VERSION 5.8 ;
BUSBITCHARS "[]" ;
DIVIDERCHAR "/" ;
UNITS
    DATABASE MICRONS 1000 ;
END UNITS

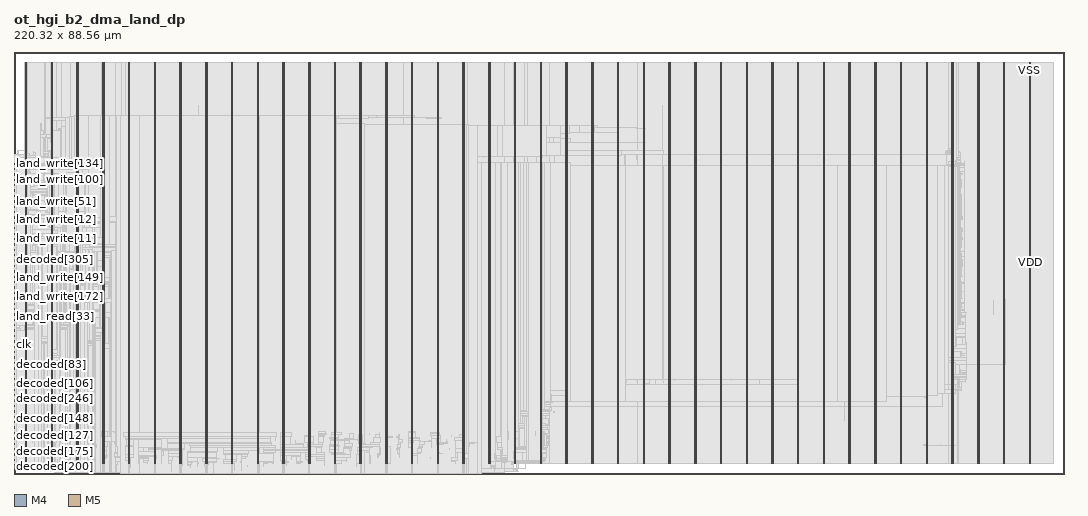
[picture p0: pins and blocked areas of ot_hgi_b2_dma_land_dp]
MACRO ot_hgi_b2_dma_land_dp
  FOREIGN ot_hgi_b2_dma_land_dp 0 0 ;
  CLASS BLOCK ;
  SIZE 220.32 BY 88.56 ;
  PIN clk
    DIRECTION INPUT ;
    USE SIGNAL ;
    PORT
      LAYER M4 ;
        RECT  0 27.216 0.084 27.24 ;
    END
  END clk
  PIN decoded[0]
    DIRECTION OUTPUT ;
    USE SIGNAL ;
    PORT
      LAYER M4 ;
        RECT  0 27.312 0.084 27.336 ;
    END
  END decoded[0]
  PIN decoded[100]
    DIRECTION OUTPUT ;
    USE SIGNAL ;
    PORT
      LAYER M4 ;
        RECT  0 18.48 0.084 18.504 ;
    END
  END decoded[100]
  PIN decoded[101]
    DIRECTION OUTPUT ;
    USE SIGNAL ;
    PORT
      LAYER M4 ;
        RECT  0 18.576 0.084 18.6 ;
    END
  END decoded[101]
  PIN decoded[102]
    DIRECTION OUTPUT ;
    USE SIGNAL ;
    PORT
      LAYER M4 ;
        RECT  0 18.672 0.084 18.696 ;
    END
  END decoded[102]
  PIN decoded[103]
    DIRECTION OUTPUT ;
    USE SIGNAL ;
    PORT
      LAYER M4 ;
        RECT  0 18.768 0.084 18.792 ;
    END
  END decoded[103]
  PIN decoded[104]
    DIRECTION OUTPUT ;
    USE SIGNAL ;
    PORT
      LAYER M4 ;
        RECT  0 18.864 0.084 18.888 ;
    END
  END decoded[104]
  PIN decoded[105]
    DIRECTION OUTPUT ;
    USE SIGNAL ;
    PORT
      LAYER M4 ;
        RECT  0 18.96 0.084 18.984 ;
    END
  END decoded[105]
  PIN decoded[106]
    DIRECTION OUTPUT ;
    USE SIGNAL ;
    PORT
      LAYER M4 ;
        RECT  0 19.056 0.084 19.08 ;
    END
  END decoded[106]
  PIN decoded[107]
    DIRECTION OUTPUT ;
    USE SIGNAL ;
    PORT
      LAYER M4 ;
        RECT  0 19.152 0.084 19.176 ;
    END
  END decoded[107]
  PIN decoded[108]
    DIRECTION OUTPUT ;
    USE SIGNAL ;
    PORT
      LAYER M4 ;
        RECT  0 19.248 0.084 19.272 ;
    END
  END decoded[108]
  PIN decoded[109]
    DIRECTION OUTPUT ;
    USE SIGNAL ;
    PORT
      LAYER M4 ;
        RECT  0 19.344 0.084 19.368 ;
    END
  END decoded[109]
  PIN decoded[10]
    DIRECTION OUTPUT ;
    USE SIGNAL ;
    PORT
      LAYER M4 ;
        RECT  0 28.272 0.084 28.296 ;
    END
  END decoded[10]
  PIN decoded[110]
    DIRECTION OUTPUT ;
    USE SIGNAL ;
    PORT
      LAYER M4 ;
        RECT  0 19.44 0.084 19.464 ;
    END
  END decoded[110]
  PIN decoded[111]
    DIRECTION OUTPUT ;
    USE SIGNAL ;
    PORT
      LAYER M4 ;
        RECT  0 19.536 0.084 19.56 ;
    END
  END decoded[111]
  PIN decoded[112]
    DIRECTION OUTPUT ;
    USE SIGNAL ;
    PORT
      LAYER M4 ;
        RECT  0 19.632 0.084 19.656 ;
    END
  END decoded[112]
  PIN decoded[113]
    DIRECTION OUTPUT ;
    USE SIGNAL ;
    PORT
      LAYER M4 ;
        RECT  0 19.728 0.084 19.752 ;
    END
  END decoded[113]
  PIN decoded[114]
    DIRECTION OUTPUT ;
    USE SIGNAL ;
    PORT
      LAYER M4 ;
        RECT  0 19.824 0.084 19.848 ;
    END
  END decoded[114]
  PIN decoded[115]
    DIRECTION OUTPUT ;
    USE SIGNAL ;
    PORT
      LAYER M4 ;
        RECT  0 19.92 0.084 19.944 ;
    END
  END decoded[115]
  PIN decoded[116]
    DIRECTION OUTPUT ;
    USE SIGNAL ;
    PORT
      LAYER M4 ;
        RECT  0 20.016 0.084 20.04 ;
    END
  END decoded[116]
  PIN decoded[117]
    DIRECTION OUTPUT ;
    USE SIGNAL ;
    PORT
      LAYER M4 ;
        RECT  0 20.112 0.084 20.136 ;
    END
  END decoded[117]
  PIN decoded[118]
    DIRECTION OUTPUT ;
    USE SIGNAL ;
    PORT
      LAYER M4 ;
        RECT  0 20.208 0.084 20.232 ;
    END
  END decoded[118]
  PIN decoded[119]
    DIRECTION OUTPUT ;
    USE SIGNAL ;
    PORT
      LAYER M4 ;
        RECT  0 20.304 0.084 20.328 ;
    END
  END decoded[119]
  PIN decoded[11]
    DIRECTION OUTPUT ;
    USE SIGNAL ;
    PORT
      LAYER M4 ;
        RECT  0 28.368 0.084 28.392 ;
    END
  END decoded[11]
  PIN decoded[120]
    DIRECTION OUTPUT ;
    USE SIGNAL ;
    PORT
      LAYER M4 ;
        RECT  0 20.4 0.084 20.424 ;
    END
  END decoded[120]
  PIN decoded[121]
    DIRECTION OUTPUT ;
    USE SIGNAL ;
    PORT
      LAYER M4 ;
        RECT  0 20.496 0.084 20.52 ;
    END
  END decoded[121]
  PIN decoded[122]
    DIRECTION OUTPUT ;
    USE SIGNAL ;
    PORT
      LAYER M4 ;
        RECT  0 20.592 0.084 20.616 ;
    END
  END decoded[122]
  PIN decoded[123]
    DIRECTION OUTPUT ;
    USE SIGNAL ;
    PORT
      LAYER M4 ;
        RECT  0 20.688 0.084 20.712 ;
    END
  END decoded[123]
  PIN decoded[124]
    DIRECTION OUTPUT ;
    USE SIGNAL ;
    PORT
      LAYER M4 ;
        RECT  0 20.784 0.084 20.808 ;
    END
  END decoded[124]
  PIN decoded[125]
    DIRECTION OUTPUT ;
    USE SIGNAL ;
    PORT
      LAYER M4 ;
        RECT  0 20.88 0.084 20.904 ;
    END
  END decoded[125]
  PIN decoded[126]
    DIRECTION OUTPUT ;
    USE SIGNAL ;
    PORT
      LAYER M4 ;
        RECT  0 20.976 0.084 21 ;
    END
  END decoded[126]
  PIN decoded[127]
    DIRECTION OUTPUT ;
    USE SIGNAL ;
    PORT
      LAYER M4 ;
        RECT  0 8.016 0.084 8.04 ;
    END
  END decoded[127]
  PIN decoded[128]
    DIRECTION OUTPUT ;
    USE SIGNAL ;
    PORT
      LAYER M4 ;
        RECT  0 8.112 0.084 8.136 ;
    END
  END decoded[128]
  PIN decoded[129]
    DIRECTION OUTPUT ;
    USE SIGNAL ;
    PORT
      LAYER M4 ;
        RECT  0 8.208 0.084 8.232 ;
    END
  END decoded[129]
  PIN decoded[12]
    DIRECTION OUTPUT ;
    USE SIGNAL ;
    PORT
      LAYER M4 ;
        RECT  0 28.464 0.084 28.488 ;
    END
  END decoded[12]
  PIN decoded[130]
    DIRECTION OUTPUT ;
    USE SIGNAL ;
    PORT
      LAYER M4 ;
        RECT  0 8.304 0.084 8.328 ;
    END
  END decoded[130]
  PIN decoded[131]
    DIRECTION OUTPUT ;
    USE SIGNAL ;
    PORT
      LAYER M4 ;
        RECT  0 8.4 0.084 8.424 ;
    END
  END decoded[131]
  PIN decoded[132]
    DIRECTION OUTPUT ;
    USE SIGNAL ;
    PORT
      LAYER M4 ;
        RECT  0 8.496 0.084 8.52 ;
    END
  END decoded[132]
  PIN decoded[133]
    DIRECTION OUTPUT ;
    USE SIGNAL ;
    PORT
      LAYER M4 ;
        RECT  0 8.592 0.084 8.616 ;
    END
  END decoded[133]
  PIN decoded[134]
    DIRECTION OUTPUT ;
    USE SIGNAL ;
    PORT
      LAYER M4 ;
        RECT  0 8.688 0.084 8.712 ;
    END
  END decoded[134]
  PIN decoded[135]
    DIRECTION OUTPUT ;
    USE SIGNAL ;
    PORT
      LAYER M4 ;
        RECT  0 8.784 0.084 8.808 ;
    END
  END decoded[135]
  PIN decoded[136]
    DIRECTION OUTPUT ;
    USE SIGNAL ;
    PORT
      LAYER M4 ;
        RECT  0 8.88 0.084 8.904 ;
    END
  END decoded[136]
  PIN decoded[137]
    DIRECTION OUTPUT ;
    USE SIGNAL ;
    PORT
      LAYER M4 ;
        RECT  0 8.976 0.084 9 ;
    END
  END decoded[137]
  PIN decoded[138]
    DIRECTION OUTPUT ;
    USE SIGNAL ;
    PORT
      LAYER M4 ;
        RECT  0 9.072 0.084 9.096 ;
    END
  END decoded[138]
  PIN decoded[139]
    DIRECTION OUTPUT ;
    USE SIGNAL ;
    PORT
      LAYER M4 ;
        RECT  0 9.168 0.084 9.192 ;
    END
  END decoded[139]
  PIN decoded[13]
    DIRECTION OUTPUT ;
    USE SIGNAL ;
    PORT
      LAYER M4 ;
        RECT  0 28.56 0.084 28.584 ;
    END
  END decoded[13]
  PIN decoded[140]
    DIRECTION OUTPUT ;
    USE SIGNAL ;
    PORT
      LAYER M4 ;
        RECT  0 9.264 0.084 9.288 ;
    END
  END decoded[140]
  PIN decoded[141]
    DIRECTION OUTPUT ;
    USE SIGNAL ;
    PORT
      LAYER M4 ;
        RECT  0 9.36 0.084 9.384 ;
    END
  END decoded[141]
  PIN decoded[142]
    DIRECTION OUTPUT ;
    USE SIGNAL ;
    PORT
      LAYER M4 ;
        RECT  0 9.456 0.084 9.48 ;
    END
  END decoded[142]
  PIN decoded[143]
    DIRECTION OUTPUT ;
    USE SIGNAL ;
    PORT
      LAYER M4 ;
        RECT  0 9.552 0.084 9.576 ;
    END
  END decoded[143]
  PIN decoded[144]
    DIRECTION OUTPUT ;
    USE SIGNAL ;
    PORT
      LAYER M4 ;
        RECT  0 9.648 0.084 9.672 ;
    END
  END decoded[144]
  PIN decoded[145]
    DIRECTION OUTPUT ;
    USE SIGNAL ;
    PORT
      LAYER M4 ;
        RECT  0 9.744 0.084 9.768 ;
    END
  END decoded[145]
  PIN decoded[146]
    DIRECTION OUTPUT ;
    USE SIGNAL ;
    PORT
      LAYER M4 ;
        RECT  0 9.84 0.084 9.864 ;
    END
  END decoded[146]
  PIN decoded[147]
    DIRECTION OUTPUT ;
    USE SIGNAL ;
    PORT
      LAYER M4 ;
        RECT  0 9.936 0.084 9.96 ;
    END
  END decoded[147]
  PIN decoded[148]
    DIRECTION OUTPUT ;
    USE SIGNAL ;
    PORT
      LAYER M4 ;
        RECT  0 10.032 0.084 10.056 ;
    END
  END decoded[148]
  PIN decoded[149]
    DIRECTION OUTPUT ;
    USE SIGNAL ;
    PORT
      LAYER M4 ;
        RECT  0 10.128 0.084 10.152 ;
    END
  END decoded[149]
  PIN decoded[14]
    DIRECTION OUTPUT ;
    USE SIGNAL ;
    PORT
      LAYER M4 ;
        RECT  0 28.656 0.084 28.68 ;
    END
  END decoded[14]
  PIN decoded[150]
    DIRECTION OUTPUT ;
    USE SIGNAL ;
    PORT
      LAYER M4 ;
        RECT  0 10.224 0.084 10.248 ;
    END
  END decoded[150]
  PIN decoded[151]
    DIRECTION OUTPUT ;
    USE SIGNAL ;
    PORT
      LAYER M4 ;
        RECT  0 10.32 0.084 10.344 ;
    END
  END decoded[151]
  PIN decoded[152]
    DIRECTION OUTPUT ;
    USE SIGNAL ;
    PORT
      LAYER M4 ;
        RECT  0 10.416 0.084 10.44 ;
    END
  END decoded[152]
  PIN decoded[153]
    DIRECTION OUTPUT ;
    USE SIGNAL ;
    PORT
      LAYER M4 ;
        RECT  0 10.512 0.084 10.536 ;
    END
  END decoded[153]
  PIN decoded[154]
    DIRECTION OUTPUT ;
    USE SIGNAL ;
    PORT
      LAYER M4 ;
        RECT  0 10.608 0.084 10.632 ;
    END
  END decoded[154]
  PIN decoded[155]
    DIRECTION OUTPUT ;
    USE SIGNAL ;
    PORT
      LAYER M4 ;
        RECT  0 10.704 0.084 10.728 ;
    END
  END decoded[155]
  PIN decoded[156]
    DIRECTION OUTPUT ;
    USE SIGNAL ;
    PORT
      LAYER M4 ;
        RECT  0 10.8 0.084 10.824 ;
    END
  END decoded[156]
  PIN decoded[157]
    DIRECTION OUTPUT ;
    USE SIGNAL ;
    PORT
      LAYER M4 ;
        RECT  0 10.896 0.084 10.92 ;
    END
  END decoded[157]
  PIN decoded[158]
    DIRECTION OUTPUT ;
    USE SIGNAL ;
    PORT
      LAYER M4 ;
        RECT  0 10.992 0.084 11.016 ;
    END
  END decoded[158]
  PIN decoded[159]
    DIRECTION OUTPUT ;
    USE SIGNAL ;
    PORT
      LAYER M4 ;
        RECT  0 4.944 0.084 4.968 ;
    END
  END decoded[159]
  PIN decoded[15]
    DIRECTION OUTPUT ;
    USE SIGNAL ;
    PORT
      LAYER M4 ;
        RECT  0 28.752 0.084 28.776 ;
    END
  END decoded[15]
  PIN decoded[160]
    DIRECTION OUTPUT ;
    USE SIGNAL ;
    PORT
      LAYER M4 ;
        RECT  0 5.04 0.084 5.064 ;
    END
  END decoded[160]
  PIN decoded[161]
    DIRECTION OUTPUT ;
    USE SIGNAL ;
    PORT
      LAYER M4 ;
        RECT  0 5.136 0.084 5.16 ;
    END
  END decoded[161]
  PIN decoded[162]
    DIRECTION OUTPUT ;
    USE SIGNAL ;
    PORT
      LAYER M4 ;
        RECT  0 5.232 0.084 5.256 ;
    END
  END decoded[162]
  PIN decoded[163]
    DIRECTION OUTPUT ;
    USE SIGNAL ;
    PORT
      LAYER M4 ;
        RECT  0 5.328 0.084 5.352 ;
    END
  END decoded[163]
  PIN decoded[164]
    DIRECTION OUTPUT ;
    USE SIGNAL ;
    PORT
      LAYER M4 ;
        RECT  0 5.424 0.084 5.448 ;
    END
  END decoded[164]
  PIN decoded[165]
    DIRECTION OUTPUT ;
    USE SIGNAL ;
    PORT
      LAYER M4 ;
        RECT  0 5.52 0.084 5.544 ;
    END
  END decoded[165]
  PIN decoded[166]
    DIRECTION OUTPUT ;
    USE SIGNAL ;
    PORT
      LAYER M4 ;
        RECT  0 5.616 0.084 5.64 ;
    END
  END decoded[166]
  PIN decoded[167]
    DIRECTION OUTPUT ;
    USE SIGNAL ;
    PORT
      LAYER M4 ;
        RECT  0 5.712 0.084 5.736 ;
    END
  END decoded[167]
  PIN decoded[168]
    DIRECTION OUTPUT ;
    USE SIGNAL ;
    PORT
      LAYER M4 ;
        RECT  0 5.808 0.084 5.832 ;
    END
  END decoded[168]
  PIN decoded[169]
    DIRECTION OUTPUT ;
    USE SIGNAL ;
    PORT
      LAYER M4 ;
        RECT  0 5.904 0.084 5.928 ;
    END
  END decoded[169]
  PIN decoded[16]
    DIRECTION OUTPUT ;
    USE SIGNAL ;
    PORT
      LAYER M4 ;
        RECT  0 28.848 0.084 28.872 ;
    END
  END decoded[16]
  PIN decoded[170]
    DIRECTION OUTPUT ;
    USE SIGNAL ;
    PORT
      LAYER M4 ;
        RECT  0 6 0.084 6.024 ;
    END
  END decoded[170]
  PIN decoded[171]
    DIRECTION OUTPUT ;
    USE SIGNAL ;
    PORT
      LAYER M4 ;
        RECT  0 6.096 0.084 6.12 ;
    END
  END decoded[171]
  PIN decoded[172]
    DIRECTION OUTPUT ;
    USE SIGNAL ;
    PORT
      LAYER M4 ;
        RECT  0 6.192 0.084 6.216 ;
    END
  END decoded[172]
  PIN decoded[173]
    DIRECTION OUTPUT ;
    USE SIGNAL ;
    PORT
      LAYER M4 ;
        RECT  0 6.288 0.084 6.312 ;
    END
  END decoded[173]
  PIN decoded[174]
    DIRECTION OUTPUT ;
    USE SIGNAL ;
    PORT
      LAYER M4 ;
        RECT  0 6.384 0.084 6.408 ;
    END
  END decoded[174]
  PIN decoded[175]
    DIRECTION OUTPUT ;
    USE SIGNAL ;
    PORT
      LAYER M4 ;
        RECT  0 6.48 0.084 6.504 ;
    END
  END decoded[175]
  PIN decoded[176]
    DIRECTION OUTPUT ;
    USE SIGNAL ;
    PORT
      LAYER M4 ;
        RECT  0 6.576 0.084 6.6 ;
    END
  END decoded[176]
  PIN decoded[177]
    DIRECTION OUTPUT ;
    USE SIGNAL ;
    PORT
      LAYER M4 ;
        RECT  0 6.672 0.084 6.696 ;
    END
  END decoded[177]
  PIN decoded[178]
    DIRECTION OUTPUT ;
    USE SIGNAL ;
    PORT
      LAYER M4 ;
        RECT  0 6.768 0.084 6.792 ;
    END
  END decoded[178]
  PIN decoded[179]
    DIRECTION OUTPUT ;
    USE SIGNAL ;
    PORT
      LAYER M4 ;
        RECT  0 6.864 0.084 6.888 ;
    END
  END decoded[179]
  PIN decoded[17]
    DIRECTION OUTPUT ;
    USE SIGNAL ;
    PORT
      LAYER M4 ;
        RECT  0 28.944 0.084 28.968 ;
    END
  END decoded[17]
  PIN decoded[180]
    DIRECTION OUTPUT ;
    USE SIGNAL ;
    PORT
      LAYER M4 ;
        RECT  0 6.96 0.084 6.984 ;
    END
  END decoded[180]
  PIN decoded[181]
    DIRECTION OUTPUT ;
    USE SIGNAL ;
    PORT
      LAYER M4 ;
        RECT  0 7.056 0.084 7.08 ;
    END
  END decoded[181]
  PIN decoded[182]
    DIRECTION OUTPUT ;
    USE SIGNAL ;
    PORT
      LAYER M4 ;
        RECT  0 7.152 0.084 7.176 ;
    END
  END decoded[182]
  PIN decoded[183]
    DIRECTION OUTPUT ;
    USE SIGNAL ;
    PORT
      LAYER M4 ;
        RECT  0 7.248 0.084 7.272 ;
    END
  END decoded[183]
  PIN decoded[184]
    DIRECTION OUTPUT ;
    USE SIGNAL ;
    PORT
      LAYER M4 ;
        RECT  0 7.344 0.084 7.368 ;
    END
  END decoded[184]
  PIN decoded[185]
    DIRECTION OUTPUT ;
    USE SIGNAL ;
    PORT
      LAYER M4 ;
        RECT  0 7.44 0.084 7.464 ;
    END
  END decoded[185]
  PIN decoded[186]
    DIRECTION OUTPUT ;
    USE SIGNAL ;
    PORT
      LAYER M4 ;
        RECT  0 7.536 0.084 7.56 ;
    END
  END decoded[186]
  PIN decoded[187]
    DIRECTION OUTPUT ;
    USE SIGNAL ;
    PORT
      LAYER M4 ;
        RECT  0 7.632 0.084 7.656 ;
    END
  END decoded[187]
  PIN decoded[188]
    DIRECTION OUTPUT ;
    USE SIGNAL ;
    PORT
      LAYER M4 ;
        RECT  0 7.728 0.084 7.752 ;
    END
  END decoded[188]
  PIN decoded[189]
    DIRECTION OUTPUT ;
    USE SIGNAL ;
    PORT
      LAYER M4 ;
        RECT  0 7.824 0.084 7.848 ;
    END
  END decoded[189]
  PIN decoded[18]
    DIRECTION OUTPUT ;
    USE SIGNAL ;
    PORT
      LAYER M4 ;
        RECT  0 29.04 0.084 29.064 ;
    END
  END decoded[18]
  PIN decoded[190]
    DIRECTION OUTPUT ;
    USE SIGNAL ;
    PORT
      LAYER M4 ;
        RECT  0 7.92 0.084 7.944 ;
    END
  END decoded[190]
  PIN decoded[191]
    DIRECTION OUTPUT ;
    USE SIGNAL ;
    PORT
      LAYER M4 ;
        RECT  0 1.872 0.084 1.896 ;
    END
  END decoded[191]
  PIN decoded[192]
    DIRECTION OUTPUT ;
    USE SIGNAL ;
    PORT
      LAYER M4 ;
        RECT  0 1.968 0.084 1.992 ;
    END
  END decoded[192]
  PIN decoded[193]
    DIRECTION OUTPUT ;
    USE SIGNAL ;
    PORT
      LAYER M4 ;
        RECT  0 2.064 0.084 2.088 ;
    END
  END decoded[193]
  PIN decoded[194]
    DIRECTION OUTPUT ;
    USE SIGNAL ;
    PORT
      LAYER M4 ;
        RECT  0 2.16 0.084 2.184 ;
    END
  END decoded[194]
  PIN decoded[195]
    DIRECTION OUTPUT ;
    USE SIGNAL ;
    PORT
      LAYER M4 ;
        RECT  0 2.256 0.084 2.28 ;
    END
  END decoded[195]
  PIN decoded[196]
    DIRECTION OUTPUT ;
    USE SIGNAL ;
    PORT
      LAYER M4 ;
        RECT  0 2.352 0.084 2.376 ;
    END
  END decoded[196]
  PIN decoded[197]
    DIRECTION OUTPUT ;
    USE SIGNAL ;
    PORT
      LAYER M4 ;
        RECT  0 2.448 0.084 2.472 ;
    END
  END decoded[197]
  PIN decoded[198]
    DIRECTION OUTPUT ;
    USE SIGNAL ;
    PORT
      LAYER M4 ;
        RECT  0 2.544 0.084 2.568 ;
    END
  END decoded[198]
  PIN decoded[199]
    DIRECTION OUTPUT ;
    USE SIGNAL ;
    PORT
      LAYER M4 ;
        RECT  0 2.64 0.084 2.664 ;
    END
  END decoded[199]
  PIN decoded[19]
    DIRECTION OUTPUT ;
    USE SIGNAL ;
    PORT
      LAYER M4 ;
        RECT  0 29.136 0.084 29.16 ;
    END
  END decoded[19]
  PIN decoded[1]
    DIRECTION OUTPUT ;
    USE SIGNAL ;
    PORT
      LAYER M4 ;
        RECT  0 27.408 0.084 27.432 ;
    END
  END decoded[1]
  PIN decoded[200]
    DIRECTION OUTPUT ;
    USE SIGNAL ;
    PORT
      LAYER M4 ;
        RECT  0 2.736 0.084 2.76 ;
    END
  END decoded[200]
  PIN decoded[201]
    DIRECTION OUTPUT ;
    USE SIGNAL ;
    PORT
      LAYER M4 ;
        RECT  0 2.832 0.084 2.856 ;
    END
  END decoded[201]
  PIN decoded[202]
    DIRECTION OUTPUT ;
    USE SIGNAL ;
    PORT
      LAYER M4 ;
        RECT  0 2.928 0.084 2.952 ;
    END
  END decoded[202]
  PIN decoded[203]
    DIRECTION OUTPUT ;
    USE SIGNAL ;
    PORT
      LAYER M4 ;
        RECT  0 3.024 0.084 3.048 ;
    END
  END decoded[203]
  PIN decoded[204]
    DIRECTION OUTPUT ;
    USE SIGNAL ;
    PORT
      LAYER M4 ;
        RECT  0 3.12 0.084 3.144 ;
    END
  END decoded[204]
  PIN decoded[205]
    DIRECTION OUTPUT ;
    USE SIGNAL ;
    PORT
      LAYER M4 ;
        RECT  0 3.216 0.084 3.24 ;
    END
  END decoded[205]
  PIN decoded[206]
    DIRECTION OUTPUT ;
    USE SIGNAL ;
    PORT
      LAYER M4 ;
        RECT  0 3.312 0.084 3.336 ;
    END
  END decoded[206]
  PIN decoded[207]
    DIRECTION OUTPUT ;
    USE SIGNAL ;
    PORT
      LAYER M4 ;
        RECT  0 3.408 0.084 3.432 ;
    END
  END decoded[207]
  PIN decoded[208]
    DIRECTION OUTPUT ;
    USE SIGNAL ;
    PORT
      LAYER M4 ;
        RECT  0 3.504 0.084 3.528 ;
    END
  END decoded[208]
  PIN decoded[209]
    DIRECTION OUTPUT ;
    USE SIGNAL ;
    PORT
      LAYER M4 ;
        RECT  0 3.6 0.084 3.624 ;
    END
  END decoded[209]
  PIN decoded[20]
    DIRECTION OUTPUT ;
    USE SIGNAL ;
    PORT
      LAYER M4 ;
        RECT  0 29.232 0.084 29.256 ;
    END
  END decoded[20]
  PIN decoded[210]
    DIRECTION OUTPUT ;
    USE SIGNAL ;
    PORT
      LAYER M4 ;
        RECT  0 3.696 0.084 3.72 ;
    END
  END decoded[210]
  PIN decoded[211]
    DIRECTION OUTPUT ;
    USE SIGNAL ;
    PORT
      LAYER M4 ;
        RECT  0 3.792 0.084 3.816 ;
    END
  END decoded[211]
  PIN decoded[212]
    DIRECTION OUTPUT ;
    USE SIGNAL ;
    PORT
      LAYER M4 ;
        RECT  0 3.888 0.084 3.912 ;
    END
  END decoded[212]
  PIN decoded[213]
    DIRECTION OUTPUT ;
    USE SIGNAL ;
    PORT
      LAYER M4 ;
        RECT  0 3.984 0.084 4.008 ;
    END
  END decoded[213]
  PIN decoded[214]
    DIRECTION OUTPUT ;
    USE SIGNAL ;
    PORT
      LAYER M4 ;
        RECT  0 4.08 0.084 4.104 ;
    END
  END decoded[214]
  PIN decoded[215]
    DIRECTION OUTPUT ;
    USE SIGNAL ;
    PORT
      LAYER M4 ;
        RECT  0 4.176 0.084 4.2 ;
    END
  END decoded[215]
  PIN decoded[216]
    DIRECTION OUTPUT ;
    USE SIGNAL ;
    PORT
      LAYER M4 ;
        RECT  0 4.272 0.084 4.296 ;
    END
  END decoded[216]
  PIN decoded[217]
    DIRECTION OUTPUT ;
    USE SIGNAL ;
    PORT
      LAYER M4 ;
        RECT  0 4.368 0.084 4.392 ;
    END
  END decoded[217]
  PIN decoded[218]
    DIRECTION OUTPUT ;
    USE SIGNAL ;
    PORT
      LAYER M4 ;
        RECT  0 4.464 0.084 4.488 ;
    END
  END decoded[218]
  PIN decoded[219]
    DIRECTION OUTPUT ;
    USE SIGNAL ;
    PORT
      LAYER M4 ;
        RECT  0 4.56 0.084 4.584 ;
    END
  END decoded[219]
  PIN decoded[21]
    DIRECTION OUTPUT ;
    USE SIGNAL ;
    PORT
      LAYER M4 ;
        RECT  0 29.328 0.084 29.352 ;
    END
  END decoded[21]
  PIN decoded[220]
    DIRECTION OUTPUT ;
    USE SIGNAL ;
    PORT
      LAYER M4 ;
        RECT  0 4.656 0.084 4.68 ;
    END
  END decoded[220]
  PIN decoded[221]
    DIRECTION OUTPUT ;
    USE SIGNAL ;
    PORT
      LAYER M4 ;
        RECT  0 4.752 0.084 4.776 ;
    END
  END decoded[221]
  PIN decoded[222]
    DIRECTION OUTPUT ;
    USE SIGNAL ;
    PORT
      LAYER M4 ;
        RECT  0 4.848 0.084 4.872 ;
    END
  END decoded[222]
  PIN decoded[223]
    DIRECTION OUTPUT ;
    USE SIGNAL ;
    PORT
      LAYER M4 ;
        RECT  0 11.856 0.084 11.88 ;
    END
  END decoded[223]
  PIN decoded[224]
    DIRECTION OUTPUT ;
    USE SIGNAL ;
    PORT
      LAYER M4 ;
        RECT  0 11.952 0.084 11.976 ;
    END
  END decoded[224]
  PIN decoded[225]
    DIRECTION OUTPUT ;
    USE SIGNAL ;
    PORT
      LAYER M4 ;
        RECT  0 12.048 0.084 12.072 ;
    END
  END decoded[225]
  PIN decoded[226]
    DIRECTION OUTPUT ;
    USE SIGNAL ;
    PORT
      LAYER M4 ;
        RECT  0 12.144 0.084 12.168 ;
    END
  END decoded[226]
  PIN decoded[227]
    DIRECTION OUTPUT ;
    USE SIGNAL ;
    PORT
      LAYER M4 ;
        RECT  0 12.24 0.084 12.264 ;
    END
  END decoded[227]
  PIN decoded[228]
    DIRECTION OUTPUT ;
    USE SIGNAL ;
    PORT
      LAYER M4 ;
        RECT  0 12.336 0.084 12.36 ;
    END
  END decoded[228]
  PIN decoded[229]
    DIRECTION OUTPUT ;
    USE SIGNAL ;
    PORT
      LAYER M4 ;
        RECT  0 12.432 0.084 12.456 ;
    END
  END decoded[229]
  PIN decoded[22]
    DIRECTION OUTPUT ;
    USE SIGNAL ;
    PORT
      LAYER M4 ;
        RECT  0 29.424 0.084 29.448 ;
    END
  END decoded[22]
  PIN decoded[230]
    DIRECTION OUTPUT ;
    USE SIGNAL ;
    PORT
      LAYER M4 ;
        RECT  0 12.528 0.084 12.552 ;
    END
  END decoded[230]
  PIN decoded[231]
    DIRECTION OUTPUT ;
    USE SIGNAL ;
    PORT
      LAYER M4 ;
        RECT  0 12.624 0.084 12.648 ;
    END
  END decoded[231]
  PIN decoded[232]
    DIRECTION OUTPUT ;
    USE SIGNAL ;
    PORT
      LAYER M4 ;
        RECT  0 12.72 0.084 12.744 ;
    END
  END decoded[232]
  PIN decoded[233]
    DIRECTION OUTPUT ;
    USE SIGNAL ;
    PORT
      LAYER M4 ;
        RECT  0 12.816 0.084 12.84 ;
    END
  END decoded[233]
  PIN decoded[234]
    DIRECTION OUTPUT ;
    USE SIGNAL ;
    PORT
      LAYER M4 ;
        RECT  0 12.912 0.084 12.936 ;
    END
  END decoded[234]
  PIN decoded[235]
    DIRECTION OUTPUT ;
    USE SIGNAL ;
    PORT
      LAYER M4 ;
        RECT  0 13.008 0.084 13.032 ;
    END
  END decoded[235]
  PIN decoded[236]
    DIRECTION OUTPUT ;
    USE SIGNAL ;
    PORT
      LAYER M4 ;
        RECT  0 13.104 0.084 13.128 ;
    END
  END decoded[236]
  PIN decoded[237]
    DIRECTION OUTPUT ;
    USE SIGNAL ;
    PORT
      LAYER M4 ;
        RECT  0 13.2 0.084 13.224 ;
    END
  END decoded[237]
  PIN decoded[238]
    DIRECTION OUTPUT ;
    USE SIGNAL ;
    PORT
      LAYER M4 ;
        RECT  0 13.296 0.084 13.32 ;
    END
  END decoded[238]
  PIN decoded[239]
    DIRECTION OUTPUT ;
    USE SIGNAL ;
    PORT
      LAYER M4 ;
        RECT  0 13.392 0.084 13.416 ;
    END
  END decoded[239]
  PIN decoded[23]
    DIRECTION OUTPUT ;
    USE SIGNAL ;
    PORT
      LAYER M4 ;
        RECT  0 29.52 0.084 29.544 ;
    END
  END decoded[23]
  PIN decoded[240]
    DIRECTION OUTPUT ;
    USE SIGNAL ;
    PORT
      LAYER M4 ;
        RECT  0 13.488 0.084 13.512 ;
    END
  END decoded[240]
  PIN decoded[241]
    DIRECTION OUTPUT ;
    USE SIGNAL ;
    PORT
      LAYER M4 ;
        RECT  0 13.584 0.084 13.608 ;
    END
  END decoded[241]
  PIN decoded[242]
    DIRECTION OUTPUT ;
    USE SIGNAL ;
    PORT
      LAYER M4 ;
        RECT  0 13.68 0.084 13.704 ;
    END
  END decoded[242]
  PIN decoded[243]
    DIRECTION OUTPUT ;
    USE SIGNAL ;
    PORT
      LAYER M4 ;
        RECT  0 13.776 0.084 13.8 ;
    END
  END decoded[243]
  PIN decoded[244]
    DIRECTION OUTPUT ;
    USE SIGNAL ;
    PORT
      LAYER M4 ;
        RECT  0 13.872 0.084 13.896 ;
    END
  END decoded[244]
  PIN decoded[245]
    DIRECTION OUTPUT ;
    USE SIGNAL ;
    PORT
      LAYER M4 ;
        RECT  0 13.968 0.084 13.992 ;
    END
  END decoded[245]
  PIN decoded[246]
    DIRECTION OUTPUT ;
    USE SIGNAL ;
    PORT
      LAYER M4 ;
        RECT  0 14.064 0.084 14.088 ;
    END
  END decoded[246]
  PIN decoded[247]
    DIRECTION OUTPUT ;
    USE SIGNAL ;
    PORT
      LAYER M4 ;
        RECT  0 14.16 0.084 14.184 ;
    END
  END decoded[247]
  PIN decoded[248]
    DIRECTION OUTPUT ;
    USE SIGNAL ;
    PORT
      LAYER M4 ;
        RECT  0 14.256 0.084 14.28 ;
    END
  END decoded[248]
  PIN decoded[249]
    DIRECTION OUTPUT ;
    USE SIGNAL ;
    PORT
      LAYER M4 ;
        RECT  0 14.352 0.084 14.376 ;
    END
  END decoded[249]
  PIN decoded[24]
    DIRECTION OUTPUT ;
    USE SIGNAL ;
    PORT
      LAYER M4 ;
        RECT  0 29.616 0.084 29.64 ;
    END
  END decoded[24]
  PIN decoded[250]
    DIRECTION OUTPUT ;
    USE SIGNAL ;
    PORT
      LAYER M4 ;
        RECT  0 14.448 0.084 14.472 ;
    END
  END decoded[250]
  PIN decoded[251]
    DIRECTION OUTPUT ;
    USE SIGNAL ;
    PORT
      LAYER M4 ;
        RECT  0 14.544 0.084 14.568 ;
    END
  END decoded[251]
  PIN decoded[252]
    DIRECTION OUTPUT ;
    USE SIGNAL ;
    PORT
      LAYER M4 ;
        RECT  0 14.64 0.084 14.664 ;
    END
  END decoded[252]
  PIN decoded[253]
    DIRECTION OUTPUT ;
    USE SIGNAL ;
    PORT
      LAYER M4 ;
        RECT  0 14.736 0.084 14.76 ;
    END
  END decoded[253]
  PIN decoded[254]
    DIRECTION OUTPUT ;
    USE SIGNAL ;
    PORT
      LAYER M4 ;
        RECT  0 14.832 0.084 14.856 ;
    END
  END decoded[254]
  PIN decoded[255]
    DIRECTION OUTPUT ;
    USE SIGNAL ;
    PORT
      LAYER M4 ;
        RECT  0 14.928 0.084 14.952 ;
    END
  END decoded[255]
  PIN decoded[256]
    DIRECTION OUTPUT ;
    USE SIGNAL ;
    PORT
      LAYER M4 ;
        RECT  0 15.024 0.084 15.048 ;
    END
  END decoded[256]
  PIN decoded[257]
    DIRECTION OUTPUT ;
    USE SIGNAL ;
    PORT
      LAYER M4 ;
        RECT  0 15.12 0.084 15.144 ;
    END
  END decoded[257]
  PIN decoded[258]
    DIRECTION OUTPUT ;
    USE SIGNAL ;
    PORT
      LAYER M4 ;
        RECT  0 15.216 0.084 15.24 ;
    END
  END decoded[258]
  PIN decoded[259]
    DIRECTION OUTPUT ;
    USE SIGNAL ;
    PORT
      LAYER M4 ;
        RECT  0 15.312 0.084 15.336 ;
    END
  END decoded[259]
  PIN decoded[25]
    DIRECTION OUTPUT ;
    USE SIGNAL ;
    PORT
      LAYER M4 ;
        RECT  0 29.712 0.084 29.736 ;
    END
  END decoded[25]
  PIN decoded[260]
    DIRECTION OUTPUT ;
    USE SIGNAL ;
    PORT
      LAYER M4 ;
        RECT  0 15.408 0.084 15.432 ;
    END
  END decoded[260]
  PIN decoded[261]
    DIRECTION OUTPUT ;
    USE SIGNAL ;
    PORT
      LAYER M4 ;
        RECT  0 15.504 0.084 15.528 ;
    END
  END decoded[261]
  PIN decoded[262]
    DIRECTION OUTPUT ;
    USE SIGNAL ;
    PORT
      LAYER M4 ;
        RECT  0 15.6 0.084 15.624 ;
    END
  END decoded[262]
  PIN decoded[263]
    DIRECTION OUTPUT ;
    USE SIGNAL ;
    PORT
      LAYER M4 ;
        RECT  0 15.696 0.084 15.72 ;
    END
  END decoded[263]
  PIN decoded[264]
    DIRECTION OUTPUT ;
    USE SIGNAL ;
    PORT
      LAYER M4 ;
        RECT  0 15.792 0.084 15.816 ;
    END
  END decoded[264]
  PIN decoded[265]
    DIRECTION OUTPUT ;
    USE SIGNAL ;
    PORT
      LAYER M4 ;
        RECT  0 15.888 0.084 15.912 ;
    END
  END decoded[265]
  PIN decoded[266]
    DIRECTION OUTPUT ;
    USE SIGNAL ;
    PORT
      LAYER M4 ;
        RECT  0 15.984 0.084 16.008 ;
    END
  END decoded[266]
  PIN decoded[267]
    DIRECTION OUTPUT ;
    USE SIGNAL ;
    PORT
      LAYER M4 ;
        RECT  0 16.08 0.084 16.104 ;
    END
  END decoded[267]
  PIN decoded[268]
    DIRECTION OUTPUT ;
    USE SIGNAL ;
    PORT
      LAYER M4 ;
        RECT  0 16.176 0.084 16.2 ;
    END
  END decoded[268]
  PIN decoded[269]
    DIRECTION OUTPUT ;
    USE SIGNAL ;
    PORT
      LAYER M4 ;
        RECT  0 16.272 0.084 16.296 ;
    END
  END decoded[269]
  PIN decoded[26]
    DIRECTION OUTPUT ;
    USE SIGNAL ;
    PORT
      LAYER M4 ;
        RECT  0 29.808 0.084 29.832 ;
    END
  END decoded[26]
  PIN decoded[270]
    DIRECTION OUTPUT ;
    USE SIGNAL ;
    PORT
      LAYER M4 ;
        RECT  0 16.368 0.084 16.392 ;
    END
  END decoded[270]
  PIN decoded[271]
    DIRECTION OUTPUT ;
    USE SIGNAL ;
    PORT
      LAYER M4 ;
        RECT  0 16.464 0.084 16.488 ;
    END
  END decoded[271]
  PIN decoded[272]
    DIRECTION OUTPUT ;
    USE SIGNAL ;
    PORT
      LAYER M4 ;
        RECT  0 16.56 0.084 16.584 ;
    END
  END decoded[272]
  PIN decoded[273]
    DIRECTION OUTPUT ;
    USE SIGNAL ;
    PORT
      LAYER M4 ;
        RECT  0 16.656 0.084 16.68 ;
    END
  END decoded[273]
  PIN decoded[274]
    DIRECTION OUTPUT ;
    USE SIGNAL ;
    PORT
      LAYER M4 ;
        RECT  0 16.752 0.084 16.776 ;
    END
  END decoded[274]
  PIN decoded[275]
    DIRECTION OUTPUT ;
    USE SIGNAL ;
    PORT
      LAYER M4 ;
        RECT  0 16.848 0.084 16.872 ;
    END
  END decoded[275]
  PIN decoded[276]
    DIRECTION OUTPUT ;
    USE SIGNAL ;
    PORT
      LAYER M4 ;
        RECT  0 16.944 0.084 16.968 ;
    END
  END decoded[276]
  PIN decoded[277]
    DIRECTION OUTPUT ;
    USE SIGNAL ;
    PORT
      LAYER M4 ;
        RECT  0 17.04 0.084 17.064 ;
    END
  END decoded[277]
  PIN decoded[278]
    DIRECTION OUTPUT ;
    USE SIGNAL ;
    PORT
      LAYER M4 ;
        RECT  0 17.136 0.084 17.16 ;
    END
  END decoded[278]
  PIN decoded[279]
    DIRECTION OUTPUT ;
    USE SIGNAL ;
    PORT
      LAYER M4 ;
        RECT  0 17.232 0.084 17.256 ;
    END
  END decoded[279]
  PIN decoded[27]
    DIRECTION OUTPUT ;
    USE SIGNAL ;
    PORT
      LAYER M4 ;
        RECT  0 29.904 0.084 29.928 ;
    END
  END decoded[27]
  PIN decoded[280]
    DIRECTION OUTPUT ;
    USE SIGNAL ;
    PORT
      LAYER M4 ;
        RECT  0 17.328 0.084 17.352 ;
    END
  END decoded[280]
  PIN decoded[281]
    DIRECTION OUTPUT ;
    USE SIGNAL ;
    PORT
      LAYER M4 ;
        RECT  0 17.424 0.084 17.448 ;
    END
  END decoded[281]
  PIN decoded[282]
    DIRECTION OUTPUT ;
    USE SIGNAL ;
    PORT
      LAYER M4 ;
        RECT  0 17.52 0.084 17.544 ;
    END
  END decoded[282]
  PIN decoded[283]
    DIRECTION OUTPUT ;
    USE SIGNAL ;
    PORT
      LAYER M4 ;
        RECT  0 17.616 0.084 17.64 ;
    END
  END decoded[283]
  PIN decoded[284]
    DIRECTION OUTPUT ;
    USE SIGNAL ;
    PORT
      LAYER M4 ;
        RECT  0 17.712 0.084 17.736 ;
    END
  END decoded[284]
  PIN decoded[285]
    DIRECTION OUTPUT ;
    USE SIGNAL ;
    PORT
      LAYER M4 ;
        RECT  0 17.808 0.084 17.832 ;
    END
  END decoded[285]
  PIN decoded[286]
    DIRECTION OUTPUT ;
    USE SIGNAL ;
    PORT
      LAYER M4 ;
        RECT  0 17.904 0.084 17.928 ;
    END
  END decoded[286]
  PIN decoded[287]
    DIRECTION OUTPUT ;
    USE SIGNAL ;
    PORT
      LAYER M4 ;
        RECT  0 43.344 0.084 43.368 ;
    END
  END decoded[287]
  PIN decoded[288]
    DIRECTION OUTPUT ;
    USE SIGNAL ;
    PORT
      LAYER M4 ;
        RECT  0 43.44 0.084 43.464 ;
    END
  END decoded[288]
  PIN decoded[289]
    DIRECTION OUTPUT ;
    USE SIGNAL ;
    PORT
      LAYER M4 ;
        RECT  0 43.536 0.084 43.56 ;
    END
  END decoded[289]
  PIN decoded[28]
    DIRECTION OUTPUT ;
    USE SIGNAL ;
    PORT
      LAYER M4 ;
        RECT  0 30 0.084 30.024 ;
    END
  END decoded[28]
  PIN decoded[290]
    DIRECTION OUTPUT ;
    USE SIGNAL ;
    PORT
      LAYER M4 ;
        RECT  0 43.632 0.084 43.656 ;
    END
  END decoded[290]
  PIN decoded[291]
    DIRECTION OUTPUT ;
    USE SIGNAL ;
    PORT
      LAYER M4 ;
        RECT  0 43.728 0.084 43.752 ;
    END
  END decoded[291]
  PIN decoded[292]
    DIRECTION OUTPUT ;
    USE SIGNAL ;
    PORT
      LAYER M4 ;
        RECT  0 43.824 0.084 43.848 ;
    END
  END decoded[292]
  PIN decoded[293]
    DIRECTION OUTPUT ;
    USE SIGNAL ;
    PORT
      LAYER M4 ;
        RECT  0 43.92 0.084 43.944 ;
    END
  END decoded[293]
  PIN decoded[294]
    DIRECTION OUTPUT ;
    USE SIGNAL ;
    PORT
      LAYER M4 ;
        RECT  0 44.016 0.084 44.04 ;
    END
  END decoded[294]
  PIN decoded[295]
    DIRECTION OUTPUT ;
    USE SIGNAL ;
    PORT
      LAYER M4 ;
        RECT  0 44.112 0.084 44.136 ;
    END
  END decoded[295]
  PIN decoded[296]
    DIRECTION OUTPUT ;
    USE SIGNAL ;
    PORT
      LAYER M4 ;
        RECT  0 44.208 0.084 44.232 ;
    END
  END decoded[296]
  PIN decoded[297]
    DIRECTION OUTPUT ;
    USE SIGNAL ;
    PORT
      LAYER M4 ;
        RECT  0 44.304 0.084 44.328 ;
    END
  END decoded[297]
  PIN decoded[298]
    DIRECTION OUTPUT ;
    USE SIGNAL ;
    PORT
      LAYER M4 ;
        RECT  0 44.4 0.084 44.424 ;
    END
  END decoded[298]
  PIN decoded[299]
    DIRECTION OUTPUT ;
    USE SIGNAL ;
    PORT
      LAYER M4 ;
        RECT  0 44.496 0.084 44.52 ;
    END
  END decoded[299]
  PIN decoded[29]
    DIRECTION OUTPUT ;
    USE SIGNAL ;
    PORT
      LAYER M4 ;
        RECT  0 30.096 0.084 30.12 ;
    END
  END decoded[29]
  PIN decoded[2]
    DIRECTION OUTPUT ;
    USE SIGNAL ;
    PORT
      LAYER M4 ;
        RECT  0 27.504 0.084 27.528 ;
    END
  END decoded[2]
  PIN decoded[300]
    DIRECTION OUTPUT ;
    USE SIGNAL ;
    PORT
      LAYER M4 ;
        RECT  0 44.592 0.084 44.616 ;
    END
  END decoded[300]
  PIN decoded[301]
    DIRECTION OUTPUT ;
    USE SIGNAL ;
    PORT
      LAYER M4 ;
        RECT  0 44.688 0.084 44.712 ;
    END
  END decoded[301]
  PIN decoded[302]
    DIRECTION OUTPUT ;
    USE SIGNAL ;
    PORT
      LAYER M4 ;
        RECT  0 44.784 0.084 44.808 ;
    END
  END decoded[302]
  PIN decoded[303]
    DIRECTION OUTPUT ;
    USE SIGNAL ;
    PORT
      LAYER M4 ;
        RECT  0 44.88 0.084 44.904 ;
    END
  END decoded[303]
  PIN decoded[304]
    DIRECTION OUTPUT ;
    USE SIGNAL ;
    PORT
      LAYER M4 ;
        RECT  0 44.976 0.084 45 ;
    END
  END decoded[304]
  PIN decoded[305]
    DIRECTION OUTPUT ;
    USE SIGNAL ;
    PORT
      LAYER M4 ;
        RECT  0 45.072 0.084 45.096 ;
    END
  END decoded[305]
  PIN decoded[306]
    DIRECTION OUTPUT ;
    USE SIGNAL ;
    PORT
      LAYER M4 ;
        RECT  0 45.168 0.084 45.192 ;
    END
  END decoded[306]
  PIN decoded[30]
    DIRECTION OUTPUT ;
    USE SIGNAL ;
    PORT
      LAYER M4 ;
        RECT  0 30.192 0.084 30.216 ;
    END
  END decoded[30]
  PIN decoded[31]
    DIRECTION OUTPUT ;
    USE SIGNAL ;
    PORT
      LAYER M4 ;
        RECT  0 24.144 0.084 24.168 ;
    END
  END decoded[31]
  PIN decoded[32]
    DIRECTION OUTPUT ;
    USE SIGNAL ;
    PORT
      LAYER M4 ;
        RECT  0 24.24 0.084 24.264 ;
    END
  END decoded[32]
  PIN decoded[33]
    DIRECTION OUTPUT ;
    USE SIGNAL ;
    PORT
      LAYER M4 ;
        RECT  0 24.336 0.084 24.36 ;
    END
  END decoded[33]
  PIN decoded[34]
    DIRECTION OUTPUT ;
    USE SIGNAL ;
    PORT
      LAYER M4 ;
        RECT  0 24.432 0.084 24.456 ;
    END
  END decoded[34]
  PIN decoded[35]
    DIRECTION OUTPUT ;
    USE SIGNAL ;
    PORT
      LAYER M4 ;
        RECT  0 24.528 0.084 24.552 ;
    END
  END decoded[35]
  PIN decoded[36]
    DIRECTION OUTPUT ;
    USE SIGNAL ;
    PORT
      LAYER M4 ;
        RECT  0 24.624 0.084 24.648 ;
    END
  END decoded[36]
  PIN decoded[37]
    DIRECTION OUTPUT ;
    USE SIGNAL ;
    PORT
      LAYER M4 ;
        RECT  0 24.72 0.084 24.744 ;
    END
  END decoded[37]
  PIN decoded[38]
    DIRECTION OUTPUT ;
    USE SIGNAL ;
    PORT
      LAYER M4 ;
        RECT  0 24.816 0.084 24.84 ;
    END
  END decoded[38]
  PIN decoded[39]
    DIRECTION OUTPUT ;
    USE SIGNAL ;
    PORT
      LAYER M4 ;
        RECT  0 24.912 0.084 24.936 ;
    END
  END decoded[39]
  PIN decoded[3]
    DIRECTION OUTPUT ;
    USE SIGNAL ;
    PORT
      LAYER M4 ;
        RECT  0 27.6 0.084 27.624 ;
    END
  END decoded[3]
  PIN decoded[40]
    DIRECTION OUTPUT ;
    USE SIGNAL ;
    PORT
      LAYER M4 ;
        RECT  0 25.008 0.084 25.032 ;
    END
  END decoded[40]
  PIN decoded[41]
    DIRECTION OUTPUT ;
    USE SIGNAL ;
    PORT
      LAYER M4 ;
        RECT  0 25.104 0.084 25.128 ;
    END
  END decoded[41]
  PIN decoded[42]
    DIRECTION OUTPUT ;
    USE SIGNAL ;
    PORT
      LAYER M4 ;
        RECT  0 25.2 0.084 25.224 ;
    END
  END decoded[42]
  PIN decoded[43]
    DIRECTION OUTPUT ;
    USE SIGNAL ;
    PORT
      LAYER M4 ;
        RECT  0 25.296 0.084 25.32 ;
    END
  END decoded[43]
  PIN decoded[44]
    DIRECTION OUTPUT ;
    USE SIGNAL ;
    PORT
      LAYER M4 ;
        RECT  0 25.392 0.084 25.416 ;
    END
  END decoded[44]
  PIN decoded[45]
    DIRECTION OUTPUT ;
    USE SIGNAL ;
    PORT
      LAYER M4 ;
        RECT  0 25.488 0.084 25.512 ;
    END
  END decoded[45]
  PIN decoded[46]
    DIRECTION OUTPUT ;
    USE SIGNAL ;
    PORT
      LAYER M4 ;
        RECT  0 25.584 0.084 25.608 ;
    END
  END decoded[46]
  PIN decoded[47]
    DIRECTION OUTPUT ;
    USE SIGNAL ;
    PORT
      LAYER M4 ;
        RECT  0 25.68 0.084 25.704 ;
    END
  END decoded[47]
  PIN decoded[48]
    DIRECTION OUTPUT ;
    USE SIGNAL ;
    PORT
      LAYER M4 ;
        RECT  0 25.776 0.084 25.8 ;
    END
  END decoded[48]
  PIN decoded[49]
    DIRECTION OUTPUT ;
    USE SIGNAL ;
    PORT
      LAYER M4 ;
        RECT  0 25.872 0.084 25.896 ;
    END
  END decoded[49]
  PIN decoded[4]
    DIRECTION OUTPUT ;
    USE SIGNAL ;
    PORT
      LAYER M4 ;
        RECT  0 27.696 0.084 27.72 ;
    END
  END decoded[4]
  PIN decoded[50]
    DIRECTION OUTPUT ;
    USE SIGNAL ;
    PORT
      LAYER M4 ;
        RECT  0 25.968 0.084 25.992 ;
    END
  END decoded[50]
  PIN decoded[51]
    DIRECTION OUTPUT ;
    USE SIGNAL ;
    PORT
      LAYER M4 ;
        RECT  0 26.064 0.084 26.088 ;
    END
  END decoded[51]
  PIN decoded[52]
    DIRECTION OUTPUT ;
    USE SIGNAL ;
    PORT
      LAYER M4 ;
        RECT  0 26.16 0.084 26.184 ;
    END
  END decoded[52]
  PIN decoded[53]
    DIRECTION OUTPUT ;
    USE SIGNAL ;
    PORT
      LAYER M4 ;
        RECT  0 26.256 0.084 26.28 ;
    END
  END decoded[53]
  PIN decoded[54]
    DIRECTION OUTPUT ;
    USE SIGNAL ;
    PORT
      LAYER M4 ;
        RECT  0 26.352 0.084 26.376 ;
    END
  END decoded[54]
  PIN decoded[55]
    DIRECTION OUTPUT ;
    USE SIGNAL ;
    PORT
      LAYER M4 ;
        RECT  0 26.448 0.084 26.472 ;
    END
  END decoded[55]
  PIN decoded[56]
    DIRECTION OUTPUT ;
    USE SIGNAL ;
    PORT
      LAYER M4 ;
        RECT  0 26.544 0.084 26.568 ;
    END
  END decoded[56]
  PIN decoded[57]
    DIRECTION OUTPUT ;
    USE SIGNAL ;
    PORT
      LAYER M4 ;
        RECT  0 26.64 0.084 26.664 ;
    END
  END decoded[57]
  PIN decoded[58]
    DIRECTION OUTPUT ;
    USE SIGNAL ;
    PORT
      LAYER M4 ;
        RECT  0 26.736 0.084 26.76 ;
    END
  END decoded[58]
  PIN decoded[59]
    DIRECTION OUTPUT ;
    USE SIGNAL ;
    PORT
      LAYER M4 ;
        RECT  0 26.832 0.084 26.856 ;
    END
  END decoded[59]
  PIN decoded[5]
    DIRECTION OUTPUT ;
    USE SIGNAL ;
    PORT
      LAYER M4 ;
        RECT  0 27.792 0.084 27.816 ;
    END
  END decoded[5]
  PIN decoded[60]
    DIRECTION OUTPUT ;
    USE SIGNAL ;
    PORT
      LAYER M4 ;
        RECT  0 26.928 0.084 26.952 ;
    END
  END decoded[60]
  PIN decoded[61]
    DIRECTION OUTPUT ;
    USE SIGNAL ;
    PORT
      LAYER M4 ;
        RECT  0 27.024 0.084 27.048 ;
    END
  END decoded[61]
  PIN decoded[62]
    DIRECTION OUTPUT ;
    USE SIGNAL ;
    PORT
      LAYER M4 ;
        RECT  0 27.12 0.084 27.144 ;
    END
  END decoded[62]
  PIN decoded[63]
    DIRECTION OUTPUT ;
    USE SIGNAL ;
    PORT
      LAYER M4 ;
        RECT  0 21.072 0.084 21.096 ;
    END
  END decoded[63]
  PIN decoded[64]
    DIRECTION OUTPUT ;
    USE SIGNAL ;
    PORT
      LAYER M4 ;
        RECT  0 21.168 0.084 21.192 ;
    END
  END decoded[64]
  PIN decoded[65]
    DIRECTION OUTPUT ;
    USE SIGNAL ;
    PORT
      LAYER M4 ;
        RECT  0 21.264 0.084 21.288 ;
    END
  END decoded[65]
  PIN decoded[66]
    DIRECTION OUTPUT ;
    USE SIGNAL ;
    PORT
      LAYER M4 ;
        RECT  0 21.36 0.084 21.384 ;
    END
  END decoded[66]
  PIN decoded[67]
    DIRECTION OUTPUT ;
    USE SIGNAL ;
    PORT
      LAYER M4 ;
        RECT  0 21.456 0.084 21.48 ;
    END
  END decoded[67]
  PIN decoded[68]
    DIRECTION OUTPUT ;
    USE SIGNAL ;
    PORT
      LAYER M4 ;
        RECT  0 21.552 0.084 21.576 ;
    END
  END decoded[68]
  PIN decoded[69]
    DIRECTION OUTPUT ;
    USE SIGNAL ;
    PORT
      LAYER M4 ;
        RECT  0 21.648 0.084 21.672 ;
    END
  END decoded[69]
  PIN decoded[6]
    DIRECTION OUTPUT ;
    USE SIGNAL ;
    PORT
      LAYER M4 ;
        RECT  0 27.888 0.084 27.912 ;
    END
  END decoded[6]
  PIN decoded[70]
    DIRECTION OUTPUT ;
    USE SIGNAL ;
    PORT
      LAYER M4 ;
        RECT  0 21.744 0.084 21.768 ;
    END
  END decoded[70]
  PIN decoded[71]
    DIRECTION OUTPUT ;
    USE SIGNAL ;
    PORT
      LAYER M4 ;
        RECT  0 21.84 0.084 21.864 ;
    END
  END decoded[71]
  PIN decoded[72]
    DIRECTION OUTPUT ;
    USE SIGNAL ;
    PORT
      LAYER M4 ;
        RECT  0 21.936 0.084 21.96 ;
    END
  END decoded[72]
  PIN decoded[73]
    DIRECTION OUTPUT ;
    USE SIGNAL ;
    PORT
      LAYER M4 ;
        RECT  0 22.032 0.084 22.056 ;
    END
  END decoded[73]
  PIN decoded[74]
    DIRECTION OUTPUT ;
    USE SIGNAL ;
    PORT
      LAYER M4 ;
        RECT  0 22.128 0.084 22.152 ;
    END
  END decoded[74]
  PIN decoded[75]
    DIRECTION OUTPUT ;
    USE SIGNAL ;
    PORT
      LAYER M4 ;
        RECT  0 22.224 0.084 22.248 ;
    END
  END decoded[75]
  PIN decoded[76]
    DIRECTION OUTPUT ;
    USE SIGNAL ;
    PORT
      LAYER M4 ;
        RECT  0 22.32 0.084 22.344 ;
    END
  END decoded[76]
  PIN decoded[77]
    DIRECTION OUTPUT ;
    USE SIGNAL ;
    PORT
      LAYER M4 ;
        RECT  0 22.416 0.084 22.44 ;
    END
  END decoded[77]
  PIN decoded[78]
    DIRECTION OUTPUT ;
    USE SIGNAL ;
    PORT
      LAYER M4 ;
        RECT  0 22.512 0.084 22.536 ;
    END
  END decoded[78]
  PIN decoded[79]
    DIRECTION OUTPUT ;
    USE SIGNAL ;
    PORT
      LAYER M4 ;
        RECT  0 22.608 0.084 22.632 ;
    END
  END decoded[79]
  PIN decoded[7]
    DIRECTION OUTPUT ;
    USE SIGNAL ;
    PORT
      LAYER M4 ;
        RECT  0 27.984 0.084 28.008 ;
    END
  END decoded[7]
  PIN decoded[80]
    DIRECTION OUTPUT ;
    USE SIGNAL ;
    PORT
      LAYER M4 ;
        RECT  0 22.704 0.084 22.728 ;
    END
  END decoded[80]
  PIN decoded[81]
    DIRECTION OUTPUT ;
    USE SIGNAL ;
    PORT
      LAYER M4 ;
        RECT  0 22.8 0.084 22.824 ;
    END
  END decoded[81]
  PIN decoded[82]
    DIRECTION OUTPUT ;
    USE SIGNAL ;
    PORT
      LAYER M4 ;
        RECT  0 22.896 0.084 22.92 ;
    END
  END decoded[82]
  PIN decoded[83]
    DIRECTION OUTPUT ;
    USE SIGNAL ;
    PORT
      LAYER M4 ;
        RECT  0 22.992 0.084 23.016 ;
    END
  END decoded[83]
  PIN decoded[84]
    DIRECTION OUTPUT ;
    USE SIGNAL ;
    PORT
      LAYER M4 ;
        RECT  0 23.088 0.084 23.112 ;
    END
  END decoded[84]
  PIN decoded[85]
    DIRECTION OUTPUT ;
    USE SIGNAL ;
    PORT
      LAYER M4 ;
        RECT  0 23.184 0.084 23.208 ;
    END
  END decoded[85]
  PIN decoded[86]
    DIRECTION OUTPUT ;
    USE SIGNAL ;
    PORT
      LAYER M4 ;
        RECT  0 23.28 0.084 23.304 ;
    END
  END decoded[86]
  PIN decoded[87]
    DIRECTION OUTPUT ;
    USE SIGNAL ;
    PORT
      LAYER M4 ;
        RECT  0 23.376 0.084 23.4 ;
    END
  END decoded[87]
  PIN decoded[88]
    DIRECTION OUTPUT ;
    USE SIGNAL ;
    PORT
      LAYER M4 ;
        RECT  0 23.472 0.084 23.496 ;
    END
  END decoded[88]
  PIN decoded[89]
    DIRECTION OUTPUT ;
    USE SIGNAL ;
    PORT
      LAYER M4 ;
        RECT  0 23.568 0.084 23.592 ;
    END
  END decoded[89]
  PIN decoded[8]
    DIRECTION OUTPUT ;
    USE SIGNAL ;
    PORT
      LAYER M4 ;
        RECT  0 28.08 0.084 28.104 ;
    END
  END decoded[8]
  PIN decoded[90]
    DIRECTION OUTPUT ;
    USE SIGNAL ;
    PORT
      LAYER M4 ;
        RECT  0 23.664 0.084 23.688 ;
    END
  END decoded[90]
  PIN decoded[91]
    DIRECTION OUTPUT ;
    USE SIGNAL ;
    PORT
      LAYER M4 ;
        RECT  0 23.76 0.084 23.784 ;
    END
  END decoded[91]
  PIN decoded[92]
    DIRECTION OUTPUT ;
    USE SIGNAL ;
    PORT
      LAYER M4 ;
        RECT  0 23.856 0.084 23.88 ;
    END
  END decoded[92]
  PIN decoded[93]
    DIRECTION OUTPUT ;
    USE SIGNAL ;
    PORT
      LAYER M4 ;
        RECT  0 23.952 0.084 23.976 ;
    END
  END decoded[93]
  PIN decoded[94]
    DIRECTION OUTPUT ;
    USE SIGNAL ;
    PORT
      LAYER M4 ;
        RECT  0 24.048 0.084 24.072 ;
    END
  END decoded[94]
  PIN decoded[95]
    DIRECTION OUTPUT ;
    USE SIGNAL ;
    PORT
      LAYER M4 ;
        RECT  0 18 0.084 18.024 ;
    END
  END decoded[95]
  PIN decoded[96]
    DIRECTION OUTPUT ;
    USE SIGNAL ;
    PORT
      LAYER M4 ;
        RECT  0 18.096 0.084 18.12 ;
    END
  END decoded[96]
  PIN decoded[97]
    DIRECTION OUTPUT ;
    USE SIGNAL ;
    PORT
      LAYER M4 ;
        RECT  0 18.192 0.084 18.216 ;
    END
  END decoded[97]
  PIN decoded[98]
    DIRECTION OUTPUT ;
    USE SIGNAL ;
    PORT
      LAYER M4 ;
        RECT  0 18.288 0.084 18.312 ;
    END
  END decoded[98]
  PIN decoded[99]
    DIRECTION OUTPUT ;
    USE SIGNAL ;
    PORT
      LAYER M4 ;
        RECT  0 18.384 0.084 18.408 ;
    END
  END decoded[99]
  PIN decoded[9]
    DIRECTION OUTPUT ;
    USE SIGNAL ;
    PORT
      LAYER M4 ;
        RECT  0 28.176 0.084 28.2 ;
    END
  END decoded[9]
  PIN land_read[0]
    DIRECTION INPUT ;
    USE SIGNAL ;
    PORT
      LAYER M4 ;
        RECT  0 45.264 0.084 45.288 ;
    END
  END land_read[0]
  PIN land_read[10]
    DIRECTION INPUT ;
    USE SIGNAL ;
    PORT
      LAYER M4 ;
        RECT  0 46.224 0.084 46.248 ;
    END
  END land_read[10]
  PIN land_read[11]
    DIRECTION INPUT ;
    USE SIGNAL ;
    PORT
      LAYER M4 ;
        RECT  0 46.32 0.084 46.344 ;
    END
  END land_read[11]
  PIN land_read[12]
    DIRECTION INPUT ;
    USE SIGNAL ;
    PORT
      LAYER M4 ;
        RECT  0 31.056 0.084 31.08 ;
    END
  END land_read[12]
  PIN land_read[13]
    DIRECTION INPUT ;
    USE SIGNAL ;
    PORT
      LAYER M4 ;
        RECT  0 31.152 0.084 31.176 ;
    END
  END land_read[13]
  PIN land_read[14]
    DIRECTION INPUT ;
    USE SIGNAL ;
    PORT
      LAYER M4 ;
        RECT  0 31.248 0.084 31.272 ;
    END
  END land_read[14]
  PIN land_read[15]
    DIRECTION INPUT ;
    USE SIGNAL ;
    PORT
      LAYER M4 ;
        RECT  0 31.344 0.084 31.368 ;
    END
  END land_read[15]
  PIN land_read[16]
    DIRECTION INPUT ;
    USE SIGNAL ;
    PORT
      LAYER M4 ;
        RECT  0 31.44 0.084 31.464 ;
    END
  END land_read[16]
  PIN land_read[17]
    DIRECTION INPUT ;
    USE SIGNAL ;
    PORT
      LAYER M4 ;
        RECT  0 31.536 0.084 31.56 ;
    END
  END land_read[17]
  PIN land_read[18]
    DIRECTION INPUT ;
    USE SIGNAL ;
    PORT
      LAYER M4 ;
        RECT  0 31.632 0.084 31.656 ;
    END
  END land_read[18]
  PIN land_read[19]
    DIRECTION INPUT ;
    USE SIGNAL ;
    PORT
      LAYER M4 ;
        RECT  0 31.728 0.084 31.752 ;
    END
  END land_read[19]
  PIN land_read[1]
    DIRECTION INPUT ;
    USE SIGNAL ;
    PORT
      LAYER M4 ;
        RECT  0 45.36 0.084 45.384 ;
    END
  END land_read[1]
  PIN land_read[20]
    DIRECTION INPUT ;
    USE SIGNAL ;
    PORT
      LAYER M4 ;
        RECT  0 31.824 0.084 31.848 ;
    END
  END land_read[20]
  PIN land_read[21]
    DIRECTION INPUT ;
    USE SIGNAL ;
    PORT
      LAYER M4 ;
        RECT  0 31.92 0.084 31.944 ;
    END
  END land_read[21]
  PIN land_read[22]
    DIRECTION INPUT ;
    USE SIGNAL ;
    PORT
      LAYER M4 ;
        RECT  0 32.016 0.084 32.04 ;
    END
  END land_read[22]
  PIN land_read[23]
    DIRECTION INPUT ;
    USE SIGNAL ;
    PORT
      LAYER M4 ;
        RECT  0 32.112 0.084 32.136 ;
    END
  END land_read[23]
  PIN land_read[24]
    DIRECTION INPUT ;
    USE SIGNAL ;
    PORT
      LAYER M4 ;
        RECT  0 32.208 0.084 32.232 ;
    END
  END land_read[24]
  PIN land_read[25]
    DIRECTION INPUT ;
    USE SIGNAL ;
    PORT
      LAYER M4 ;
        RECT  0 32.304 0.084 32.328 ;
    END
  END land_read[25]
  PIN land_read[26]
    DIRECTION INPUT ;
    USE SIGNAL ;
    PORT
      LAYER M4 ;
        RECT  0 32.4 0.084 32.424 ;
    END
  END land_read[26]
  PIN land_read[27]
    DIRECTION INPUT ;
    USE SIGNAL ;
    PORT
      LAYER M4 ;
        RECT  0 32.496 0.084 32.52 ;
    END
  END land_read[27]
  PIN land_read[28]
    DIRECTION INPUT ;
    USE SIGNAL ;
    PORT
      LAYER M4 ;
        RECT  0 32.592 0.084 32.616 ;
    END
  END land_read[28]
  PIN land_read[29]
    DIRECTION INPUT ;
    USE SIGNAL ;
    PORT
      LAYER M4 ;
        RECT  0 32.688 0.084 32.712 ;
    END
  END land_read[29]
  PIN land_read[2]
    DIRECTION INPUT ;
    USE SIGNAL ;
    PORT
      LAYER M4 ;
        RECT  0 45.456 0.084 45.48 ;
    END
  END land_read[2]
  PIN land_read[30]
    DIRECTION INPUT ;
    USE SIGNAL ;
    PORT
      LAYER M4 ;
        RECT  0 32.784 0.084 32.808 ;
    END
  END land_read[30]
  PIN land_read[31]
    DIRECTION INPUT ;
    USE SIGNAL ;
    PORT
      LAYER M4 ;
        RECT  0 32.88 0.084 32.904 ;
    END
  END land_read[31]
  PIN land_read[32]
    DIRECTION INPUT ;
    USE SIGNAL ;
    PORT
      LAYER M4 ;
        RECT  0 32.976 0.084 33 ;
    END
  END land_read[32]
  PIN land_read[33]
    DIRECTION INPUT ;
    USE SIGNAL ;
    PORT
      LAYER M4 ;
        RECT  0 33.072 0.084 33.096 ;
    END
  END land_read[33]
  PIN land_read[34]
    DIRECTION INPUT ;
    USE SIGNAL ;
    PORT
      LAYER M4 ;
        RECT  0 33.168 0.084 33.192 ;
    END
  END land_read[34]
  PIN land_read[35]
    DIRECTION INPUT ;
    USE SIGNAL ;
    PORT
      LAYER M4 ;
        RECT  0 33.264 0.084 33.288 ;
    END
  END land_read[35]
  PIN land_read[36]
    DIRECTION INPUT ;
    USE SIGNAL ;
    PORT
      LAYER M4 ;
        RECT  0 33.36 0.084 33.384 ;
    END
  END land_read[36]
  PIN land_read[37]
    DIRECTION INPUT ;
    USE SIGNAL ;
    PORT
      LAYER M4 ;
        RECT  0 33.456 0.084 33.48 ;
    END
  END land_read[37]
  PIN land_read[38]
    DIRECTION INPUT ;
    USE SIGNAL ;
    PORT
      LAYER M4 ;
        RECT  0 33.552 0.084 33.576 ;
    END
  END land_read[38]
  PIN land_read[39]
    DIRECTION INPUT ;
    USE SIGNAL ;
    PORT
      LAYER M4 ;
        RECT  0 33.648 0.084 33.672 ;
    END
  END land_read[39]
  PIN land_read[3]
    DIRECTION INPUT ;
    USE SIGNAL ;
    PORT
      LAYER M4 ;
        RECT  0 45.552 0.084 45.576 ;
    END
  END land_read[3]
  PIN land_read[40]
    DIRECTION INPUT ;
    USE SIGNAL ;
    PORT
      LAYER M4 ;
        RECT  0 33.744 0.084 33.768 ;
    END
  END land_read[40]
  PIN land_read[41]
    DIRECTION INPUT ;
    USE SIGNAL ;
    PORT
      LAYER M4 ;
        RECT  0 33.84 0.084 33.864 ;
    END
  END land_read[41]
  PIN land_read[42]
    DIRECTION INPUT ;
    USE SIGNAL ;
    PORT
      LAYER M4 ;
        RECT  0 33.936 0.084 33.96 ;
    END
  END land_read[42]
  PIN land_read[43]
    DIRECTION INPUT ;
    USE SIGNAL ;
    PORT
      LAYER M4 ;
        RECT  0 34.032 0.084 34.056 ;
    END
  END land_read[43]
  PIN land_read[44]
    DIRECTION INPUT ;
    USE SIGNAL ;
    PORT
      LAYER M4 ;
        RECT  0 46.416 0.084 46.44 ;
    END
  END land_read[44]
  PIN land_read[45]
    DIRECTION INPUT ;
    USE SIGNAL ;
    PORT
      LAYER M4 ;
        RECT  0 46.512 0.084 46.536 ;
    END
  END land_read[45]
  PIN land_read[46]
    DIRECTION INPUT ;
    USE SIGNAL ;
    PORT
      LAYER M4 ;
        RECT  0 46.608 0.084 46.632 ;
    END
  END land_read[46]
  PIN land_read[47]
    DIRECTION INPUT ;
    USE SIGNAL ;
    PORT
      LAYER M4 ;
        RECT  0 46.704 0.084 46.728 ;
    END
  END land_read[47]
  PIN land_read[48]
    DIRECTION INPUT ;
    USE SIGNAL ;
    PORT
      LAYER M4 ;
        RECT  0 46.8 0.084 46.824 ;
    END
  END land_read[48]
  PIN land_read[49]
    DIRECTION INPUT ;
    USE SIGNAL ;
    PORT
      LAYER M4 ;
        RECT  0 46.896 0.084 46.92 ;
    END
  END land_read[49]
  PIN land_read[4]
    DIRECTION INPUT ;
    USE SIGNAL ;
    PORT
      LAYER M4 ;
        RECT  0 45.648 0.084 45.672 ;
    END
  END land_read[4]
  PIN land_read[50]
    DIRECTION INPUT ;
    USE SIGNAL ;
    PORT
      LAYER M4 ;
        RECT  0 46.992 0.084 47.016 ;
    END
  END land_read[50]
  PIN land_read[51]
    DIRECTION INPUT ;
    USE SIGNAL ;
    PORT
      LAYER M4 ;
        RECT  0 47.088 0.084 47.112 ;
    END
  END land_read[51]
  PIN land_read[52]
    DIRECTION INPUT ;
    USE SIGNAL ;
    PORT
      LAYER M4 ;
        RECT  0 47.184 0.084 47.208 ;
    END
  END land_read[52]
  PIN land_read[53]
    DIRECTION INPUT ;
    USE SIGNAL ;
    PORT
      LAYER M4 ;
        RECT  0 47.28 0.084 47.304 ;
    END
  END land_read[53]
  PIN land_read[54]
    DIRECTION INPUT ;
    USE SIGNAL ;
    PORT
      LAYER M4 ;
        RECT  0 47.376 0.084 47.4 ;
    END
  END land_read[54]
  PIN land_read[55]
    DIRECTION INPUT ;
    USE SIGNAL ;
    PORT
      LAYER M4 ;
        RECT  0 47.472 0.084 47.496 ;
    END
  END land_read[55]
  PIN land_read[56]
    DIRECTION INPUT ;
    USE SIGNAL ;
    PORT
      LAYER M4 ;
        RECT  0 47.568 0.084 47.592 ;
    END
  END land_read[56]
  PIN land_read[57]
    DIRECTION INPUT ;
    USE SIGNAL ;
    PORT
      LAYER M4 ;
        RECT  0 47.664 0.084 47.688 ;
    END
  END land_read[57]
  PIN land_read[58]
    DIRECTION INPUT ;
    USE SIGNAL ;
    PORT
      LAYER M4 ;
        RECT  0 47.76 0.084 47.784 ;
    END
  END land_read[58]
  PIN land_read[59]
    DIRECTION INPUT ;
    USE SIGNAL ;
    PORT
      LAYER M4 ;
        RECT  0 47.856 0.084 47.88 ;
    END
  END land_read[59]
  PIN land_read[5]
    DIRECTION INPUT ;
    USE SIGNAL ;
    PORT
      LAYER M4 ;
        RECT  0 45.744 0.084 45.768 ;
    END
  END land_read[5]
  PIN land_read[60]
    DIRECTION INPUT ;
    USE SIGNAL ;
    PORT
      LAYER M4 ;
        RECT  0 47.952 0.084 47.976 ;
    END
  END land_read[60]
  PIN land_read[61]
    DIRECTION INPUT ;
    USE SIGNAL ;
    PORT
      LAYER M4 ;
        RECT  0 48.048 0.084 48.072 ;
    END
  END land_read[61]
  PIN land_read[62]
    DIRECTION INPUT ;
    USE SIGNAL ;
    PORT
      LAYER M4 ;
        RECT  0 48.144 0.084 48.168 ;
    END
  END land_read[62]
  PIN land_read[63]
    DIRECTION INPUT ;
    USE SIGNAL ;
    PORT
      LAYER M4 ;
        RECT  0 48.24 0.084 48.264 ;
    END
  END land_read[63]
  PIN land_read[6]
    DIRECTION INPUT ;
    USE SIGNAL ;
    PORT
      LAYER M4 ;
        RECT  0 45.84 0.084 45.864 ;
    END
  END land_read[6]
  PIN land_read[7]
    DIRECTION INPUT ;
    USE SIGNAL ;
    PORT
      LAYER M4 ;
        RECT  0 45.936 0.084 45.96 ;
    END
  END land_read[7]
  PIN land_read[8]
    DIRECTION INPUT ;
    USE SIGNAL ;
    PORT
      LAYER M4 ;
        RECT  0 46.032 0.084 46.056 ;
    END
  END land_read[8]
  PIN land_read[9]
    DIRECTION INPUT ;
    USE SIGNAL ;
    PORT
      LAYER M4 ;
        RECT  0 46.128 0.084 46.152 ;
    END
  END land_read[9]
  PIN land_write[0]
    DIRECTION INPUT ;
    USE SIGNAL ;
    PORT
      LAYER M4 ;
        RECT  0 48.336 0.084 48.36 ;
    END
  END land_write[0]
  PIN land_write[100]
    DIRECTION INPUT ;
    USE SIGNAL ;
    PORT
      LAYER M4 ;
        RECT  0 61.776 0.084 61.8 ;
    END
  END land_write[100]
  PIN land_write[101]
    DIRECTION INPUT ;
    USE SIGNAL ;
    PORT
      LAYER M4 ;
        RECT  0 61.872 0.084 61.896 ;
    END
  END land_write[101]
  PIN land_write[102]
    DIRECTION INPUT ;
    USE SIGNAL ;
    PORT
      LAYER M4 ;
        RECT  0 61.968 0.084 61.992 ;
    END
  END land_write[102]
  PIN land_write[103]
    DIRECTION INPUT ;
    USE SIGNAL ;
    PORT
      LAYER M4 ;
        RECT  0 62.064 0.084 62.088 ;
    END
  END land_write[103]
  PIN land_write[104]
    DIRECTION INPUT ;
    USE SIGNAL ;
    PORT
      LAYER M4 ;
        RECT  0 62.16 0.084 62.184 ;
    END
  END land_write[104]
  PIN land_write[105]
    DIRECTION INPUT ;
    USE SIGNAL ;
    PORT
      LAYER M4 ;
        RECT  0 62.256 0.084 62.28 ;
    END
  END land_write[105]
  PIN land_write[106]
    DIRECTION INPUT ;
    USE SIGNAL ;
    PORT
      LAYER M4 ;
        RECT  0 62.352 0.084 62.376 ;
    END
  END land_write[106]
  PIN land_write[107]
    DIRECTION INPUT ;
    USE SIGNAL ;
    PORT
      LAYER M4 ;
        RECT  0 62.448 0.084 62.472 ;
    END
  END land_write[107]
  PIN land_write[108]
    DIRECTION INPUT ;
    USE SIGNAL ;
    PORT
      LAYER M4 ;
        RECT  0 62.544 0.084 62.568 ;
    END
  END land_write[108]
  PIN land_write[109]
    DIRECTION INPUT ;
    USE SIGNAL ;
    PORT
      LAYER M4 ;
        RECT  0 62.64 0.084 62.664 ;
    END
  END land_write[109]
  PIN land_write[10]
    DIRECTION INPUT ;
    USE SIGNAL ;
    PORT
      LAYER M4 ;
        RECT  0 49.296 0.084 49.32 ;
    END
  END land_write[10]
  PIN land_write[110]
    DIRECTION INPUT ;
    USE SIGNAL ;
    PORT
      LAYER M4 ;
        RECT  0 62.736 0.084 62.76 ;
    END
  END land_write[110]
  PIN land_write[111]
    DIRECTION INPUT ;
    USE SIGNAL ;
    PORT
      LAYER M4 ;
        RECT  0 62.832 0.084 62.856 ;
    END
  END land_write[111]
  PIN land_write[112]
    DIRECTION INPUT ;
    USE SIGNAL ;
    PORT
      LAYER M4 ;
        RECT  0 62.928 0.084 62.952 ;
    END
  END land_write[112]
  PIN land_write[113]
    DIRECTION INPUT ;
    USE SIGNAL ;
    PORT
      LAYER M4 ;
        RECT  0 63.024 0.084 63.048 ;
    END
  END land_write[113]
  PIN land_write[114]
    DIRECTION INPUT ;
    USE SIGNAL ;
    PORT
      LAYER M4 ;
        RECT  0 63.12 0.084 63.144 ;
    END
  END land_write[114]
  PIN land_write[115]
    DIRECTION INPUT ;
    USE SIGNAL ;
    PORT
      LAYER M4 ;
        RECT  0 63.216 0.084 63.24 ;
    END
  END land_write[115]
  PIN land_write[116]
    DIRECTION INPUT ;
    USE SIGNAL ;
    PORT
      LAYER M4 ;
        RECT  0 63.312 0.084 63.336 ;
    END
  END land_write[116]
  PIN land_write[117]
    DIRECTION INPUT ;
    USE SIGNAL ;
    PORT
      LAYER M4 ;
        RECT  0 63.408 0.084 63.432 ;
    END
  END land_write[117]
  PIN land_write[118]
    DIRECTION INPUT ;
    USE SIGNAL ;
    PORT
      LAYER M4 ;
        RECT  0 63.504 0.084 63.528 ;
    END
  END land_write[118]
  PIN land_write[119]
    DIRECTION INPUT ;
    USE SIGNAL ;
    PORT
      LAYER M4 ;
        RECT  0 63.6 0.084 63.624 ;
    END
  END land_write[119]
  PIN land_write[11]
    DIRECTION INPUT ;
    USE SIGNAL ;
    PORT
      LAYER M4 ;
        RECT  0 49.392 0.084 49.416 ;
    END
  END land_write[11]
  PIN land_write[120]
    DIRECTION INPUT ;
    USE SIGNAL ;
    PORT
      LAYER M4 ;
        RECT  0 63.696 0.084 63.72 ;
    END
  END land_write[120]
  PIN land_write[121]
    DIRECTION INPUT ;
    USE SIGNAL ;
    PORT
      LAYER M4 ;
        RECT  0 63.792 0.084 63.816 ;
    END
  END land_write[121]
  PIN land_write[122]
    DIRECTION INPUT ;
    USE SIGNAL ;
    PORT
      LAYER M4 ;
        RECT  0 63.888 0.084 63.912 ;
    END
  END land_write[122]
  PIN land_write[123]
    DIRECTION INPUT ;
    USE SIGNAL ;
    PORT
      LAYER M4 ;
        RECT  0 63.984 0.084 64.008 ;
    END
  END land_write[123]
  PIN land_write[124]
    DIRECTION INPUT ;
    USE SIGNAL ;
    PORT
      LAYER M4 ;
        RECT  0 64.08 0.084 64.104 ;
    END
  END land_write[124]
  PIN land_write[125]
    DIRECTION INPUT ;
    USE SIGNAL ;
    PORT
      LAYER M4 ;
        RECT  0 64.176 0.084 64.2 ;
    END
  END land_write[125]
  PIN land_write[126]
    DIRECTION INPUT ;
    USE SIGNAL ;
    PORT
      LAYER M4 ;
        RECT  0 64.272 0.084 64.296 ;
    END
  END land_write[126]
  PIN land_write[127]
    DIRECTION INPUT ;
    USE SIGNAL ;
    PORT
      LAYER M4 ;
        RECT  0 64.368 0.084 64.392 ;
    END
  END land_write[127]
  PIN land_write[128]
    DIRECTION INPUT ;
    USE SIGNAL ;
    PORT
      LAYER M4 ;
        RECT  0 64.464 0.084 64.488 ;
    END
  END land_write[128]
  PIN land_write[129]
    DIRECTION INPUT ;
    USE SIGNAL ;
    PORT
      LAYER M4 ;
        RECT  0 64.56 0.084 64.584 ;
    END
  END land_write[129]
  PIN land_write[12]
    DIRECTION INPUT ;
    USE SIGNAL ;
    PORT
      LAYER M4 ;
        RECT  0 53.328 0.084 53.352 ;
    END
  END land_write[12]
  PIN land_write[130]
    DIRECTION INPUT ;
    USE SIGNAL ;
    PORT
      LAYER M4 ;
        RECT  0 64.656 0.084 64.68 ;
    END
  END land_write[130]
  PIN land_write[131]
    DIRECTION INPUT ;
    USE SIGNAL ;
    PORT
      LAYER M4 ;
        RECT  0 64.752 0.084 64.776 ;
    END
  END land_write[131]
  PIN land_write[132]
    DIRECTION INPUT ;
    USE SIGNAL ;
    PORT
      LAYER M4 ;
        RECT  0 64.848 0.084 64.872 ;
    END
  END land_write[132]
  PIN land_write[133]
    DIRECTION INPUT ;
    USE SIGNAL ;
    PORT
      LAYER M4 ;
        RECT  0 64.944 0.084 64.968 ;
    END
  END land_write[133]
  PIN land_write[134]
    DIRECTION INPUT ;
    USE SIGNAL ;
    PORT
      LAYER M4 ;
        RECT  0 65.04 0.084 65.064 ;
    END
  END land_write[134]
  PIN land_write[135]
    DIRECTION INPUT ;
    USE SIGNAL ;
    PORT
      LAYER M4 ;
        RECT  0 65.136 0.084 65.16 ;
    END
  END land_write[135]
  PIN land_write[136]
    DIRECTION INPUT ;
    USE SIGNAL ;
    PORT
      LAYER M4 ;
        RECT  0 65.232 0.084 65.256 ;
    END
  END land_write[136]
  PIN land_write[137]
    DIRECTION INPUT ;
    USE SIGNAL ;
    PORT
      LAYER M4 ;
        RECT  0 65.328 0.084 65.352 ;
    END
  END land_write[137]
  PIN land_write[138]
    DIRECTION INPUT ;
    USE SIGNAL ;
    PORT
      LAYER M4 ;
        RECT  0 65.424 0.084 65.448 ;
    END
  END land_write[138]
  PIN land_write[139]
    DIRECTION INPUT ;
    USE SIGNAL ;
    PORT
      LAYER M4 ;
        RECT  0 65.52 0.084 65.544 ;
    END
  END land_write[139]
  PIN land_write[13]
    DIRECTION INPUT ;
    USE SIGNAL ;
    PORT
      LAYER M4 ;
        RECT  0 53.424 0.084 53.448 ;
    END
  END land_write[13]
  PIN land_write[140]
    DIRECTION INPUT ;
    USE SIGNAL ;
    PORT
      LAYER M4 ;
        RECT  0 40.272 0.084 40.296 ;
    END
  END land_write[140]
  PIN land_write[141]
    DIRECTION INPUT ;
    USE SIGNAL ;
    PORT
      LAYER M4 ;
        RECT  0 40.368 0.084 40.392 ;
    END
  END land_write[141]
  PIN land_write[142]
    DIRECTION INPUT ;
    USE SIGNAL ;
    PORT
      LAYER M4 ;
        RECT  0 40.464 0.084 40.488 ;
    END
  END land_write[142]
  PIN land_write[143]
    DIRECTION INPUT ;
    USE SIGNAL ;
    PORT
      LAYER M4 ;
        RECT  0 40.56 0.084 40.584 ;
    END
  END land_write[143]
  PIN land_write[144]
    DIRECTION INPUT ;
    USE SIGNAL ;
    PORT
      LAYER M4 ;
        RECT  0 40.656 0.084 40.68 ;
    END
  END land_write[144]
  PIN land_write[145]
    DIRECTION INPUT ;
    USE SIGNAL ;
    PORT
      LAYER M4 ;
        RECT  0 40.752 0.084 40.776 ;
    END
  END land_write[145]
  PIN land_write[146]
    DIRECTION INPUT ;
    USE SIGNAL ;
    PORT
      LAYER M4 ;
        RECT  0 40.848 0.084 40.872 ;
    END
  END land_write[146]
  PIN land_write[147]
    DIRECTION INPUT ;
    USE SIGNAL ;
    PORT
      LAYER M4 ;
        RECT  0 40.944 0.084 40.968 ;
    END
  END land_write[147]
  PIN land_write[148]
    DIRECTION INPUT ;
    USE SIGNAL ;
    PORT
      LAYER M4 ;
        RECT  0 41.04 0.084 41.064 ;
    END
  END land_write[148]
  PIN land_write[149]
    DIRECTION INPUT ;
    USE SIGNAL ;
    PORT
      LAYER M4 ;
        RECT  0 41.136 0.084 41.16 ;
    END
  END land_write[149]
  PIN land_write[14]
    DIRECTION INPUT ;
    USE SIGNAL ;
    PORT
      LAYER M4 ;
        RECT  0 53.52 0.084 53.544 ;
    END
  END land_write[14]
  PIN land_write[150]
    DIRECTION INPUT ;
    USE SIGNAL ;
    PORT
      LAYER M4 ;
        RECT  0 41.232 0.084 41.256 ;
    END
  END land_write[150]
  PIN land_write[151]
    DIRECTION INPUT ;
    USE SIGNAL ;
    PORT
      LAYER M4 ;
        RECT  0 41.328 0.084 41.352 ;
    END
  END land_write[151]
  PIN land_write[152]
    DIRECTION INPUT ;
    USE SIGNAL ;
    PORT
      LAYER M4 ;
        RECT  0 41.424 0.084 41.448 ;
    END
  END land_write[152]
  PIN land_write[153]
    DIRECTION INPUT ;
    USE SIGNAL ;
    PORT
      LAYER M4 ;
        RECT  0 41.52 0.084 41.544 ;
    END
  END land_write[153]
  PIN land_write[154]
    DIRECTION INPUT ;
    USE SIGNAL ;
    PORT
      LAYER M4 ;
        RECT  0 41.616 0.084 41.64 ;
    END
  END land_write[154]
  PIN land_write[155]
    DIRECTION INPUT ;
    USE SIGNAL ;
    PORT
      LAYER M4 ;
        RECT  0 41.712 0.084 41.736 ;
    END
  END land_write[155]
  PIN land_write[156]
    DIRECTION INPUT ;
    USE SIGNAL ;
    PORT
      LAYER M4 ;
        RECT  0 41.808 0.084 41.832 ;
    END
  END land_write[156]
  PIN land_write[157]
    DIRECTION INPUT ;
    USE SIGNAL ;
    PORT
      LAYER M4 ;
        RECT  0 41.904 0.084 41.928 ;
    END
  END land_write[157]
  PIN land_write[158]
    DIRECTION INPUT ;
    USE SIGNAL ;
    PORT
      LAYER M4 ;
        RECT  0 42 0.084 42.024 ;
    END
  END land_write[158]
  PIN land_write[159]
    DIRECTION INPUT ;
    USE SIGNAL ;
    PORT
      LAYER M4 ;
        RECT  0 42.096 0.084 42.12 ;
    END
  END land_write[159]
  PIN land_write[15]
    DIRECTION INPUT ;
    USE SIGNAL ;
    PORT
      LAYER M4 ;
        RECT  0 53.616 0.084 53.64 ;
    END
  END land_write[15]
  PIN land_write[160]
    DIRECTION INPUT ;
    USE SIGNAL ;
    PORT
      LAYER M4 ;
        RECT  0 42.192 0.084 42.216 ;
    END
  END land_write[160]
  PIN land_write[161]
    DIRECTION INPUT ;
    USE SIGNAL ;
    PORT
      LAYER M4 ;
        RECT  0 42.288 0.084 42.312 ;
    END
  END land_write[161]
  PIN land_write[162]
    DIRECTION INPUT ;
    USE SIGNAL ;
    PORT
      LAYER M4 ;
        RECT  0 42.384 0.084 42.408 ;
    END
  END land_write[162]
  PIN land_write[163]
    DIRECTION INPUT ;
    USE SIGNAL ;
    PORT
      LAYER M4 ;
        RECT  0 42.48 0.084 42.504 ;
    END
  END land_write[163]
  PIN land_write[164]
    DIRECTION INPUT ;
    USE SIGNAL ;
    PORT
      LAYER M4 ;
        RECT  0 42.576 0.084 42.6 ;
    END
  END land_write[164]
  PIN land_write[165]
    DIRECTION INPUT ;
    USE SIGNAL ;
    PORT
      LAYER M4 ;
        RECT  0 42.672 0.084 42.696 ;
    END
  END land_write[165]
  PIN land_write[166]
    DIRECTION INPUT ;
    USE SIGNAL ;
    PORT
      LAYER M4 ;
        RECT  0 42.768 0.084 42.792 ;
    END
  END land_write[166]
  PIN land_write[167]
    DIRECTION INPUT ;
    USE SIGNAL ;
    PORT
      LAYER M4 ;
        RECT  0 42.864 0.084 42.888 ;
    END
  END land_write[167]
  PIN land_write[168]
    DIRECTION INPUT ;
    USE SIGNAL ;
    PORT
      LAYER M4 ;
        RECT  0 42.96 0.084 42.984 ;
    END
  END land_write[168]
  PIN land_write[169]
    DIRECTION INPUT ;
    USE SIGNAL ;
    PORT
      LAYER M4 ;
        RECT  0 43.056 0.084 43.08 ;
    END
  END land_write[169]
  PIN land_write[16]
    DIRECTION INPUT ;
    USE SIGNAL ;
    PORT
      LAYER M4 ;
        RECT  0 53.712 0.084 53.736 ;
    END
  END land_write[16]
  PIN land_write[170]
    DIRECTION INPUT ;
    USE SIGNAL ;
    PORT
      LAYER M4 ;
        RECT  0 43.152 0.084 43.176 ;
    END
  END land_write[170]
  PIN land_write[171]
    DIRECTION INPUT ;
    USE SIGNAL ;
    PORT
      LAYER M4 ;
        RECT  0 43.248 0.084 43.272 ;
    END
  END land_write[171]
  PIN land_write[172]
    DIRECTION INPUT ;
    USE SIGNAL ;
    PORT
      LAYER M4 ;
        RECT  0 37.2 0.084 37.224 ;
    END
  END land_write[172]
  PIN land_write[173]
    DIRECTION INPUT ;
    USE SIGNAL ;
    PORT
      LAYER M4 ;
        RECT  0 37.296 0.084 37.32 ;
    END
  END land_write[173]
  PIN land_write[174]
    DIRECTION INPUT ;
    USE SIGNAL ;
    PORT
      LAYER M4 ;
        RECT  0 37.392 0.084 37.416 ;
    END
  END land_write[174]
  PIN land_write[175]
    DIRECTION INPUT ;
    USE SIGNAL ;
    PORT
      LAYER M4 ;
        RECT  0 37.488 0.084 37.512 ;
    END
  END land_write[175]
  PIN land_write[176]
    DIRECTION INPUT ;
    USE SIGNAL ;
    PORT
      LAYER M4 ;
        RECT  0 37.584 0.084 37.608 ;
    END
  END land_write[176]
  PIN land_write[177]
    DIRECTION INPUT ;
    USE SIGNAL ;
    PORT
      LAYER M4 ;
        RECT  0 37.68 0.084 37.704 ;
    END
  END land_write[177]
  PIN land_write[178]
    DIRECTION INPUT ;
    USE SIGNAL ;
    PORT
      LAYER M4 ;
        RECT  0 37.776 0.084 37.8 ;
    END
  END land_write[178]
  PIN land_write[179]
    DIRECTION INPUT ;
    USE SIGNAL ;
    PORT
      LAYER M4 ;
        RECT  0 37.872 0.084 37.896 ;
    END
  END land_write[179]
  PIN land_write[17]
    DIRECTION INPUT ;
    USE SIGNAL ;
    PORT
      LAYER M4 ;
        RECT  0 53.808 0.084 53.832 ;
    END
  END land_write[17]
  PIN land_write[180]
    DIRECTION INPUT ;
    USE SIGNAL ;
    PORT
      LAYER M4 ;
        RECT  0 37.968 0.084 37.992 ;
    END
  END land_write[180]
  PIN land_write[181]
    DIRECTION INPUT ;
    USE SIGNAL ;
    PORT
      LAYER M4 ;
        RECT  0 38.064 0.084 38.088 ;
    END
  END land_write[181]
  PIN land_write[182]
    DIRECTION INPUT ;
    USE SIGNAL ;
    PORT
      LAYER M4 ;
        RECT  0 38.16 0.084 38.184 ;
    END
  END land_write[182]
  PIN land_write[183]
    DIRECTION INPUT ;
    USE SIGNAL ;
    PORT
      LAYER M4 ;
        RECT  0 38.256 0.084 38.28 ;
    END
  END land_write[183]
  PIN land_write[184]
    DIRECTION INPUT ;
    USE SIGNAL ;
    PORT
      LAYER M4 ;
        RECT  0 38.352 0.084 38.376 ;
    END
  END land_write[184]
  PIN land_write[185]
    DIRECTION INPUT ;
    USE SIGNAL ;
    PORT
      LAYER M4 ;
        RECT  0 38.448 0.084 38.472 ;
    END
  END land_write[185]
  PIN land_write[186]
    DIRECTION INPUT ;
    USE SIGNAL ;
    PORT
      LAYER M4 ;
        RECT  0 38.544 0.084 38.568 ;
    END
  END land_write[186]
  PIN land_write[187]
    DIRECTION INPUT ;
    USE SIGNAL ;
    PORT
      LAYER M4 ;
        RECT  0 38.64 0.084 38.664 ;
    END
  END land_write[187]
  PIN land_write[188]
    DIRECTION INPUT ;
    USE SIGNAL ;
    PORT
      LAYER M4 ;
        RECT  0 38.736 0.084 38.76 ;
    END
  END land_write[188]
  PIN land_write[189]
    DIRECTION INPUT ;
    USE SIGNAL ;
    PORT
      LAYER M4 ;
        RECT  0 38.832 0.084 38.856 ;
    END
  END land_write[189]
  PIN land_write[18]
    DIRECTION INPUT ;
    USE SIGNAL ;
    PORT
      LAYER M4 ;
        RECT  0 53.904 0.084 53.928 ;
    END
  END land_write[18]
  PIN land_write[190]
    DIRECTION INPUT ;
    USE SIGNAL ;
    PORT
      LAYER M4 ;
        RECT  0 38.928 0.084 38.952 ;
    END
  END land_write[190]
  PIN land_write[191]
    DIRECTION INPUT ;
    USE SIGNAL ;
    PORT
      LAYER M4 ;
        RECT  0 39.024 0.084 39.048 ;
    END
  END land_write[191]
  PIN land_write[192]
    DIRECTION INPUT ;
    USE SIGNAL ;
    PORT
      LAYER M4 ;
        RECT  0 39.12 0.084 39.144 ;
    END
  END land_write[192]
  PIN land_write[193]
    DIRECTION INPUT ;
    USE SIGNAL ;
    PORT
      LAYER M4 ;
        RECT  0 39.216 0.084 39.24 ;
    END
  END land_write[193]
  PIN land_write[194]
    DIRECTION INPUT ;
    USE SIGNAL ;
    PORT
      LAYER M4 ;
        RECT  0 39.312 0.084 39.336 ;
    END
  END land_write[194]
  PIN land_write[195]
    DIRECTION INPUT ;
    USE SIGNAL ;
    PORT
      LAYER M4 ;
        RECT  0 39.408 0.084 39.432 ;
    END
  END land_write[195]
  PIN land_write[196]
    DIRECTION INPUT ;
    USE SIGNAL ;
    PORT
      LAYER M4 ;
        RECT  0 39.504 0.084 39.528 ;
    END
  END land_write[196]
  PIN land_write[197]
    DIRECTION INPUT ;
    USE SIGNAL ;
    PORT
      LAYER M4 ;
        RECT  0 39.6 0.084 39.624 ;
    END
  END land_write[197]
  PIN land_write[198]
    DIRECTION INPUT ;
    USE SIGNAL ;
    PORT
      LAYER M4 ;
        RECT  0 39.696 0.084 39.72 ;
    END
  END land_write[198]
  PIN land_write[199]
    DIRECTION INPUT ;
    USE SIGNAL ;
    PORT
      LAYER M4 ;
        RECT  0 39.792 0.084 39.816 ;
    END
  END land_write[199]
  PIN land_write[19]
    DIRECTION INPUT ;
    USE SIGNAL ;
    PORT
      LAYER M4 ;
        RECT  0 54 0.084 54.024 ;
    END
  END land_write[19]
  PIN land_write[1]
    DIRECTION INPUT ;
    USE SIGNAL ;
    PORT
      LAYER M4 ;
        RECT  0 48.432 0.084 48.456 ;
    END
  END land_write[1]
  PIN land_write[200]
    DIRECTION INPUT ;
    USE SIGNAL ;
    PORT
      LAYER M4 ;
        RECT  0 39.888 0.084 39.912 ;
    END
  END land_write[200]
  PIN land_write[201]
    DIRECTION INPUT ;
    USE SIGNAL ;
    PORT
      LAYER M4 ;
        RECT  0 39.984 0.084 40.008 ;
    END
  END land_write[201]
  PIN land_write[202]
    DIRECTION INPUT ;
    USE SIGNAL ;
    PORT
      LAYER M4 ;
        RECT  0 40.08 0.084 40.104 ;
    END
  END land_write[202]
  PIN land_write[203]
    DIRECTION INPUT ;
    USE SIGNAL ;
    PORT
      LAYER M4 ;
        RECT  0 40.176 0.084 40.2 ;
    END
  END land_write[203]
  PIN land_write[204]
    DIRECTION INPUT ;
    USE SIGNAL ;
    PORT
      LAYER M4 ;
        RECT  0 34.128 0.084 34.152 ;
    END
  END land_write[204]
  PIN land_write[205]
    DIRECTION INPUT ;
    USE SIGNAL ;
    PORT
      LAYER M4 ;
        RECT  0 34.224 0.084 34.248 ;
    END
  END land_write[205]
  PIN land_write[206]
    DIRECTION INPUT ;
    USE SIGNAL ;
    PORT
      LAYER M4 ;
        RECT  0 34.32 0.084 34.344 ;
    END
  END land_write[206]
  PIN land_write[207]
    DIRECTION INPUT ;
    USE SIGNAL ;
    PORT
      LAYER M4 ;
        RECT  0 34.416 0.084 34.44 ;
    END
  END land_write[207]
  PIN land_write[208]
    DIRECTION INPUT ;
    USE SIGNAL ;
    PORT
      LAYER M4 ;
        RECT  0 34.512 0.084 34.536 ;
    END
  END land_write[208]
  PIN land_write[209]
    DIRECTION INPUT ;
    USE SIGNAL ;
    PORT
      LAYER M4 ;
        RECT  0 34.608 0.084 34.632 ;
    END
  END land_write[209]
  PIN land_write[20]
    DIRECTION INPUT ;
    USE SIGNAL ;
    PORT
      LAYER M4 ;
        RECT  0 54.096 0.084 54.12 ;
    END
  END land_write[20]
  PIN land_write[210]
    DIRECTION INPUT ;
    USE SIGNAL ;
    PORT
      LAYER M4 ;
        RECT  0 34.704 0.084 34.728 ;
    END
  END land_write[210]
  PIN land_write[211]
    DIRECTION INPUT ;
    USE SIGNAL ;
    PORT
      LAYER M4 ;
        RECT  0 34.8 0.084 34.824 ;
    END
  END land_write[211]
  PIN land_write[212]
    DIRECTION INPUT ;
    USE SIGNAL ;
    PORT
      LAYER M4 ;
        RECT  0 34.896 0.084 34.92 ;
    END
  END land_write[212]
  PIN land_write[213]
    DIRECTION INPUT ;
    USE SIGNAL ;
    PORT
      LAYER M4 ;
        RECT  0 34.992 0.084 35.016 ;
    END
  END land_write[213]
  PIN land_write[214]
    DIRECTION INPUT ;
    USE SIGNAL ;
    PORT
      LAYER M4 ;
        RECT  0 35.088 0.084 35.112 ;
    END
  END land_write[214]
  PIN land_write[215]
    DIRECTION INPUT ;
    USE SIGNAL ;
    PORT
      LAYER M4 ;
        RECT  0 35.184 0.084 35.208 ;
    END
  END land_write[215]
  PIN land_write[216]
    DIRECTION INPUT ;
    USE SIGNAL ;
    PORT
      LAYER M4 ;
        RECT  0 35.28 0.084 35.304 ;
    END
  END land_write[216]
  PIN land_write[217]
    DIRECTION INPUT ;
    USE SIGNAL ;
    PORT
      LAYER M4 ;
        RECT  0 35.376 0.084 35.4 ;
    END
  END land_write[217]
  PIN land_write[218]
    DIRECTION INPUT ;
    USE SIGNAL ;
    PORT
      LAYER M4 ;
        RECT  0 35.472 0.084 35.496 ;
    END
  END land_write[218]
  PIN land_write[219]
    DIRECTION INPUT ;
    USE SIGNAL ;
    PORT
      LAYER M4 ;
        RECT  0 35.568 0.084 35.592 ;
    END
  END land_write[219]
  PIN land_write[21]
    DIRECTION INPUT ;
    USE SIGNAL ;
    PORT
      LAYER M4 ;
        RECT  0 54.192 0.084 54.216 ;
    END
  END land_write[21]
  PIN land_write[220]
    DIRECTION INPUT ;
    USE SIGNAL ;
    PORT
      LAYER M4 ;
        RECT  0 35.664 0.084 35.688 ;
    END
  END land_write[220]
  PIN land_write[221]
    DIRECTION INPUT ;
    USE SIGNAL ;
    PORT
      LAYER M4 ;
        RECT  0 35.76 0.084 35.784 ;
    END
  END land_write[221]
  PIN land_write[222]
    DIRECTION INPUT ;
    USE SIGNAL ;
    PORT
      LAYER M4 ;
        RECT  0 35.856 0.084 35.88 ;
    END
  END land_write[222]
  PIN land_write[223]
    DIRECTION INPUT ;
    USE SIGNAL ;
    PORT
      LAYER M4 ;
        RECT  0 35.952 0.084 35.976 ;
    END
  END land_write[223]
  PIN land_write[224]
    DIRECTION INPUT ;
    USE SIGNAL ;
    PORT
      LAYER M4 ;
        RECT  0 36.048 0.084 36.072 ;
    END
  END land_write[224]
  PIN land_write[225]
    DIRECTION INPUT ;
    USE SIGNAL ;
    PORT
      LAYER M4 ;
        RECT  0 36.144 0.084 36.168 ;
    END
  END land_write[225]
  PIN land_write[226]
    DIRECTION INPUT ;
    USE SIGNAL ;
    PORT
      LAYER M4 ;
        RECT  0 36.24 0.084 36.264 ;
    END
  END land_write[226]
  PIN land_write[227]
    DIRECTION INPUT ;
    USE SIGNAL ;
    PORT
      LAYER M4 ;
        RECT  0 36.336 0.084 36.36 ;
    END
  END land_write[227]
  PIN land_write[228]
    DIRECTION INPUT ;
    USE SIGNAL ;
    PORT
      LAYER M4 ;
        RECT  0 36.432 0.084 36.456 ;
    END
  END land_write[228]
  PIN land_write[229]
    DIRECTION INPUT ;
    USE SIGNAL ;
    PORT
      LAYER M4 ;
        RECT  0 36.528 0.084 36.552 ;
    END
  END land_write[229]
  PIN land_write[22]
    DIRECTION INPUT ;
    USE SIGNAL ;
    PORT
      LAYER M4 ;
        RECT  0 54.288 0.084 54.312 ;
    END
  END land_write[22]
  PIN land_write[230]
    DIRECTION INPUT ;
    USE SIGNAL ;
    PORT
      LAYER M4 ;
        RECT  0 36.624 0.084 36.648 ;
    END
  END land_write[230]
  PIN land_write[231]
    DIRECTION INPUT ;
    USE SIGNAL ;
    PORT
      LAYER M4 ;
        RECT  0 36.72 0.084 36.744 ;
    END
  END land_write[231]
  PIN land_write[232]
    DIRECTION INPUT ;
    USE SIGNAL ;
    PORT
      LAYER M4 ;
        RECT  0 36.816 0.084 36.84 ;
    END
  END land_write[232]
  PIN land_write[233]
    DIRECTION INPUT ;
    USE SIGNAL ;
    PORT
      LAYER M4 ;
        RECT  0 36.912 0.084 36.936 ;
    END
  END land_write[233]
  PIN land_write[234]
    DIRECTION INPUT ;
    USE SIGNAL ;
    PORT
      LAYER M4 ;
        RECT  0 37.008 0.084 37.032 ;
    END
  END land_write[234]
  PIN land_write[235]
    DIRECTION INPUT ;
    USE SIGNAL ;
    PORT
      LAYER M4 ;
        RECT  0 37.104 0.084 37.128 ;
    END
  END land_write[235]
  PIN land_write[236]
    DIRECTION INPUT ;
    USE SIGNAL ;
    PORT
      LAYER M4 ;
        RECT  0 50.256 0.084 50.28 ;
    END
  END land_write[236]
  PIN land_write[237]
    DIRECTION INPUT ;
    USE SIGNAL ;
    PORT
      LAYER M4 ;
        RECT  0 50.352 0.084 50.376 ;
    END
  END land_write[237]
  PIN land_write[238]
    DIRECTION INPUT ;
    USE SIGNAL ;
    PORT
      LAYER M4 ;
        RECT  0 50.448 0.084 50.472 ;
    END
  END land_write[238]
  PIN land_write[239]
    DIRECTION INPUT ;
    USE SIGNAL ;
    PORT
      LAYER M4 ;
        RECT  0 50.544 0.084 50.568 ;
    END
  END land_write[239]
  PIN land_write[23]
    DIRECTION INPUT ;
    USE SIGNAL ;
    PORT
      LAYER M4 ;
        RECT  0 54.384 0.084 54.408 ;
    END
  END land_write[23]
  PIN land_write[240]
    DIRECTION INPUT ;
    USE SIGNAL ;
    PORT
      LAYER M4 ;
        RECT  0 50.64 0.084 50.664 ;
    END
  END land_write[240]
  PIN land_write[241]
    DIRECTION INPUT ;
    USE SIGNAL ;
    PORT
      LAYER M4 ;
        RECT  0 50.736 0.084 50.76 ;
    END
  END land_write[241]
  PIN land_write[242]
    DIRECTION INPUT ;
    USE SIGNAL ;
    PORT
      LAYER M4 ;
        RECT  0 50.832 0.084 50.856 ;
    END
  END land_write[242]
  PIN land_write[243]
    DIRECTION INPUT ;
    USE SIGNAL ;
    PORT
      LAYER M4 ;
        RECT  0 50.928 0.084 50.952 ;
    END
  END land_write[243]
  PIN land_write[244]
    DIRECTION INPUT ;
    USE SIGNAL ;
    PORT
      LAYER M4 ;
        RECT  0 51.024 0.084 51.048 ;
    END
  END land_write[244]
  PIN land_write[245]
    DIRECTION INPUT ;
    USE SIGNAL ;
    PORT
      LAYER M4 ;
        RECT  0 51.12 0.084 51.144 ;
    END
  END land_write[245]
  PIN land_write[246]
    DIRECTION INPUT ;
    USE SIGNAL ;
    PORT
      LAYER M4 ;
        RECT  0 51.216 0.084 51.24 ;
    END
  END land_write[246]
  PIN land_write[247]
    DIRECTION INPUT ;
    USE SIGNAL ;
    PORT
      LAYER M4 ;
        RECT  0 51.312 0.084 51.336 ;
    END
  END land_write[247]
  PIN land_write[248]
    DIRECTION INPUT ;
    USE SIGNAL ;
    PORT
      LAYER M4 ;
        RECT  0 51.408 0.084 51.432 ;
    END
  END land_write[248]
  PIN land_write[249]
    DIRECTION INPUT ;
    USE SIGNAL ;
    PORT
      LAYER M4 ;
        RECT  0 51.504 0.084 51.528 ;
    END
  END land_write[249]
  PIN land_write[24]
    DIRECTION INPUT ;
    USE SIGNAL ;
    PORT
      LAYER M4 ;
        RECT  0 54.48 0.084 54.504 ;
    END
  END land_write[24]
  PIN land_write[250]
    DIRECTION INPUT ;
    USE SIGNAL ;
    PORT
      LAYER M4 ;
        RECT  0 51.6 0.084 51.624 ;
    END
  END land_write[250]
  PIN land_write[251]
    DIRECTION INPUT ;
    USE SIGNAL ;
    PORT
      LAYER M4 ;
        RECT  0 51.696 0.084 51.72 ;
    END
  END land_write[251]
  PIN land_write[252]
    DIRECTION INPUT ;
    USE SIGNAL ;
    PORT
      LAYER M4 ;
        RECT  0 51.792 0.084 51.816 ;
    END
  END land_write[252]
  PIN land_write[253]
    DIRECTION INPUT ;
    USE SIGNAL ;
    PORT
      LAYER M4 ;
        RECT  0 51.888 0.084 51.912 ;
    END
  END land_write[253]
  PIN land_write[254]
    DIRECTION INPUT ;
    USE SIGNAL ;
    PORT
      LAYER M4 ;
        RECT  0 51.984 0.084 52.008 ;
    END
  END land_write[254]
  PIN land_write[255]
    DIRECTION INPUT ;
    USE SIGNAL ;
    PORT
      LAYER M4 ;
        RECT  0 52.08 0.084 52.104 ;
    END
  END land_write[255]
  PIN land_write[256]
    DIRECTION INPUT ;
    USE SIGNAL ;
    PORT
      LAYER M4 ;
        RECT  0 52.176 0.084 52.2 ;
    END
  END land_write[256]
  PIN land_write[257]
    DIRECTION INPUT ;
    USE SIGNAL ;
    PORT
      LAYER M4 ;
        RECT  0 52.272 0.084 52.296 ;
    END
  END land_write[257]
  PIN land_write[258]
    DIRECTION INPUT ;
    USE SIGNAL ;
    PORT
      LAYER M4 ;
        RECT  0 52.368 0.084 52.392 ;
    END
  END land_write[258]
  PIN land_write[259]
    DIRECTION INPUT ;
    USE SIGNAL ;
    PORT
      LAYER M4 ;
        RECT  0 52.464 0.084 52.488 ;
    END
  END land_write[259]
  PIN land_write[25]
    DIRECTION INPUT ;
    USE SIGNAL ;
    PORT
      LAYER M4 ;
        RECT  0 54.576 0.084 54.6 ;
    END
  END land_write[25]
  PIN land_write[260]
    DIRECTION INPUT ;
    USE SIGNAL ;
    PORT
      LAYER M4 ;
        RECT  0 52.56 0.084 52.584 ;
    END
  END land_write[260]
  PIN land_write[261]
    DIRECTION INPUT ;
    USE SIGNAL ;
    PORT
      LAYER M4 ;
        RECT  0 52.656 0.084 52.68 ;
    END
  END land_write[261]
  PIN land_write[262]
    DIRECTION INPUT ;
    USE SIGNAL ;
    PORT
      LAYER M4 ;
        RECT  0 52.752 0.084 52.776 ;
    END
  END land_write[262]
  PIN land_write[263]
    DIRECTION INPUT ;
    USE SIGNAL ;
    PORT
      LAYER M4 ;
        RECT  0 52.848 0.084 52.872 ;
    END
  END land_write[263]
  PIN land_write[264]
    DIRECTION INPUT ;
    USE SIGNAL ;
    PORT
      LAYER M4 ;
        RECT  0 52.944 0.084 52.968 ;
    END
  END land_write[264]
  PIN land_write[26]
    DIRECTION INPUT ;
    USE SIGNAL ;
    PORT
      LAYER M4 ;
        RECT  0 54.672 0.084 54.696 ;
    END
  END land_write[26]
  PIN land_write[27]
    DIRECTION INPUT ;
    USE SIGNAL ;
    PORT
      LAYER M4 ;
        RECT  0 54.768 0.084 54.792 ;
    END
  END land_write[27]
  PIN land_write[28]
    DIRECTION INPUT ;
    USE SIGNAL ;
    PORT
      LAYER M4 ;
        RECT  0 54.864 0.084 54.888 ;
    END
  END land_write[28]
  PIN land_write[29]
    DIRECTION INPUT ;
    USE SIGNAL ;
    PORT
      LAYER M4 ;
        RECT  0 54.96 0.084 54.984 ;
    END
  END land_write[29]
  PIN land_write[2]
    DIRECTION INPUT ;
    USE SIGNAL ;
    PORT
      LAYER M4 ;
        RECT  0 48.528 0.084 48.552 ;
    END
  END land_write[2]
  PIN land_write[30]
    DIRECTION INPUT ;
    USE SIGNAL ;
    PORT
      LAYER M4 ;
        RECT  0 55.056 0.084 55.08 ;
    END
  END land_write[30]
  PIN land_write[31]
    DIRECTION INPUT ;
    USE SIGNAL ;
    PORT
      LAYER M4 ;
        RECT  0 55.152 0.084 55.176 ;
    END
  END land_write[31]
  PIN land_write[32]
    DIRECTION INPUT ;
    USE SIGNAL ;
    PORT
      LAYER M4 ;
        RECT  0 55.248 0.084 55.272 ;
    END
  END land_write[32]
  PIN land_write[33]
    DIRECTION INPUT ;
    USE SIGNAL ;
    PORT
      LAYER M4 ;
        RECT  0 55.344 0.084 55.368 ;
    END
  END land_write[33]
  PIN land_write[34]
    DIRECTION INPUT ;
    USE SIGNAL ;
    PORT
      LAYER M4 ;
        RECT  0 55.44 0.084 55.464 ;
    END
  END land_write[34]
  PIN land_write[35]
    DIRECTION INPUT ;
    USE SIGNAL ;
    PORT
      LAYER M4 ;
        RECT  0 55.536 0.084 55.56 ;
    END
  END land_write[35]
  PIN land_write[36]
    DIRECTION INPUT ;
    USE SIGNAL ;
    PORT
      LAYER M4 ;
        RECT  0 55.632 0.084 55.656 ;
    END
  END land_write[36]
  PIN land_write[37]
    DIRECTION INPUT ;
    USE SIGNAL ;
    PORT
      LAYER M4 ;
        RECT  0 55.728 0.084 55.752 ;
    END
  END land_write[37]
  PIN land_write[38]
    DIRECTION INPUT ;
    USE SIGNAL ;
    PORT
      LAYER M4 ;
        RECT  0 55.824 0.084 55.848 ;
    END
  END land_write[38]
  PIN land_write[39]
    DIRECTION INPUT ;
    USE SIGNAL ;
    PORT
      LAYER M4 ;
        RECT  0 55.92 0.084 55.944 ;
    END
  END land_write[39]
  PIN land_write[3]
    DIRECTION INPUT ;
    USE SIGNAL ;
    PORT
      LAYER M4 ;
        RECT  0 48.624 0.084 48.648 ;
    END
  END land_write[3]
  PIN land_write[40]
    DIRECTION INPUT ;
    USE SIGNAL ;
    PORT
      LAYER M4 ;
        RECT  0 56.016 0.084 56.04 ;
    END
  END land_write[40]
  PIN land_write[41]
    DIRECTION INPUT ;
    USE SIGNAL ;
    PORT
      LAYER M4 ;
        RECT  0 56.112 0.084 56.136 ;
    END
  END land_write[41]
  PIN land_write[42]
    DIRECTION INPUT ;
    USE SIGNAL ;
    PORT
      LAYER M4 ;
        RECT  0 56.208 0.084 56.232 ;
    END
  END land_write[42]
  PIN land_write[43]
    DIRECTION INPUT ;
    USE SIGNAL ;
    PORT
      LAYER M4 ;
        RECT  0 56.304 0.084 56.328 ;
    END
  END land_write[43]
  PIN land_write[44]
    DIRECTION INPUT ;
    USE SIGNAL ;
    PORT
      LAYER M4 ;
        RECT  0 56.4 0.084 56.424 ;
    END
  END land_write[44]
  PIN land_write[45]
    DIRECTION INPUT ;
    USE SIGNAL ;
    PORT
      LAYER M4 ;
        RECT  0 56.496 0.084 56.52 ;
    END
  END land_write[45]
  PIN land_write[46]
    DIRECTION INPUT ;
    USE SIGNAL ;
    PORT
      LAYER M4 ;
        RECT  0 56.592 0.084 56.616 ;
    END
  END land_write[46]
  PIN land_write[47]
    DIRECTION INPUT ;
    USE SIGNAL ;
    PORT
      LAYER M4 ;
        RECT  0 56.688 0.084 56.712 ;
    END
  END land_write[47]
  PIN land_write[48]
    DIRECTION INPUT ;
    USE SIGNAL ;
    PORT
      LAYER M4 ;
        RECT  0 56.784 0.084 56.808 ;
    END
  END land_write[48]
  PIN land_write[49]
    DIRECTION INPUT ;
    USE SIGNAL ;
    PORT
      LAYER M4 ;
        RECT  0 56.88 0.084 56.904 ;
    END
  END land_write[49]
  PIN land_write[4]
    DIRECTION INPUT ;
    USE SIGNAL ;
    PORT
      LAYER M4 ;
        RECT  0 48.72 0.084 48.744 ;
    END
  END land_write[4]
  PIN land_write[50]
    DIRECTION INPUT ;
    USE SIGNAL ;
    PORT
      LAYER M4 ;
        RECT  0 56.976 0.084 57 ;
    END
  END land_write[50]
  PIN land_write[51]
    DIRECTION INPUT ;
    USE SIGNAL ;
    PORT
      LAYER M4 ;
        RECT  0 57.072 0.084 57.096 ;
    END
  END land_write[51]
  PIN land_write[52]
    DIRECTION INPUT ;
    USE SIGNAL ;
    PORT
      LAYER M4 ;
        RECT  0 57.168 0.084 57.192 ;
    END
  END land_write[52]
  PIN land_write[53]
    DIRECTION INPUT ;
    USE SIGNAL ;
    PORT
      LAYER M4 ;
        RECT  0 57.264 0.084 57.288 ;
    END
  END land_write[53]
  PIN land_write[54]
    DIRECTION INPUT ;
    USE SIGNAL ;
    PORT
      LAYER M4 ;
        RECT  0 57.36 0.084 57.384 ;
    END
  END land_write[54]
  PIN land_write[55]
    DIRECTION INPUT ;
    USE SIGNAL ;
    PORT
      LAYER M4 ;
        RECT  0 57.456 0.084 57.48 ;
    END
  END land_write[55]
  PIN land_write[56]
    DIRECTION INPUT ;
    USE SIGNAL ;
    PORT
      LAYER M4 ;
        RECT  0 57.552 0.084 57.576 ;
    END
  END land_write[56]
  PIN land_write[57]
    DIRECTION INPUT ;
    USE SIGNAL ;
    PORT
      LAYER M4 ;
        RECT  0 57.648 0.084 57.672 ;
    END
  END land_write[57]
  PIN land_write[58]
    DIRECTION INPUT ;
    USE SIGNAL ;
    PORT
      LAYER M4 ;
        RECT  0 57.744 0.084 57.768 ;
    END
  END land_write[58]
  PIN land_write[59]
    DIRECTION INPUT ;
    USE SIGNAL ;
    PORT
      LAYER M4 ;
        RECT  0 57.84 0.084 57.864 ;
    END
  END land_write[59]
  PIN land_write[5]
    DIRECTION INPUT ;
    USE SIGNAL ;
    PORT
      LAYER M4 ;
        RECT  0 48.816 0.084 48.84 ;
    END
  END land_write[5]
  PIN land_write[60]
    DIRECTION INPUT ;
    USE SIGNAL ;
    PORT
      LAYER M4 ;
        RECT  0 57.936 0.084 57.96 ;
    END
  END land_write[60]
  PIN land_write[61]
    DIRECTION INPUT ;
    USE SIGNAL ;
    PORT
      LAYER M4 ;
        RECT  0 58.032 0.084 58.056 ;
    END
  END land_write[61]
  PIN land_write[62]
    DIRECTION INPUT ;
    USE SIGNAL ;
    PORT
      LAYER M4 ;
        RECT  0 58.128 0.084 58.152 ;
    END
  END land_write[62]
  PIN land_write[63]
    DIRECTION INPUT ;
    USE SIGNAL ;
    PORT
      LAYER M4 ;
        RECT  0 58.224 0.084 58.248 ;
    END
  END land_write[63]
  PIN land_write[64]
    DIRECTION INPUT ;
    USE SIGNAL ;
    PORT
      LAYER M4 ;
        RECT  0 58.32 0.084 58.344 ;
    END
  END land_write[64]
  PIN land_write[65]
    DIRECTION INPUT ;
    USE SIGNAL ;
    PORT
      LAYER M4 ;
        RECT  0 58.416 0.084 58.44 ;
    END
  END land_write[65]
  PIN land_write[66]
    DIRECTION INPUT ;
    USE SIGNAL ;
    PORT
      LAYER M4 ;
        RECT  0 58.512 0.084 58.536 ;
    END
  END land_write[66]
  PIN land_write[67]
    DIRECTION INPUT ;
    USE SIGNAL ;
    PORT
      LAYER M4 ;
        RECT  0 58.608 0.084 58.632 ;
    END
  END land_write[67]
  PIN land_write[68]
    DIRECTION INPUT ;
    USE SIGNAL ;
    PORT
      LAYER M4 ;
        RECT  0 58.704 0.084 58.728 ;
    END
  END land_write[68]
  PIN land_write[69]
    DIRECTION INPUT ;
    USE SIGNAL ;
    PORT
      LAYER M4 ;
        RECT  0 58.8 0.084 58.824 ;
    END
  END land_write[69]
  PIN land_write[6]
    DIRECTION INPUT ;
    USE SIGNAL ;
    PORT
      LAYER M4 ;
        RECT  0 48.912 0.084 48.936 ;
    END
  END land_write[6]
  PIN land_write[70]
    DIRECTION INPUT ;
    USE SIGNAL ;
    PORT
      LAYER M4 ;
        RECT  0 58.896 0.084 58.92 ;
    END
  END land_write[70]
  PIN land_write[71]
    DIRECTION INPUT ;
    USE SIGNAL ;
    PORT
      LAYER M4 ;
        RECT  0 58.992 0.084 59.016 ;
    END
  END land_write[71]
  PIN land_write[72]
    DIRECTION INPUT ;
    USE SIGNAL ;
    PORT
      LAYER M4 ;
        RECT  0 59.088 0.084 59.112 ;
    END
  END land_write[72]
  PIN land_write[73]
    DIRECTION INPUT ;
    USE SIGNAL ;
    PORT
      LAYER M4 ;
        RECT  0 59.184 0.084 59.208 ;
    END
  END land_write[73]
  PIN land_write[74]
    DIRECTION INPUT ;
    USE SIGNAL ;
    PORT
      LAYER M4 ;
        RECT  0 59.28 0.084 59.304 ;
    END
  END land_write[74]
  PIN land_write[75]
    DIRECTION INPUT ;
    USE SIGNAL ;
    PORT
      LAYER M4 ;
        RECT  0 59.376 0.084 59.4 ;
    END
  END land_write[75]
  PIN land_write[76]
    DIRECTION INPUT ;
    USE SIGNAL ;
    PORT
      LAYER M4 ;
        RECT  0 59.472 0.084 59.496 ;
    END
  END land_write[76]
  PIN land_write[77]
    DIRECTION INPUT ;
    USE SIGNAL ;
    PORT
      LAYER M4 ;
        RECT  0 59.568 0.084 59.592 ;
    END
  END land_write[77]
  PIN land_write[78]
    DIRECTION INPUT ;
    USE SIGNAL ;
    PORT
      LAYER M4 ;
        RECT  0 59.664 0.084 59.688 ;
    END
  END land_write[78]
  PIN land_write[79]
    DIRECTION INPUT ;
    USE SIGNAL ;
    PORT
      LAYER M4 ;
        RECT  0 59.76 0.084 59.784 ;
    END
  END land_write[79]
  PIN land_write[7]
    DIRECTION INPUT ;
    USE SIGNAL ;
    PORT
      LAYER M4 ;
        RECT  0 49.008 0.084 49.032 ;
    END
  END land_write[7]
  PIN land_write[80]
    DIRECTION INPUT ;
    USE SIGNAL ;
    PORT
      LAYER M4 ;
        RECT  0 59.856 0.084 59.88 ;
    END
  END land_write[80]
  PIN land_write[81]
    DIRECTION INPUT ;
    USE SIGNAL ;
    PORT
      LAYER M4 ;
        RECT  0 59.952 0.084 59.976 ;
    END
  END land_write[81]
  PIN land_write[82]
    DIRECTION INPUT ;
    USE SIGNAL ;
    PORT
      LAYER M4 ;
        RECT  0 60.048 0.084 60.072 ;
    END
  END land_write[82]
  PIN land_write[83]
    DIRECTION INPUT ;
    USE SIGNAL ;
    PORT
      LAYER M4 ;
        RECT  0 60.144 0.084 60.168 ;
    END
  END land_write[83]
  PIN land_write[84]
    DIRECTION INPUT ;
    USE SIGNAL ;
    PORT
      LAYER M4 ;
        RECT  0 60.24 0.084 60.264 ;
    END
  END land_write[84]
  PIN land_write[85]
    DIRECTION INPUT ;
    USE SIGNAL ;
    PORT
      LAYER M4 ;
        RECT  0 60.336 0.084 60.36 ;
    END
  END land_write[85]
  PIN land_write[86]
    DIRECTION INPUT ;
    USE SIGNAL ;
    PORT
      LAYER M4 ;
        RECT  0 60.432 0.084 60.456 ;
    END
  END land_write[86]
  PIN land_write[87]
    DIRECTION INPUT ;
    USE SIGNAL ;
    PORT
      LAYER M4 ;
        RECT  0 60.528 0.084 60.552 ;
    END
  END land_write[87]
  PIN land_write[88]
    DIRECTION INPUT ;
    USE SIGNAL ;
    PORT
      LAYER M4 ;
        RECT  0 60.624 0.084 60.648 ;
    END
  END land_write[88]
  PIN land_write[89]
    DIRECTION INPUT ;
    USE SIGNAL ;
    PORT
      LAYER M4 ;
        RECT  0 60.72 0.084 60.744 ;
    END
  END land_write[89]
  PIN land_write[8]
    DIRECTION INPUT ;
    USE SIGNAL ;
    PORT
      LAYER M4 ;
        RECT  0 49.104 0.084 49.128 ;
    END
  END land_write[8]
  PIN land_write[90]
    DIRECTION INPUT ;
    USE SIGNAL ;
    PORT
      LAYER M4 ;
        RECT  0 60.816 0.084 60.84 ;
    END
  END land_write[90]
  PIN land_write[91]
    DIRECTION INPUT ;
    USE SIGNAL ;
    PORT
      LAYER M4 ;
        RECT  0 60.912 0.084 60.936 ;
    END
  END land_write[91]
  PIN land_write[92]
    DIRECTION INPUT ;
    USE SIGNAL ;
    PORT
      LAYER M4 ;
        RECT  0 61.008 0.084 61.032 ;
    END
  END land_write[92]
  PIN land_write[93]
    DIRECTION INPUT ;
    USE SIGNAL ;
    PORT
      LAYER M4 ;
        RECT  0 61.104 0.084 61.128 ;
    END
  END land_write[93]
  PIN land_write[94]
    DIRECTION INPUT ;
    USE SIGNAL ;
    PORT
      LAYER M4 ;
        RECT  0 61.2 0.084 61.224 ;
    END
  END land_write[94]
  PIN land_write[95]
    DIRECTION INPUT ;
    USE SIGNAL ;
    PORT
      LAYER M4 ;
        RECT  0 61.296 0.084 61.32 ;
    END
  END land_write[95]
  PIN land_write[96]
    DIRECTION INPUT ;
    USE SIGNAL ;
    PORT
      LAYER M4 ;
        RECT  0 61.392 0.084 61.416 ;
    END
  END land_write[96]
  PIN land_write[97]
    DIRECTION INPUT ;
    USE SIGNAL ;
    PORT
      LAYER M4 ;
        RECT  0 61.488 0.084 61.512 ;
    END
  END land_write[97]
  PIN land_write[98]
    DIRECTION INPUT ;
    USE SIGNAL ;
    PORT
      LAYER M4 ;
        RECT  0 61.584 0.084 61.608 ;
    END
  END land_write[98]
  PIN land_write[99]
    DIRECTION INPUT ;
    USE SIGNAL ;
    PORT
      LAYER M4 ;
        RECT  0 61.68 0.084 61.704 ;
    END
  END land_write[99]
  PIN land_write[9]
    DIRECTION INPUT ;
    USE SIGNAL ;
    PORT
      LAYER M4 ;
        RECT  0 49.2 0.084 49.224 ;
    END
  END land_write[9]
  PIN rst_n
    DIRECTION INPUT ;
    USE SIGNAL ;
    PORT
      LAYER M4 ;
        RECT  0 53.04 0.084 53.064 ;
    END
  END rst_n
  PIN source_format[0]
    DIRECTION INPUT ;
    USE SIGNAL ;
    PORT
      LAYER M4 ;
        RECT  0 53.136 0.084 53.16 ;
    END
  END source_format[0]
  PIN source_format[1]
    DIRECTION INPUT ;
    USE SIGNAL ;
    PORT
      LAYER M4 ;
        RECT  0 53.232 0.084 53.256 ;
    END
  END source_format[1]
  PIN source_format[2]
    DIRECTION INPUT ;
    USE SIGNAL ;
    PORT
      LAYER M4 ;
        RECT  0 11.376 0.084 11.4 ;
    END
  END source_format[2]
  PIN source_format[3]
    DIRECTION INPUT ;
    USE SIGNAL ;
    PORT
      LAYER M4 ;
        RECT  0 11.472 0.084 11.496 ;
    END
  END source_format[3]
  PIN source_format[4]
    DIRECTION INPUT ;
    USE SIGNAL ;
    PORT
      LAYER M4 ;
        RECT  0 11.568 0.084 11.592 ;
    END
  END source_format[4]
  PIN source_format[5]
    DIRECTION INPUT ;
    USE SIGNAL ;
    PORT
      LAYER M4 ;
        RECT  0 11.664 0.084 11.688 ;
    END
  END source_format[5]
  PIN source_format[6]
    DIRECTION INPUT ;
    USE SIGNAL ;
    PORT
      LAYER M4 ;
        RECT  0 11.76 0.084 11.784 ;
    END
  END source_format[6]
  PIN VDD
    DIRECTION INOUT ;
    USE POWER ;
    PORT
      LAYER M5 ;
        RECT  213.192 2.151 213.312 86.409 ;
        RECT  207.792 2.151 207.912 86.409 ;
        RECT  202.392 2.151 202.512 86.409 ;
        RECT  196.992 2.151 197.112 86.409 ;
        RECT  191.592 2.151 191.712 86.409 ;
        RECT  186.192 2.151 186.312 86.409 ;
        RECT  180.792 2.151 180.912 86.409 ;
        RECT  175.392 2.151 175.512 86.409 ;
        RECT  169.992 2.151 170.112 86.409 ;
        RECT  164.592 2.151 164.712 86.409 ;
        RECT  159.192 2.151 159.312 86.409 ;
        RECT  153.792 2.151 153.912 86.409 ;
        RECT  148.392 2.151 148.512 86.409 ;
        RECT  142.992 2.151 143.112 86.409 ;
        RECT  137.592 2.151 137.712 86.409 ;
        RECT  132.192 2.151 132.312 86.409 ;
        RECT  126.792 2.151 126.912 86.409 ;
        RECT  121.392 2.151 121.512 86.409 ;
        RECT  115.992 2.151 116.112 86.409 ;
        RECT  110.592 2.151 110.712 86.409 ;
        RECT  105.192 2.151 105.312 86.409 ;
        RECT  99.792 2.151 99.912 86.409 ;
        RECT  94.392 2.151 94.512 86.409 ;
        RECT  88.992 2.151 89.112 86.409 ;
        RECT  83.592 2.151 83.712 86.409 ;
        RECT  78.192 2.151 78.312 86.409 ;
        RECT  72.792 2.151 72.912 86.409 ;
        RECT  67.392 2.151 67.512 86.409 ;
        RECT  61.992 2.151 62.112 86.409 ;
        RECT  56.592 2.151 56.712 86.409 ;
        RECT  51.192 2.151 51.312 86.409 ;
        RECT  45.792 2.151 45.912 86.409 ;
        RECT  40.392 2.151 40.512 86.409 ;
        RECT  34.992 2.151 35.112 86.409 ;
        RECT  29.592 2.151 29.712 86.409 ;
        RECT  24.192 2.151 24.312 86.409 ;
        RECT  18.792 2.151 18.912 86.409 ;
        RECT  13.392 2.151 13.512 86.409 ;
        RECT  7.992 2.151 8.112 86.409 ;
        RECT  2.592 2.151 2.712 86.409 ;
    END
  END VDD
  PIN VSS
    DIRECTION INOUT ;
    USE GROUND ;
    PORT
      LAYER M5 ;
        RECT  213 2.137 213.12 86.423 ;
        RECT  207.6 2.137 207.72 86.423 ;
        RECT  202.2 2.137 202.32 86.423 ;
        RECT  196.8 2.137 196.92 86.423 ;
        RECT  191.4 2.137 191.52 86.423 ;
        RECT  186 2.137 186.12 86.423 ;
        RECT  180.6 2.137 180.72 86.423 ;
        RECT  175.2 2.137 175.32 86.423 ;
        RECT  169.8 2.137 169.92 86.423 ;
        RECT  164.4 2.137 164.52 86.423 ;
        RECT  159 2.137 159.12 86.423 ;
        RECT  153.6 2.137 153.72 86.423 ;
        RECT  148.2 2.137 148.32 86.423 ;
        RECT  142.8 2.137 142.92 86.423 ;
        RECT  137.4 2.137 137.52 86.423 ;
        RECT  132 2.137 132.12 86.423 ;
        RECT  126.6 2.137 126.72 86.423 ;
        RECT  121.2 2.137 121.32 86.423 ;
        RECT  115.8 2.137 115.92 86.423 ;
        RECT  110.4 2.137 110.52 86.423 ;
        RECT  105 2.137 105.12 86.423 ;
        RECT  99.6 2.137 99.72 86.423 ;
        RECT  94.2 2.137 94.32 86.423 ;
        RECT  88.8 2.137 88.92 86.423 ;
        RECT  83.4 2.137 83.52 86.423 ;
        RECT  78 2.137 78.12 86.423 ;
        RECT  72.6 2.137 72.72 86.423 ;
        RECT  67.2 2.137 67.32 86.423 ;
        RECT  61.8 2.137 61.92 86.423 ;
        RECT  56.4 2.137 56.52 86.423 ;
        RECT  51 2.137 51.12 86.423 ;
        RECT  45.6 2.137 45.72 86.423 ;
        RECT  40.2 2.137 40.32 86.423 ;
        RECT  34.8 2.137 34.92 86.423 ;
        RECT  29.4 2.137 29.52 86.423 ;
        RECT  24 2.137 24.12 86.423 ;
        RECT  18.6 2.137 18.72 86.423 ;
        RECT  13.2 2.137 13.32 86.423 ;
        RECT  7.8 2.137 7.92 86.423 ;
        RECT  2.4 2.137 2.52 86.423 ;
    END
  END VSS
  # OT_OBS_CLOSED layer=M5 d_um=1.536 added=622
  OBS
    LAYER RVTN ;
     RECT  2.16 2.16 218.16 2.295 ;
     RECT  2.16 2.565 218.16 2.835 ;
     RECT  2.16 3.105 218.16 3.375 ;
     RECT  2.16 3.645 218.16 3.915 ;
     RECT  2.16 4.185 218.16 4.455 ;
     RECT  2.16 4.725 218.16 4.995 ;
     RECT  2.16 5.265 218.16 5.535 ;
     RECT  2.16 5.805 218.16 6.075 ;
     RECT  2.16 6.345 218.16 6.615 ;
     RECT  2.16 6.885 218.16 7.155 ;
     RECT  2.16 7.425 218.16 7.695 ;
     RECT  2.16 7.965 218.16 8.235 ;
     RECT  2.16 8.505 218.16 8.775 ;
     RECT  2.16 9.045 218.16 9.315 ;
     RECT  2.16 9.585 218.16 9.855 ;
     RECT  2.16 10.125 218.16 10.395 ;
     RECT  2.16 10.665 218.16 10.935 ;
     RECT  2.16 11.205 218.16 11.475 ;
     RECT  2.16 11.745 218.16 12.015 ;
     RECT  2.16 12.285 218.16 12.555 ;
     RECT  2.16 12.825 218.16 13.095 ;
     RECT  2.16 13.365 218.16 13.635 ;
     RECT  2.16 13.905 218.16 14.175 ;
     RECT  2.16 14.445 218.16 14.715 ;
     RECT  2.16 14.985 218.16 15.255 ;
     RECT  2.16 15.525 218.16 15.795 ;
     RECT  2.16 16.065 218.16 16.335 ;
     RECT  2.16 16.605 218.16 16.875 ;
     RECT  2.16 17.145 218.16 17.415 ;
     RECT  2.16 17.685 218.16 17.955 ;
     RECT  2.16 18.225 218.16 18.495 ;
     RECT  2.16 18.765 218.16 19.035 ;
     RECT  2.16 19.305 218.16 19.575 ;
     RECT  2.16 19.845 218.16 20.115 ;
     RECT  2.16 20.385 218.16 20.655 ;
     RECT  2.16 20.925 218.16 21.195 ;
     RECT  2.16 21.465 218.16 21.6 ;
     RECT  2.16 21.6 21.276 21.735 ;
     RECT  198.18 21.6 218.16 21.735 ;
     RECT  2.16 22.005 21.276 22.275 ;
     RECT  198.18 22.005 218.16 22.275 ;
     RECT  2.16 22.545 21.276 22.815 ;
     RECT  198.18 22.545 218.16 22.815 ;
     RECT  2.16 23.085 21.276 23.355 ;
     RECT  198.18 23.085 218.16 23.355 ;
     RECT  2.16 23.625 21.276 23.895 ;
     RECT  198.18 23.625 218.16 23.895 ;
     RECT  2.16 24.165 21.276 24.435 ;
     RECT  198.18 24.165 218.16 24.435 ;
     RECT  2.16 24.705 21.276 24.975 ;
     RECT  198.18 24.705 218.16 24.975 ;
     RECT  2.16 25.245 21.276 25.515 ;
     RECT  198.18 25.245 218.16 25.515 ;
     RECT  2.16 25.785 21.276 26.055 ;
     RECT  198.18 25.785 218.16 26.055 ;
     RECT  2.16 26.325 21.276 26.595 ;
     RECT  198.18 26.325 218.16 26.595 ;
     RECT  2.16 26.865 21.276 27.135 ;
     RECT  198.18 26.865 218.16 27.135 ;
     RECT  2.16 27.405 21.276 27.675 ;
     RECT  198.18 27.405 218.16 27.675 ;
     RECT  2.16 27.945 21.276 28.215 ;
     RECT  198.18 27.945 218.16 28.215 ;
     RECT  2.16 28.485 21.276 28.755 ;
     RECT  198.18 28.485 218.16 28.755 ;
     RECT  2.16 29.025 21.276 29.295 ;
     RECT  198.18 29.025 218.16 29.295 ;
     RECT  2.16 29.565 21.276 29.835 ;
     RECT  198.18 29.565 218.16 29.835 ;
     RECT  2.16 30.105 21.276 30.375 ;
     RECT  198.18 30.105 218.16 30.375 ;
     RECT  2.16 30.645 21.276 30.915 ;
     RECT  198.18 30.645 218.16 30.915 ;
     RECT  2.16 31.185 21.276 31.455 ;
     RECT  198.18 31.185 218.16 31.455 ;
     RECT  2.16 31.725 21.276 31.995 ;
     RECT  198.18 31.725 218.16 31.995 ;
     RECT  2.16 32.265 21.276 32.535 ;
     RECT  198.18 32.265 218.16 32.535 ;
     RECT  2.16 32.805 21.276 33.075 ;
     RECT  198.18 32.805 218.16 33.075 ;
     RECT  2.16 33.345 21.276 33.615 ;
     RECT  198.18 33.345 218.16 33.615 ;
     RECT  2.16 33.885 21.276 34.155 ;
     RECT  198.18 33.885 218.16 34.155 ;
     RECT  2.16 34.425 21.276 34.695 ;
     RECT  198.18 34.425 218.16 34.695 ;
     RECT  2.16 34.965 21.276 35.235 ;
     RECT  198.18 34.965 218.16 35.235 ;
     RECT  2.16 35.505 21.276 35.775 ;
     RECT  198.18 35.505 218.16 35.775 ;
     RECT  2.16 36.045 21.276 36.315 ;
     RECT  198.18 36.045 218.16 36.315 ;
     RECT  2.16 36.585 21.276 36.855 ;
     RECT  198.18 36.585 218.16 36.855 ;
     RECT  2.16 37.125 21.276 37.395 ;
     RECT  198.18 37.125 218.16 37.395 ;
     RECT  2.16 37.665 21.276 37.935 ;
     RECT  198.18 37.665 218.16 37.935 ;
     RECT  2.16 38.205 21.276 38.475 ;
     RECT  198.18 38.205 218.16 38.475 ;
     RECT  2.16 38.745 21.276 39.015 ;
     RECT  198.18 38.745 218.16 39.015 ;
     RECT  2.16 39.285 21.276 39.555 ;
     RECT  198.18 39.285 218.16 39.555 ;
     RECT  2.16 39.825 21.276 40.095 ;
     RECT  198.18 39.825 218.16 40.095 ;
     RECT  2.16 40.365 21.276 40.635 ;
     RECT  198.18 40.365 218.16 40.635 ;
     RECT  2.16 40.905 21.276 41.175 ;
     RECT  198.18 40.905 218.16 41.175 ;
     RECT  2.16 41.445 21.276 41.715 ;
     RECT  198.18 41.445 218.16 41.715 ;
     RECT  2.16 41.985 21.276 42.255 ;
     RECT  198.18 41.985 218.16 42.255 ;
     RECT  2.16 42.525 21.276 42.795 ;
     RECT  198.18 42.525 218.16 42.795 ;
     RECT  2.16 43.065 21.276 43.335 ;
     RECT  198.18 43.065 218.16 43.335 ;
     RECT  2.16 43.605 21.276 43.875 ;
     RECT  198.18 43.605 218.16 43.875 ;
     RECT  2.16 44.145 21.276 44.415 ;
     RECT  198.18 44.145 218.16 44.415 ;
     RECT  2.16 44.685 21.276 44.955 ;
     RECT  198.18 44.685 218.16 44.955 ;
     RECT  2.16 45.225 21.276 45.495 ;
     RECT  198.18 45.225 218.16 45.495 ;
     RECT  2.16 45.765 21.276 46.035 ;
     RECT  198.18 45.765 218.16 46.035 ;
     RECT  2.16 46.305 21.276 46.575 ;
     RECT  198.18 46.305 218.16 46.575 ;
     RECT  2.16 46.845 21.276 47.115 ;
     RECT  198.18 46.845 218.16 47.115 ;
     RECT  2.16 47.385 21.276 47.655 ;
     RECT  198.18 47.385 218.16 47.655 ;
     RECT  2.16 47.925 21.276 48.195 ;
     RECT  198.18 47.925 218.16 48.195 ;
     RECT  2.16 48.465 21.276 48.735 ;
     RECT  198.18 48.465 218.16 48.735 ;
     RECT  2.16 49.005 21.276 49.275 ;
     RECT  198.18 49.005 218.16 49.275 ;
     RECT  2.16 49.545 21.276 49.815 ;
     RECT  198.18 49.545 218.16 49.815 ;
     RECT  2.16 50.085 21.276 50.355 ;
     RECT  198.18 50.085 218.16 50.355 ;
     RECT  2.16 50.625 21.276 50.895 ;
     RECT  198.18 50.625 218.16 50.895 ;
     RECT  2.16 51.165 21.276 51.435 ;
     RECT  198.18 51.165 218.16 51.435 ;
     RECT  2.16 51.705 21.276 51.975 ;
     RECT  198.18 51.705 218.16 51.975 ;
     RECT  2.16 52.245 21.276 52.515 ;
     RECT  198.18 52.245 218.16 52.515 ;
     RECT  2.16 52.785 21.276 53.055 ;
     RECT  198.18 52.785 218.16 53.055 ;
     RECT  2.16 53.325 21.276 53.595 ;
     RECT  198.18 53.325 218.16 53.595 ;
     RECT  2.16 53.865 21.276 54.135 ;
     RECT  198.18 53.865 218.16 54.135 ;
     RECT  2.16 54.405 21.276 54.675 ;
     RECT  198.18 54.405 218.16 54.675 ;
     RECT  2.16 54.945 21.276 55.215 ;
     RECT  198.18 54.945 218.16 55.215 ;
     RECT  2.16 55.485 21.276 55.755 ;
     RECT  198.18 55.485 218.16 55.755 ;
     RECT  2.16 56.025 21.276 56.295 ;
     RECT  198.18 56.025 218.16 56.295 ;
     RECT  2.16 56.565 21.276 56.835 ;
     RECT  198.18 56.565 218.16 56.835 ;
     RECT  2.16 57.105 21.276 57.375 ;
     RECT  198.18 57.105 218.16 57.375 ;
     RECT  2.16 57.645 21.276 57.915 ;
     RECT  198.18 57.645 218.16 57.915 ;
     RECT  2.16 58.185 21.276 58.455 ;
     RECT  198.18 58.185 218.16 58.455 ;
     RECT  2.16 58.725 21.276 58.995 ;
     RECT  198.18 58.725 218.16 58.995 ;
     RECT  2.16 59.265 21.276 59.535 ;
     RECT  198.18 59.265 218.16 59.535 ;
     RECT  2.16 59.805 21.276 60.075 ;
     RECT  198.18 59.805 218.16 60.075 ;
     RECT  2.16 60.345 21.276 60.615 ;
     RECT  198.18 60.345 218.16 60.615 ;
     RECT  2.16 60.885 21.276 61.155 ;
     RECT  198.18 60.885 218.16 61.155 ;
     RECT  2.16 61.425 21.276 61.695 ;
     RECT  198.18 61.425 218.16 61.695 ;
     RECT  2.16 61.965 21.276 62.235 ;
     RECT  198.18 61.965 218.16 62.235 ;
     RECT  2.16 62.505 21.276 62.775 ;
     RECT  198.18 62.505 218.16 62.775 ;
     RECT  2.16 63.045 21.276 63.315 ;
     RECT  198.18 63.045 218.16 63.315 ;
     RECT  2.16 63.585 21.276 63.855 ;
     RECT  198.18 63.585 218.16 63.855 ;
     RECT  2.16 64.125 21.276 64.395 ;
     RECT  198.18 64.125 218.16 64.395 ;
     RECT  2.16 64.665 21.276 64.935 ;
     RECT  198.18 64.665 218.16 64.935 ;
     RECT  2.16 65.205 21.276 65.475 ;
     RECT  198.18 65.205 218.16 65.475 ;
     RECT  2.16 65.745 21.276 66.015 ;
     RECT  198.18 65.745 218.16 66.015 ;
     RECT  2.16 66.285 21.276 66.555 ;
     RECT  198.18 66.285 218.16 66.555 ;
     RECT  2.16 66.825 21.276 66.96 ;
     RECT  198.18 66.825 218.16 66.96 ;
     RECT  2.16 66.96 218.16 67.095 ;
     RECT  2.16 67.365 218.16 67.635 ;
     RECT  2.16 67.905 218.16 68.175 ;
     RECT  2.16 68.445 218.16 68.715 ;
     RECT  2.16 68.985 218.16 69.255 ;
     RECT  2.16 69.525 218.16 69.795 ;
     RECT  2.16 70.065 218.16 70.335 ;
     RECT  2.16 70.605 218.16 70.875 ;
     RECT  2.16 71.145 218.16 71.415 ;
     RECT  2.16 71.685 218.16 71.955 ;
     RECT  2.16 72.225 218.16 72.495 ;
     RECT  2.16 72.765 218.16 73.035 ;
     RECT  2.16 73.305 218.16 73.575 ;
     RECT  2.16 73.845 218.16 74.115 ;
     RECT  2.16 74.385 218.16 74.655 ;
     RECT  2.16 74.925 218.16 75.195 ;
     RECT  2.16 75.465 218.16 75.735 ;
     RECT  2.16 76.005 218.16 76.275 ;
     RECT  2.16 76.545 218.16 76.815 ;
     RECT  2.16 77.085 218.16 77.355 ;
     RECT  2.16 77.625 218.16 77.895 ;
     RECT  2.16 78.165 218.16 78.435 ;
     RECT  2.16 78.705 218.16 78.975 ;
     RECT  2.16 79.245 218.16 79.515 ;
     RECT  2.16 79.785 218.16 80.055 ;
     RECT  2.16 80.325 218.16 80.595 ;
     RECT  2.16 80.865 218.16 81.135 ;
     RECT  2.16 81.405 218.16 81.675 ;
     RECT  2.16 81.945 218.16 82.215 ;
     RECT  2.16 82.485 218.16 82.755 ;
     RECT  2.16 83.025 218.16 83.295 ;
     RECT  2.16 83.565 218.16 83.835 ;
     RECT  2.16 84.105 218.16 84.375 ;
     RECT  2.16 84.645 218.16 84.915 ;
     RECT  2.16 85.185 218.16 85.455 ;
     RECT  2.16 85.725 218.16 85.995 ;
     RECT  2.16 86.265 218.16 86.4 ;
    LAYER RVTP ;
     RECT  2.16 2.295 218.16 2.565 ;
     RECT  2.16 2.835 218.16 3.105 ;
     RECT  2.16 3.375 218.16 3.645 ;
     RECT  2.16 3.915 218.16 4.185 ;
     RECT  2.16 4.455 218.16 4.725 ;
     RECT  2.16 4.995 218.16 5.265 ;
     RECT  2.16 5.535 218.16 5.805 ;
     RECT  2.16 6.075 218.16 6.345 ;
     RECT  2.16 6.615 218.16 6.885 ;
     RECT  2.16 7.155 218.16 7.425 ;
     RECT  2.16 7.695 218.16 7.965 ;
     RECT  2.16 8.235 218.16 8.505 ;
     RECT  2.16 8.775 218.16 9.045 ;
     RECT  2.16 9.315 218.16 9.585 ;
     RECT  2.16 9.855 218.16 10.125 ;
     RECT  2.16 10.395 218.16 10.665 ;
     RECT  2.16 10.935 218.16 11.205 ;
     RECT  2.16 11.475 218.16 11.745 ;
     RECT  2.16 12.015 218.16 12.285 ;
     RECT  2.16 12.555 218.16 12.825 ;
     RECT  2.16 13.095 218.16 13.365 ;
     RECT  2.16 13.635 218.16 13.905 ;
     RECT  2.16 14.175 218.16 14.445 ;
     RECT  2.16 14.715 218.16 14.985 ;
     RECT  2.16 15.255 218.16 15.525 ;
     RECT  2.16 15.795 218.16 16.065 ;
     RECT  2.16 16.335 218.16 16.605 ;
     RECT  2.16 16.875 218.16 17.145 ;
     RECT  2.16 17.415 218.16 17.685 ;
     RECT  2.16 17.955 218.16 18.225 ;
     RECT  2.16 18.495 218.16 18.765 ;
     RECT  2.16 19.035 218.16 19.305 ;
     RECT  2.16 19.575 218.16 19.845 ;
     RECT  2.16 20.115 218.16 20.385 ;
     RECT  2.16 20.655 218.16 20.925 ;
     RECT  2.16 21.195 218.16 21.465 ;
     RECT  2.16 21.735 21.276 22.005 ;
     RECT  198.18 21.735 218.16 22.005 ;
     RECT  2.16 22.275 21.276 22.545 ;
     RECT  198.18 22.275 218.16 22.545 ;
     RECT  2.16 22.815 21.276 23.085 ;
     RECT  198.18 22.815 218.16 23.085 ;
     RECT  2.16 23.355 21.276 23.625 ;
     RECT  198.18 23.355 218.16 23.625 ;
     RECT  2.16 23.895 21.276 24.165 ;
     RECT  198.18 23.895 218.16 24.165 ;
     RECT  2.16 24.435 21.276 24.705 ;
     RECT  198.18 24.435 218.16 24.705 ;
     RECT  2.16 24.975 21.276 25.245 ;
     RECT  198.18 24.975 218.16 25.245 ;
     RECT  2.16 25.515 21.276 25.785 ;
     RECT  198.18 25.515 218.16 25.785 ;
     RECT  2.16 26.055 21.276 26.325 ;
     RECT  198.18 26.055 218.16 26.325 ;
     RECT  2.16 26.595 21.276 26.865 ;
     RECT  198.18 26.595 218.16 26.865 ;
     RECT  2.16 27.135 21.276 27.405 ;
     RECT  198.18 27.135 218.16 27.405 ;
     RECT  2.16 27.675 21.276 27.945 ;
     RECT  198.18 27.675 218.16 27.945 ;
     RECT  2.16 28.215 21.276 28.485 ;
     RECT  198.18 28.215 218.16 28.485 ;
     RECT  2.16 28.755 21.276 29.025 ;
     RECT  198.18 28.755 218.16 29.025 ;
     RECT  2.16 29.295 21.276 29.565 ;
     RECT  198.18 29.295 218.16 29.565 ;
     RECT  2.16 29.835 21.276 30.105 ;
     RECT  198.18 29.835 218.16 30.105 ;
     RECT  2.16 30.375 21.276 30.645 ;
     RECT  198.18 30.375 218.16 30.645 ;
     RECT  2.16 30.915 21.276 31.185 ;
     RECT  198.18 30.915 218.16 31.185 ;
     RECT  2.16 31.455 21.276 31.725 ;
     RECT  198.18 31.455 218.16 31.725 ;
     RECT  2.16 31.995 21.276 32.265 ;
     RECT  198.18 31.995 218.16 32.265 ;
     RECT  2.16 32.535 21.276 32.805 ;
     RECT  198.18 32.535 218.16 32.805 ;
     RECT  2.16 33.075 21.276 33.345 ;
     RECT  198.18 33.075 218.16 33.345 ;
     RECT  2.16 33.615 21.276 33.885 ;
     RECT  198.18 33.615 218.16 33.885 ;
     RECT  2.16 34.155 21.276 34.425 ;
     RECT  198.18 34.155 218.16 34.425 ;
     RECT  2.16 34.695 21.276 34.965 ;
     RECT  198.18 34.695 218.16 34.965 ;
     RECT  2.16 35.235 21.276 35.505 ;
     RECT  198.18 35.235 218.16 35.505 ;
     RECT  2.16 35.775 21.276 36.045 ;
     RECT  198.18 35.775 218.16 36.045 ;
     RECT  2.16 36.315 21.276 36.585 ;
     RECT  198.18 36.315 218.16 36.585 ;
     RECT  2.16 36.855 21.276 37.125 ;
     RECT  198.18 36.855 218.16 37.125 ;
     RECT  2.16 37.395 21.276 37.665 ;
     RECT  198.18 37.395 218.16 37.665 ;
     RECT  2.16 37.935 21.276 38.205 ;
     RECT  198.18 37.935 218.16 38.205 ;
     RECT  2.16 38.475 21.276 38.745 ;
     RECT  198.18 38.475 218.16 38.745 ;
     RECT  2.16 39.015 21.276 39.285 ;
     RECT  198.18 39.015 218.16 39.285 ;
     RECT  2.16 39.555 21.276 39.825 ;
     RECT  198.18 39.555 218.16 39.825 ;
     RECT  2.16 40.095 21.276 40.365 ;
     RECT  198.18 40.095 218.16 40.365 ;
     RECT  2.16 40.635 21.276 40.905 ;
     RECT  198.18 40.635 218.16 40.905 ;
     RECT  2.16 41.175 21.276 41.445 ;
     RECT  198.18 41.175 218.16 41.445 ;
     RECT  2.16 41.715 21.276 41.985 ;
     RECT  198.18 41.715 218.16 41.985 ;
     RECT  2.16 42.255 21.276 42.525 ;
     RECT  198.18 42.255 218.16 42.525 ;
     RECT  2.16 42.795 21.276 43.065 ;
     RECT  198.18 42.795 218.16 43.065 ;
     RECT  2.16 43.335 21.276 43.605 ;
     RECT  198.18 43.335 218.16 43.605 ;
     RECT  2.16 43.875 21.276 44.145 ;
     RECT  198.18 43.875 218.16 44.145 ;
     RECT  2.16 44.415 21.276 44.685 ;
     RECT  198.18 44.415 218.16 44.685 ;
     RECT  2.16 44.955 21.276 45.225 ;
     RECT  198.18 44.955 218.16 45.225 ;
     RECT  2.16 45.495 21.276 45.765 ;
     RECT  198.18 45.495 218.16 45.765 ;
     RECT  2.16 46.035 21.276 46.305 ;
     RECT  198.18 46.035 218.16 46.305 ;
     RECT  2.16 46.575 21.276 46.845 ;
     RECT  198.18 46.575 218.16 46.845 ;
     RECT  2.16 47.115 21.276 47.385 ;
     RECT  198.18 47.115 218.16 47.385 ;
     RECT  2.16 47.655 21.276 47.925 ;
     RECT  198.18 47.655 218.16 47.925 ;
     RECT  2.16 48.195 21.276 48.465 ;
     RECT  198.18 48.195 218.16 48.465 ;
     RECT  2.16 48.735 21.276 49.005 ;
     RECT  198.18 48.735 218.16 49.005 ;
     RECT  2.16 49.275 21.276 49.545 ;
     RECT  198.18 49.275 218.16 49.545 ;
     RECT  2.16 49.815 21.276 50.085 ;
     RECT  198.18 49.815 218.16 50.085 ;
     RECT  2.16 50.355 21.276 50.625 ;
     RECT  198.18 50.355 218.16 50.625 ;
     RECT  2.16 50.895 21.276 51.165 ;
     RECT  198.18 50.895 218.16 51.165 ;
     RECT  2.16 51.435 21.276 51.705 ;
     RECT  198.18 51.435 218.16 51.705 ;
     RECT  2.16 51.975 21.276 52.245 ;
     RECT  198.18 51.975 218.16 52.245 ;
     RECT  2.16 52.515 21.276 52.785 ;
     RECT  198.18 52.515 218.16 52.785 ;
     RECT  2.16 53.055 21.276 53.325 ;
     RECT  198.18 53.055 218.16 53.325 ;
     RECT  2.16 53.595 21.276 53.865 ;
     RECT  198.18 53.595 218.16 53.865 ;
     RECT  2.16 54.135 21.276 54.405 ;
     RECT  198.18 54.135 218.16 54.405 ;
     RECT  2.16 54.675 21.276 54.945 ;
     RECT  198.18 54.675 218.16 54.945 ;
     RECT  2.16 55.215 21.276 55.485 ;
     RECT  198.18 55.215 218.16 55.485 ;
     RECT  2.16 55.755 21.276 56.025 ;
     RECT  198.18 55.755 218.16 56.025 ;
     RECT  2.16 56.295 21.276 56.565 ;
     RECT  198.18 56.295 218.16 56.565 ;
     RECT  2.16 56.835 21.276 57.105 ;
     RECT  198.18 56.835 218.16 57.105 ;
     RECT  2.16 57.375 21.276 57.645 ;
     RECT  198.18 57.375 218.16 57.645 ;
     RECT  2.16 57.915 21.276 58.185 ;
     RECT  198.18 57.915 218.16 58.185 ;
     RECT  2.16 58.455 21.276 58.725 ;
     RECT  198.18 58.455 218.16 58.725 ;
     RECT  2.16 58.995 21.276 59.265 ;
     RECT  198.18 58.995 218.16 59.265 ;
     RECT  2.16 59.535 21.276 59.805 ;
     RECT  198.18 59.535 218.16 59.805 ;
     RECT  2.16 60.075 21.276 60.345 ;
     RECT  198.18 60.075 218.16 60.345 ;
     RECT  2.16 60.615 21.276 60.885 ;
     RECT  198.18 60.615 218.16 60.885 ;
     RECT  2.16 61.155 21.276 61.425 ;
     RECT  198.18 61.155 218.16 61.425 ;
     RECT  2.16 61.695 21.276 61.965 ;
     RECT  198.18 61.695 218.16 61.965 ;
     RECT  2.16 62.235 21.276 62.505 ;
     RECT  198.18 62.235 218.16 62.505 ;
     RECT  2.16 62.775 21.276 63.045 ;
     RECT  198.18 62.775 218.16 63.045 ;
     RECT  2.16 63.315 21.276 63.585 ;
     RECT  198.18 63.315 218.16 63.585 ;
     RECT  2.16 63.855 21.276 64.125 ;
     RECT  198.18 63.855 218.16 64.125 ;
     RECT  2.16 64.395 21.276 64.665 ;
     RECT  198.18 64.395 218.16 64.665 ;
     RECT  2.16 64.935 21.276 65.205 ;
     RECT  198.18 64.935 218.16 65.205 ;
     RECT  2.16 65.475 21.276 65.745 ;
     RECT  198.18 65.475 218.16 65.745 ;
     RECT  2.16 66.015 21.276 66.285 ;
     RECT  198.18 66.015 218.16 66.285 ;
     RECT  2.16 66.555 21.276 66.825 ;
     RECT  198.18 66.555 218.16 66.825 ;
     RECT  2.16 67.095 218.16 67.365 ;
     RECT  2.16 67.635 218.16 67.905 ;
     RECT  2.16 68.175 218.16 68.445 ;
     RECT  2.16 68.715 218.16 68.985 ;
     RECT  2.16 69.255 218.16 69.525 ;
     RECT  2.16 69.795 218.16 70.065 ;
     RECT  2.16 70.335 218.16 70.605 ;
     RECT  2.16 70.875 218.16 71.145 ;
     RECT  2.16 71.415 218.16 71.685 ;
     RECT  2.16 71.955 218.16 72.225 ;
     RECT  2.16 72.495 218.16 72.765 ;
     RECT  2.16 73.035 218.16 73.305 ;
     RECT  2.16 73.575 218.16 73.845 ;
     RECT  2.16 74.115 218.16 74.385 ;
     RECT  2.16 74.655 218.16 74.925 ;
     RECT  2.16 75.195 218.16 75.465 ;
     RECT  2.16 75.735 218.16 76.005 ;
     RECT  2.16 76.275 218.16 76.545 ;
     RECT  2.16 76.815 218.16 77.085 ;
     RECT  2.16 77.355 218.16 77.625 ;
     RECT  2.16 77.895 218.16 78.165 ;
     RECT  2.16 78.435 218.16 78.705 ;
     RECT  2.16 78.975 218.16 79.245 ;
     RECT  2.16 79.515 218.16 79.785 ;
     RECT  2.16 80.055 218.16 80.325 ;
     RECT  2.16 80.595 218.16 80.865 ;
     RECT  2.16 81.135 218.16 81.405 ;
     RECT  2.16 81.675 218.16 81.945 ;
     RECT  2.16 82.215 218.16 82.485 ;
     RECT  2.16 82.755 218.16 83.025 ;
     RECT  2.16 83.295 218.16 83.565 ;
     RECT  2.16 83.835 218.16 84.105 ;
     RECT  2.16 84.375 218.16 84.645 ;
     RECT  2.16 84.915 218.16 85.185 ;
     RECT  2.16 85.455 218.16 85.725 ;
     RECT  2.16 85.995 218.16 86.265 ;
    LAYER M1 ;
     RECT  2.16 2.151 218.16 21.609 ;
     RECT  23.328 23.76 196.128 64.8 ;
     RECT  2.16 21.609 21.276 66.951 ;
     RECT  198.18 21.609 218.16 66.951 ;
     RECT  2.16 66.951 218.16 86.409 ;
    LAYER M2 ;
     RECT  0.103 3.186 0.139 3.672 ;
     RECT  0.103 4.536 0.139 4.554 ;
     RECT  0.103 8.316 0.139 8.874 ;
     RECT  0.103 11.952 0.139 12.204 ;
     RECT  0.103 16.416 0.139 16.434 ;
     RECT  0.103 18.432 0.139 19.872 ;
     RECT  0.103 21.546 0.139 21.564 ;
     RECT  0.103 24.246 0.139 24.264 ;
     RECT  0.103 26.406 0.139 26.424 ;
     RECT  0.103 32.346 0.139 33.84 ;
     RECT  0.103 34.668 0.139 34.92 ;
     RECT  0.103 47.322 0.139 47.34 ;
     RECT  0.103 49.86 0.139 49.878 ;
     RECT  0.103 51.102 0.139 51.93 ;
     RECT  0.103 53.568 0.139 53.586 ;
     RECT  0.103 55.422 0.139 60.57 ;
     RECT  0.103 61.434 0.139 64.62 ;
     RECT  0.139 18.432 0.175 20.214 ;
     RECT  0.139 46.512 0.175 47.34 ;
     RECT  0.139 48.672 0.175 51.93 ;
     RECT  0.139 61.434 0.175 64.89 ;
     RECT  0.175 18.432 0.203 20.412 ;
     RECT  0.103 23.094 0.203 23.112 ;
     RECT  0.103 29.808 0.203 29.826 ;
     RECT  0.103 45.306 0.203 45.414 ;
     RECT  0.139 3.186 0.211 4.554 ;
     RECT  0.103 5.616 0.211 7.146 ;
     RECT  0.139 21.366 0.211 21.564 ;
     RECT  0.139 26.406 0.211 26.658 ;
     RECT  0.103 27.846 0.211 28.314 ;
     RECT  0.103 35.82 0.211 39.618 ;
     RECT  0.103 40.572 0.211 40.86 ;
     RECT  0.103 41.922 0.211 44.244 ;
     RECT  0.203 18.576 0.239 20.412 ;
     RECT  0.211 26.406 0.239 28.314 ;
     RECT  0.175 46.512 0.247 47.376 ;
     RECT  0.175 48.132 0.247 51.93 ;
     RECT  0.211 2.574 0.319 7.146 ;
     RECT  0.319 2.466 0.419 7.146 ;
     RECT  0.211 21.366 0.419 21.726 ;
     RECT  0.139 8.316 0.427 9.072 ;
     RECT  0.103 9.936 0.427 9.954 ;
     RECT  0.427 8.316 0.499 9.954 ;
     RECT  0.103 13.68 0.499 13.932 ;
     RECT  0.175 14.796 0.499 14.814 ;
     RECT  0.139 16.416 0.499 16.524 ;
     RECT  0.139 32.202 0.499 34.92 ;
     RECT  0.419 2.574 0.535 7.146 ;
     RECT  0.499 8.316 0.535 10.764 ;
     RECT  0.139 11.682 0.535 12.204 ;
     RECT  0.499 13.446 0.535 13.932 ;
     RECT  0.139 23.904 0.535 24.264 ;
     RECT  0.499 31.23 0.535 34.92 ;
     RECT  0.211 35.82 0.535 44.244 ;
     RECT  0.203 45.306 0.535 45.324 ;
     RECT  0.247 46.512 0.535 51.93 ;
     RECT  0.103 52.758 0.535 52.776 ;
     RECT  0.139 53.568 0.535 60.57 ;
     RECT  0.175 61.362 0.535 64.89 ;
     RECT  0.535 2.574 1.147 12.312 ;
     RECT  0.535 13.374 1.147 13.932 ;
     RECT  0.499 14.796 1.147 16.524 ;
     RECT  0.535 17.496 1.147 17.514 ;
     RECT  0.239 26.406 1.147 26.424 ;
     RECT  0.499 30.186 1.147 30.204 ;
     RECT  0.535 31.23 1.147 44.244 ;
     RECT  0.535 46.512 1.147 65.034 ;
     RECT  1.147 17.424 1.183 17.514 ;
     RECT  0.239 18.576 1.183 18.594 ;
     RECT  0.239 27.216 1.183 28.314 ;
     RECT  0.103 67.032 1.183 67.05 ;
     RECT  0.419 21.366 1.219 21.564 ;
     RECT  1.147 22.554 1.219 22.572 ;
     RECT  1.183 27.216 1.219 28.782 ;
     RECT  1.147 30.186 1.255 44.244 ;
     RECT  0.535 45.234 1.291 45.324 ;
     RECT  1.147 46.512 1.291 65.43 ;
     RECT  1.183 17.424 1.399 18.594 ;
     RECT  0.535 23.904 1.399 24.462 ;
     RECT  1.219 21.366 1.723 22.572 ;
     RECT  1.147 2.574 2.16 16.524 ;
     RECT  1.399 17.424 2.16 18.792 ;
     RECT  0.239 20.394 2.16 20.412 ;
     RECT  1.723 21.366 2.16 22.806 ;
     RECT  1.399 23.904 2.16 25.002 ;
     RECT  1.147 26.064 2.16 26.424 ;
     RECT  1.219 27.216 2.16 29.124 ;
     RECT  1.255 29.916 2.16 44.244 ;
     RECT  1.291 45.234 2.16 65.43 ;
     RECT  1.183 66.492 2.16 67.05 ;
     RECT  0.823 67.842 2.16 67.86 ;
     RECT  2.335 1.341 2.839 1.359 ;
     RECT  2.16 2.151 2.839 86.409 ;
     RECT  2.839 1.341 6.475 86.409 ;
     RECT  6.475 1.152 6.683 86.409 ;
     RECT  6.683 1.341 7.699 86.409 ;
     RECT  7.699 0.801 8.851 86.409 ;
     RECT  8.851 0.531 10.039 86.409 ;
     RECT  10.039 0.486 11.839 86.409 ;
     RECT  11.839 0.45 18.355 86.409 ;
     RECT  18.355 0.261 21.276 86.409 ;
     RECT  21.276 40.914 21.551 40.932 ;
     RECT  21.276 34.776 21.695 35.496 ;
     RECT  21.276 49.554 21.731 51.804 ;
     RECT  21.731 49.554 21.767 51.156 ;
     RECT  21.276 33.084 21.875 33.102 ;
     RECT  21.695 34.866 22.019 35.496 ;
     RECT  22.019 35.478 22.055 35.496 ;
     RECT  21.276 48.636 22.135 48.654 ;
     RECT  21.276 0.261 22.235 27.126 ;
     RECT  21.767 49.554 22.235 50.886 ;
     RECT  21.276 52.686 22.235 58.752 ;
     RECT  21.276 59.976 22.235 62.838 ;
     RECT  21.276 42.84 22.271 42.858 ;
     RECT  21.276 46.746 22.271 47.304 ;
     RECT  22.235 49.554 22.271 50.382 ;
     RECT  21.276 45.738 22.343 45.756 ;
     RECT  22.271 49.554 22.343 50.148 ;
     RECT  21.276 27.954 22.351 27.972 ;
     RECT  22.279 30.852 22.379 30.87 ;
     RECT  22.135 48.438 22.379 48.654 ;
     RECT  22.343 49.896 22.415 50.148 ;
     RECT  22.351 27.954 22.451 28.512 ;
     RECT  21.276 39.6 22.451 39.618 ;
     RECT  22.235 26.766 22.487 27.126 ;
     RECT  22.379 48.438 22.487 48.456 ;
     RECT  22.271 47.286 22.523 47.304 ;
     RECT  22.235 52.686 22.523 55.17 ;
     RECT  22.235 56.106 22.523 58.752 ;
     RECT  22.235 61.362 22.523 62.838 ;
     RECT  21.276 63.756 22.523 86.409 ;
     RECT  22.235 59.976 22.999 60.606 ;
     RECT  22.523 61.362 22.999 62.604 ;
     RECT  22.963 30.114 23.179 30.744 ;
     RECT  22.235 0.261 23.328 25.659 ;
     RECT  22.487 26.766 23.328 26.784 ;
     RECT  22.451 28.494 23.328 28.512 ;
     RECT  23.179 30.114 23.328 30.834 ;
     RECT  21.276 33.894 23.328 33.912 ;
     RECT  23.071 34.776 23.328 34.794 ;
     RECT  23.071 37.098 23.328 37.116 ;
     RECT  22.415 50.13 23.328 50.148 ;
     RECT  22.523 52.686 23.328 53.82 ;
     RECT  22.523 54.576 23.328 55.17 ;
     RECT  22.523 56.106 23.328 58.14 ;
     RECT  22.999 59.976 23.328 62.604 ;
     RECT  22.523 63.756 23.328 63.774 ;
     RECT  22.523 64.566 23.328 86.409 ;
     RECT  23.328 0.261 81.635 86.409 ;
     RECT  81.635 0.306 95.243 86.409 ;
     RECT  95.243 0.342 102.947 86.409 ;
     RECT  102.947 0.531 104.747 86.409 ;
     RECT  104.747 0.531 105.539 0.864 ;
     RECT  105.539 0.531 105.755 0.549 ;
     RECT  104.747 2.151 107.023 86.409 ;
     RECT  107.023 2.106 107.663 86.409 ;
     RECT  107.663 2.151 112.307 86.409 ;
     RECT  112.307 2.151 130.783 23.004 ;
     RECT  112.307 23.76 130.783 86.409 ;
     RECT  130.783 2.151 196.128 86.409 ;
     RECT  196.128 35.901 196.259 35.919 ;
     RECT  196.128 30.276 196.295 30.978 ;
     RECT  196.295 30.96 196.367 30.978 ;
     RECT  196.128 28.728 196.439 28.746 ;
     RECT  196.128 26.721 197.015 26.739 ;
     RECT  197.239 35.406 197.527 35.424 ;
     RECT  196.951 46.746 197.635 46.764 ;
     RECT  197.203 39.258 197.671 39.276 ;
     RECT  197.491 34.164 197.779 34.182 ;
     RECT  197.527 35.046 197.779 35.424 ;
     RECT  197.275 38.106 197.779 38.124 ;
     RECT  197.671 39.024 197.779 39.276 ;
     RECT  196.987 44.046 197.779 44.064 ;
     RECT  196.915 45.666 197.779 45.684 ;
     RECT  196.128 53.028 197.779 53.046 ;
     RECT  197.563 54.918 197.779 54.936 ;
     RECT  197.599 57.816 197.779 57.834 ;
     RECT  196.128 64.368 197.779 86.409 ;
     RECT  197.635 46.746 197.815 47.142 ;
     RECT  197.779 54.918 197.815 55.404 ;
     RECT  197.779 57.006 197.815 57.024 ;
     RECT  197.779 57.816 197.815 58.644 ;
     RECT  197.779 61.128 197.815 63.54 ;
     RECT  197.779 64.296 197.815 86.409 ;
     RECT  197.815 57.006 197.923 58.716 ;
     RECT  197.923 57.006 197.995 59.094 ;
     RECT  196.128 2.151 198.031 23.724 ;
     RECT  197.779 53.028 198.067 53.316 ;
     RECT  197.995 57.006 198.067 59.634 ;
     RECT  198.031 2.151 198.103 23.922 ;
     RECT  197.815 46.584 198.139 47.142 ;
     RECT  197.599 48.906 198.139 48.924 ;
     RECT  197.779 41.256 198.175 41.274 ;
     RECT  198.139 46.584 198.175 47.574 ;
     RECT  197.959 51.066 198.175 51.084 ;
     RECT  197.815 54.612 198.175 55.782 ;
     RECT  198.103 2.151 198.18 24.264 ;
     RECT  197.203 31.896 198.18 31.914 ;
     RECT  197.167 33.048 198.18 33.066 ;
     RECT  197.779 34.164 198.18 35.424 ;
     RECT  197.779 38.106 198.18 39.654 ;
     RECT  198.175 41.256 198.18 41.904 ;
     RECT  197.779 42.732 198.18 42.75 ;
     RECT  197.779 44.046 198.18 45.684 ;
     RECT  198.175 46.584 198.18 47.682 ;
     RECT  198.139 48.906 198.18 49.608 ;
     RECT  198.175 50.796 198.18 51.084 ;
     RECT  198.067 53.028 198.18 53.514 ;
     RECT  198.175 54.378 198.18 55.782 ;
     RECT  198.067 57.006 198.18 59.994 ;
     RECT  197.815 61.128 198.18 86.409 ;
     RECT  198.18 2.151 218.16 86.409 ;
    LAYER M3 ;
     RECT  98.064 0.091 98.082 0.331 ;
     RECT  80.1 0.235 80.118 0.337 ;
     RECT  22.284 0.139 22.302 0.373 ;
     RECT  42.588 0.337 42.606 0.373 ;
     RECT  8.712 0.331 8.73 0.379 ;
     RECT  42.192 0.373 42.606 0.409 ;
     RECT  46.8 0.373 46.818 0.409 ;
     RECT  50.832 0.337 50.85 0.409 ;
     RECT  54.792 0.337 54.81 0.409 ;
     RECT  76.392 0.379 76.41 0.427 ;
     RECT  48.996 0.139 49.014 0.437 ;
     RECT  42.192 0.409 42.678 0.445 ;
     RECT  102.924 0.337 102.942 0.445 ;
     RECT  77.148 0.301 77.166 0.475 ;
     RECT  65.556 0.337 65.574 0.481 ;
     RECT  8.424 0.379 8.73 0.526 ;
     RECT  25.128 0.409 25.146 0.526 ;
     RECT  46.8 0.409 47.322 0.526 ;
     RECT  81.612 0.256 81.63 0.526 ;
     RECT  38.808 0.445 39.438 0.554 ;
     RECT  58.68 0.409 58.698 0.554 ;
     RECT  34.884 0.301 34.902 0.571 ;
     RECT  67.824 0.187 67.842 0.571 ;
     RECT  31.932 0.373 31.95 0.599 ;
     RECT  64.908 0.481 65.574 0.599 ;
     RECT  25.092 0.526 25.146 0.679 ;
     RECT  26.352 0.091 26.37 0.679 ;
     RECT  50.724 0.409 50.85 0.679 ;
     RECT  32.796 0.373 32.814 0.715 ;
     RECT  34.164 0.571 34.902 0.715 ;
     RECT  45.612 0.445 45.63 0.715 ;
     RECT  11.844 0.445 11.862 0.751 ;
     RECT  50.724 0.679 51.354 0.751 ;
     RECT  8.424 0.526 8.874 0.796 ;
     RECT  62.352 0.481 62.37 0.796 ;
     RECT  40.464 0.301 40.482 0.841 ;
     RECT  105.732 0.526 105.75 0.841 ;
     RECT  72.972 0.283 72.99 0.869 ;
     RECT  92.916 0.409 92.934 0.869 ;
     RECT  25.092 0.679 26.37 0.877 ;
     RECT  27.36 0.235 27.378 0.877 ;
     RECT  34.128 0.715 34.902 0.877 ;
     RECT  25.092 0.877 27.378 0.907 ;
     RECT  79.92 0.337 80.118 0.907 ;
     RECT  80.964 0.526 81.63 0.907 ;
     RECT  52.704 0.715 52.722 0.913 ;
     RECT  79.056 0.841 79.074 0.949 ;
     RECT  79.92 0.907 81.63 0.949 ;
     RECT  6.444 0.427 6.462 0.955 ;
     RECT  54.756 0.409 54.81 0.977 ;
     RECT  50.724 0.751 51.75 0.985 ;
     RECT  52.704 0.913 53.262 0.985 ;
     RECT  71.172 0.913 71.19 0.985 ;
     RECT  6.372 0.955 6.462 1.003 ;
     RECT  72.432 0.985 72.594 1.003 ;
     RECT  11.844 0.751 12.51 1.021 ;
     RECT  43.884 0.877 43.902 1.021 ;
     RECT  79.056 0.949 81.63 1.021 ;
     RECT  100.764 0.481 100.782 1.021 ;
     RECT  34.128 0.877 35.37 1.051 ;
     RECT  105.516 0.841 105.75 1.051 ;
     RECT  22.248 0.373 22.302 1.066 ;
     RECT  25.092 0.907 27.954 1.066 ;
     RECT  33.876 1.051 35.37 1.066 ;
     RECT  46.8 0.526 47.934 1.066 ;
     RECT  6.3 1.003 6.462 1.099 ;
     RECT  24.876 1.066 27.954 1.111 ;
     RECT  30.924 0.913 30.942 1.111 ;
     RECT  37.908 1.021 37.926 1.111 ;
     RECT  39.384 0.554 39.438 1.111 ;
     RECT  40.464 0.841 40.734 1.111 ;
     RECT  42.192 0.445 42.714 1.111 ;
     RECT  43.884 1.021 44.19 1.111 ;
     RECT  46.8 1.066 48.366 1.111 ;
     RECT  56.232 0.859 56.25 1.111 ;
     RECT  57.276 0.877 57.294 1.111 ;
     RECT  58.212 0.841 58.23 1.111 ;
     RECT  62.208 0.796 62.37 1.111 ;
     RECT  102.816 0.445 102.942 1.111 ;
     RECT  52.704 0.985 53.55 1.139 ;
     RECT  6.3 1.099 6.498 1.147 ;
     RECT  18.36 0.256 18.378 1.147 ;
     RECT  33.552 1.066 35.406 1.147 ;
     RECT  45 0.715 45.63 1.147 ;
     RECT  71.172 0.985 71.55 1.147 ;
     RECT  72.396 1.003 72.594 1.147 ;
     RECT  75.996 0.427 76.41 1.147 ;
     RECT  77.148 0.475 77.526 1.147 ;
     RECT  78.732 1.021 81.63 1.147 ;
     RECT  102.348 1.111 102.942 1.147 ;
     RECT  37.908 1.111 38.214 1.175 ;
     RECT  73.548 0.877 73.566 1.175 ;
     RECT  45 1.147 45.702 1.183 ;
     RECT  46.764 1.111 48.366 1.183 ;
     RECT  50.616 0.985 51.75 1.183 ;
     RECT  52.704 1.139 53.406 1.183 ;
     RECT  39.384 1.111 40.734 1.219 ;
     RECT  41.58 1.111 44.19 1.219 ;
     RECT  62.208 1.111 62.73 1.219 ;
     RECT  24.624 1.111 27.954 1.243 ;
     RECT  95.22 0.301 95.238 1.243 ;
     RECT  56.232 1.111 56.43 1.255 ;
     RECT  57.276 1.111 58.23 1.255 ;
     RECT  71.172 1.147 72.594 1.291 ;
     RECT  30.924 1.111 31.41 1.336 ;
     RECT  45 1.183 48.366 1.336 ;
     RECT  100.764 1.021 100.998 1.336 ;
     RECT  64.908 0.599 64.926 1.339 ;
     RECT  20.34 0.859 20.358 1.381 ;
     RECT  45 1.336 48.546 1.381 ;
     RECT  62.208 1.219 62.766 1.387 ;
     RECT  67.14 0.571 67.842 1.387 ;
     RECT  33.552 1.147 35.982 1.435 ;
     RECT  88.92 1.066 88.938 1.445 ;
     RECT  6.3 1.147 6.678 1.453 ;
     RECT  7.704 0.796 8.874 1.453 ;
     RECT  24.624 1.243 28.17 1.453 ;
     RECT  32.436 0.715 32.814 1.453 ;
     RECT  33.552 1.435 36.054 1.453 ;
     RECT  70.704 1.291 72.594 1.453 ;
     RECT  22.248 1.066 22.806 1.481 ;
     RECT  89.928 1.453 89.946 1.483 ;
     RECT  91.224 0.949 91.242 1.483 ;
     RECT  62.136 1.387 62.766 1.489 ;
     RECT  100.512 1.336 100.998 1.489 ;
     RECT  22.248 1.481 22.626 1.525 ;
     RECT  37.98 1.175 38.214 1.525 ;
     RECT  18.36 1.147 18.45 1.531 ;
     RECT  39.384 1.219 44.19 1.561 ;
     RECT  59.076 0.949 59.094 1.561 ;
     RECT  85.104 0.373 85.122 1.561 ;
     RECT  49.608 0.526 49.626 1.579 ;
     RECT  50.616 1.183 53.406 1.579 ;
     RECT  100.44 1.489 100.998 1.579 ;
     RECT  30.852 1.336 31.41 1.606 ;
     RECT  39.348 1.561 44.19 1.606 ;
     RECT  45 1.381 48.69 1.606 ;
     RECT  97.812 0.331 98.082 1.627 ;
     RECT  30.816 1.606 31.41 1.651 ;
     RECT  32.436 1.453 36.054 1.651 ;
     RECT  95.22 1.243 95.886 1.651 ;
     RECT  20.34 1.381 21.078 1.675 ;
     RECT  21.96 1.525 22.626 1.675 ;
     RECT  30.816 1.651 36.054 1.675 ;
     RECT  36.9 1.417 36.918 1.675 ;
     RECT  61.02 1.531 61.038 1.675 ;
     RECT  29.628 1.387 29.646 1.687 ;
     RECT  30.816 1.675 37.062 1.687 ;
     RECT  24.624 1.453 28.494 1.723 ;
     RECT  29.628 1.687 29.682 1.723 ;
     RECT  54.756 0.977 54.774 1.723 ;
     RECT  67.14 1.387 68.418 1.751 ;
     RECT  69.588 1.723 69.606 1.771 ;
     RECT  59.076 1.561 59.598 1.795 ;
     RECT  60.552 1.675 61.038 1.795 ;
     RECT  11.844 1.021 12.546 1.819 ;
     RECT  61.776 1.489 62.766 1.819 ;
     RECT  63.504 1.111 63.522 1.819 ;
     RECT  99.18 1.606 99.198 1.867 ;
     RECT  100.188 1.579 100.998 1.867 ;
     RECT  2.34 1.336 2.358 1.876 ;
     RECT  4.32 1.867 4.338 1.876 ;
     RECT  11.016 1.435 11.034 1.876 ;
     RECT  11.844 1.819 13.194 1.876 ;
     RECT  54.72 1.723 55.386 1.876 ;
     RECT  59.076 1.795 61.038 1.876 ;
     RECT  61.776 1.819 63.522 1.876 ;
     RECT  64.908 1.339 65.61 1.876 ;
     RECT  75.24 1.147 75.258 1.915 ;
     RECT  6.3 1.453 8.874 1.921 ;
     RECT  11.016 1.876 13.194 1.921 ;
     RECT  39.348 1.606 48.69 1.921 ;
     RECT  54.72 1.876 55.422 1.921 ;
     RECT  56.232 1.255 58.23 1.921 ;
     RECT  64.476 1.876 65.61 1.921 ;
     RECT  104.724 1.525 104.742 1.921 ;
     RECT  2.34 1.876 2.862 1.957 ;
     RECT  4.212 1.876 4.338 1.957 ;
     RECT  6.3 1.921 9.234 1.957 ;
     RECT  30.78 1.687 37.062 1.957 ;
     RECT  37.98 1.525 38.574 1.957 ;
     RECT  39.312 1.921 48.69 1.957 ;
     RECT  93.636 0.985 93.654 1.957 ;
     RECT  2.34 1.957 4.338 1.963 ;
     RECT  30.78 1.957 48.69 1.963 ;
     RECT  54.72 1.921 58.23 1.963 ;
     RECT  59.076 1.876 63.522 1.963 ;
     RECT  75.996 1.147 77.526 1.963 ;
     RECT  78.66 1.147 81.846 1.963 ;
     RECT  5.22 1.957 5.238 1.993 ;
     RECT  6.084 1.957 9.234 1.993 ;
     RECT  74.556 1.915 75.258 1.993 ;
     RECT  75.996 1.963 81.846 1.993 ;
     RECT  24.624 1.723 29.682 2.011 ;
     RECT  82.836 1.435 82.854 2.011 ;
     RECT  2.304 1.963 4.338 2.029 ;
     RECT  11.016 1.921 13.59 2.029 ;
     RECT  74.556 1.993 81.846 2.029 ;
     RECT  82.836 2.011 83.142 2.029 ;
     RECT  85.104 1.561 85.554 2.059 ;
     RECT  2.304 2.029 4.41 2.065 ;
     RECT  5.184 1.993 9.234 2.065 ;
     RECT  24.3 2.011 29.682 2.065 ;
     RECT  30.42 1.963 48.69 2.065 ;
     RECT  68.652 1.771 69.606 2.065 ;
     RECT  70.344 1.453 72.594 2.065 ;
     RECT  107.388 1.099 107.406 2.101 ;
     RECT  18.216 1.531 18.45 2.143 ;
     RECT  23.544 2.065 23.562 2.143 ;
     RECT  24.3 2.065 48.69 2.143 ;
     RECT  68.652 2.065 72.594 2.143 ;
     RECT  74.556 2.029 83.142 2.143 ;
     RECT  93.636 1.957 93.69 2.143 ;
     RECT  104.364 1.921 104.742 2.143 ;
     RECT  105.516 1.051 105.894 2.143 ;
     RECT  2.304 2.065 9.234 2.155 ;
     RECT  18.216 2.143 18.705 2.155 ;
     RECT  54.72 1.963 63.522 2.155 ;
     RECT  67.14 1.751 67.842 2.155 ;
     RECT  68.652 2.143 72.705 2.155 ;
     RECT  15.588 0.283 15.606 2.191 ;
     RECT  54.216 2.155 63.522 2.191 ;
     RECT  64.26 1.921 65.61 2.191 ;
     RECT  66.888 2.155 67.842 2.191 ;
     RECT  107.028 2.101 107.658 2.191 ;
     RECT  2.268 2.155 9.234 2.203 ;
     RECT  10.044 0.481 10.062 2.203 ;
     RECT  73.656 2.029 73.674 2.227 ;
     RECT  74.556 2.143 83.505 2.227 ;
     RECT  84.996 2.059 85.554 2.227 ;
     RECT  92.7 1.819 92.718 2.227 ;
     RECT  10.8 2.029 14.31 2.251 ;
     RECT  15.588 2.191 15.678 2.251 ;
     RECT  92.52 2.227 92.862 2.251 ;
     RECT  93.636 2.143 94.305 2.251 ;
     RECT  68.652 2.155 72.81 2.263 ;
     RECT  73.656 2.227 83.505 2.263 ;
     RECT  10.8 2.251 14.67 2.299 ;
     RECT  18.216 2.155 18.81 2.299 ;
     RECT  20.34 1.675 22.626 2.299 ;
     RECT  23.544 2.143 48.69 2.299 ;
     RECT  49.608 1.579 53.406 2.299 ;
     RECT  54.216 2.191 67.842 2.299 ;
     RECT  68.652 2.263 83.505 2.299 ;
     RECT  84.708 2.227 85.554 2.299 ;
     RECT  88.815 2.143 88.905 2.299 ;
     RECT  89.928 1.483 91.242 2.299 ;
     RECT  92.52 2.251 94.305 2.299 ;
     RECT  95.22 1.651 96.21 2.299 ;
     RECT  97.812 1.627 98.37 2.299 ;
     RECT  110.415 2.143 110.505 2.299 ;
     RECT  18.216 2.299 22.626 2.335 ;
     RECT  23.544 2.299 67.842 2.335 ;
     RECT  102.348 1.147 103.014 2.335 ;
     RECT  104.364 2.143 105.894 2.335 ;
     RECT  106.848 2.191 107.658 2.335 ;
     RECT  110.34 2.299 110.505 2.335 ;
     RECT  17.604 2.335 67.842 2.347 ;
     RECT  2.268 2.203 10.062 2.371 ;
     RECT  10.8 2.299 14.742 2.371 ;
     RECT  15.588 2.251 15.966 2.371 ;
     RECT  87.372 1.417 87.39 2.371 ;
     RECT  104.364 2.335 109.098 2.371 ;
     RECT  109.872 2.335 110.538 2.371 ;
     RECT  68.652 2.299 83.574 2.413 ;
     RECT  88.164 2.299 88.905 2.413 ;
     RECT  115.815 2.143 115.905 2.413 ;
     RECT  121.215 2.143 121.305 2.413 ;
     RECT  126.615 2.143 126.705 2.413 ;
     RECT  132.015 2.143 132.105 2.413 ;
     RECT  137.415 2.143 137.505 2.413 ;
     RECT  142.815 2.143 142.905 2.413 ;
     RECT  148.215 2.143 148.305 2.413 ;
     RECT  153.615 2.143 153.705 2.413 ;
     RECT  159.015 2.143 159.105 2.413 ;
     RECT  164.415 2.143 164.505 2.413 ;
     RECT  169.815 2.143 169.905 2.413 ;
     RECT  175.215 2.143 175.305 2.413 ;
     RECT  180.615 2.143 180.705 2.413 ;
     RECT  186.015 2.143 186.105 2.413 ;
     RECT  191.415 2.143 191.505 2.413 ;
     RECT  196.815 2.143 196.905 2.413 ;
     RECT  202.215 2.143 202.305 2.413 ;
     RECT  207.615 2.143 207.705 2.413 ;
     RECT  213.015 2.143 213.105 2.413 ;
     RECT  0.324 2.443 0.342 2.461 ;
     RECT  87.3 2.371 87.39 2.461 ;
     RECT  88.164 2.413 89.097 2.461 ;
     RECT  89.892 2.299 91.242 2.461 ;
     RECT  15.516 2.371 15.966 2.491 ;
     RECT  17.1 2.347 67.842 2.497 ;
     RECT  68.652 2.413 83.697 2.497 ;
     RECT  84.42 2.299 86.418 2.497 ;
     RECT  87.3 2.461 91.242 2.497 ;
     RECT  92.52 2.299 98.37 2.497 ;
     RECT  0.324 2.461 0.414 2.525 ;
     RECT  15.516 2.491 16.038 2.533 ;
     RECT  17.1 2.497 91.242 2.533 ;
     RECT  104.364 2.371 110.79 2.533 ;
     RECT  0.324 2.525 0.342 2.539 ;
     RECT  2.268 2.371 14.742 2.539 ;
     RECT  15.48 2.533 91.242 2.539 ;
     RECT  92.376 2.497 98.37 2.569 ;
     RECT  99.18 1.867 100.998 2.569 ;
     RECT  0.216 2.539 0.342 2.587 ;
     RECT  2.268 2.539 91.242 2.605 ;
     RECT  92.376 2.569 100.998 2.605 ;
     RECT  2.268 2.605 91.458 2.641 ;
     RECT  92.196 2.605 100.998 2.641 ;
     RECT  104.364 2.533 111.258 2.641 ;
     RECT  102.348 2.335 103.338 2.827 ;
     RECT  102.348 2.827 103.554 2.875 ;
     RECT  104.364 2.641 111.294 2.875 ;
     RECT  2.268 2.641 100.998 2.911 ;
     RECT  102.348 2.875 111.294 2.911 ;
     RECT  0.144 2.587 0.342 3.019 ;
     RECT  102.348 2.911 111.546 3.145 ;
     RECT  2.268 2.911 101.142 3.149 ;
     RECT  2.304 3.149 101.142 3.181 ;
     RECT  102.132 3.145 111.546 3.181 ;
     RECT  0.108 3.019 0.342 3.271 ;
     RECT  2.304 3.181 111.546 3.299 ;
     RECT  102.132 3.299 111.546 3.379 ;
     RECT  102.132 3.379 111.762 3.389 ;
     RECT  0.108 3.271 0.558 3.403 ;
     RECT  0.108 3.403 1.242 3.821 ;
     RECT  2.304 3.299 101.25 3.955 ;
     RECT  2.268 3.955 101.25 4.013 ;
     RECT  102.168 3.389 111.762 4.225 ;
     RECT  2.304 4.013 101.25 4.267 ;
     RECT  102.024 4.225 111.762 4.267 ;
     RECT  2.304 4.267 111.762 4.415 ;
     RECT  0.108 3.821 0.342 4.493 ;
     RECT  0.108 4.493 0.234 4.559 ;
     RECT  1.224 3.821 1.242 4.829 ;
     RECT  2.304 4.415 111.69 5.131 ;
     RECT  1.98 5.131 111.69 5.309 ;
     RECT  0.144 4.559 0.234 5.323 ;
     RECT  0.108 5.323 0.234 5.431 ;
     RECT  2.304 5.309 111.69 5.611 ;
     RECT  2.304 5.611 111.942 5.881 ;
     RECT  0.108 5.431 0.306 5.899 ;
     RECT  2.304 5.881 112.086 5.971 ;
     RECT  0.108 5.899 0.342 6.029 ;
     RECT  191.415 2.413 191.697 6.043 ;
     RECT  2.304 5.971 112.302 6.071 ;
     RECT  190.908 6.043 191.697 6.115 ;
     RECT  1.296 6.139 1.314 6.151 ;
     RECT  194.328 6.043 194.454 6.173 ;
     RECT  190.8 6.115 191.697 6.269 ;
     RECT  2.304 6.071 112.194 6.421 ;
     RECT  2.268 6.421 112.194 6.575 ;
     RECT  2.268 6.575 112.158 6.583 ;
     RECT  1.152 6.151 1.314 6.667 ;
     RECT  2.232 6.583 112.158 6.667 ;
     RECT  1.152 6.667 112.158 6.797 ;
     RECT  2.232 6.797 112.158 6.845 ;
     RECT  0.108 6.029 0.126 7.151 ;
     RECT  1.152 6.797 1.314 7.231 ;
     RECT  0.432 7.231 1.314 7.259 ;
     RECT  2.304 6.845 112.158 7.501 ;
     RECT  2.304 7.501 112.338 7.735 ;
     RECT  2.304 7.735 112.446 7.925 ;
     RECT  0.432 7.259 1.206 8.011 ;
     RECT  2.304 7.925 112.374 8.041 ;
     RECT  2.268 8.041 112.374 8.429 ;
     RECT  2.268 8.429 112.302 8.465 ;
     RECT  2.268 8.465 112.23 8.573 ;
     RECT  0.108 8.011 1.206 8.699 ;
     RECT  0.108 8.699 0.558 8.879 ;
     RECT  0.144 8.879 0.558 9.077 ;
     RECT  2.268 8.573 112.158 9.239 ;
     RECT  0.432 9.077 0.558 9.481 ;
     RECT  0.432 9.481 0.63 9.533 ;
     RECT  0.432 9.533 0.558 9.689 ;
     RECT  2.268 9.239 111.942 9.773 ;
     RECT  0.432 9.689 0.522 9.931 ;
     RECT  0.108 9.931 0.522 9.968 ;
     RECT  2.304 9.773 111.942 10.267 ;
     RECT  0.144 9.968 0.522 10.411 ;
     RECT  0.144 10.411 0.666 10.541 ;
     RECT  0.144 10.541 0.558 10.829 ;
     RECT  0.54 10.829 0.558 11.039 ;
     RECT  2.304 10.267 112.158 11.659 ;
     RECT  2.232 11.659 112.158 11.677 ;
     RECT  0.108 11.659 0.234 12.235 ;
     RECT  1.152 11.851 1.17 12.235 ;
     RECT  2.232 11.677 112.266 12.289 ;
     RECT  0.108 12.235 1.17 12.317 ;
     RECT  1.152 12.317 1.17 12.361 ;
     RECT  2.232 12.289 112.338 12.361 ;
     RECT  0.108 12.317 0.234 12.461 ;
     RECT  0.18 12.461 0.234 12.509 ;
     RECT  1.152 12.361 112.446 12.653 ;
     RECT  113.292 12.901 113.31 13.019 ;
     RECT  2.304 12.653 112.446 13.063 ;
     RECT  0.216 12.509 0.234 13.099 ;
     RECT  1.152 12.653 1.242 13.099 ;
     RECT  2.304 13.063 112.518 13.369 ;
     RECT  0.216 13.099 1.242 13.469 ;
     RECT  113.616 13.441 113.634 13.559 ;
     RECT  0.144 13.483 0.198 13.66 ;
     RECT  1.152 13.469 1.242 14.009 ;
     RECT  2.304 13.369 112.842 14.099 ;
     RECT  2.304 14.099 112.662 14.251 ;
     RECT  0.108 13.66 0.198 14.347 ;
     RECT  1.152 14.009 1.17 14.549 ;
     RECT  2.268 14.251 112.662 14.573 ;
     RECT  0.108 14.347 0.342 15.019 ;
     RECT  2.304 14.573 112.662 15.061 ;
     RECT  2.304 15.061 112.95 15.179 ;
     RECT  0.108 15.019 0.558 15.499 ;
     RECT  2.304 15.179 112.878 15.499 ;
     RECT  0.108 15.499 0.594 15.799 ;
     RECT  0.108 15.799 1.134 16.075 ;
     RECT  191.415 6.269 191.697 16.141 ;
     RECT  113.724 16.141 113.742 16.259 ;
     RECT  190.98 16.141 191.697 16.301 ;
     RECT  2.268 15.499 112.878 16.411 ;
     RECT  0.108 16.075 1.17 16.439 ;
     RECT  0.144 16.439 1.17 16.459 ;
     RECT  117.072 16.459 117.09 16.501 ;
     RECT  2.268 16.411 112.95 16.529 ;
     RECT  117 16.501 117.09 16.529 ;
     RECT  2.268 16.529 112.806 16.589 ;
     RECT  2.268 16.589 112.59 16.601 ;
     RECT  2.268 16.601 112.518 16.685 ;
     RECT  126.615 2.413 126.897 16.771 ;
     RECT  117 16.529 117.018 16.799 ;
     RECT  196.815 2.413 197.097 16.807 ;
     RECT  126.615 16.771 127.062 16.829 ;
     RECT  2.268 16.685 112.482 16.835 ;
     RECT  127.836 16.795 127.854 16.835 ;
     RECT  191.052 16.301 191.697 16.835 ;
     RECT  2.304 16.835 112.482 16.877 ;
     RECT  194.76 14.203 194.778 17.617 ;
     RECT  121.215 2.413 121.497 17.752 ;
     RECT  132.015 2.413 132.297 17.752 ;
     RECT  142.815 2.413 143.097 17.752 ;
     RECT  153.615 2.413 153.897 17.752 ;
     RECT  164.415 2.413 164.697 17.752 ;
     RECT  175.215 2.413 175.497 17.752 ;
     RECT  2.304 16.877 112.374 17.761 ;
     RECT  169.815 2.413 170.097 17.761 ;
     RECT  170.892 15.871 170.91 17.761 ;
     RECT  194.652 17.617 194.778 17.761 ;
     RECT  121.104 17.752 121.497 17.789 ;
     RECT  131.904 17.752 132.297 17.789 ;
     RECT  142.704 17.752 143.097 17.789 ;
     RECT  153.504 17.752 153.897 17.789 ;
     RECT  164.304 17.752 164.697 17.789 ;
     RECT  175.104 17.752 175.497 17.789 ;
     RECT  180.615 2.413 180.897 17.899 ;
     RECT  118.584 17.761 118.602 17.915 ;
     RECT  130.536 17.761 130.554 17.915 ;
     RECT  138.528 17.761 138.546 17.915 ;
     RECT  150.48 17.761 150.498 17.915 ;
     RECT  162.468 17.761 162.486 17.915 ;
     RECT  169.815 17.761 170.91 17.915 ;
     RECT  178.416 17.755 178.434 17.933 ;
     RECT  191.415 16.835 191.697 17.995 ;
     RECT  126.615 16.829 126.897 18.031 ;
     RECT  0.144 16.459 1.422 18.059 ;
     RECT  198.792 17.611 198.81 18.229 ;
     RECT  2.304 17.761 112.554 18.265 ;
     RECT  2.304 18.265 112.734 18.283 ;
     RECT  187.092 17.851 187.11 18.301 ;
     RECT  2.268 18.283 112.734 18.329 ;
     RECT  0.144 18.059 0.594 18.412 ;
     RECT  194.652 17.761 195.102 18.475 ;
     RECT  2.304 18.329 112.734 18.535 ;
     RECT  172.728 15.259 172.746 18.571 ;
     RECT  0.108 18.412 0.594 18.599 ;
     RECT  187.092 18.301 187.326 18.661 ;
     RECT  132.015 17.789 132.297 18.733 ;
     RECT  2.304 18.535 112.842 18.761 ;
     RECT  1.404 18.059 1.422 18.797 ;
     RECT  194.652 18.475 195.246 18.805 ;
     RECT  2.304 18.761 70.362 18.833 ;
     RECT  174.348 11.245 174.366 19.003 ;
     RECT  175.215 17.789 175.497 19.003 ;
     RECT  132.015 18.733 132.858 19.039 ;
     RECT  187.092 18.661 187.398 19.085 ;
     RECT  71.172 18.761 112.842 19.111 ;
     RECT  121.215 17.789 121.497 19.111 ;
     RECT  186.015 2.413 186.297 19.111 ;
     RECT  71.172 19.111 112.986 19.228 ;
     RECT  128.628 19.201 128.646 19.265 ;
     RECT  174.348 19.003 175.497 19.273 ;
     RECT  174.168 19.273 175.497 19.309 ;
     RECT  71.172 19.228 113.022 19.337 ;
     RECT  189.828 16.363 189.846 19.381 ;
     RECT  198.324 18.229 198.81 19.471 ;
     RECT  199.728 19.237 199.746 19.471 ;
     RECT  136.26 19.201 136.278 19.499 ;
     RECT  189.288 19.381 189.846 19.499 ;
     RECT  142.815 17.789 143.097 19.579 ;
     RECT  153.615 17.789 153.897 19.579 ;
     RECT  2.34 18.833 70.362 19.615 ;
     RECT  156.348 15.835 156.366 19.615 ;
     RECT  189.828 19.499 189.846 19.615 ;
     RECT  190.8 17.995 191.697 19.615 ;
     RECT  128.376 19.273 128.61 19.651 ;
     RECT  164.415 17.789 164.697 19.651 ;
     RECT  169.815 17.915 170.097 19.651 ;
     RECT  170.892 17.915 170.91 19.651 ;
     RECT  174.024 19.309 175.497 19.651 ;
     RECT  183.132 15.307 183.15 19.651 ;
     RECT  185.832 19.111 186.297 19.651 ;
     RECT  187.092 19.085 187.182 19.651 ;
     RECT  71.172 19.337 112.41 19.679 ;
     RECT  182.52 19.651 183.15 19.741 ;
     RECT  71.172 19.679 112.302 19.769 ;
     RECT  179.46 18.697 179.478 19.777 ;
     RECT  198.324 19.471 199.746 19.777 ;
     RECT  102.096 19.769 112.302 19.805 ;
     RECT  126.36 18.031 126.897 19.813 ;
     RECT  130.536 19.579 130.554 19.813 ;
     RECT  138.528 19.579 138.546 19.813 ;
     RECT  150.48 19.579 150.498 19.813 ;
     RECT  162.54 19.741 162.558 19.813 ;
     RECT  192.924 19.039 192.942 19.813 ;
     RECT  193.68 16.507 193.698 19.813 ;
     RECT  192.924 19.813 193.698 19.819 ;
     RECT  194.652 18.805 195.426 19.819 ;
     RECT  0.108 18.599 0.342 19.853 ;
     RECT  0.108 19.853 0.234 19.877 ;
     RECT  196.815 16.807 197.55 19.885 ;
     RECT  136.008 19.615 136.026 19.901 ;
     RECT  132.015 19.039 133.326 19.912 ;
     RECT  142.815 19.579 143.154 19.912 ;
     RECT  153.615 19.579 153.954 19.912 ;
     RECT  164.415 19.651 164.79 19.912 ;
     RECT  185.832 19.651 187.182 19.913 ;
     RECT  117.684 18.763 117.702 19.915 ;
     RECT  118.62 19.849 118.638 19.915 ;
     RECT  162.54 19.813 162.63 19.949 ;
     RECT  169.815 19.651 170.91 19.949 ;
     RECT  128.196 19.651 128.61 20.059 ;
     RECT  2.304 19.615 70.362 20.107 ;
     RECT  71.172 19.769 101.286 20.107 ;
     RECT  188.316 20.107 188.334 20.147 ;
     RECT  117.684 19.915 118.638 20.155 ;
     RECT  196.452 19.885 197.55 20.191 ;
     RECT  0.144 19.877 0.234 20.219 ;
     RECT  164.304 19.912 164.79 20.219 ;
     RECT  114.588 20.155 114.606 20.251 ;
     RECT  162.54 19.949 162.558 20.281 ;
     RECT  196.452 20.191 197.586 20.281 ;
     RECT  198.324 19.777 199.782 20.281 ;
     RECT  182.412 19.741 183.15 20.299 ;
     RECT  117.216 20.155 118.638 20.309 ;
     RECT  125.244 19.849 125.262 20.309 ;
     RECT  117.216 20.309 117.234 20.317 ;
     RECT  119.844 18.697 119.862 20.317 ;
     RECT  178.164 17.959 178.182 20.317 ;
     RECT  192.924 19.819 195.426 20.317 ;
     RECT  102.096 19.805 106.65 20.345 ;
     RECT  107.676 19.805 112.302 20.345 ;
     RECT  127.944 20.059 128.61 20.345 ;
     RECT  114.588 20.251 114.714 20.353 ;
     RECT  115.815 2.413 116.097 20.353 ;
     RECT  141.696 20.317 141.714 20.353 ;
     RECT  2.304 20.107 101.286 20.381 ;
     RECT  102.096 20.345 105.354 20.381 ;
     RECT  108.756 20.345 112.302 20.381 ;
     RECT  117.108 20.317 117.234 20.381 ;
     RECT  153.504 19.912 153.954 20.381 ;
     RECT  162.468 20.281 162.558 20.381 ;
     RECT  124.992 20.317 125.01 20.389 ;
     RECT  2.304 20.381 91.386 20.417 ;
     RECT  114.588 20.353 116.097 20.425 ;
     RECT  179.316 19.777 179.478 20.425 ;
     RECT  180.615 17.899 180.954 20.425 ;
     RECT  182.412 20.299 183.546 20.425 ;
     RECT  71.316 20.417 91.386 20.429 ;
     RECT  124.704 20.389 125.01 20.429 ;
     RECT  192.924 20.317 195.534 20.443 ;
     RECT  196.452 20.281 199.782 20.443 ;
     RECT  71.316 20.429 86.13 20.453 ;
     RECT  102.096 20.381 105.297 20.453 ;
     RECT  106.092 20.345 106.65 20.453 ;
     RECT  141.696 20.353 141.75 20.489 ;
     RECT  142.704 19.912 143.154 20.489 ;
     RECT  153.504 20.381 153.897 20.489 ;
     RECT  162.54 20.381 162.558 20.489 ;
     RECT  164.304 20.219 164.754 20.489 ;
     RECT  182.304 20.425 183.546 20.489 ;
     RECT  102.096 20.453 102.402 20.525 ;
     RECT  92.124 20.381 101.286 20.539 ;
     RECT  102.096 20.525 102.15 20.539 ;
     RECT  118.116 20.309 118.638 20.551 ;
     RECT  122.652 17.959 122.67 20.551 ;
     RECT  126.36 19.813 127.098 20.551 ;
     RECT  134.676 17.995 134.694 20.551 ;
     RECT  137.415 2.413 137.697 20.551 ;
     RECT  138.528 19.813 138.618 20.551 ;
     RECT  141.696 20.489 141.714 20.551 ;
     RECT  142.815 20.489 143.154 20.551 ;
     RECT  128.34 20.345 128.61 20.579 ;
     RECT  179.316 20.425 180.954 20.579 ;
     RECT  187.092 19.913 187.182 20.579 ;
     RECT  106.596 20.453 106.65 20.587 ;
     RECT  114.588 20.425 116.262 20.587 ;
     RECT  118.116 20.551 118.71 20.587 ;
     RECT  122.616 20.551 122.67 20.587 ;
     RECT  134.64 20.551 134.694 20.587 ;
     RECT  137.415 20.551 138.618 20.587 ;
     RECT  156.348 19.615 156.51 20.587 ;
     RECT  111.636 20.381 112.302 20.623 ;
     RECT  122.616 20.587 122.706 20.623 ;
     RECT  131.904 19.912 133.326 20.623 ;
     RECT  134.568 20.587 134.694 20.623 ;
     RECT  141.588 20.551 141.714 20.623 ;
     RECT  106.596 20.587 106.866 20.635 ;
     RECT  107.676 20.345 107.838 20.635 ;
     RECT  122.616 20.623 122.778 20.635 ;
     RECT  177.948 20.317 178.182 20.659 ;
     RECT  184.752 16.681 184.77 20.659 ;
     RECT  122.4 20.635 122.778 20.669 ;
     RECT  71.316 20.453 85.698 20.687 ;
     RECT  134.532 20.623 134.694 20.695 ;
     RECT  168.84 20.623 168.858 20.695 ;
     RECT  185.832 19.913 186.297 20.695 ;
     RECT  2.304 20.417 70.578 20.723 ;
     RECT  119.592 20.317 119.862 20.731 ;
     RECT  120.6 19.111 121.497 20.731 ;
     RECT  150.48 19.813 150.57 20.731 ;
     RECT  156.24 20.587 156.51 20.731 ;
     RECT  172.692 18.571 172.746 20.731 ;
     RECT  176.76 20.281 176.778 20.731 ;
     RECT  177.948 20.659 178.434 20.731 ;
     RECT  131.904 20.623 133.506 20.759 ;
     RECT  2.304 20.723 66.078 20.765 ;
     RECT  92.124 20.539 102.15 20.765 ;
     RECT  106.596 20.635 107.838 20.765 ;
     RECT  119.592 20.731 121.497 20.779 ;
     RECT  124.704 20.429 124.722 20.779 ;
     RECT  71.316 20.687 78.786 20.813 ;
     RECT  130.536 19.813 130.626 20.821 ;
     RECT  135.972 20.587 135.99 20.821 ;
     RECT  140.472 20.587 140.49 20.821 ;
     RECT  155.052 20.659 155.07 20.821 ;
     RECT  159.015 2.413 159.297 20.821 ;
     RECT  180.072 20.579 180.954 20.821 ;
     RECT  79.632 20.687 85.698 20.849 ;
     RECT  102.132 20.765 102.15 20.849 ;
     RECT  103.644 20.453 105.297 20.849 ;
     RECT  124.452 20.779 124.722 20.849 ;
     RECT  131.904 20.759 133.434 20.849 ;
     RECT  152.208 20.659 152.298 20.849 ;
     RECT  168.408 20.695 168.858 20.849 ;
     RECT  172.62 20.731 172.746 20.849 ;
     RECT  174.024 19.651 175.554 20.849 ;
     RECT  176.76 20.731 178.938 20.849 ;
     RECT  184.752 20.659 185.022 20.849 ;
     RECT  189.828 19.615 191.697 20.849 ;
     RECT  150.48 20.731 150.606 20.857 ;
     RECT  168.48 20.849 168.858 20.857 ;
     RECT  169.815 19.949 170.097 20.857 ;
     RECT  170.892 19.949 170.91 20.857 ;
     RECT  135.864 20.821 135.99 20.858 ;
     RECT  155.052 20.821 155.106 20.861 ;
     RECT  74.664 20.813 78.786 20.885 ;
     RECT  79.632 20.849 81.378 20.885 ;
     RECT  86.94 20.429 91.386 20.885 ;
     RECT  104.508 20.849 105.297 20.885 ;
     RECT  118.116 20.587 118.782 20.885 ;
     RECT  119.592 20.779 121.59 20.885 ;
     RECT  122.4 20.669 122.742 20.885 ;
     RECT  124.452 20.849 124.47 20.885 ;
     RECT  184.932 20.849 185.022 20.885 ;
     RECT  119.592 20.885 119.682 20.893 ;
     RECT  135.864 20.858 135.954 20.893 ;
     RECT  140.472 20.821 140.742 20.893 ;
     RECT  141.516 20.623 141.714 20.893 ;
     RECT  178.272 20.849 178.83 20.909 ;
     RECT  90.252 20.885 91.386 20.921 ;
     RECT  134.532 20.695 134.802 20.921 ;
     RECT  150.48 20.857 150.642 20.921 ;
     RECT  71.316 20.813 73.638 20.957 ;
     RECT  82.44 20.849 85.698 20.957 ;
     RECT  92.124 20.765 101.394 20.957 ;
     RECT  106.596 20.765 107.298 20.957 ;
     RECT  108.756 20.381 110.862 20.957 ;
     RECT  118.116 20.885 118.674 20.957 ;
     RECT  135.612 20.893 135.954 20.957 ;
     RECT  140.148 20.893 141.714 20.957 ;
     RECT  166.464 20.857 166.482 20.957 ;
     RECT  168.48 20.857 169.002 20.957 ;
     RECT  180.072 20.821 181.026 20.957 ;
     RECT  188.856 20.857 188.874 20.957 ;
     RECT  114.588 20.587 116.298 20.965 ;
     RECT  167.544 20.353 167.562 20.965 ;
     RECT  2.304 20.765 52.002 20.993 ;
     RECT  74.664 20.885 78.678 20.993 ;
     RECT  111.636 20.623 112.842 20.993 ;
     RECT  122.472 20.885 122.742 20.993 ;
     RECT  135.936 20.957 135.954 20.993 ;
     RECT  137.415 20.587 138.654 20.993 ;
     RECT  147.06 20.827 147.078 20.993 ;
     RECT  92.124 20.957 100.926 21.029 ;
     RECT  106.596 20.957 107.118 21.029 ;
     RECT  134.532 20.921 134.766 21.029 ;
     RECT  150.552 20.921 150.642 21.029 ;
     RECT  168.48 20.957 168.93 21.029 ;
     RECT  80.604 20.885 80.982 21.053 ;
     RECT  90.432 20.921 91.386 21.053 ;
     RECT  104.904 20.885 105.297 21.053 ;
     RECT  108.828 20.957 110.862 21.053 ;
     RECT  119.52 20.893 119.682 21.053 ;
     RECT  126.36 20.551 127.35 21.091 ;
     RECT  53.028 20.765 66.078 21.101 ;
     RECT  71.316 20.957 71.334 21.101 ;
     RECT  74.664 20.993 75.978 21.101 ;
     RECT  86.94 20.885 88.074 21.101 ;
     RECT  92.232 21.029 100.602 21.101 ;
     RECT  103.644 20.849 103.77 21.101 ;
     RECT  108.828 21.053 109.53 21.101 ;
     RECT  111.636 20.993 112.302 21.101 ;
     RECT  113.868 20.965 116.298 21.101 ;
     RECT  122.544 20.993 122.742 21.101 ;
     RECT  86.94 21.101 87.894 21.119 ;
     RECT  92.232 21.101 92.394 21.119 ;
     RECT  171.684 21.001 171.702 21.119 ;
     RECT  172.728 20.849 172.746 21.119 ;
     RECT  190.224 20.849 190.638 21.119 ;
     RECT  128.34 20.579 128.574 21.127 ;
     RECT  153.612 20.489 153.897 21.127 ;
     RECT  155.052 20.861 155.07 21.127 ;
     RECT  156.168 20.731 156.51 21.127 ;
     RECT  192.924 20.443 199.782 21.149 ;
     RECT  93.492 21.101 100.314 21.155 ;
     RECT  169.815 20.857 170.91 21.155 ;
     RECT  194.544 21.149 199.782 21.155 ;
     RECT  0.144 20.219 0.198 21.163 ;
     RECT  110.304 21.053 110.862 21.163 ;
     RECT  125.712 21.091 127.35 21.163 ;
     RECT  131.904 20.849 133.398 21.163 ;
     RECT  137.415 20.993 138.042 21.163 ;
     RECT  125.46 21.163 127.35 21.197 ;
     RECT  120.6 20.885 121.59 21.2 ;
     RECT  125.46 21.197 125.478 21.2 ;
     RECT  0.108 21.163 0.198 21.211 ;
     RECT  67.032 20.723 70.578 21.211 ;
     RECT  150.552 21.029 150.57 21.227 ;
     RECT  141.444 20.957 141.714 21.235 ;
     RECT  142.815 20.551 143.406 21.235 ;
     RECT  144.216 21.001 144.234 21.235 ;
     RECT  164.415 20.489 164.754 21.235 ;
     RECT  188.748 20.965 188.766 21.235 ;
     RECT  128.232 21.127 128.574 21.245 ;
     RECT  138.924 21.127 139.086 21.245 ;
     RECT  84.852 20.957 85.122 21.263 ;
     RECT  111.744 21.101 112.302 21.263 ;
     RECT  128.304 21.245 128.574 21.263 ;
     RECT  138.996 21.245 139.086 21.263 ;
     RECT  145.26 21.091 145.278 21.263 ;
     RECT  169.815 21.155 170.514 21.263 ;
     RECT  172.8 21.127 172.89 21.263 ;
     RECT  139.068 21.263 139.086 21.271 ;
     RECT  140.148 20.957 140.166 21.271 ;
     RECT  153.612 21.127 155.07 21.271 ;
     RECT  167.364 20.965 167.562 21.271 ;
     RECT  182.304 20.489 182.322 21.271 ;
     RECT  183.132 20.489 183.546 21.271 ;
     RECT  93.492 21.155 100.062 21.293 ;
     RECT  137.232 21.163 138.042 21.293 ;
     RECT  194.58 21.155 199.782 21.293 ;
     RECT  139.068 21.271 140.166 21.299 ;
     RECT  146.88 21.127 146.97 21.299 ;
     RECT  153.54 21.271 155.07 21.299 ;
     RECT  156.168 21.127 156.582 21.299 ;
     RECT  171.756 21.211 171.846 21.299 ;
     RECT  104.976 21.053 105.297 21.307 ;
     RECT  84.852 21.263 85.086 21.341 ;
     RECT  126.216 21.197 127.35 21.341 ;
     RECT  134.532 21.029 134.73 21.341 ;
     RECT  139.176 21.299 140.166 21.341 ;
     RECT  148.215 2.413 148.497 21.347 ;
     RECT  153.54 21.299 153.897 21.347 ;
     RECT  158.652 20.821 159.297 21.347 ;
     RECT  164.415 21.235 165.33 21.347 ;
     RECT  169.815 21.263 170.097 21.347 ;
     RECT  191.415 20.849 191.697 21.347 ;
     RECT  104.976 21.307 105.39 21.355 ;
     RECT  185.832 20.695 186.534 21.361 ;
     RECT  2.34 20.993 52.002 21.389 ;
     RECT  87.768 21.119 87.894 21.389 ;
     RECT  93.492 21.293 97.038 21.389 ;
     RECT  98.1 21.293 100.062 21.389 ;
     RECT  122.544 21.101 122.67 21.389 ;
     RECT  141.444 21.235 144.234 21.389 ;
     RECT  146.952 21.299 146.97 21.389 ;
     RECT  180.072 20.957 180.99 21.389 ;
     RECT  185.256 21.361 186.534 21.389 ;
     RECT  98.244 21.389 100.062 21.395 ;
     RECT  104.976 21.355 105.462 21.395 ;
     RECT  192.924 21.149 193.77 21.397 ;
     RECT  120.816 21.2 121.59 21.403 ;
     RECT  72.18 20.957 73.638 21.437 ;
     RECT  95.688 21.389 97.038 21.437 ;
     RECT  98.244 21.395 99.99 21.437 ;
     RECT  102.6 21.307 102.618 21.437 ;
     RECT  104.976 21.395 105.39 21.437 ;
     RECT  106.596 21.029 106.758 21.437 ;
     RECT  110.304 21.163 110.898 21.437 ;
     RECT  114.588 21.101 114.714 21.437 ;
     RECT  115.815 21.101 116.298 21.437 ;
     RECT  118.584 20.957 118.674 21.437 ;
     RECT  122.58 21.389 122.67 21.437 ;
     RECT  160.2 21.361 160.29 21.437 ;
     RECT  53.028 21.101 65.07 21.461 ;
     RECT  120.816 21.403 121.698 21.461 ;
     RECT  122.58 21.437 122.598 21.461 ;
     RECT  128.34 21.263 128.574 21.461 ;
     RECT  134.568 21.341 134.73 21.461 ;
     RECT  76.968 20.993 78.678 21.485 ;
     RECT  84.852 21.341 84.978 21.485 ;
     RECT  88.815 20.885 89.298 21.485 ;
     RECT  98.244 21.437 99.705 21.485 ;
     RECT  131.616 21.163 133.398 21.485 ;
     RECT  67.032 21.211 70.902 21.497 ;
     RECT  98.28 21.485 99.705 21.497 ;
     RECT  133.38 21.485 133.398 21.497 ;
     RECT  188.352 21.235 188.766 21.497 ;
     RECT  192.78 21.397 193.77 21.505 ;
     RECT  160.2 21.437 160.218 21.533 ;
     RECT  180.144 21.389 180.99 21.533 ;
     RECT  1.224 21.067 1.242 21.547 ;
     RECT  0.108 21.211 0.234 21.569 ;
     RECT  53.028 21.461 64.494 21.569 ;
     RECT  171.756 21.299 171.774 21.569 ;
     RECT  74.664 21.101 75.294 21.581 ;
     RECT  126.504 21.341 127.35 21.581 ;
     RECT  82.476 20.957 84.042 21.617 ;
     RECT  99.615 21.497 99.705 21.617 ;
     RECT  104.976 21.437 105.105 21.617 ;
     RECT  115.815 21.437 115.905 21.617 ;
     RECT  137.415 21.293 138.042 21.617 ;
     RECT  148.215 21.347 148.305 21.617 ;
     RECT  153.54 21.347 153.705 21.617 ;
     RECT  158.652 21.347 159.105 21.617 ;
     RECT  164.415 21.347 164.505 21.617 ;
     RECT  169.815 21.347 169.905 21.617 ;
     RECT  180.144 21.533 180.705 21.617 ;
     RECT  191.415 21.347 191.505 21.617 ;
     RECT  70.344 21.497 70.902 21.629 ;
     RECT  88.815 21.485 89.262 21.631 ;
     RECT  0.144 21.569 0.234 21.643 ;
     RECT  67.032 21.497 69.498 21.659 ;
     RECT  72.432 21.437 73.638 21.659 ;
     RECT  83.664 21.617 84.042 21.659 ;
     RECT  84.852 21.485 84.942 21.659 ;
     RECT  106.596 21.437 106.614 21.659 ;
     RECT  110.304 21.437 110.682 21.659 ;
     RECT  118.584 21.437 118.602 21.659 ;
     RECT  120.816 21.461 121.482 21.659 ;
     RECT  130.536 20.821 130.806 21.659 ;
     RECT  131.616 21.485 132.282 21.659 ;
     RECT  192.708 21.505 193.77 21.659 ;
     RECT  65.916 21.101 66.078 21.677 ;
     RECT  77.904 21.485 78.21 21.677 ;
     RECT  88.704 21.631 89.262 21.677 ;
     RECT  110.304 21.659 110.61 21.677 ;
     RECT  120.816 21.659 121.41 21.677 ;
     RECT  131.616 21.659 132.21 21.677 ;
     RECT  0.144 21.643 0.342 21.691 ;
     RECT  53.028 21.569 64.386 21.695 ;
     RECT  126.54 21.581 127.35 21.695 ;
     RECT  128.34 21.461 128.502 21.695 ;
     RECT  187.524 21.271 187.542 21.695 ;
     RECT  0.144 21.691 0.414 21.731 ;
     RECT  80.604 21.053 80.91 21.731 ;
     RECT  98.28 21.497 98.298 21.731 ;
     RECT  194.652 21.293 199.782 21.731 ;
     RECT  2.34 21.389 38.574 21.739 ;
     RECT  80.604 21.731 80.622 21.767 ;
     RECT  119.664 21.053 119.682 21.767 ;
     RECT  0.144 21.731 0.342 21.773 ;
     RECT  60.336 21.695 64.386 21.773 ;
     RECT  141.444 21.389 143.622 21.773 ;
     RECT  67.032 21.659 68.922 21.803 ;
     RECT  73.224 21.659 73.638 21.803 ;
     RECT  82.476 21.617 82.818 21.803 ;
     RECT  139.176 21.341 139.878 21.803 ;
     RECT  182.232 21.271 184.05 21.803 ;
     RECT  53.028 21.695 59.598 21.811 ;
     RECT  95.688 21.437 96.318 21.821 ;
     RECT  62.748 21.773 64.386 21.839 ;
     RECT  70.344 21.629 70.362 21.839 ;
     RECT  120.816 21.677 120.834 21.839 ;
     RECT  141.444 21.773 143.226 21.839 ;
     RECT  185.256 21.389 186.174 21.839 ;
     RECT  95.688 21.821 96.282 21.884 ;
     RECT  139.86 21.803 139.878 21.884 ;
     RECT  67.032 21.803 67.158 21.917 ;
     RECT  62.856 21.839 64.386 21.929 ;
     RECT  62.856 21.929 63.594 21.965 ;
     RECT  141.444 21.839 141.462 21.965 ;
     RECT  143.208 21.839 143.226 21.965 ;
     RECT  156.168 21.299 156.474 21.965 ;
     RECT  95.688 21.884 96.138 22.001 ;
     RECT  167.364 21.271 167.634 22.001 ;
     RECT  95.688 22.001 95.706 22.013 ;
     RECT  165.312 21.347 165.33 22.013 ;
     RECT  66.06 21.677 66.078 22.037 ;
     RECT  174.096 20.849 175.554 22.037 ;
     RECT  180.144 21.617 180.342 22.061 ;
     RECT  174.096 22.037 175.374 22.073 ;
     RECT  39.312 21.389 52.002 22.109 ;
     RECT  93.492 21.389 94.95 22.109 ;
     RECT  185.832 21.839 186.174 22.109 ;
     RECT  76.968 21.485 77.022 22.123 ;
     RECT  52.992 21.811 59.598 22.126 ;
     RECT  193.752 21.659 193.77 22.126 ;
     RECT  60.336 21.773 61.686 22.154 ;
     RECT  190.296 21.119 190.638 22.154 ;
     RECT  2.304 21.739 38.574 22.219 ;
     RECT  39.312 22.109 51.354 22.219 ;
     RECT  193.752 22.126 194.382 22.235 ;
     RECT  128.34 21.695 128.358 22.253 ;
     RECT  127.332 21.695 127.35 22.271 ;
     RECT  188.352 21.497 188.406 22.271 ;
     RECT  89.244 21.677 89.262 22.301 ;
     RECT  2.304 22.219 51.354 22.307 ;
     RECT  52.416 22.126 59.598 22.307 ;
     RECT  79.632 20.885 79.65 22.307 ;
     RECT  73.62 21.803 73.638 22.343 ;
     RECT  52.416 22.307 55.566 22.349 ;
     RECT  75.06 21.581 75.294 22.349 ;
     RECT  1.152 21.547 1.242 22.441 ;
     RECT  2.304 22.307 51.318 22.441 ;
     RECT  52.416 22.349 54.738 22.445 ;
     RECT  56.448 22.307 59.598 22.445 ;
     RECT  1.152 22.441 51.318 22.469 ;
     RECT  87.768 21.389 87.786 22.469 ;
     RECT  190.62 22.154 190.638 22.469 ;
     RECT  90.504 21.053 91.386 22.493 ;
     RECT  137.556 21.617 138.042 22.493 ;
     RECT  188.388 22.271 188.406 22.505 ;
     RECT  1.152 22.469 27.918 22.541 ;
     RECT  67.14 21.917 67.158 22.541 ;
     RECT  82.656 21.803 82.818 22.541 ;
     RECT  138.024 22.493 138.042 22.541 ;
     RECT  1.152 22.541 26.334 22.577 ;
     RECT  83.916 21.659 84.042 22.577 ;
     RECT  92.34 21.119 92.394 22.577 ;
     RECT  90.828 22.493 91.386 22.589 ;
     RECT  155.052 21.299 155.07 22.589 ;
     RECT  84.852 21.659 84.87 22.613 ;
     RECT  131.616 21.677 131.634 22.613 ;
     RECT  67.932 21.803 68.922 22.621 ;
     RECT  182.808 21.803 184.05 22.637 ;
     RECT  83.916 22.577 83.934 22.649 ;
     RECT  153.54 21.617 153.558 22.649 ;
     RECT  193.752 22.235 193.77 22.685 ;
     RECT  75.24 22.349 75.294 22.711 ;
     RECT  76.392 22.123 77.022 22.711 ;
     RECT  28.944 22.469 51.318 22.739 ;
     RECT  86.94 21.119 86.958 22.739 ;
     RECT  174.42 22.073 175.374 22.739 ;
     RECT  67.788 22.621 68.922 22.775 ;
     RECT  178.488 20.909 178.83 22.775 ;
     RECT  37.656 22.739 51.318 22.811 ;
     RECT  185.94 22.109 185.958 22.811 ;
     RECT  1.728 22.577 26.082 22.829 ;
     RECT  43.128 22.811 51.318 22.847 ;
     RECT  52.416 22.445 54.702 22.847 ;
     RECT  60.336 22.154 60.39 22.847 ;
     RECT  72.432 21.659 72.45 22.847 ;
     RECT  28.944 22.739 36.63 22.877 ;
     RECT  94.644 22.109 94.95 22.877 ;
     RECT  27.36 22.541 27.918 22.883 ;
     RECT  28.944 22.877 36.558 22.883 ;
     RECT  43.164 22.847 51.318 22.883 ;
     RECT  60.336 22.847 60.354 22.883 ;
     RECT  167.364 22.001 167.382 22.883 ;
     RECT  52.416 22.847 52.434 22.891 ;
     RECT  2.304 22.829 26.082 22.919 ;
     RECT  43.344 22.883 51.318 22.919 ;
     RECT  56.448 22.445 59.31 22.919 ;
     RECT  75.24 22.711 77.022 22.919 ;
     RECT  182.808 22.637 182.934 22.919 ;
     RECT  43.344 22.919 49.014 22.925 ;
     RECT  55.548 22.349 55.566 22.925 ;
     RECT  82.728 22.541 82.818 22.925 ;
     RECT  43.344 22.925 48.834 22.964 ;
     RECT  56.448 22.919 58.158 22.964 ;
     RECT  63.144 21.965 63.594 22.964 ;
     RECT  82.8 22.925 82.818 22.964 ;
     RECT  178.812 22.775 178.83 22.964 ;
     RECT  43.344 22.964 43.758 22.973 ;
     RECT  75.24 22.919 76.986 22.973 ;
     RECT  52.272 22.891 52.434 22.987 ;
     RECT  44.568 22.964 48.834 23.009 ;
     RECT  94.932 22.877 94.95 23.009 ;
     RECT  103.752 21.101 103.77 23.009 ;
     RECT  183.96 22.637 184.05 23.009 ;
     RECT  207.615 2.413 207.897 23.035 ;
     RECT  50.112 22.919 51.318 23.053 ;
     RECT  0.144 21.773 0.162 23.089 ;
     RECT  50.112 23.053 51.354 23.125 ;
     RECT  50.112 23.125 51.39 23.131 ;
     RECT  52.164 22.987 52.434 23.131 ;
     RECT  0.108 23.089 0.198 23.213 ;
     RECT  2.304 22.919 25.722 23.76 ;
     RECT  27.396 22.883 27.918 23.76 ;
     RECT  28.944 22.883 36.486 23.76 ;
     RECT  37.656 22.811 42.318 23.76 ;
     RECT  43.344 22.973 43.398 23.76 ;
     RECT  44.568 23.009 44.586 23.76 ;
     RECT  45.54 23.009 48.834 23.76 ;
     RECT  50.112 23.131 52.434 23.76 ;
     RECT  53.532 22.847 54.702 23.76 ;
     RECT  57.06 22.964 58.158 23.76 ;
     RECT  59.292 22.919 59.31 23.76 ;
     RECT  61.668 22.154 61.686 23.76 ;
     RECT  63.144 22.964 63.162 23.76 ;
     RECT  64.368 21.929 64.386 23.76 ;
     RECT  67.788 22.775 68.49 23.76 ;
     RECT  75.24 22.973 75.798 23.76 ;
     RECT  76.968 22.973 76.986 23.76 ;
     RECT  91.368 22.589 91.386 23.76 ;
     RECT  92.376 22.577 92.394 23.76 ;
     RECT  93.492 22.109 93.51 23.76 ;
     RECT  104.976 21.617 104.994 23.76 ;
     RECT  108.936 21.101 109.53 23.76 ;
     RECT  112.284 21.263 112.302 23.76 ;
     RECT  130.788 21.659 130.806 23.76 ;
     RECT  156.168 21.965 156.186 23.76 ;
     RECT  158.652 21.617 158.67 23.76 ;
     RECT  168.912 21.029 168.93 23.76 ;
     RECT  172.8 21.263 172.818 23.76 ;
     RECT  174.42 22.739 174.906 23.76 ;
     RECT  176.868 20.849 177.426 23.76 ;
     RECT  180.324 22.061 180.342 23.76 ;
     RECT  182.916 22.919 182.934 23.76 ;
     RECT  184.032 23.009 184.05 23.76 ;
     RECT  192.96 21.659 192.978 23.76 ;
     RECT  195.3 21.731 199.782 23.76 ;
     RECT  0.144 23.213 0.198 24.043 ;
     RECT  0.144 24.043 0.666 24.232 ;
     RECT  0.108 24.232 0.666 24.467 ;
     RECT  2.304 23.76 199.782 24.511 ;
     RECT  1.404 23.851 1.422 24.619 ;
     RECT  1.152 24.619 1.422 25.291 ;
     RECT  2.268 24.511 199.782 25.291 ;
     RECT  0.108 24.467 0.342 25.675 ;
     RECT  0.108 25.675 0.378 25.805 ;
     RECT  1.152 25.291 199.782 26.357 ;
     RECT  0.108 25.805 0.342 26.429 ;
     RECT  1.152 26.357 1.17 26.765 ;
     RECT  0.144 26.429 0.342 27.053 ;
     RECT  2.304 26.357 199.782 27.403 ;
     RECT  1.692 27.403 199.782 27.499 ;
     RECT  1.26 27.499 199.782 27.533 ;
     RECT  0.216 27.053 0.342 27.595 ;
     RECT  1.26 27.533 199.746 27.595 ;
     RECT  0.216 27.595 199.746 27.779 ;
     RECT  0.108 27.787 0.126 28.319 ;
     RECT  1.188 27.779 199.746 28.507 ;
     RECT  1.152 28.507 199.746 28.859 ;
     RECT  0.288 28.843 0.306 29.371 ;
     RECT  0.144 29.371 0.306 29.419 ;
     RECT  2.304 28.859 199.746 29.489 ;
     RECT  1.152 28.859 1.314 29.611 ;
     RECT  0.144 29.419 0.342 29.707 ;
     RECT  0.108 29.707 0.342 29.831 ;
     RECT  0.144 29.831 0.342 29.899 ;
     RECT  1.152 29.611 1.35 29.899 ;
     RECT  0.144 29.899 1.35 30.029 ;
     RECT  0.504 30.029 1.35 30.209 ;
     RECT  0.54 30.209 1.35 30.479 ;
     RECT  2.34 29.489 199.746 30.509 ;
     RECT  2.34 30.509 196.47 30.685 ;
     RECT  0.54 30.479 1.17 30.749 ;
     RECT  0.54 30.749 0.558 31.051 ;
     RECT  2.304 30.685 196.47 31.243 ;
     RECT  0.504 31.051 0.558 31.339 ;
     RECT  2.268 31.243 196.47 31.373 ;
     RECT  0.324 31.339 0.558 31.483 ;
     RECT  2.268 31.373 196.29 31.765 ;
     RECT  0.216 31.483 0.558 31.829 ;
     RECT  197.388 30.509 199.746 31.891 ;
     RECT  1.728 31.765 196.29 32.621 ;
     RECT  0.108 32.107 0.162 32.683 ;
     RECT  0.108 32.683 0.342 32.813 ;
     RECT  197.208 31.891 199.746 32.813 ;
     RECT  198.324 32.813 199.746 33.005 ;
     RECT  197.208 32.813 197.514 33.043 ;
     RECT  198.432 33.005 199.746 33.293 ;
     RECT  197.172 33.043 197.514 33.389 ;
     RECT  197.172 33.389 197.19 33.677 ;
     RECT  0.108 32.813 0.162 33.835 ;
     RECT  198.504 33.293 199.746 33.869 ;
     RECT  1.728 32.621 196.218 34.027 ;
     RECT  1.368 34.027 196.218 34.061 ;
     RECT  1.368 34.061 196.128 34.253 ;
     RECT  197.496 34.159 197.514 34.315 ;
     RECT  198.504 33.869 199.53 34.315 ;
     RECT  197.496 34.315 199.53 34.507 ;
     RECT  0.108 33.835 0.558 34.603 ;
     RECT  1.368 34.253 1.386 34.603 ;
     RECT  197.244 34.507 199.53 34.603 ;
     RECT  0.108 34.603 1.386 35.267 ;
     RECT  1.152 35.267 1.386 35.275 ;
     RECT  2.304 34.253 196.128 35.275 ;
     RECT  1.152 35.275 196.128 35.851 ;
     RECT  196.92 34.603 199.53 35.851 ;
     RECT  1.152 35.851 199.53 35.924 ;
     RECT  1.152 35.924 196.182 35.981 ;
     RECT  1.152 35.981 1.242 36.077 ;
     RECT  0.108 35.267 0.342 36.139 ;
     RECT  1.152 36.077 1.206 36.139 ;
     RECT  0.108 36.139 1.206 36.149 ;
     RECT  205.452 33.547 205.47 36.509 ;
     RECT  207.615 23.035 207.954 36.545 ;
     RECT  2.304 35.981 196.182 37.129 ;
     RECT  1.728 37.129 196.182 37.709 ;
     RECT  1.764 37.709 196.182 37.805 ;
     RECT  0.108 36.149 0.558 38.003 ;
     RECT  1.8 37.805 196.182 38.189 ;
     RECT  2.268 38.189 196.182 38.381 ;
     RECT  2.376 38.381 196.182 38.471 ;
     RECT  0.108 38.003 0.162 38.923 ;
     RECT  0.108 38.923 0.234 39.019 ;
     RECT  0.108 39.019 0.27 39.055 ;
     RECT  0.108 39.055 0.306 39.403 ;
     RECT  0.108 39.403 0.342 39.623 ;
     RECT  2.415 38.471 196.182 39.691 ;
     RECT  1.152 38.731 1.17 39.785 ;
     RECT  2.304 39.691 196.182 39.829 ;
     RECT  1.728 39.829 196.182 39.979 ;
     RECT  196.92 35.924 199.53 39.979 ;
     RECT  1.728 39.979 199.53 40.109 ;
     RECT  0.144 39.623 0.342 40.135 ;
     RECT  1.728 40.109 196.182 40.361 ;
     RECT  0.144 40.135 0.558 40.459 ;
     RECT  1.728 40.361 3.15 40.733 ;
     RECT  2.268 40.733 3.15 40.739 ;
     RECT  0.108 40.459 0.558 40.865 ;
     RECT  0.144 40.865 0.558 40.937 ;
     RECT  3.888 40.361 196.182 41.251 ;
     RECT  2.268 40.739 3.006 41.611 ;
     RECT  3.744 41.251 196.182 41.611 ;
     RECT  0.144 40.937 0.306 41.707 ;
     RECT  0.108 41.707 0.306 41.791 ;
     RECT  1.152 41.323 1.17 41.791 ;
     RECT  0.108 41.791 1.17 42.029 ;
     RECT  1.152 42.029 1.17 42.557 ;
     RECT  2.268 41.611 196.182 42.827 ;
     RECT  0.108 42.029 0.198 43.339 ;
     RECT  0.108 43.339 0.594 43.627 ;
     RECT  0.108 43.627 0.738 43.757 ;
     RECT  0.108 43.757 0.63 44.249 ;
     RECT  0.144 44.249 0.63 44.381 ;
     RECT  0.324 44.381 0.63 44.491 ;
     RECT  2.304 42.827 196.182 44.717 ;
     RECT  0.324 44.491 1.314 45.163 ;
     RECT  2.34 44.717 196.182 45.451 ;
     RECT  196.92 40.109 199.53 45.689 ;
     RECT  2.304 45.451 196.182 45.832 ;
     RECT  0.108 45.163 1.314 46.507 ;
     RECT  2.268 45.832 196.182 46.507 ;
     RECT  196.956 45.689 199.53 46.769 ;
     RECT  0.108 46.507 196.182 47.489 ;
     RECT  15.768 47.489 196.182 47.611 ;
     RECT  15.768 47.611 196.218 47.789 ;
     RECT  0.108 47.489 15.03 48.119 ;
     RECT  0.108 48.119 14.094 48.263 ;
     RECT  0.108 48.263 1.314 48.929 ;
     RECT  0.108 48.929 1.278 49.307 ;
     RECT  1.152 49.307 1.278 49.379 ;
     RECT  1.224 49.379 1.278 49.649 ;
     RECT  2.304 48.263 14.094 49.739 ;
     RECT  1.26 49.649 1.278 49.775 ;
     RECT  0.108 49.307 0.126 49.883 ;
     RECT  15.768 47.789 196.182 49.981 ;
     RECT  2.304 49.739 5.166 50.251 ;
     RECT  2.268 50.251 5.166 50.288 ;
     RECT  15.12 49.981 196.182 50.359 ;
     RECT  0.144 50.395 0.162 50.443 ;
     RECT  2.304 50.288 5.166 50.491 ;
     RECT  6.048 49.739 14.094 50.491 ;
     RECT  0.144 50.443 0.342 50.573 ;
     RECT  1.152 50.731 1.17 50.923 ;
     RECT  1.152 50.923 1.314 51.053 ;
     RECT  14.832 50.359 196.182 51.125 ;
     RECT  2.304 50.491 14.094 51.205 ;
     RECT  2.268 51.205 14.094 51.341 ;
     RECT  0.108 51.097 0.126 51.439 ;
     RECT  0.108 51.439 0.162 51.475 ;
     RECT  1.152 51.053 1.206 51.475 ;
     RECT  14.832 51.125 14.958 51.539 ;
     RECT  14.832 51.539 14.886 51.665 ;
     RECT  0.108 51.475 1.206 51.935 ;
     RECT  0.144 51.935 1.206 52.277 ;
     RECT  1.188 52.277 1.206 52.313 ;
     RECT  2.304 51.341 14.094 52.363 ;
     RECT  14.832 51.665 14.85 52.363 ;
     RECT  15.768 51.125 196.182 52.555 ;
     RECT  2.268 52.363 14.85 52.591 ;
     RECT  15.732 52.555 196.182 52.591 ;
     RECT  0.144 52.277 0.234 52.744 ;
     RECT  2.268 52.591 196.182 52.987 ;
     RECT  1.728 52.987 196.182 53.051 ;
     RECT  1.728 53.051 196.128 53.069 ;
     RECT  0.108 52.744 0.234 53.125 ;
     RECT  0.108 53.125 0.558 53.227 ;
     RECT  2.304 53.069 196.128 54.175 ;
     RECT  2.268 54.175 196.128 54.317 ;
     RECT  2.376 54.317 196.128 54.473 ;
     RECT  0.108 53.227 1.35 54.797 ;
     RECT  1.152 54.797 1.35 54.905 ;
     RECT  0.108 54.797 0.342 55.085 ;
     RECT  5.616 54.473 196.128 55.283 ;
     RECT  2.376 54.473 4.806 55.387 ;
     RECT  5.616 55.283 14.382 55.387 ;
     RECT  2.376 55.387 14.382 55.481 ;
     RECT  2.376 55.481 2.754 55.517 ;
     RECT  1.332 54.905 1.35 55.531 ;
     RECT  1.332 55.531 1.386 55.627 ;
     RECT  1.332 55.627 1.422 55.787 ;
     RECT  2.376 55.517 2.697 55.819 ;
     RECT  0.108 55.085 0.198 56.059 ;
     RECT  15.372 55.283 196.128 56.093 ;
     RECT  3.528 55.481 14.382 56.191 ;
     RECT  3.528 56.191 14.814 56.291 ;
     RECT  2.304 55.819 2.697 56.299 ;
     RECT  3.528 56.291 14.094 56.299 ;
     RECT  1.368 55.787 1.422 56.597 ;
     RECT  1.404 56.597 1.422 56.633 ;
     RECT  0.108 56.059 0.27 56.839 ;
     RECT  0.108 56.839 0.558 57.005 ;
     RECT  2.304 56.299 14.094 57.307 ;
     RECT  1.98 57.307 14.094 57.343 ;
     RECT  1.98 57.343 14.742 57.379 ;
     RECT  1.98 57.379 14.814 57.485 ;
     RECT  0.108 57.005 0.126 57.739 ;
     RECT  0.108 57.739 0.162 57.835 ;
     RECT  2.268 57.485 14.814 57.983 ;
     RECT  0.108 57.835 0.198 58.027 ;
     RECT  0.108 58.027 0.342 58.459 ;
     RECT  0.108 58.459 0.558 58.507 ;
     RECT  0.108 58.507 0.666 58.637 ;
     RECT  2.268 57.983 14.094 58.657 ;
     RECT  14.832 58.621 14.85 58.721 ;
     RECT  1.728 58.657 14.094 58.729 ;
     RECT  1.728 58.729 14.814 59.117 ;
     RECT  0.108 58.637 0.558 59.213 ;
     RECT  2.304 59.117 14.814 59.261 ;
     RECT  2.304 59.261 14.274 59.765 ;
     RECT  0.108 59.213 0.198 59.947 ;
     RECT  15.768 56.093 196.128 60.079 ;
     RECT  0.108 59.947 0.342 60.115 ;
     RECT  1.152 59.755 1.17 60.115 ;
     RECT  0.108 60.115 1.17 60.173 ;
     RECT  1.152 60.173 1.17 60.427 ;
     RECT  2.34 59.765 14.274 60.619 ;
     RECT  15.336 60.079 196.128 60.619 ;
     RECT  2.34 60.619 196.128 60.715 ;
     RECT  1.152 60.427 1.206 61.099 ;
     RECT  2.304 60.715 196.128 61.151 ;
     RECT  0.108 60.173 0.162 61.195 ;
     RECT  0.108 61.195 0.198 61.231 ;
     RECT  1.152 61.099 1.242 61.231 ;
     RECT  0.108 61.231 1.242 61.517 ;
     RECT  1.188 61.517 1.242 62.005 ;
     RECT  2.304 61.151 14.814 62.005 ;
     RECT  1.188 62.005 14.814 62.033 ;
     RECT  1.188 62.033 14.382 62.189 ;
     RECT  0.108 61.517 0.162 62.195 ;
     RECT  1.188 62.189 1.35 62.251 ;
     RECT  2.304 62.189 14.382 63.013 ;
     RECT  0.108 62.195 0.126 63.067 ;
     RECT  2.304 63.013 14.814 63.113 ;
     RECT  15.768 61.151 196.128 63.307 ;
     RECT  197.496 46.769 199.53 63.499 ;
     RECT  0.108 63.067 0.198 63.661 ;
     RECT  1.152 62.251 1.35 63.661 ;
     RECT  0.108 63.661 1.35 63.821 ;
     RECT  15.696 63.307 196.128 63.887 ;
     RECT  2.304 63.113 14.31 63.931 ;
     RECT  1.152 63.821 1.35 63.979 ;
     RECT  2.304 63.931 14.886 64.049 ;
     RECT  15.696 63.887 15.786 64.121 ;
     RECT  1.152 63.979 1.386 64.219 ;
     RECT  16.524 63.887 196.128 64.363 ;
     RECT  197.244 63.499 199.53 64.363 ;
     RECT  0.108 63.821 0.342 64.625 ;
     RECT  2.304 64.049 14.31 64.661 ;
     RECT  2.304 64.661 14.202 64.769 ;
     RECT  16.524 64.363 199.53 64.8 ;
     RECT  2.304 64.769 14.094 64.843 ;
     RECT  2.268 64.843 14.094 64.859 ;
     RECT  195.696 64.8 199.53 64.859 ;
     RECT  16.524 64.8 23.814 64.925 ;
     RECT  16.524 64.925 23.742 64.931 ;
     RECT  30.204 64.8 30.798 64.973 ;
     RECT  37.404 64.8 37.638 64.973 ;
     RECT  0.144 64.625 0.342 65.011 ;
     RECT  1.152 64.219 1.422 65.011 ;
     RECT  111.888 64.8 111.906 65.021 ;
     RECT  2.268 64.859 9.738 65.165 ;
     RECT  197.496 64.859 199.53 65.201 ;
     RECT  0.144 65.011 1.422 65.273 ;
     RECT  16.524 64.931 23.706 65.273 ;
     RECT  57.384 64.8 57.546 65.273 ;
     RECT  51.876 64.8 53.622 65.309 ;
     RECT  55.296 64.8 55.854 65.309 ;
     RECT  197.496 65.201 198.774 65.354 ;
     RECT  51.876 65.309 52.794 65.405 ;
     RECT  55.404 65.309 55.854 65.405 ;
     RECT  197.532 65.354 198.774 65.435 ;
     RECT  51.876 65.405 52.686 65.453 ;
     RECT  199.512 65.201 199.53 65.471 ;
     RECT  30.78 64.973 30.798 65.501 ;
     RECT  53.604 65.309 53.622 65.501 ;
     RECT  0.144 65.273 1.206 65.515 ;
     RECT  50.724 64.8 50.85 65.549 ;
     RECT  52.56 65.453 52.686 65.549 ;
     RECT  57.384 65.273 57.402 65.549 ;
     RECT  58.716 64.8 58.734 65.549 ;
     RECT  62.928 64.8 62.946 65.549 ;
     RECT  94.824 65.551 94.842 65.645 ;
     RECT  10.692 64.859 14.094 65.677 ;
     RECT  10.62 65.677 14.094 65.741 ;
     RECT  96.084 65.641 96.102 65.821 ;
     RECT  197.532 65.435 198.666 65.849 ;
     RECT  28.512 64.8 29.07 65.911 ;
     RECT  37.404 64.973 37.422 65.911 ;
     RECT  37.404 65.911 37.638 65.981 ;
     RECT  27.936 65.911 29.07 65.995 ;
     RECT  35.676 65.947 35.694 66.011 ;
     RECT  27.036 65.947 27.054 66.019 ;
     RECT  27.936 65.995 29.682 66.019 ;
     RECT  34.164 65.983 34.182 66.029 ;
     RECT  41.04 65.911 41.058 66.029 ;
     RECT  53.64 65.803 53.658 66.029 ;
     RECT  27.036 66.019 29.682 66.055 ;
     RECT  197.928 65.849 198.666 66.083 ;
     RECT  37.404 65.981 37.602 66.091 ;
     RECT  37.044 66.091 37.602 66.173 ;
     RECT  55.836 65.405 55.854 66.379 ;
     RECT  27.036 66.055 29.754 66.413 ;
     RECT  66.996 66.361 67.014 66.427 ;
     RECT  198.036 66.083 198.666 66.434 ;
     RECT  45.288 65.947 45.306 66.475 ;
     RECT  62.784 65.866 62.802 66.475 ;
     RECT  2.304 65.165 9.738 66.479 ;
     RECT  0.108 65.515 1.206 66.515 ;
     RECT  52.452 66.487 52.47 66.557 ;
     RECT  28.512 66.413 29.754 66.559 ;
     RECT  110.916 66.451 110.934 66.559 ;
     RECT  98.46 66.406 98.478 66.595 ;
     RECT  27.036 66.413 27.702 66.631 ;
     RECT  28.512 66.559 30.222 66.631 ;
     RECT  43.344 66.475 43.362 66.631 ;
     RECT  50.724 65.549 50.742 66.631 ;
     RECT  58.752 66.475 58.77 66.631 ;
     RECT  62.784 66.475 62.91 66.631 ;
     RECT  66.672 66.427 67.014 66.631 ;
     RECT  75.24 65.749 75.258 66.631 ;
     RECT  79.2 66.475 79.218 66.631 ;
     RECT  82.476 64.8 82.494 66.631 ;
     RECT  87.948 66.451 87.966 66.631 ;
     RECT  90.648 66.559 90.666 66.631 ;
     RECT  94.608 66.559 94.626 66.631 ;
     RECT  111.816 66.559 111.834 66.631 ;
     RECT  62.64 66.631 62.91 66.653 ;
     RECT  110.592 66.559 110.934 66.658 ;
     RECT  5.616 66.479 9.738 66.659 ;
     RECT  111.744 66.631 111.834 66.659 ;
     RECT  45.288 66.475 45.594 66.667 ;
     RECT  54.72 66.631 54.738 66.667 ;
     RECT  60.3 64.8 60.318 66.667 ;
     RECT  68.112 66.091 68.13 66.667 ;
     RECT  78.66 66.631 79.218 66.667 ;
     RECT  86.616 66.631 86.634 66.667 ;
     RECT  90.648 66.631 90.738 66.667 ;
     RECT  94.536 66.631 94.626 66.667 ;
     RECT  102.564 66.595 102.582 66.667 ;
     RECT  46.692 66.631 46.782 66.676 ;
     RECT  54.684 66.667 54.738 66.676 ;
     RECT  58.68 66.631 58.806 66.676 ;
     RECT  74.628 66.631 75.258 66.676 ;
     RECT  86.616 66.667 86.67 66.676 ;
     RECT  94.536 66.667 94.662 66.676 ;
     RECT  102.564 66.667 102.618 66.676 ;
     RECT  26.748 66.631 27.702 66.704 ;
     RECT  38.7 66.631 38.79 66.704 ;
     RECT  54.684 66.676 54.81 66.704 ;
     RECT  58.68 66.676 58.878 66.704 ;
     RECT  66.636 66.631 67.014 66.704 ;
     RECT  82.476 66.631 82.71 66.704 ;
     RECT  86.544 66.676 86.67 66.704 ;
     RECT  90.612 66.667 90.738 66.704 ;
     RECT  94.464 66.676 94.662 66.704 ;
     RECT  102.492 66.676 102.618 66.704 ;
     RECT  106.56 66.667 106.686 66.704 ;
     RECT  16.524 65.273 23.67 66.721 ;
     RECT  24.516 66.595 24.534 66.721 ;
     RECT  90.612 66.704 90.666 66.721 ;
     RECT  106.56 66.704 106.614 66.721 ;
     RECT  2.304 66.479 4.518 66.749 ;
     RECT  7.056 66.659 9.738 66.749 ;
     RECT  33.624 66.055 33.642 66.749 ;
     RECT  74.556 66.676 75.258 66.749 ;
     RECT  82.476 66.704 82.638 66.749 ;
     RECT  86.544 66.704 86.634 66.749 ;
     RECT  102.492 66.704 102.582 66.749 ;
     RECT  111.744 66.659 111.762 66.749 ;
     RECT  46.62 66.676 46.854 66.785 ;
     RECT  58.788 66.704 58.878 66.785 ;
     RECT  66.672 66.704 67.014 66.811 ;
     RECT  28.512 66.631 30.798 66.829 ;
     RECT  34.74 66.631 34.83 66.829 ;
     RECT  73.512 66.361 73.53 66.829 ;
     RECT  16.524 66.721 24.534 66.859 ;
     RECT  37.404 66.173 37.602 66.859 ;
     RECT  41.58 66.427 41.598 66.859 ;
     RECT  42.732 66.631 43.362 66.859 ;
     RECT  49.716 66.523 49.734 66.859 ;
     RECT  50.688 66.631 50.742 66.859 ;
     RECT  57.312 66.406 57.33 66.859 ;
     RECT  72.972 66.829 73.53 66.859 ;
     RECT  74.664 66.749 75.258 66.859 ;
     RECT  98.46 66.595 98.622 66.859 ;
     RECT  99.756 66.487 99.774 66.859 ;
     RECT  70.632 66.631 70.722 66.865 ;
     RECT  34.74 66.829 35.154 66.901 ;
     RECT  38.772 66.704 38.79 66.901 ;
     RECT  45.036 66.667 45.594 66.901 ;
     RECT  49.716 66.859 50.742 66.901 ;
     RECT  55.656 66.379 55.854 66.901 ;
     RECT  57.312 66.859 57.474 66.901 ;
     RECT  61.596 66.475 61.614 66.901 ;
     RECT  62.64 66.653 62.874 66.901 ;
     RECT  69.696 66.715 69.822 66.901 ;
     RECT  198.144 66.434 198.666 66.929 ;
     RECT  40.104 66.901 40.41 66.941 ;
     RECT  66.672 66.811 67.05 66.943 ;
     RECT  72.792 66.859 73.53 66.943 ;
     RECT  78.624 66.667 79.218 66.943 ;
     RECT  87.948 66.631 88.218 66.943 ;
     RECT  94.464 66.704 94.626 66.943 ;
     RECT  109.692 64.8 109.71 66.943 ;
     RECT  110.556 66.658 110.934 66.943 ;
     RECT  195.696 64.859 196.686 66.943 ;
     RECT  38.772 66.901 39.15 66.955 ;
     RECT  45.036 66.901 45.81 66.955 ;
     RECT  69.3 66.901 69.822 66.955 ;
     RECT  70.596 66.865 70.722 66.955 ;
     RECT  44.46 66.955 45.81 66.991 ;
     RECT  87.948 66.943 88.905 66.991 ;
     RECT  121.215 66.943 121.305 66.991 ;
     RECT  132.015 66.943 132.105 66.991 ;
     RECT  142.815 66.943 142.905 66.991 ;
     RECT  153.615 66.943 153.705 66.991 ;
     RECT  164.415 66.943 164.505 66.991 ;
     RECT  175.215 66.943 175.305 66.991 ;
     RECT  186.015 66.943 186.105 66.991 ;
     RECT  99.54 66.859 99.774 67.003 ;
     RECT  7.056 66.749 9.306 67.019 ;
     RECT  26.784 66.704 27.702 67.019 ;
     RECT  41.58 66.859 43.362 67.019 ;
     RECT  49.716 66.901 51.21 67.019 ;
     RECT  53.316 66.859 53.334 67.019 ;
     RECT  69.3 66.955 70.722 67.019 ;
     RECT  72.615 66.943 73.53 67.019 ;
     RECT  74.664 66.859 75.69 67.019 ;
     RECT  82.476 66.749 82.494 67.019 ;
     RECT  87.948 66.991 89.01 67.019 ;
     RECT  130.68 65.911 130.698 67.019 ;
     RECT  28.512 66.829 30.87 67.027 ;
     RECT  36.612 66.991 36.63 67.027 ;
     RECT  37.404 66.859 37.962 67.027 ;
     RECT  70.668 67.019 70.722 67.027 ;
     RECT  75.42 67.019 75.69 67.027 ;
     RECT  35.892 67.027 37.962 67.037 ;
     RECT  121.104 66.991 121.41 67.037 ;
     RECT  131.904 66.991 132.21 67.037 ;
     RECT  142.704 66.991 143.01 67.037 ;
     RECT  153.504 66.991 153.81 67.037 ;
     RECT  164.304 66.991 164.61 67.037 ;
     RECT  175.104 66.991 175.41 67.037 ;
     RECT  185.904 66.991 186.21 67.037 ;
     RECT  0.108 66.515 0.846 67.055 ;
     RECT  87.948 67.019 87.966 67.055 ;
     RECT  69.48 67.019 69.93 67.085 ;
     RECT  44.46 66.991 45.882 67.091 ;
     RECT  130.428 67.051 130.446 67.091 ;
     RECT  36.756 67.037 37.962 67.127 ;
     RECT  38.772 66.955 39.186 67.127 ;
     RECT  66.672 66.943 67.305 67.127 ;
     RECT  70.668 67.027 70.758 67.127 ;
     RECT  75.42 67.027 75.762 67.127 ;
     RECT  10.692 65.741 14.094 67.133 ;
     RECT  98.424 66.859 98.622 67.133 ;
     RECT  55.656 66.901 57.474 67.147 ;
     RECT  28.512 67.027 30.942 67.163 ;
     RECT  35.892 67.037 35.91 67.163 ;
     RECT  44.46 67.091 44.55 67.163 ;
     RECT  65.556 65.821 65.574 67.171 ;
     RECT  16.524 66.859 25.002 67.199 ;
     RECT  28.512 67.163 30.906 67.199 ;
     RECT  42.12 67.019 42.822 67.199 ;
     RECT  47.88 67.147 47.898 67.199 ;
     RECT  50.148 67.019 51.21 67.199 ;
     RECT  78.015 66.943 79.218 67.199 ;
     RECT  40.215 66.941 40.41 67.213 ;
     RECT  45.288 67.091 45.882 67.213 ;
     RECT  50.724 67.199 51.21 67.213 ;
     RECT  67.215 67.127 67.305 67.213 ;
     RECT  68.112 66.667 68.382 67.213 ;
     RECT  83.415 66.943 83.505 67.213 ;
     RECT  88.704 67.019 89.01 67.213 ;
     RECT  99.54 67.003 99.81 67.213 ;
     RECT  105.015 66.943 105.105 67.213 ;
     RECT  115.815 66.943 115.905 67.213 ;
     RECT  121.215 67.037 121.41 67.213 ;
     RECT  126.615 66.943 126.705 67.213 ;
     RECT  132.015 67.037 132.21 67.213 ;
     RECT  137.415 66.943 137.505 67.213 ;
     RECT  142.815 67.037 143.01 67.213 ;
     RECT  148.215 66.943 148.305 67.213 ;
     RECT  153.615 67.037 153.81 67.213 ;
     RECT  159.015 66.943 159.105 67.213 ;
     RECT  164.415 67.037 164.61 67.213 ;
     RECT  169.815 66.943 169.905 67.213 ;
     RECT  175.215 67.037 175.41 67.213 ;
     RECT  180.615 66.943 180.705 67.213 ;
     RECT  186.015 67.037 186.21 67.213 ;
     RECT  191.415 66.943 191.505 67.213 ;
     RECT  195.696 66.943 196.905 67.213 ;
     RECT  40.215 67.213 40.497 67.243 ;
     RECT  55.656 67.147 57.798 67.243 ;
     RECT  67.215 67.213 68.382 67.243 ;
     RECT  2.304 66.749 3.186 67.289 ;
     RECT  40.215 67.243 41.094 67.289 ;
     RECT  44.028 67.243 44.046 67.289 ;
     RECT  67.215 67.243 68.742 67.289 ;
     RECT  75.42 67.127 75.69 67.289 ;
     RECT  95.652 65.821 96.102 67.289 ;
     RECT  109.692 66.943 110.934 67.289 ;
     RECT  113.364 64.8 113.382 67.289 ;
     RECT  128.196 64.8 128.214 67.289 ;
     RECT  195.696 67.213 197.097 67.297 ;
     RECT  75.42 67.289 75.438 67.325 ;
     RECT  96.084 67.289 96.102 67.325 ;
     RECT  34.704 66.901 35.154 67.333 ;
     RECT  98.424 67.133 98.478 67.333 ;
     RECT  195.552 67.297 197.097 67.333 ;
     RECT  198.18 66.929 198.666 67.361 ;
     RECT  127.944 67.297 127.962 67.373 ;
     RECT  50.724 67.213 51.297 67.387 ;
     RECT  70.704 67.127 70.758 67.387 ;
     RECT  2.304 67.289 2.697 67.397 ;
     RECT  4.032 66.749 4.518 67.397 ;
     RECT  98.28 67.333 98.478 67.405 ;
     RECT  113.184 67.297 113.202 67.405 ;
     RECT  26.784 67.019 27.054 67.421 ;
     RECT  90.648 66.721 90.666 67.433 ;
     RECT  94.215 66.943 94.626 67.433 ;
     RECT  96.156 67.333 96.174 67.433 ;
     RECT  106.596 66.721 106.614 67.433 ;
     RECT  113.112 67.405 113.202 67.433 ;
     RECT  195.516 67.333 197.097 67.433 ;
     RECT  65.556 67.171 65.79 67.435 ;
     RECT  37.332 67.127 37.962 67.441 ;
     RECT  38.772 67.127 39.078 67.441 ;
     RECT  54.72 66.704 54.81 67.441 ;
     RECT  72.615 67.019 72.99 67.441 ;
     RECT  92.844 67.405 92.862 67.441 ;
     RECT  79.2 67.199 79.218 67.469 ;
     RECT  194.364 67.369 194.454 67.469 ;
     RECT  46.764 66.785 46.854 67.483 ;
     RECT  64.656 67.243 64.674 67.483 ;
     RECT  45.288 67.213 45.897 67.531 ;
     RECT  48.384 67.525 48.402 67.531 ;
     RECT  61.596 66.901 62.874 67.531 ;
     RECT  78.015 67.199 78.39 67.531 ;
     RECT  83.415 67.213 83.697 67.531 ;
     RECT  99.54 67.213 99.897 67.531 ;
     RECT  4.032 67.397 4.158 67.559 ;
     RECT  7.056 67.019 8.154 67.559 ;
     RECT  60.3 66.667 60.39 67.559 ;
     RECT  64.548 67.483 64.674 67.559 ;
     RECT  65.556 67.435 66.474 67.559 ;
     RECT  194.364 67.469 194.382 67.559 ;
     RECT  198.216 67.361 198.666 67.559 ;
     RECT  48.384 67.531 48.474 67.565 ;
     RECT  114.588 67.291 114.606 67.565 ;
     RECT  85.5 67.531 85.518 67.568 ;
     RECT  99.504 67.531 99.897 67.568 ;
     RECT  58.824 66.785 58.842 67.579 ;
     RECT  50.724 67.387 51.318 67.595 ;
     RECT  46.764 67.483 46.998 67.613 ;
     RECT  54.72 67.441 54.846 67.627 ;
     RECT  55.584 67.243 57.798 67.627 ;
     RECT  82.692 67.531 83.697 67.627 ;
     RECT  84.492 67.531 84.51 67.627 ;
     RECT  195.552 67.433 197.097 67.631 ;
     RECT  198.216 67.559 198.342 67.631 ;
     RECT  28.512 67.199 29.898 67.639 ;
     RECT  34.704 67.333 35.406 67.661 ;
     RECT  50.976 67.595 51.318 67.661 ;
     RECT  82.692 67.627 84.51 67.661 ;
     RECT  27.936 67.639 29.898 67.667 ;
     RECT  37.332 67.441 39.078 67.667 ;
     RECT  83.415 67.661 84.402 67.667 ;
     RECT  61.596 67.531 63.018 67.675 ;
     RECT  72.252 67.441 72.99 67.675 ;
     RECT  45.288 67.531 45.954 67.711 ;
     RECT  51.012 67.661 51.318 67.711 ;
     RECT  70.704 67.387 70.866 67.711 ;
     RECT  88.704 67.213 89.097 67.711 ;
     RECT  4.14 67.559 4.158 67.739 ;
     RECT  27.936 67.667 29.79 67.757 ;
     RECT  30.78 67.199 30.906 67.757 ;
     RECT  51.012 67.711 51.39 67.757 ;
     RECT  54.72 67.627 57.798 67.757 ;
     RECT  72 67.675 72.99 67.757 ;
     RECT  77.904 67.531 78.39 67.757 ;
     RECT  83.415 67.667 83.79 67.757 ;
     RECT  88.704 67.711 89.19 67.757 ;
     RECT  53.532 67.243 53.658 67.771 ;
     RECT  55.656 67.757 57.798 67.771 ;
     RECT  58.716 67.579 58.842 67.771 ;
     RECT  60.372 67.559 60.39 67.801 ;
     RECT  61.596 67.675 63.414 67.801 ;
     RECT  30.78 67.757 30.798 67.805 ;
     RECT  34.704 67.661 35.262 67.805 ;
     RECT  46.764 67.613 46.926 67.805 ;
     RECT  51.012 67.757 51.297 67.805 ;
     RECT  7.128 67.559 8.154 67.829 ;
     RECT  27.936 67.757 29.697 67.829 ;
     RECT  53.532 67.771 53.874 67.829 ;
     RECT  55.656 67.771 58.842 67.829 ;
     RECT  70.704 67.711 71.262 67.829 ;
     RECT  72 67.757 72.897 67.829 ;
     RECT  0.828 67.055 0.846 67.865 ;
     RECT  92.844 67.441 93.114 67.865 ;
     RECT  195.624 67.631 197.097 67.865 ;
     RECT  98.208 67.405 98.478 67.867 ;
     RECT  28.764 67.829 29.697 67.901 ;
     RECT  55.656 67.829 57.798 67.901 ;
     RECT  55.656 67.901 57.762 67.937 ;
     RECT  107.172 67.909 107.19 67.949 ;
     RECT  65.772 67.559 66.474 67.963 ;
     RECT  67.215 67.289 68.418 67.963 ;
     RECT  40.215 67.289 41.022 67.981 ;
     RECT  98.208 67.867 98.73 67.997 ;
     RECT  60.372 67.801 63.414 68.009 ;
     RECT  88.704 67.757 89.097 68.009 ;
     RECT  34.704 67.805 35.097 68.011 ;
     RECT  42.768 67.199 42.822 68.011 ;
     RECT  58.716 67.829 58.842 68.011 ;
     RECT  29.304 67.901 29.697 68.045 ;
     RECT  40.104 67.981 41.022 68.071 ;
     RECT  34.632 68.011 35.097 68.099 ;
     RECT  37.332 67.667 38.79 68.099 ;
     RECT  53.568 67.829 53.586 68.099 ;
     RECT  70.704 67.829 71.226 68.099 ;
     RECT  72.072 67.829 72.897 68.099 ;
     RECT  16.524 67.199 24.534 68.107 ;
     RECT  48.456 67.565 48.474 68.135 ;
     RECT  40.104 68.071 41.49 68.141 ;
     RECT  71.1 68.099 71.226 68.141 ;
     RECT  74.664 67.019 74.682 68.141 ;
     RECT  98.208 67.997 98.622 68.141 ;
     RECT  102.528 67.867 102.546 68.141 ;
     RECT  58.716 68.011 58.878 68.155 ;
     RECT  40.104 68.141 40.77 68.207 ;
     RECT  16.524 68.107 24.57 68.279 ;
     RECT  196.344 67.865 197.097 68.279 ;
     RECT  33.552 68.245 33.57 68.285 ;
     RECT  46.764 67.805 46.89 68.285 ;
     RECT  58.716 68.155 58.95 68.285 ;
     RECT  64.764 68.251 64.782 68.299 ;
     RECT  16.524 68.279 24.534 68.369 ;
     RECT  198.216 67.631 198.234 68.369 ;
     RECT  105.015 67.213 105.297 68.395 ;
     RECT  65.772 67.963 68.418 68.405 ;
     RECT  26.82 67.421 27.054 68.441 ;
     RECT  45.288 67.711 45.99 68.441 ;
     RECT  54.72 67.757 54.738 68.491 ;
     RECT  16.524 68.369 24.462 68.525 ;
     RECT  26.82 68.441 26.91 68.539 ;
     RECT  46.836 68.285 46.89 68.539 ;
     RECT  64.404 68.299 64.782 68.539 ;
     RECT  30.996 68.539 31.014 68.587 ;
     RECT  10.692 67.133 11.538 68.621 ;
     RECT  59.724 68.491 59.742 68.621 ;
     RECT  55.656 67.937 57.546 68.639 ;
     RECT  105.015 68.395 105.966 68.639 ;
     RECT  30.924 68.587 31.014 68.668 ;
     RECT  30.816 68.668 31.014 68.669 ;
     RECT  46.836 68.539 47.07 68.669 ;
     RECT  60.552 68.009 63.414 68.675 ;
     RECT  105.015 68.639 105.606 68.675 ;
     RECT  29.415 68.045 29.697 68.683 ;
     RECT  34.815 68.099 35.097 68.683 ;
     RECT  51.015 67.805 51.297 68.683 ;
     RECT  94.215 67.433 94.554 68.711 ;
     RECT  46.836 68.669 46.998 68.717 ;
     RECT  61.2 68.675 63.414 68.731 ;
     RECT  64.368 68.539 64.782 68.731 ;
     RECT  69.48 67.085 69.534 68.731 ;
     RECT  54.72 68.491 54.846 68.779 ;
     RECT  49.68 68.683 49.698 68.791 ;
     RECT  61.2 68.731 64.782 68.791 ;
     RECT  69.48 68.731 70.11 68.791 ;
     RECT  29.415 68.683 29.754 68.819 ;
     RECT  55.656 68.639 57.042 68.819 ;
     RECT  69.3 68.791 70.11 68.819 ;
     RECT  49.644 68.791 49.698 68.827 ;
     RECT  61.2 68.791 64.89 68.861 ;
     RECT  69.3 68.819 69.534 68.861 ;
     RECT  49.644 68.827 49.77 68.872 ;
     RECT  49.572 68.872 49.77 68.909 ;
     RECT  64.368 68.861 64.89 68.915 ;
     RECT  68.328 68.405 68.418 68.915 ;
     RECT  61.2 68.861 63.414 68.945 ;
     RECT  29.415 68.819 29.718 68.953 ;
     RECT  34.815 68.683 35.154 68.953 ;
     RECT  37.728 68.099 38.79 68.953 ;
     RECT  40.104 68.207 40.497 68.953 ;
     RECT  51.015 68.683 51.354 68.953 ;
     RECT  49.68 68.909 49.698 68.957 ;
     RECT  61.596 68.945 63.414 68.957 ;
     RECT  37.728 68.953 38.862 68.971 ;
     RECT  40.104 68.953 40.518 68.971 ;
     RECT  42.768 68.011 42.894 68.971 ;
     RECT  54.72 68.779 54.882 68.971 ;
     RECT  55.656 68.819 56.898 68.971 ;
     RECT  61.596 68.957 63.198 68.981 ;
     RECT  58.788 68.285 58.95 69.025 ;
     RECT  72.504 68.099 72.897 69.061 ;
     RECT  40.104 68.971 40.59 69.067 ;
     RECT  61.596 68.981 63.162 69.089 ;
     RECT  29.304 68.953 29.718 69.101 ;
     RECT  40.104 69.067 40.698 69.101 ;
     RECT  58.716 69.025 58.95 69.101 ;
     RECT  72.432 69.061 72.897 69.101 ;
     RECT  30.816 68.669 30.978 69.149 ;
     RECT  42.768 68.971 43.002 69.149 ;
     RECT  46.836 68.717 46.962 69.149 ;
     RECT  74.664 68.971 74.79 69.149 ;
     RECT  69.48 68.861 69.534 69.179 ;
     RECT  72.504 69.101 72.897 69.179 ;
     RECT  86.652 69.019 86.778 69.197 ;
     RECT  54.72 68.971 56.898 69.215 ;
     RECT  86.652 69.197 86.67 69.245 ;
     RECT  40.215 69.101 40.698 69.287 ;
     RECT  68.4 68.915 68.418 69.287 ;
     RECT  74.664 69.149 74.682 69.293 ;
     RECT  79.164 68.971 79.182 69.293 ;
     RECT  34.704 68.953 35.154 69.307 ;
     RECT  45.504 68.441 45.99 69.307 ;
     RECT  50.904 68.953 51.354 69.307 ;
     RECT  58.716 69.101 58.842 69.341 ;
     RECT  37.044 68.971 38.862 69.389 ;
     RECT  65.772 68.405 67.59 69.448 ;
     RECT  56.304 69.215 56.898 69.485 ;
     RECT  64.368 68.915 64.422 69.485 ;
     RECT  65.628 69.448 67.59 69.485 ;
     RECT  16.524 68.525 24.354 69.499 ;
     RECT  34.704 69.307 35.262 69.533 ;
     RECT  29.415 69.101 29.718 69.547 ;
     RECT  30.816 69.149 30.906 69.547 ;
     RECT  46.836 69.149 46.89 69.547 ;
     RECT  50.904 69.307 51.426 69.547 ;
     RECT  92.844 67.865 92.862 69.557 ;
     RECT  37.044 69.389 38.646 69.593 ;
     RECT  65.772 69.485 67.59 69.593 ;
     RECT  50.904 69.547 51.534 69.643 ;
     RECT  58.716 69.341 58.734 69.677 ;
     RECT  64.368 69.485 64.386 69.719 ;
     RECT  9.072 67.019 9.306 69.725 ;
     RECT  94.215 68.711 94.497 69.739 ;
     RECT  61.704 69.089 63.162 69.755 ;
     RECT  82.656 68.443 82.674 69.773 ;
     RECT  44.46 69.223 44.478 69.787 ;
     RECT  44.352 69.787 44.478 69.827 ;
     RECT  94.215 69.739 95.13 69.869 ;
     RECT  29.415 69.547 29.826 69.931 ;
     RECT  42.768 69.149 42.786 69.931 ;
     RECT  72.615 69.179 72.897 69.931 ;
     RECT  77.904 67.757 78.297 69.931 ;
     RECT  83.415 67.757 83.697 69.931 ;
     RECT  88.815 68.009 89.097 69.931 ;
     RECT  29.415 69.931 29.862 69.961 ;
     RECT  30.78 69.547 30.906 69.961 ;
     RECT  90.72 69.835 90.738 69.965 ;
     RECT  16.524 69.499 24.462 69.989 ;
     RECT  29.415 69.961 30.906 69.989 ;
     RECT  54.72 69.215 55.278 69.989 ;
     RECT  66.708 69.593 67.59 69.989 ;
     RECT  72.615 69.931 72.99 69.989 ;
     RECT  77.904 69.931 78.39 69.989 ;
     RECT  83.415 69.931 83.79 69.989 ;
     RECT  88.815 69.931 89.19 69.989 ;
     RECT  30.564 69.989 30.906 70.013 ;
     RECT  45.504 69.307 46.026 70.027 ;
     RECT  46.764 69.547 46.89 70.027 ;
     RECT  53.928 69.421 53.946 70.069 ;
     RECT  52.992 69.547 53.01 70.097 ;
     RECT  9.288 69.725 9.306 70.123 ;
     RECT  50.616 69.643 51.534 70.123 ;
     RECT  53.892 70.069 53.946 70.123 ;
     RECT  54.72 69.989 54.954 70.123 ;
     RECT  88.815 69.989 89.097 70.123 ;
     RECT  98.208 68.141 98.226 70.123 ;
     RECT  10.908 68.621 11.538 70.133 ;
     RECT  109.692 67.289 110.754 70.133 ;
     RECT  53.892 70.123 54.954 70.157 ;
     RECT  50.616 70.123 51.858 70.169 ;
     RECT  77.904 69.989 78.297 70.169 ;
     RECT  42.768 69.931 42.894 70.171 ;
     RECT  29.415 69.989 29.79 70.219 ;
     RECT  48.42 69.787 48.438 70.259 ;
     RECT  26.784 68.539 26.91 70.3 ;
     RECT  30.96 70.171 30.978 70.301 ;
     RECT  37.044 69.593 37.314 70.301 ;
     RECT  42.768 70.171 43.146 70.301 ;
     RECT  45.504 70.027 46.89 70.301 ;
     RECT  98.208 70.123 98.622 70.301 ;
     RECT  45.504 70.301 46.782 70.303 ;
     RECT  58.752 70.171 58.878 70.303 ;
     RECT  26.784 70.3 26.946 70.315 ;
     RECT  40.215 69.287 40.59 70.315 ;
     RECT  45 70.303 46.782 70.331 ;
     RECT  40.215 70.315 40.662 70.339 ;
     RECT  42.768 70.301 43.074 70.349 ;
     RECT  54 70.157 54.954 70.349 ;
     RECT  26.784 70.315 27.342 70.363 ;
     RECT  34.704 69.533 35.19 70.363 ;
     RECT  72.615 69.989 72.897 70.363 ;
     RECT  37.044 70.301 37.242 70.397 ;
     RECT  40.215 70.339 40.734 70.397 ;
     RECT  42.768 70.349 42.966 70.397 ;
     RECT  58.752 70.303 59.238 70.397 ;
     RECT  33.084 70.123 33.102 70.403 ;
     RECT  45 70.331 45.99 70.403 ;
     RECT  58.752 70.397 59.13 70.411 ;
     RECT  34.704 70.363 35.298 70.439 ;
     RECT  40.215 70.397 40.662 70.439 ;
     RECT  54 70.349 54.882 70.439 ;
     RECT  46.764 70.331 46.782 70.445 ;
     RECT  7.128 67.829 8.097 70.459 ;
     RECT  37.044 70.397 37.062 70.493 ;
     RECT  49.032 70.501 49.05 70.507 ;
     RECT  7.128 70.459 8.55 70.529 ;
     RECT  26.64 70.363 27.342 70.529 ;
     RECT  52.488 70.267 52.506 70.529 ;
     RECT  72.36 70.363 72.897 70.529 ;
     RECT  49.032 70.507 49.158 70.541 ;
     RECT  114.588 70.363 114.606 70.541 ;
     RECT  56.304 69.485 56.79 70.589 ;
     RECT  26.64 70.529 26.658 70.6 ;
     RECT  50.616 70.169 51.498 70.6 ;
     RECT  71.568 70.555 71.586 70.601 ;
     RECT  26.532 70.6 26.658 70.637 ;
     RECT  49.14 70.541 49.158 70.637 ;
     RECT  50.4 70.6 51.498 70.637 ;
     RECT  58.716 70.411 59.13 70.637 ;
     RECT  10.908 70.133 11.214 70.645 ;
     RECT  61.815 69.755 63.162 70.645 ;
     RECT  83.415 69.989 83.697 70.645 ;
     RECT  94.215 69.869 94.497 70.645 ;
     RECT  50.724 70.637 51.297 70.685 ;
     RECT  54 70.439 54.846 70.685 ;
     RECT  56.304 70.589 56.754 70.685 ;
     RECT  66.708 69.989 67.497 70.685 ;
     RECT  5.616 66.659 6.282 70.699 ;
     RECT  7.128 70.529 8.097 70.699 ;
     RECT  9.288 70.123 9.45 70.699 ;
     RECT  10.548 70.645 11.214 70.709 ;
     RECT  113.112 67.433 113.13 70.709 ;
     RECT  38.16 69.593 38.646 70.733 ;
     RECT  83.304 70.645 83.697 70.733 ;
     RECT  88.704 70.123 89.097 70.733 ;
     RECT  94.104 70.645 94.497 70.733 ;
     RECT  40.215 70.439 40.59 70.747 ;
     RECT  42.768 70.397 42.822 70.747 ;
     RECT  16.524 69.989 24.39 70.771 ;
     RECT  45.432 70.403 45.99 70.799 ;
     RECT  16.524 70.771 24.57 70.829 ;
     RECT  106.56 70.699 106.578 70.835 ;
     RECT  75.852 70.699 75.87 70.877 ;
     RECT  29.304 70.219 29.79 70.915 ;
     RECT  40.104 70.747 40.59 70.915 ;
     RECT  69.48 69.179 69.498 70.939 ;
     RECT  29.088 70.915 29.79 70.973 ;
     RECT  86.652 70.843 86.67 70.973 ;
     RECT  16.524 70.829 24.534 70.979 ;
     RECT  10.548 70.709 10.926 71.021 ;
     RECT  14.832 70.891 14.85 71.021 ;
     RECT  8.892 70.699 9.45 71.069 ;
     RECT  42.156 70.747 42.822 71.069 ;
     RECT  59.868 70.987 59.886 71.069 ;
     RECT  69.444 70.939 69.498 71.069 ;
     RECT  77.076 70.699 77.094 71.069 ;
     RECT  61.704 70.645 63.162 71.077 ;
     RECT  10.836 71.021 10.926 71.117 ;
     RECT  16.524 70.979 22.914 71.117 ;
     RECT  60.984 71.077 63.162 71.117 ;
     RECT  5.616 70.699 8.097 71.165 ;
     RECT  76.752 71.131 76.77 71.177 ;
     RECT  9.288 71.069 9.45 71.221 ;
     RECT  78.015 70.169 78.297 71.221 ;
     RECT  5.616 71.165 6.93 71.261 ;
     RECT  9.288 71.221 9.594 71.261 ;
     RECT  29.304 70.973 29.79 71.261 ;
     RECT  61.704 71.117 63.162 71.261 ;
     RECT  33.66 70.699 33.678 71.275 ;
     RECT  34.704 70.439 35.097 71.275 ;
     RECT  42.768 71.069 42.822 71.275 ;
     RECT  66.996 70.685 67.497 71.275 ;
     RECT  30.924 71.275 30.942 71.311 ;
     RECT  86.976 71.275 86.994 71.339 ;
     RECT  26.892 71.275 26.91 71.371 ;
     RECT  37.152 71.275 37.17 71.371 ;
     RECT  45.504 70.799 45.99 71.371 ;
     RECT  46.872 71.275 46.89 71.371 ;
     RECT  72.504 70.529 72.897 71.371 ;
     RECT  18.576 71.117 22.914 71.405 ;
     RECT  26.784 71.371 26.91 71.405 ;
     RECT  30.78 71.311 30.942 71.405 ;
     RECT  54.72 70.685 54.774 71.405 ;
     RECT  58.716 70.637 58.734 71.405 ;
     RECT  18.576 71.405 22.842 71.411 ;
     RECT  30.78 71.405 30.834 71.411 ;
     RECT  54.72 71.405 54.738 71.411 ;
     RECT  61.815 71.261 63.162 71.411 ;
     RECT  62.928 71.411 63.162 71.419 ;
     RECT  18.576 71.411 22.518 71.453 ;
     RECT  37.008 71.371 37.17 71.467 ;
     RECT  33.66 71.275 35.118 71.491 ;
     RECT  46.764 71.371 46.89 71.501 ;
     RECT  45.504 71.371 46.026 71.519 ;
     RECT  30.816 71.411 30.834 71.549 ;
     RECT  39.924 70.915 40.59 71.549 ;
     RECT  50.904 70.685 51.297 71.563 ;
     RECT  56.304 70.685 56.718 71.563 ;
     RECT  66.996 71.275 67.518 71.563 ;
     RECT  77.904 71.221 78.297 71.563 ;
     RECT  83.415 70.733 83.697 71.563 ;
     RECT  45.504 71.519 45.99 71.597 ;
     RECT  33.084 71.491 35.19 71.609 ;
     RECT  36.792 71.467 37.17 71.609 ;
     RECT  50.904 71.563 51.39 71.609 ;
     RECT  54 71.467 54.018 71.609 ;
     RECT  56.304 71.563 56.79 71.609 ;
     RECT  61.815 71.411 62.19 71.609 ;
     RECT  62.928 71.419 63.846 71.609 ;
     RECT  72.504 71.371 73.53 71.609 ;
     RECT  77.904 71.563 78.39 71.609 ;
     RECT  83.415 71.563 83.79 71.609 ;
     RECT  43.812 71.515 43.83 71.611 ;
     RECT  16.524 71.117 17.802 71.645 ;
     RECT  23.904 70.979 24.534 71.645 ;
     RECT  26.784 71.405 26.802 71.645 ;
     RECT  33.084 71.609 33.102 71.645 ;
     RECT  52.884 71.608 52.902 71.645 ;
     RECT  71.208 71.581 71.226 71.645 ;
     RECT  43.704 71.611 43.83 71.693 ;
     RECT  70.38 71.653 70.398 71.693 ;
     RECT  72.504 71.609 72.897 71.707 ;
     RECT  43.704 71.693 43.722 71.741 ;
     RECT  50.904 71.609 51.297 71.752 ;
     RECT  88.815 70.733 89.097 71.752 ;
     RECT  62.928 71.609 63.162 71.753 ;
     RECT  37.044 71.609 37.17 71.789 ;
     RECT  50.724 71.752 51.297 71.789 ;
     RECT  88.704 71.752 89.097 71.888 ;
     RECT  63.144 71.753 63.162 71.915 ;
     RECT  38.304 70.733 38.646 71.951 ;
     RECT  16.524 71.645 17.622 71.981 ;
     RECT  90.648 71.851 90.666 71.981 ;
     RECT  5.616 71.261 6.282 71.987 ;
     RECT  72.396 71.707 72.897 71.995 ;
     RECT  12.528 67.133 14.094 72.077 ;
     RECT  69.48 71.069 69.498 72.121 ;
     RECT  66.996 71.563 67.59 72.139 ;
     RECT  109.692 70.133 110.697 72.149 ;
     RECT  42.768 71.275 42.894 72.157 ;
     RECT  66.996 72.139 67.914 72.157 ;
     RECT  47.088 71.947 47.106 72.173 ;
     RECT  68.796 72.121 69.498 72.173 ;
     RECT  41.616 72.139 41.634 72.185 ;
     RECT  66.708 72.157 67.914 72.185 ;
     RECT  66.708 72.185 67.497 72.257 ;
     RECT  72.108 71.995 72.897 72.257 ;
     RECT  16.524 71.981 16.974 72.269 ;
     RECT  23.904 71.645 24.39 72.329 ;
     RECT  45.504 71.597 45.897 72.329 ;
     RECT  77.904 71.609 78.297 72.329 ;
     RECT  9.288 71.261 9.306 72.379 ;
     RECT  10.908 71.117 10.926 72.379 ;
     RECT  12.528 72.077 13.59 72.379 ;
     RECT  18.615 71.453 22.518 72.379 ;
     RECT  40.215 71.549 40.59 72.379 ;
     RECT  42.768 72.157 42.93 72.379 ;
     RECT  70.992 72.235 71.01 72.379 ;
     RECT  69.48 72.173 69.498 72.391 ;
     RECT  9.288 72.379 10.026 72.419 ;
     RECT  66.996 72.257 67.497 72.419 ;
     RECT  46.692 72.379 46.89 72.427 ;
     RECT  70.992 72.379 71.046 72.427 ;
     RECT  50.904 71.789 51.297 72.455 ;
     RECT  10.836 72.379 10.926 72.461 ;
     RECT  18.615 72.379 22.842 72.475 ;
     RECT  54.72 72.379 54.738 72.475 ;
     RECT  26.964 72.379 26.982 72.509 ;
     RECT  30.78 72.379 30.798 72.509 ;
     RECT  10.836 72.461 10.854 72.523 ;
     RECT  18 72.475 22.842 72.523 ;
     RECT  24.015 72.329 24.39 72.523 ;
     RECT  34.704 71.609 35.19 72.523 ;
     RECT  37.044 71.789 37.062 72.523 ;
     RECT  45.615 72.329 45.897 72.523 ;
     RECT  46.656 72.427 46.89 72.523 ;
     RECT  51.015 72.455 51.297 72.523 ;
     RECT  54.072 72.475 54.738 72.523 ;
     RECT  65.772 69.593 65.826 72.523 ;
     RECT  59.04 72.379 59.058 72.557 ;
     RECT  29.415 71.261 29.79 72.565 ;
     RECT  40.104 72.379 40.59 72.565 ;
     RECT  29.415 72.565 29.862 72.605 ;
     RECT  56.304 71.609 56.697 72.619 ;
     RECT  18 72.523 22.914 72.653 ;
     RECT  30.888 72.523 30.978 72.653 ;
     RECT  54.072 72.523 54.954 72.661 ;
     RECT  70.992 72.427 71.262 72.661 ;
     RECT  12.276 72.379 13.59 72.689 ;
     RECT  18 72.653 19.53 72.689 ;
     RECT  44.64 72.379 44.658 72.689 ;
     RECT  54.072 72.661 55.206 72.689 ;
     RECT  64.296 72.427 64.314 72.689 ;
     RECT  61.815 71.609 62.097 72.697 ;
     RECT  70.704 72.661 71.262 72.701 ;
     RECT  130.536 72.523 130.554 72.701 ;
     RECT  51.015 72.523 51.498 72.715 ;
     RECT  98.208 70.301 98.226 72.725 ;
     RECT  10.8 72.523 10.854 72.749 ;
     RECT  54.72 72.689 55.206 72.749 ;
     RECT  38.628 71.951 38.646 72.76 ;
     RECT  71.244 72.701 71.262 72.76 ;
     RECT  69.48 72.391 69.93 72.763 ;
     RECT  42.768 72.379 43.47 72.797 ;
     RECT  45.615 72.523 46.89 72.797 ;
     RECT  65.412 72.523 65.826 72.797 ;
     RECT  71.244 72.76 71.802 72.797 ;
     RECT  74.628 72.667 74.646 72.797 ;
     RECT  13.215 72.689 13.59 72.805 ;
     RECT  24.015 72.523 24.534 72.805 ;
     RECT  20.592 72.653 22.914 72.811 ;
     RECT  34.704 72.523 35.334 72.811 ;
     RECT  40.104 72.565 40.662 72.811 ;
     RECT  65.808 72.797 65.826 72.811 ;
     RECT  61.776 72.697 62.73 72.841 ;
     RECT  12.384 72.689 12.402 72.845 ;
     RECT  13.215 72.805 13.698 72.845 ;
     RECT  24.015 72.805 24.642 72.845 ;
     RECT  37.044 72.523 37.17 72.845 ;
     RECT  51.015 72.715 51.678 72.845 ;
     RECT  34.704 72.811 35.442 72.869 ;
     RECT  40.104 72.811 40.842 72.869 ;
     RECT  61.704 72.841 62.73 72.869 ;
     RECT  61.704 72.869 62.097 72.893 ;
     RECT  29.415 72.605 29.79 72.907 ;
     RECT  18.432 72.689 19.53 72.941 ;
     RECT  20.592 72.811 22.986 72.941 ;
     RECT  37.044 72.845 37.062 72.941 ;
     RECT  46.836 72.797 46.89 72.941 ;
     RECT  64.98 72.811 64.998 72.959 ;
     RECT  65.808 72.811 65.97 72.959 ;
     RECT  69.48 72.763 70.146 72.959 ;
     RECT  71.244 72.797 71.262 72.959 ;
     RECT  40.104 72.869 40.698 73.051 ;
     RECT  88.815 71.888 89.097 73.051 ;
     RECT  83.415 71.609 83.697 73.099 ;
     RECT  13.215 72.845 13.59 73.133 ;
     RECT  42.768 72.797 42.894 73.133 ;
     RECT  118.584 73.003 118.602 73.133 ;
     RECT  38.628 72.76 38.754 73.147 ;
     RECT  39.672 73.051 40.698 73.147 ;
     RECT  44.784 72.955 44.802 73.147 ;
     RECT  45.615 72.797 45.99 73.147 ;
     RECT  42.768 73.133 42.786 73.181 ;
     RECT  44.784 73.147 45.99 73.181 ;
     RECT  61.776 72.893 62.097 73.181 ;
     RECT  10.008 72.419 10.026 73.229 ;
     RECT  20.592 72.941 22.914 73.229 ;
     RECT  38.628 73.147 40.698 73.229 ;
     RECT  44.784 73.181 45.897 73.229 ;
     RECT  83.415 73.099 83.79 73.229 ;
     RECT  88.632 73.051 89.478 73.229 ;
     RECT  10.8 72.749 10.818 73.277 ;
     RECT  14.94 73.099 14.958 73.277 ;
     RECT  18.615 72.941 19.53 73.277 ;
     RECT  21.06 73.229 22.914 73.277 ;
     RECT  26.784 72.523 26.91 73.277 ;
     RECT  29.304 72.907 29.79 73.277 ;
     RECT  30.888 72.653 30.906 73.277 ;
     RECT  38.628 73.229 38.97 73.277 ;
     RECT  46.872 72.941 46.89 73.277 ;
     RECT  51.015 72.845 51.498 73.277 ;
     RECT  56.304 72.619 56.79 73.291 ;
     RECT  16.524 72.269 16.542 73.325 ;
     RECT  34.704 72.869 35.298 73.337 ;
     RECT  40.032 73.229 40.698 73.337 ;
     RECT  82.152 73.291 82.17 73.337 ;
     RECT  24.015 72.845 24.498 73.373 ;
     RECT  26.784 73.277 26.802 73.373 ;
     RECT  34.704 73.337 35.226 73.373 ;
     RECT  24.015 73.373 24.297 73.381 ;
     RECT  51.015 73.277 51.297 73.381 ;
     RECT  63.18 73.339 63.198 73.409 ;
     RECT  50.904 73.381 51.297 73.421 ;
     RECT  56.304 73.291 57.258 73.421 ;
     RECT  40.032 73.337 40.497 73.469 ;
     RECT  54.72 72.749 54.846 73.469 ;
     RECT  54.828 73.469 54.846 73.517 ;
     RECT  5.616 71.987 5.814 73.571 ;
     RECT  69.48 72.959 69.498 73.571 ;
     RECT  5.796 73.571 5.814 73.607 ;
     RECT  65.808 72.959 65.826 73.607 ;
     RECT  61.815 73.181 62.097 73.741 ;
     RECT  34.704 73.373 35.154 73.769 ;
     RECT  36.252 73.579 36.27 73.769 ;
     RECT  58.032 73.627 58.05 73.769 ;
     RECT  59.148 73.531 59.166 73.769 ;
     RECT  63.792 73.531 63.81 73.769 ;
     RECT  61.815 73.741 62.694 73.805 ;
     RECT  21.06 73.277 22.518 73.853 ;
     RECT  21.06 73.853 22.158 73.901 ;
     RECT  29.304 73.277 29.697 73.912 ;
     RECT  29.088 73.912 29.697 73.949 ;
     RECT  56.304 73.421 56.697 73.949 ;
     RECT  58.716 73.819 58.734 73.949 ;
     RECT  21.06 73.901 21.69 74.045 ;
     RECT  21.06 74.045 21.078 74.093 ;
     RECT  18.615 73.277 18.897 74.347 ;
     RECT  23.904 73.381 24.297 74.489 ;
     RECT  34.704 73.769 35.097 74.489 ;
     RECT  45.504 73.229 45.897 74.489 ;
     RECT  56.415 73.949 56.697 74.581 ;
     RECT  14.832 74.347 14.85 74.621 ;
     RECT  18.615 74.347 18.918 74.621 ;
     RECT  56.415 74.581 57.33 74.621 ;
     RECT  56.415 74.621 57.042 74.624 ;
     RECT  86.652 74.683 86.67 74.861 ;
     RECT  136.08 64.8 136.098 77.279 ;
     RECT  38.628 73.277 38.646 77.315 ;
     RECT  2.415 67.397 2.697 86.147 ;
     RECT  7.815 71.165 8.097 86.147 ;
     RECT  13.215 73.133 13.497 86.147 ;
     RECT  18.615 74.621 18.897 86.147 ;
     RECT  24.015 74.489 24.297 86.147 ;
     RECT  29.415 73.949 29.697 86.147 ;
     RECT  34.815 74.489 35.097 86.147 ;
     RECT  40.215 73.469 40.497 86.147 ;
     RECT  45.615 74.489 45.897 86.147 ;
     RECT  51.015 73.421 51.297 86.147 ;
     RECT  56.415 74.624 56.697 86.147 ;
     RECT  61.815 73.805 62.097 86.147 ;
     RECT  67.215 72.419 67.497 86.147 ;
     RECT  72.615 72.257 72.897 86.147 ;
     RECT  78.015 72.329 78.297 86.147 ;
     RECT  83.415 73.229 83.697 86.147 ;
     RECT  88.815 73.229 89.097 86.147 ;
     RECT  94.215 70.733 94.497 86.147 ;
     RECT  99.615 67.568 99.897 86.147 ;
     RECT  105.015 68.675 105.297 86.147 ;
     RECT  110.415 72.149 110.697 86.147 ;
     RECT  115.815 67.213 116.097 86.147 ;
     RECT  121.215 67.213 121.497 86.147 ;
     RECT  126.615 67.213 126.897 86.147 ;
     RECT  132.015 67.213 132.297 86.147 ;
     RECT  137.415 67.213 137.697 86.147 ;
     RECT  142.815 67.213 143.097 86.147 ;
     RECT  148.215 67.213 148.497 86.147 ;
     RECT  153.615 67.213 153.897 86.147 ;
     RECT  159.015 67.213 159.297 86.147 ;
     RECT  164.415 67.213 164.697 86.147 ;
     RECT  169.815 67.213 170.097 86.147 ;
     RECT  175.215 67.213 175.497 86.147 ;
     RECT  180.615 67.213 180.897 86.147 ;
     RECT  186.015 67.213 186.297 86.147 ;
     RECT  191.415 67.213 191.697 86.147 ;
     RECT  196.815 68.279 197.097 86.147 ;
     RECT  202.215 2.413 202.497 86.147 ;
     RECT  207.615 36.545 207.897 86.147 ;
     RECT  213.015 2.413 213.297 86.147 ;
     RECT  2.415 86.147 2.505 86.417 ;
     RECT  7.815 86.147 7.905 86.417 ;
     RECT  13.215 86.147 13.305 86.417 ;
     RECT  18.615 86.147 18.705 86.417 ;
     RECT  24.015 86.147 24.105 86.417 ;
     RECT  29.415 86.147 29.505 86.417 ;
     RECT  34.815 86.147 34.905 86.417 ;
     RECT  40.215 86.147 40.305 86.417 ;
     RECT  45.615 86.147 45.705 86.417 ;
     RECT  51.015 86.147 51.105 86.417 ;
     RECT  56.415 86.147 56.505 86.417 ;
     RECT  61.815 86.147 61.905 86.417 ;
     RECT  67.215 86.147 67.305 86.417 ;
     RECT  72.615 86.147 72.705 86.417 ;
     RECT  78.015 86.147 78.105 86.417 ;
     RECT  83.415 86.147 83.505 86.417 ;
     RECT  88.815 86.147 88.905 86.417 ;
     RECT  94.215 86.147 94.305 86.417 ;
     RECT  99.615 86.147 99.705 86.417 ;
     RECT  105.015 86.147 105.105 86.417 ;
     RECT  110.415 86.147 110.505 86.417 ;
     RECT  115.815 86.147 115.905 86.417 ;
     RECT  121.215 86.147 121.305 86.417 ;
     RECT  126.615 86.147 126.705 86.417 ;
     RECT  132.015 86.147 132.105 86.417 ;
     RECT  137.415 86.147 137.505 86.417 ;
     RECT  142.815 86.147 142.905 86.417 ;
     RECT  148.215 86.147 148.305 86.417 ;
     RECT  153.615 86.147 153.705 86.417 ;
     RECT  159.015 86.147 159.105 86.417 ;
     RECT  164.415 86.147 164.505 86.417 ;
     RECT  169.815 86.147 169.905 86.417 ;
     RECT  175.215 86.147 175.305 86.417 ;
     RECT  180.615 86.147 180.705 86.417 ;
     RECT  186.015 86.147 186.105 86.417 ;
     RECT  191.415 86.147 191.505 86.417 ;
     RECT  196.815 86.147 196.905 86.417 ;
     RECT  202.215 86.147 202.305 86.417 ;
     RECT  207.615 86.147 207.705 86.417 ;
     RECT  213.015 86.147 213.105 86.417 ;
    LAYER M4 ;
     RECT  0.06 1.872 0.137 65.544 ;
     RECT  0.137 1.872 0.602 65.448 ;
     RECT  0.602 1.872 2.408 30.168 ;
     RECT  0.602 31.152 2.408 65.448 ;
     RECT  2.408 1.872 2.512 86.412 ;
     RECT  2.512 1.872 2.704 86.142 ;
     RECT  2.704 34.416 2.765 49.224 ;
     RECT  2.704 54.048 2.765 61.704 ;
     RECT  2.765 34.416 2.873 48.984 ;
     RECT  2.765 56.064 2.873 61.704 ;
     RECT  2.704 63.024 2.873 64.68 ;
     RECT  2.873 63.072 2.945 64.68 ;
     RECT  2.765 54.048 3.089 54.984 ;
     RECT  2.945 63.072 3.233 64.392 ;
     RECT  3.089 54.048 3.521 54.408 ;
     RECT  2.873 56.064 3.521 60.648 ;
     RECT  3.233 63.072 3.521 63.528 ;
     RECT  2.873 35.472 3.557 48.984 ;
     RECT  2.704 50.256 3.557 53.016 ;
     RECT  2.704 31.44 3.805 33.384 ;
     RECT  2.873 34.416 3.805 34.44 ;
     RECT  3.557 35.472 3.809 45.816 ;
     RECT  3.521 56.064 3.845 58.92 ;
     RECT  2.873 61.68 3.845 61.704 ;
     RECT  3.557 50.256 3.881 52.824 ;
     RECT  3.845 56.064 3.881 57.432 ;
     RECT  3.521 63.072 3.881 63.096 ;
     RECT  3.557 46.8 3.953 48.984 ;
     RECT  3.881 57.312 3.989 57.432 ;
     RECT  3.805 31.44 4.093 34.44 ;
     RECT  3.845 58.416 4.169 58.92 ;
     RECT  2.704 1.872 4.201 30.312 ;
     RECT  4.093 31.344 4.201 34.44 ;
     RECT  3.881 50.256 4.205 50.568 ;
     RECT  3.881 56.064 4.277 56.088 ;
     RECT  3.989 57.408 4.277 57.432 ;
     RECT  3.521 54.048 4.313 54.072 ;
     RECT  4.169 58.416 4.313 58.44 ;
     RECT  3.521 60.288 4.313 60.648 ;
     RECT  3.809 35.472 4.345 44.472 ;
     RECT  3.953 48.912 4.345 48.984 ;
     RECT  4.205 50.256 4.345 50.28 ;
     RECT  4.201 1.872 4.349 34.44 ;
     RECT  4.345 48.912 4.349 50.28 ;
     RECT  4.349 2.256 4.381 34.44 ;
     RECT  4.345 35.424 4.381 44.472 ;
     RECT  3.953 46.8 4.421 47.928 ;
     RECT  3.809 45.504 4.957 45.816 ;
     RECT  4.421 46.8 4.957 47.736 ;
     RECT  4.381 2.256 5.065 44.472 ;
     RECT  4.957 45.504 5.065 47.736 ;
     RECT  4.777 54.192 5.077 54.888 ;
     RECT  4.349 48.912 5.105 49.464 ;
     RECT  5.077 54.192 5.123 55.416 ;
     RECT  5.137 61.632 5.173 61.656 ;
     RECT  5.123 55.392 5.177 55.416 ;
     RECT  3.881 52.464 5.317 52.824 ;
     RECT  5.123 54.192 5.317 54.216 ;
     RECT  5.173 61.632 5.317 62.232 ;
     RECT  5.317 52.464 5.357 54.216 ;
     RECT  3.985 64.992 5.413 65.016 ;
     RECT  5.065 57.456 5.461 57.48 ;
     RECT  5.461 57.456 5.497 58.392 ;
     RECT  5.413 64.368 5.5 65.016 ;
     RECT  5.065 59.856 5.713 59.88 ;
     RECT  5.065 2.256 5.753 47.736 ;
     RECT  5.713 59.856 5.753 59.976 ;
     RECT  5.753 28.896 5.785 47.736 ;
     RECT  5.785 28.896 5.897 48.216 ;
     RECT  5.753 2.256 6.133 27.48 ;
     RECT  6.181 67.584 6.229 67.608 ;
     RECT  5.317 61.632 6.277 63 ;
     RECT  6.133 1.728 6.289 27.48 ;
     RECT  5.357 52.464 6.289 53.592 ;
     RECT  6.289 1.008 6.361 27.48 ;
     RECT  6.277 61.392 6.373 63 ;
     RECT  5.5 64.896 6.373 65.016 ;
     RECT  5.497 57.456 6.397 58.488 ;
     RECT  6.361 0.96 6.433 27.48 ;
     RECT  6.373 61.392 6.437 63.816 ;
     RECT  6.373 64.896 6.46 65.688 ;
     RECT  6.437 63.792 6.473 63.816 ;
     RECT  5.965 55.92 6.613 56.04 ;
     RECT  6.397 57.024 6.613 58.488 ;
     RECT  6.437 61.392 6.613 62.04 ;
     RECT  5.105 49.44 6.757 49.464 ;
     RECT  6.289 51.936 6.757 53.592 ;
     RECT  6.613 54.96 6.757 58.488 ;
     RECT  5.753 59.952 6.757 59.976 ;
     RECT  6.46 64.896 6.757 64.92 ;
     RECT  6.757 48.72 6.797 49.464 ;
     RECT  6.541 70.704 6.901 70.728 ;
     RECT  5.897 28.896 6.937 47.736 ;
     RECT  5.821 50.496 6.973 50.52 ;
     RECT  6.937 28.656 7.009 47.736 ;
     RECT  6.797 48.72 7.009 48.792 ;
     RECT  6.757 54.96 7.009 59.976 ;
     RECT  6.613 61.008 7.009 62.04 ;
     RECT  6.433 0.432 7.117 27.48 ;
     RECT  7.009 28.656 7.117 48.792 ;
     RECT  6.229 67.152 7.237 67.608 ;
     RECT  6.757 51.936 7.369 53.928 ;
     RECT  7.009 54.96 7.369 62.04 ;
     RECT  6.757 64.176 7.477 64.92 ;
     RECT  7.369 51.936 7.525 62.04 ;
     RECT  6.901 70.704 7.573 71.256 ;
     RECT  7.237 66.48 7.621 67.608 ;
     RECT  7.573 70.272 7.621 71.256 ;
     RECT  7.621 69.552 7.669 71.256 ;
     RECT  7.477 64.176 7.693 65.496 ;
     RECT  6.973 50.064 7.801 50.52 ;
     RECT  7.525 51.792 7.801 62.04 ;
     RECT  7.117 0.432 7.808 48.792 ;
     RECT  7.801 50.064 7.808 62.04 ;
     RECT  7.693 63.264 7.808 65.496 ;
     RECT  7.621 66.48 7.808 67.8 ;
     RECT  7.669 69.552 7.808 71.4 ;
     RECT  6.901 74.688 7.808 74.712 ;
     RECT  7.808 0.432 7.912 86.412 ;
     RECT  7.912 0.432 8.104 86.142 ;
     RECT  8.104 51.12 8.243 65.496 ;
     RECT  8.104 0.432 8.413 23.88 ;
     RECT  8.243 51.12 8.417 63.288 ;
     RECT  8.104 50.064 8.597 50.136 ;
     RECT  8.417 53.328 8.597 63.288 ;
     RECT  8.413 0.384 8.701 23.88 ;
     RECT  8.104 26.112 8.813 47.688 ;
     RECT  8.813 45.456 9.097 47.688 ;
     RECT  8.104 48.768 9.097 49.032 ;
     RECT  8.597 50.112 9.097 50.136 ;
     RECT  8.417 51.12 9.097 51.768 ;
     RECT  8.104 24.864 9.133 24.888 ;
     RECT  9.133 24.864 9.205 24.984 ;
     RECT  8.813 26.112 9.205 44.472 ;
     RECT  9.097 45.456 9.209 49.032 ;
     RECT  8.597 53.328 9.245 62.52 ;
     RECT  9.245 53.328 9.425 53.928 ;
     RECT  8.701 0.336 9.637 23.88 ;
     RECT  9.205 24.864 9.637 44.472 ;
     RECT  8.243 64.416 9.637 65.496 ;
     RECT  9.425 53.328 9.673 53.688 ;
     RECT  9.637 63.84 9.673 65.496 ;
     RECT  8.104 66.48 9.673 72.168 ;
     RECT  9.637 0.336 9.785 44.472 ;
     RECT  9.209 46.656 9.853 49.032 ;
     RECT  9.097 50.112 9.853 51.768 ;
     RECT  9.673 63.84 9.925 72.168 ;
     RECT  9.785 31.392 9.961 44.472 ;
     RECT  9.209 45.456 9.961 45.576 ;
     RECT  9.925 63.84 9.997 72.408 ;
     RECT  9.853 46.656 10.249 51.768 ;
     RECT  9.673 52.992 10.249 53.688 ;
     RECT  9.961 31.392 10.307 45.576 ;
     RECT  9.245 55.152 10.357 62.52 ;
     RECT  10.307 31.728 10.393 45.576 ;
     RECT  10.249 46.656 10.393 53.688 ;
     RECT  10.393 31.728 10.505 53.688 ;
     RECT  10.505 31.728 10.649 48.888 ;
     RECT  10.505 49.968 10.753 53.688 ;
     RECT  10.357 55.104 10.789 62.52 ;
     RECT  9.997 63.84 10.789 72.984 ;
     RECT  8.104 74.16 10.789 74.712 ;
     RECT  9.785 0.336 10.837 30.216 ;
     RECT  10.753 49.968 10.837 53.88 ;
     RECT  10.789 55.008 10.837 62.52 ;
     RECT  10.649 32.64 10.865 48.888 ;
     RECT  10.789 63.84 10.865 74.712 ;
     RECT  10.865 32.64 11.009 45.576 ;
     RECT  10.837 49.968 11.009 62.52 ;
     RECT  11.009 50.016 11.113 62.52 ;
     RECT  10.837 0.336 11.293 30.312 ;
     RECT  11.009 32.64 11.593 44.232 ;
     RECT  10.865 46.752 11.603 48.888 ;
     RECT  11.293 0.336 11.689 31.032 ;
     RECT  11.593 32.64 11.689 42.168 ;
     RECT  10.865 64.224 11.701 74.712 ;
     RECT  11.689 0.336 11.873 42.168 ;
     RECT  11.701 64.224 12.161 75 ;
     RECT  11.593 43.152 12.193 44.232 ;
     RECT  11.009 45.264 12.193 45.576 ;
     RECT  11.873 18.768 12.589 42.168 ;
     RECT  12.193 43.152 12.589 45.576 ;
     RECT  11.603 46.752 12.613 48.744 ;
     RECT  12.161 64.416 12.613 75 ;
     RECT  12.589 18.768 12.805 45.576 ;
     RECT  12.613 46.704 12.805 48.744 ;
     RECT  11.873 0.336 12.949 17.64 ;
     RECT  12.805 18.768 12.949 48.744 ;
     RECT  12.949 0.336 13.208 48.744 ;
     RECT  11.113 50.016 13.208 63.24 ;
     RECT  12.613 64.416 13.208 75.24 ;
     RECT  13.208 0.336 13.312 86.412 ;
     RECT  13.312 0.336 13.504 86.142 ;
     RECT  13.504 0.336 13.997 48.744 ;
     RECT  13.504 50.304 14.285 52.392 ;
     RECT  13.997 40.56 14.357 48.744 ;
     RECT  14.677 53.28 14.821 53.304 ;
     RECT  13.504 55.008 14.821 62.52 ;
     RECT  14.821 53.28 14.825 62.52 ;
     RECT  13.997 0.336 14.867 39.576 ;
     RECT  14.867 37.008 15.061 39.576 ;
     RECT  14.357 40.56 15.061 47.112 ;
     RECT  14.825 53.808 15.077 62.52 ;
     RECT  14.357 48.24 15.301 48.744 ;
     RECT  14.285 50.304 15.301 51.768 ;
     RECT  14.867 0.336 15.329 35.976 ;
     RECT  15.329 0.336 15.577 26.904 ;
     RECT  15.061 37.008 15.637 47.112 ;
     RECT  15.077 53.904 15.685 62.52 ;
     RECT  13.504 63.792 15.685 75.24 ;
     RECT  15.329 27.936 15.829 35.976 ;
     RECT  15.637 37.008 15.829 47.208 ;
     RECT  15.829 27.936 16.441 47.208 ;
     RECT  15.301 48.24 16.441 51.768 ;
     RECT  15.577 0.288 16.513 26.904 ;
     RECT  16.441 27.936 16.513 51.768 ;
     RECT  16.513 0.288 16.547 51.768 ;
     RECT  16.547 0.288 16.595 46.776 ;
     RECT  16.595 37.152 16.691 46.776 ;
     RECT  16.595 0.288 16.697 35.976 ;
     RECT  16.697 0.288 16.805 32.904 ;
     RECT  16.691 40.416 16.931 46.776 ;
     RECT  16.547 48.24 16.979 51.768 ;
     RECT  16.805 0.288 17.027 32.856 ;
     RECT  17.027 0.288 17.068 29.64 ;
     RECT  16.931 40.848 17.237 46.776 ;
     RECT  17.237 40.848 17.597 46.632 ;
     RECT  16.691 37.152 17.756 39.288 ;
     RECT  17.756 37.152 17.773 39.48 ;
     RECT  16.697 34.416 17.845 35.976 ;
     RECT  17.845 34.32 17.917 35.976 ;
     RECT  17.027 30.816 17.953 32.856 ;
     RECT  17.917 33.888 17.953 35.976 ;
     RECT  17.053 52.752 18.133 52.776 ;
     RECT  15.685 53.904 18.133 75.24 ;
     RECT  17.068 0.288 18.181 27.96 ;
     RECT  17.953 30.816 18.205 35.976 ;
     RECT  17.773 37.008 18.205 39.48 ;
     RECT  16.979 49.584 18.205 51.768 ;
     RECT  18.133 52.752 18.205 75.24 ;
     RECT  18.181 0.288 18.241 28.008 ;
     RECT  17.068 29.088 18.241 29.64 ;
     RECT  18.241 0.288 18.469 29.64 ;
     RECT  18.205 30.816 18.469 39.48 ;
     RECT  18.469 0.288 18.608 39.48 ;
     RECT  17.597 40.848 18.608 43.56 ;
     RECT  17.597 44.88 18.608 46.632 ;
     RECT  16.979 48.24 18.608 48.456 ;
     RECT  18.205 49.584 18.608 75.24 ;
     RECT  18.608 0.288 18.712 86.412 ;
     RECT  18.712 0.288 18.904 86.142 ;
     RECT  18.904 27.456 19.073 39.336 ;
     RECT  19.073 27.456 19.109 35.928 ;
     RECT  19.109 27.456 19.909 32.856 ;
     RECT  19.073 36.912 19.909 39.336 ;
     RECT  18.904 48.144 19.973 75.24 ;
     RECT  19.909 36.912 20.041 39.624 ;
     RECT  18.904 41.184 20.041 45.384 ;
     RECT  18.904 0.288 20.053 26.376 ;
     RECT  19.909 27.36 20.053 32.856 ;
     RECT  20.041 36.912 20.221 45.384 ;
     RECT  18.904 46.416 20.221 46.632 ;
     RECT  20.053 0.288 20.257 32.856 ;
     RECT  19.109 33.888 20.257 35.928 ;
     RECT  20.221 36.912 20.365 46.632 ;
     RECT  20.257 0.288 20.437 35.928 ;
     RECT  20.365 36.912 20.437 46.92 ;
     RECT  19.973 54.096 21.337 75.24 ;
     RECT  20.437 0.288 21.373 46.92 ;
     RECT  19.973 48.144 21.373 52.872 ;
     RECT  21.373 0.288 21.445 52.872 ;
     RECT  21.337 54 21.445 75.24 ;
     RECT  21.445 0.288 22.273 75.24 ;
     RECT  22.273 0.144 24.008 75.24 ;
     RECT  24.008 0.144 24.112 86.412 ;
     RECT  24.112 0.144 24.304 86.142 ;
     RECT  24.304 0.144 26.341 75.24 ;
     RECT  26.341 0.096 29.408 75.24 ;
     RECT  29.408 0.096 29.512 86.412 ;
     RECT  29.512 0.096 29.704 86.142 ;
     RECT  29.704 0.096 34.808 75.24 ;
     RECT  34.808 0.096 34.912 86.412 ;
     RECT  34.912 0.096 35.104 86.142 ;
     RECT  35.104 0.096 40.208 75.24 ;
     RECT  40.208 0.096 40.312 86.412 ;
     RECT  40.312 0.096 40.504 86.142 ;
     RECT  40.504 0.096 45.608 75.24 ;
     RECT  45.608 0.096 45.712 86.412 ;
     RECT  45.712 0.096 45.904 86.142 ;
     RECT  45.904 0.096 51.008 75.24 ;
     RECT  51.008 0.096 51.112 86.412 ;
     RECT  51.112 0.096 51.304 86.142 ;
     RECT  51.304 0.096 51.443 75.24 ;
     RECT  51.443 0.096 56.408 75.192 ;
     RECT  56.408 0.096 56.512 86.412 ;
     RECT  56.512 0.096 56.704 86.142 ;
     RECT  56.704 0.096 61.808 75.192 ;
     RECT  61.808 0.096 61.912 86.412 ;
     RECT  61.912 0.096 62.104 86.142 ;
     RECT  62.104 0.096 67.208 75.192 ;
     RECT  67.208 0.096 67.312 86.412 ;
     RECT  67.312 0.096 67.504 86.142 ;
     RECT  67.504 0.096 67.619 75.192 ;
     RECT  67.619 74.592 68.099 75.192 ;
     RECT  67.619 0.096 72.608 73.608 ;
     RECT  68.099 74.688 72.608 75.192 ;
     RECT  72.608 0.096 72.712 86.412 ;
     RECT  72.712 0.096 72.904 86.142 ;
     RECT  72.904 0.096 73.523 73.608 ;
     RECT  72.904 74.688 74.387 75.192 ;
     RECT  74.387 74.832 76.019 75.192 ;
     RECT  73.523 0.096 78.008 73.368 ;
     RECT  76.019 74.832 78.008 75.144 ;
     RECT  78.008 0.096 78.112 86.412 ;
     RECT  78.112 0.096 78.304 86.142 ;
     RECT  78.304 0.096 83.408 73.368 ;
     RECT  78.304 74.832 83.408 75.144 ;
     RECT  83.408 0.096 83.512 86.412 ;
     RECT  83.512 0.096 83.704 86.142 ;
     RECT  83.704 74.832 84.083 75.144 ;
     RECT  84.083 74.832 86.641 74.856 ;
     RECT  86.641 74.688 86.681 74.856 ;
     RECT  83.704 0.096 88.808 73.368 ;
     RECT  86.681 74.688 88.808 74.712 ;
     RECT  88.808 0.096 88.912 86.412 ;
     RECT  88.912 0.096 89.104 86.142 ;
     RECT  89.104 74.688 89.795 74.712 ;
     RECT  89.104 0.096 94.208 73.368 ;
     RECT  94.208 0.096 94.312 86.412 ;
     RECT  94.312 0.096 94.504 86.142 ;
     RECT  94.504 0.096 94.931 73.368 ;
     RECT  94.931 0.096 95.459 73.272 ;
     RECT  95.459 0.096 97.187 73.128 ;
     RECT  97.187 0.096 98.093 65.4 ;
     RECT  97.187 66.576 99.608 73.128 ;
     RECT  99.608 66.576 99.712 86.412 ;
     RECT  98.093 1.056 99.904 65.4 ;
     RECT  99.712 66.576 99.904 86.142 ;
     RECT  99.904 1.056 100.217 1.608 ;
     RECT  99.904 2.592 100.931 65.4 ;
     RECT  99.904 66.576 101.507 73.128 ;
     RECT  100.931 2.592 102.121 2.856 ;
     RECT  100.931 3.84 102.121 65.4 ;
     RECT  102.121 2.592 102.227 65.4 ;
     RECT  101.507 66.72 102.589 73.128 ;
     RECT  102.227 2.592 103.633 2.856 ;
     RECT  102.227 3.84 103.633 65.4 ;
     RECT  103.633 2.592 105.008 65.4 ;
     RECT  102.589 66.672 105.008 73.128 ;
     RECT  105.008 2.148 105.112 65.4 ;
     RECT  105.008 66.672 105.112 86.412 ;
     RECT  105.112 2.418 105.304 65.4 ;
     RECT  105.112 66.672 105.304 86.142 ;
     RECT  105.304 5.664 105.827 65.4 ;
     RECT  100.217 1.056 105.905 1.128 ;
     RECT  105.827 5.664 106.121 9.624 ;
     RECT  105.827 10.656 106.193 65.4 ;
     RECT  105.304 2.88 106.657 4.536 ;
     RECT  106.193 10.656 106.769 12.36 ;
     RECT  106.193 13.344 106.883 65.4 ;
     RECT  106.121 5.712 107.053 9.624 ;
     RECT  106.769 10.656 107.053 12.024 ;
     RECT  105.905 1.104 107.417 1.128 ;
     RECT  106.883 13.344 107.449 65.352 ;
     RECT  106.657 2.736 107.516 4.536 ;
     RECT  107.516 2.736 107.521 4.728 ;
     RECT  107.053 5.712 107.521 12.024 ;
     RECT  107.521 2.736 108.025 12.024 ;
     RECT  107.449 13.104 108.025 65.352 ;
     RECT  108.025 2.736 108.029 65.352 ;
     RECT  108.029 2.832 110.408 65.352 ;
     RECT  105.304 66.672 110.408 73.128 ;
     RECT  110.408 2.148 110.512 65.352 ;
     RECT  110.408 66.672 110.512 86.412 ;
     RECT  110.512 66.672 110.585 86.142 ;
     RECT  110.512 2.418 110.704 65.352 ;
     RECT  110.585 66.864 110.704 86.142 ;
     RECT  110.704 2.88 110.765 12.504 ;
     RECT  110.765 5.568 110.837 12.504 ;
     RECT  110.837 5.568 110.873 9.288 ;
     RECT  110.837 10.272 110.873 12.312 ;
     RECT  110.873 5.568 110.909 8.856 ;
     RECT  110.704 13.584 110.909 65.352 ;
     RECT  110.765 2.88 110.945 4.536 ;
     RECT  110.945 2.88 110.981 4.44 ;
     RECT  110.981 2.88 111.053 3.096 ;
     RECT  110.909 5.856 111.053 8.856 ;
     RECT  111.053 2.88 111.125 2.904 ;
     RECT  110.981 4.224 111.125 4.44 ;
     RECT  111.125 4.224 111.269 4.248 ;
     RECT  111.053 6.048 111.341 8.856 ;
     RECT  110.909 13.632 111.341 65.352 ;
     RECT  110.873 10.272 111.593 10.68 ;
     RECT  110.873 11.664 111.593 12.312 ;
     RECT  111.341 6.048 111.665 8.232 ;
     RECT  110.704 66.864 111.683 73.128 ;
     RECT  111.665 6.816 111.701 8.232 ;
     RECT  111.683 66.864 111.733 69.48 ;
     RECT  111.733 66.72 111.827 69.48 ;
     RECT  111.593 12.288 111.953 12.312 ;
     RECT  111.593 10.272 112.097 10.392 ;
     RECT  112.097 10.272 112.169 10.296 ;
     RECT  111.341 13.632 112.316 14.232 ;
     RECT  111.701 6.816 112.403 6.84 ;
     RECT  112.316 13.056 112.403 14.232 ;
     RECT  111.341 15.264 112.529 65.352 ;
     RECT  112.403 13.92 112.673 14.232 ;
     RECT  112.529 15.264 112.817 16.584 ;
     RECT  111.827 66.864 114.577 69.48 ;
     RECT  111.683 70.512 114.577 73.128 ;
     RECT  114.577 66.864 114.617 73.128 ;
     RECT  112.673 14.208 115.808 14.232 ;
     RECT  112.817 15.264 115.808 16.536 ;
     RECT  112.529 17.616 115.808 65.352 ;
     RECT  114.617 66.864 115.808 70.392 ;
     RECT  114.617 71.376 115.808 73.128 ;
     RECT  115.808 2.148 115.912 65.352 ;
     RECT  115.808 66.864 115.912 86.412 ;
     RECT  115.912 2.418 116.104 65.352 ;
     RECT  115.912 66.864 116.104 86.142 ;
     RECT  116.104 71.376 116.579 73.128 ;
     RECT  116.104 69.456 116.675 70.392 ;
     RECT  116.104 15.264 116.723 65.352 ;
     RECT  116.579 71.616 118.613 73.128 ;
     RECT  116.104 14.208 121.208 14.232 ;
     RECT  116.723 15.264 121.208 64.8 ;
     RECT  116.104 66.864 121.208 67.848 ;
     RECT  116.675 69.456 121.208 69.48 ;
     RECT  118.613 71.616 121.208 73.08 ;
     RECT  121.208 2.148 121.312 64.8 ;
     RECT  121.208 66.864 121.312 86.412 ;
     RECT  121.312 2.418 121.504 64.8 ;
     RECT  121.312 66.864 121.504 86.142 ;
     RECT  121.504 71.616 121.715 73.08 ;
     RECT  121.715 72.672 122.339 73.08 ;
     RECT  121.504 14.208 126.608 14.232 ;
     RECT  121.504 15.264 126.608 64.8 ;
     RECT  121.504 66.864 126.608 67.848 ;
     RECT  121.504 69.456 126.608 69.48 ;
     RECT  121.715 71.616 126.608 71.64 ;
     RECT  122.339 72.672 126.608 72.696 ;
     RECT  126.608 2.148 126.712 64.8 ;
     RECT  126.608 66.864 126.712 86.412 ;
     RECT  126.712 2.418 126.904 64.8 ;
     RECT  126.712 66.864 126.904 86.142 ;
     RECT  126.904 66.864 127.379 67.848 ;
     RECT  126.904 15.264 128.405 64.8 ;
     RECT  126.904 72.672 130.525 72.696 ;
     RECT  130.525 72.528 130.565 72.696 ;
     RECT  126.904 14.208 132.008 14.232 ;
     RECT  128.405 15.264 132.008 18.792 ;
     RECT  128.405 19.92 132.008 64.8 ;
     RECT  127.379 67.008 132.008 67.848 ;
     RECT  126.904 69.456 132.008 69.48 ;
     RECT  130.565 72.528 132.008 72.552 ;
     RECT  132.008 2.148 132.112 64.8 ;
     RECT  132.008 66.948 132.112 86.412 ;
     RECT  132.112 2.418 132.304 64.8 ;
     RECT  132.112 67.008 132.304 86.142 ;
     RECT  132.304 72.528 132.515 72.552 ;
     RECT  132.304 69.456 132.611 69.48 ;
     RECT  132.304 19.92 135.997 64.8 ;
     RECT  135.997 19.872 136.259 64.8 ;
     RECT  132.304 67.008 136.259 67.848 ;
     RECT  132.304 14.208 137.408 14.232 ;
     RECT  132.304 15.264 137.408 18.792 ;
     RECT  136.259 19.92 137.408 64.8 ;
     RECT  136.259 67.008 137.408 67.032 ;
     RECT  137.408 2.148 137.512 64.8 ;
     RECT  137.408 66.948 137.512 86.412 ;
     RECT  137.512 2.418 137.704 64.8 ;
     RECT  137.512 67.008 137.704 86.142 ;
     RECT  137.704 14.208 142.808 14.232 ;
     RECT  137.704 15.264 142.808 18.792 ;
     RECT  137.704 19.92 142.808 64.8 ;
     RECT  137.704 67.008 142.808 67.032 ;
     RECT  142.808 2.148 142.912 64.8 ;
     RECT  142.808 66.948 142.912 86.412 ;
     RECT  142.912 2.418 143.104 64.8 ;
     RECT  142.912 67.008 143.104 86.142 ;
     RECT  143.104 14.208 148.208 14.232 ;
     RECT  143.104 15.264 148.208 18.792 ;
     RECT  143.104 19.92 148.208 64.8 ;
     RECT  143.104 67.008 148.208 67.032 ;
     RECT  148.208 2.148 148.312 64.8 ;
     RECT  148.208 66.948 148.312 86.412 ;
     RECT  148.312 2.418 148.504 64.8 ;
     RECT  148.312 67.008 148.504 86.142 ;
     RECT  148.504 14.208 153.608 14.232 ;
     RECT  148.504 15.264 153.608 18.792 ;
     RECT  148.504 19.92 153.608 64.8 ;
     RECT  148.504 67.008 153.608 67.032 ;
     RECT  153.608 2.148 153.712 64.8 ;
     RECT  153.608 66.948 153.712 86.412 ;
     RECT  153.712 2.418 153.904 64.8 ;
     RECT  153.712 67.008 153.904 86.142 ;
     RECT  153.904 14.208 159.008 14.232 ;
     RECT  153.904 15.264 159.008 18.792 ;
     RECT  153.904 19.92 159.008 64.8 ;
     RECT  153.904 67.008 159.008 67.032 ;
     RECT  159.008 2.148 159.112 64.8 ;
     RECT  159.008 66.948 159.112 86.412 ;
     RECT  159.112 2.418 159.304 64.8 ;
     RECT  159.112 67.008 159.304 86.142 ;
     RECT  159.304 14.208 164.408 14.232 ;
     RECT  159.304 15.264 164.408 18.792 ;
     RECT  159.304 19.92 164.408 64.8 ;
     RECT  159.304 67.008 164.408 67.032 ;
     RECT  164.408 2.148 164.512 64.8 ;
     RECT  164.408 66.948 164.512 86.412 ;
     RECT  164.512 2.418 164.704 64.8 ;
     RECT  164.512 67.008 164.704 86.142 ;
     RECT  164.704 14.208 169.808 14.232 ;
     RECT  164.704 15.264 169.808 64.8 ;
     RECT  164.704 67.008 169.808 67.032 ;
     RECT  169.808 2.148 169.912 64.8 ;
     RECT  169.808 66.948 169.912 86.412 ;
     RECT  169.912 2.418 170.104 64.8 ;
     RECT  169.912 67.008 170.104 86.142 ;
     RECT  170.104 15.264 172.757 64.8 ;
     RECT  170.104 14.208 175.208 14.232 ;
     RECT  172.757 15.312 175.208 64.8 ;
     RECT  170.104 67.008 175.208 67.032 ;
     RECT  175.208 2.148 175.312 64.8 ;
     RECT  175.208 66.948 175.312 86.412 ;
     RECT  175.312 2.418 175.504 64.8 ;
     RECT  175.312 67.008 175.504 86.142 ;
     RECT  175.504 14.208 180.608 14.232 ;
     RECT  175.504 15.312 180.608 64.8 ;
     RECT  175.504 67.008 180.608 67.032 ;
     RECT  180.608 2.148 180.712 64.8 ;
     RECT  180.608 66.948 180.712 86.412 ;
     RECT  180.712 2.418 180.904 64.8 ;
     RECT  180.712 67.008 180.904 86.142 ;
     RECT  180.904 15.312 183.161 64.8 ;
     RECT  180.904 14.208 186.008 14.232 ;
     RECT  183.161 16.272 186.008 64.8 ;
     RECT  180.904 67.008 186.008 67.032 ;
     RECT  186.008 2.148 186.112 64.8 ;
     RECT  186.008 66.948 186.112 86.412 ;
     RECT  186.112 2.418 186.304 64.8 ;
     RECT  186.112 67.008 186.304 86.142 ;
     RECT  190.897 6.048 191.408 6.072 ;
     RECT  186.304 14.208 191.408 14.232 ;
     RECT  186.304 16.272 191.408 64.8 ;
     RECT  186.304 67.008 191.408 67.032 ;
     RECT  191.408 2.148 191.512 64.8 ;
     RECT  191.408 66.948 191.512 86.412 ;
     RECT  191.512 2.418 191.704 64.8 ;
     RECT  191.512 67.008 191.704 86.142 ;
     RECT  191.704 16.512 193.709 64.8 ;
     RECT  191.704 6.048 194.317 6.072 ;
     RECT  194.317 6.048 194.465 6.168 ;
     RECT  191.704 14.208 194.789 14.232 ;
     RECT  193.709 16.8 195.257 64.8 ;
     RECT  195.257 18.768 196.009 64.8 ;
     RECT  196.009 18.768 196.056 65.544 ;
     RECT  194.465 6.048 196.808 6.072 ;
     RECT  195.257 16.8 196.808 17.64 ;
     RECT  196.056 18.768 196.808 23.4 ;
     RECT  191.704 67.008 196.808 67.032 ;
     RECT  196.808 2.148 196.912 23.4 ;
     RECT  196.808 66.948 196.912 86.412 ;
     RECT  196.912 2.418 197.104 23.4 ;
     RECT  196.912 67.218 197.104 86.142 ;
     RECT  196.056 24.528 197.219 64.488 ;
     RECT  197.219 26.736 197.453 64.488 ;
     RECT  197.104 20.832 197.507 23.4 ;
     RECT  197.104 6.048 197.555 6.072 ;
     RECT  197.104 16.8 197.603 17.64 ;
     RECT  197.453 29.808 197.651 64.488 ;
     RECT  196.056 65.52 197.843 65.544 ;
     RECT  197.453 26.736 197.849 28.584 ;
     RECT  197.104 18.768 197.891 19.848 ;
     RECT  197.891 18.768 197.939 18.792 ;
     RECT  197.651 30.288 197.957 64.488 ;
     RECT  197.957 30.576 198.029 64.488 ;
     RECT  198.029 31.056 198.173 64.488 ;
     RECT  198.173 31.344 198.419 64.488 ;
     RECT  198.419 31.344 198.425 64.392 ;
     RECT  197.507 20.832 198.461 23.064 ;
     RECT  198.425 31.344 198.467 63.24 ;
     RECT  198.425 64.368 198.467 64.392 ;
     RECT  198.461 20.832 198.515 22.008 ;
     RECT  197.891 19.824 198.563 19.848 ;
     RECT  198.467 31.44 198.563 63.24 ;
     RECT  198.563 33.072 198.605 63.24 ;
     RECT  198.605 41.424 198.641 52.104 ;
     RECT  198.605 53.232 198.641 58.632 ;
     RECT  198.605 59.664 198.641 61.896 ;
     RECT  198.565 65.568 198.649 65.592 ;
     RECT  197.219 24.528 198.677 25.704 ;
     RECT  198.605 34.896 198.677 40.392 ;
     RECT  198.641 41.424 198.677 51.72 ;
     RECT  198.605 33.072 198.713 33.864 ;
     RECT  198.677 47.568 198.713 51.72 ;
     RECT  198.641 53.424 198.713 58.632 ;
     RECT  198.677 24.816 198.749 25.704 ;
     RECT  198.677 36.816 198.749 40.392 ;
     RECT  198.713 55.92 198.749 58.632 ;
     RECT  198.641 60.144 198.749 61.896 ;
     RECT  198.605 62.928 198.749 63.048 ;
     RECT  198.749 39.504 198.785 40.392 ;
     RECT  198.749 57.264 198.785 58.44 ;
     RECT  197.603 17.616 198.821 17.64 ;
     RECT  198.749 36.816 198.821 36.936 ;
     RECT  198.785 40.176 198.821 40.392 ;
     RECT  198.677 41.424 198.821 46.248 ;
     RECT  198.713 47.568 198.821 47.64 ;
     RECT  198.713 53.424 198.821 54.792 ;
     RECT  198.785 57.84 198.821 58.44 ;
     RECT  198.749 60.144 198.821 61.608 ;
     RECT  198.713 33.552 198.857 33.864 ;
     RECT  198.821 40.176 198.857 40.2 ;
     RECT  198.821 41.52 198.857 42.312 ;
     RECT  198.677 34.896 198.893 35.688 ;
     RECT  198.857 41.52 198.893 41.736 ;
     RECT  198.821 47.568 198.893 47.592 ;
     RECT  198.713 48.72 198.893 49.704 ;
     RECT  198.713 50.784 198.893 51.528 ;
     RECT  198.749 56.112 198.893 56.232 ;
     RECT  198.821 58.416 198.893 58.44 ;
     RECT  198.563 31.44 198.929 32.04 ;
     RECT  198.821 36.816 198.929 36.84 ;
     RECT  198.893 41.52 198.929 41.544 ;
     RECT  198.821 43.536 198.929 44.904 ;
     RECT  198.893 49.296 198.929 49.704 ;
     RECT  198.893 50.832 198.929 51.528 ;
     RECT  198.821 53.424 198.929 54.024 ;
     RECT  198.749 62.928 198.929 62.952 ;
     RECT  198.893 34.896 198.965 34.92 ;
     RECT  198.929 50.832 198.965 50.856 ;
     RECT  197.849 27.12 199.001 28.584 ;
     RECT  198.749 38.352 199.073 38.376 ;
     RECT  198.515 20.832 199.109 21.24 ;
     RECT  198.929 31.44 199.181 31.752 ;
     RECT  198.749 24.816 199.541 24.84 ;
     RECT  199.181 31.728 199.613 31.752 ;
     RECT  199.109 20.832 199.649 20.856 ;
     RECT  199.001 27.216 199.649 28.584 ;
     RECT  199.649 27.216 199.685 27.528 ;
     RECT  199.649 28.56 199.721 28.584 ;
     RECT  198.857 33.84 199.757 33.864 ;
     RECT  199.685 27.504 199.793 27.528 ;
     RECT  198.461 23.04 202.208 23.064 ;
     RECT  202.208 2.148 202.312 86.412 ;
     RECT  202.312 2.418 202.504 86.142 ;
     RECT  202.504 23.04 207.608 23.064 ;
     RECT  207.608 2.148 207.712 86.412 ;
     RECT  207.712 2.418 207.904 86.142 ;
     RECT  207.904 23.04 207.965 23.064 ;
     RECT  213.008 2.148 213.112 86.412 ;
     RECT  213.112 2.418 213.304 86.142 ;
    LAYER M5 ;
     RECT  40.464 0.517 40.488 1.573 ;
     RECT  37.008 1.429 37.032 1.717 ;
     RECT  33.024 0.517 33.048 1.765 ;
     RECT  49.008 1.573 49.032 1.859 ;
     RECT  35.376 1.717 35.4 1.861 ;
     RECT  36.384 1.717 37.032 1.909 ;
     RECT  40.032 1.573 40.488 1.909 ;
     RECT  34.704 1.861 35.4 2.003 ;
     RECT  21.312 0.757 21.336 2.005 ;
     RECT  40.032 1.909 40.776 2.101 ;
     RECT  52.368 1.477 52.392 2.101 ;
     RECT  67.728 1.957 67.752 2.101 ;
     RECT  7.2 0.469 7.224 2.137 ;
     RECT  18.48 0.805 18.504 2.137 ;
     RECT  24.384 1.285 24.408 2.137 ;
     RECT  46.176 0.757 46.2 2.137 ;
     RECT  57.12 1.813 57.144 2.137 ;
     RECT  67.728 2.101 67.8 2.137 ;
     RECT  71.808 1.669 71.832 2.137 ;
     RECT  33.024 1.765 33.096 2.149 ;
     RECT  43.872 2.101 43.896 2.149 ;
     RECT  45.6 2.137 46.2 2.149 ;
     RECT  2.4 2.137 2.52 2.151 ;
     RECT  7.2 2.137 7.92 2.151 ;
     RECT  13.2 2.137 13.32 2.151 ;
     RECT  18.48 2.137 18.72 2.151 ;
     RECT  29.4 2.137 29.52 2.151 ;
     RECT  51 2.137 51.12 2.151 ;
     RECT  61.8 2.137 61.92 2.151 ;
     RECT  71.808 2.137 72.72 2.151 ;
     RECT  78 2.137 78.12 2.151 ;
     RECT  83.4 2.137 83.52 2.151 ;
     RECT  88.8 2.137 88.92 2.151 ;
     RECT  94.2 2.137 94.32 2.151 ;
     RECT  99.6 2.137 99.72 2.151 ;
     RECT  105 2.137 105.12 2.151 ;
     RECT  110.4 2.137 110.52 2.151 ;
     RECT  115.8 2.137 115.92 2.151 ;
     RECT  121.2 2.137 121.32 2.151 ;
     RECT  126.6 2.137 126.72 2.151 ;
     RECT  132 2.137 132.12 2.151 ;
     RECT  137.4 2.137 137.52 2.151 ;
     RECT  142.8 2.137 142.92 2.151 ;
     RECT  148.2 2.137 148.32 2.151 ;
     RECT  153.6 2.137 153.72 2.151 ;
     RECT  159 2.137 159.12 2.151 ;
     RECT  164.4 2.137 164.52 2.151 ;
     RECT  169.8 2.137 169.92 2.151 ;
     RECT  175.2 2.137 175.32 2.151 ;
     RECT  180.6 2.137 180.72 2.151 ;
     RECT  186 2.137 186.12 2.151 ;
     RECT  191.4 2.137 191.52 2.151 ;
     RECT  196.8 2.137 196.92 2.151 ;
     RECT  202.2 2.137 202.32 2.151 ;
     RECT  207.6 2.137 207.72 2.151 ;
     RECT  213 2.137 213.12 2.151 ;
     RECT  38.4 1.669 38.424 2.197 ;
     RECT  32.496 2.149 33.096 2.245 ;
     RECT  52.368 2.101 53.064 2.245 ;
     RECT  56.4 2.137 57.144 2.245 ;
     RECT  60.096 2.101 60.12 2.245 ;
     RECT  67.2 2.137 67.8 2.245 ;
     RECT  78 2.151 78.312 2.245 ;
     RECT  47.76 0.805 47.784 2.293 ;
     RECT  67.2 2.245 68.088 2.293 ;
     RECT  28.032 2.149 28.056 2.341 ;
     RECT  41.856 0.181 41.88 2.341 ;
     RECT  56.16 2.245 57.144 2.341 ;
     RECT  38.4 2.197 38.664 2.387 ;
     RECT  36.384 1.909 37.176 2.389 ;
     RECT  59.232 2.245 60.12 2.389 ;
     RECT  34.704 2.003 35.256 2.435 ;
     RECT  47.712 2.293 47.784 2.437 ;
     RECT  52.368 2.245 53.16 2.437 ;
     RECT  39.984 2.101 40.824 2.485 ;
     RECT  41.856 2.341 42.504 2.485 ;
     RECT  52.368 2.437 53.256 2.485 ;
     RECT  54.336 2.245 54.36 2.485 ;
     RECT  13.2 2.151 13.512 2.533 ;
     RECT  59.232 2.389 60.504 2.579 ;
     RECT  21.312 2.005 21.816 2.629 ;
     RECT  36.384 2.389 37.416 2.629 ;
     RECT  38.4 2.387 38.424 2.629 ;
     RECT  39.984 2.485 42.504 2.629 ;
     RECT  51 2.151 51.312 2.629 ;
     RECT  52.368 2.485 54.36 2.629 ;
     RECT  92.544 2.245 92.568 2.629 ;
     RECT  43.872 2.149 46.2 2.677 ;
     RECT  61.8 2.151 62.112 2.677 ;
     RECT  11.904 2.533 11.928 2.723 ;
     RECT  16.944 2.581 16.968 2.723 ;
     RECT  47.616 2.437 47.784 2.723 ;
     RECT  56.16 2.341 57.528 2.723 ;
     RECT  65.088 1.813 65.112 2.725 ;
     RECT  24 2.137 24.408 2.773 ;
     RECT  91.728 2.629 92.568 2.773 ;
     RECT  27.264 2.341 28.056 2.869 ;
     RECT  32.4 2.245 33.096 2.869 ;
     RECT  56.16 2.723 57.096 2.917 ;
     RECT  64.032 2.869 64.056 2.917 ;
     RECT  65.088 2.725 65.16 2.917 ;
     RECT  67.2 2.293 68.76 2.917 ;
     RECT  69.792 2.533 69.816 2.917 ;
     RECT  61.68 2.677 62.112 2.965 ;
     RECT  9.12 2.437 9.144 3.011 ;
     RECT  43.872 2.677 46.584 3.059 ;
     RECT  94.2 2.151 94.512 3.157 ;
     RECT  29.4 2.151 29.712 3.205 ;
     RECT  39.648 2.629 42.504 3.205 ;
     RECT  47.664 2.723 47.784 3.205 ;
     RECT  18.48 2.151 18.912 3.253 ;
     RECT  39.648 3.205 43.224 3.253 ;
     RECT  63.552 2.917 65.16 3.299 ;
     RECT  94.2 3.157 95.352 3.301 ;
     RECT  39.552 3.253 43.224 3.347 ;
     RECT  26.16 2.245 26.184 3.349 ;
     RECT  27.264 2.869 28.2 3.349 ;
     RECT  105 2.151 105.312 3.349 ;
     RECT  16.512 3.253 16.536 3.395 ;
     RECT  87.36 3.253 87.384 3.395 ;
     RECT  13.104 2.533 13.512 3.397 ;
     RECT  23.376 2.773 24.408 3.397 ;
     RECT  67.2 2.917 69.816 3.397 ;
     RECT  18.48 3.253 19.416 3.443 ;
     RECT  21.312 2.629 22.296 3.445 ;
     RECT  36.384 2.629 38.424 3.491 ;
     RECT  91.728 2.773 93 3.491 ;
     RECT  26.16 3.349 28.2 3.493 ;
     RECT  34.8 2.435 35.256 3.493 ;
     RECT  36.432 3.491 38.424 3.541 ;
     RECT  39.552 3.347 42.504 3.541 ;
     RECT  6.144 1.717 6.168 3.589 ;
     RECT  47.664 3.205 48.648 3.589 ;
     RECT  58.128 2.965 58.152 3.589 ;
     RECT  59.232 2.579 60.12 3.589 ;
     RECT  7.2 2.151 8.112 3.637 ;
     RECT  18.6 3.443 19.416 3.637 ;
     RECT  26.16 3.493 28.248 3.637 ;
     RECT  26.16 3.637 28.344 3.685 ;
     RECT  29.4 3.205 29.832 3.685 ;
     RECT  32.4 2.869 33.192 3.685 ;
     RECT  34.224 3.493 35.256 3.685 ;
     RECT  63.552 3.299 65.112 3.685 ;
     RECT  21.168 3.445 22.296 3.731 ;
     RECT  61.152 2.965 62.112 3.733 ;
     RECT  63.456 3.685 65.112 3.733 ;
     RECT  7.2 3.637 8.424 3.779 ;
     RECT  56.016 2.917 57.096 3.781 ;
     RECT  58.128 3.589 60.12 3.781 ;
     RECT  18.6 3.637 19.608 3.827 ;
     RECT  31.008 2.293 31.032 3.829 ;
     RECT  76.368 3.445 76.392 3.925 ;
     RECT  102.192 3.349 102.216 3.925 ;
     RECT  26.16 3.685 29.832 3.971 ;
     RECT  74.688 2.245 74.712 3.971 ;
     RECT  83.4 2.151 83.712 3.973 ;
     RECT  84.72 2.245 84.744 3.973 ;
     RECT  61.152 3.733 65.112 4.019 ;
     RECT  71.808 2.151 72.912 4.019 ;
     RECT  44.4 3.059 46.584 4.021 ;
     RECT  67.2 3.397 70.68 4.067 ;
     RECT  43.872 4.021 46.584 4.069 ;
     RECT  47.664 3.589 49.032 4.069 ;
     RECT  67.2 4.067 69.48 4.069 ;
     RECT  11.424 2.869 11.448 4.115 ;
     RECT  23.376 3.397 25.128 4.117 ;
     RECT  76.368 3.925 76.776 4.165 ;
     RECT  80.928 3.493 80.952 4.165 ;
     RECT  76.368 4.165 76.968 4.211 ;
     RECT  94.08 3.301 95.352 4.211 ;
     RECT  88.8 2.151 89.112 4.213 ;
     RECT  83.4 3.973 84.744 4.259 ;
     RECT  32.4 3.685 35.256 4.261 ;
     RECT  43.872 4.069 49.032 4.261 ;
     RECT  51 2.629 54.36 4.261 ;
     RECT  80.688 4.165 80.952 4.261 ;
     RECT  84.72 4.259 84.744 4.261 ;
     RECT  51 4.261 54.552 4.307 ;
     RECT  66.576 4.069 69.48 4.355 ;
     RECT  88.8 4.213 89.976 4.403 ;
     RECT  100.896 3.349 100.92 4.403 ;
     RECT  21.168 3.731 21.816 4.405 ;
     RECT  52.368 4.307 54.552 4.453 ;
     RECT  92.544 3.491 93 4.453 ;
     RECT  94.08 4.211 94.632 4.453 ;
     RECT  0.144 4.213 0.168 4.499 ;
     RECT  66.576 4.355 69.096 4.501 ;
     RECT  84.72 4.261 85.272 4.501 ;
     RECT  66.24 4.501 69.096 4.547 ;
     RECT  88.8 4.403 89.256 4.547 ;
     RECT  36.432 3.541 42.504 4.549 ;
     RECT  74.64 4.165 74.664 4.549 ;
     RECT  13.008 3.397 13.512 4.595 ;
     RECT  21.12 4.405 21.816 4.595 ;
     RECT  63.408 4.019 65.112 4.595 ;
     RECT  56.016 3.781 60.12 4.597 ;
     RECT  61.152 4.019 62.112 4.597 ;
     RECT  26.16 3.971 29.712 4.643 ;
     RECT  104.88 3.349 105.312 4.643 ;
     RECT  36.384 4.549 42.504 4.645 ;
     RECT  36.384 4.645 42.648 4.739 ;
     RECT  31.008 3.829 31.368 4.741 ;
     RECT  37.104 4.739 42.648 4.789 ;
     RECT  43.872 4.261 49.224 4.837 ;
     RECT  51 4.307 51.312 4.837 ;
     RECT  52.368 4.453 54.888 4.837 ;
     RECT  56.016 4.597 62.112 4.837 ;
     RECT  12.192 4.741 12.216 4.883 ;
     RECT  30.96 4.741 31.368 4.885 ;
     RECT  32.4 4.261 35.4 4.885 ;
     RECT  18.6 3.827 19.416 4.933 ;
     RECT  70.512 4.067 70.68 4.933 ;
     RECT  72.144 4.019 72.912 4.981 ;
     RECT  73.968 4.549 74.664 4.981 ;
     RECT  70.512 4.933 70.728 5.029 ;
     RECT  28.176 4.643 29.712 5.077 ;
     RECT  30.96 4.885 35.4 5.077 ;
     RECT  102.192 3.925 102.6 5.077 ;
     RECT  80.4 4.261 80.952 5.125 ;
     RECT  52.368 4.837 62.112 5.171 ;
     RECT  28.176 5.077 35.4 5.221 ;
     RECT  66.24 4.547 68.088 5.221 ;
     RECT  91.344 5.173 91.368 5.315 ;
     RECT  28.176 5.221 35.736 5.363 ;
     RECT  84.72 4.501 85.512 5.363 ;
     RECT  69.072 4.547 69.096 5.365 ;
     RECT  70.32 5.029 70.728 5.365 ;
     RECT  80.304 5.125 80.952 5.411 ;
     RECT  92.544 4.453 94.632 5.411 ;
     RECT  98.016 5.221 98.04 5.411 ;
     RECT  72.144 4.981 74.664 5.459 ;
     RECT  43.872 4.837 51.312 5.461 ;
     RECT  52.368 5.171 54.888 5.461 ;
     RECT  84.96 5.363 85.512 5.461 ;
     RECT  56.016 5.171 62.112 5.507 ;
     RECT  76.752 4.211 76.968 5.507 ;
     RECT  101.424 5.077 102.6 5.507 ;
     RECT  69.072 5.365 70.728 5.555 ;
     RECT  26.16 4.643 27.192 5.605 ;
     RECT  28.176 5.363 30.984 5.605 ;
     RECT  63.408 4.595 64.584 5.605 ;
     RECT  72.48 5.459 74.664 5.605 ;
     RECT  7.2 3.779 8.112 5.653 ;
     RECT  37.104 4.789 42.792 5.653 ;
     RECT  43.872 5.461 54.888 5.653 ;
     RECT  80.4 5.411 80.952 5.653 ;
     RECT  83.4 4.259 83.712 5.653 ;
     RECT  61.68 5.507 62.112 5.701 ;
     RECT  63.264 5.605 64.584 5.701 ;
     RECT  69.408 5.555 70.728 5.701 ;
     RECT  18.48 4.933 19.416 5.747 ;
     RECT  21.312 4.595 21.816 5.747 ;
     RECT  78 2.245 79.032 5.747 ;
     RECT  84.96 5.461 85.704 5.747 ;
     RECT  13.2 4.595 13.512 5.749 ;
     RECT  66.144 5.221 68.088 5.749 ;
     RECT  23.376 4.117 25.176 5.795 ;
     RECT  72.48 5.605 75.192 5.797 ;
     RECT  76.752 5.507 76.776 5.797 ;
     RECT  18.6 5.747 19.416 5.845 ;
     RECT  61.68 5.701 64.584 5.845 ;
     RECT  66.144 5.749 68.376 5.891 ;
     RECT  107.568 3.109 107.592 5.891 ;
     RECT  11.712 5.653 11.736 5.893 ;
     RECT  13.2 5.749 13.608 5.893 ;
     RECT  15.84 5.749 15.864 5.987 ;
     RECT  23.376 5.795 25.128 5.987 ;
     RECT  37.104 5.653 54.888 5.987 ;
     RECT  37.104 5.987 53.928 5.989 ;
     RECT  17.088 5.653 17.4 6.035 ;
     RECT  196.8 2.151 197.112 6.037 ;
     RECT  11.712 5.893 13.608 6.083 ;
     RECT  17.184 6.035 17.4 6.083 ;
     RECT  17.376 6.083 17.4 6.131 ;
     RECT  21.312 5.747 21.336 6.131 ;
     RECT  61.68 5.845 64.68 6.131 ;
     RECT  80.4 5.653 81.096 6.131 ;
     RECT  85.104 5.747 85.704 6.133 ;
     RECT  0.144 5.989 0.168 6.179 ;
     RECT  66.144 5.891 68.088 6.179 ;
     RECT  88.8 4.547 89.112 6.181 ;
     RECT  88.704 6.181 89.112 6.229 ;
     RECT  56.016 5.507 60.648 6.275 ;
     RECT  72.48 5.797 76.776 6.275 ;
     RECT  10.128 5.845 10.152 6.323 ;
     RECT  59.04 6.275 60.648 6.323 ;
     RECT  69.408 5.701 71.064 6.323 ;
     RECT  72.48 6.275 73.704 6.323 ;
     RECT  32.16 5.363 35.736 6.325 ;
     RECT  36.768 5.989 53.928 6.325 ;
     RECT  21.264 6.373 21.288 6.469 ;
     RECT  72.48 6.323 73.032 6.469 ;
     RECT  88.704 6.229 90.024 6.469 ;
     RECT  95.568 5.797 95.592 6.469 ;
     RECT  13.104 6.083 13.608 6.515 ;
     RECT  74.832 6.275 76.776 6.515 ;
     RECT  7.2 5.653 8.232 6.517 ;
     RECT  63.936 6.131 64.68 6.517 ;
     RECT  75.36 6.515 76.776 6.517 ;
     RECT  80.688 6.131 81.096 6.517 ;
     RECT  32.16 6.325 53.928 6.563 ;
     RECT  11.712 6.083 11.736 6.565 ;
     RECT  88.704 6.469 90.936 6.611 ;
     RECT  61.68 6.131 62.76 6.613 ;
     RECT  95.568 6.469 96.552 6.613 ;
     RECT  82.704 5.653 83.712 6.661 ;
     RECT  101.424 5.507 102.216 6.661 ;
     RECT  95.568 6.613 97.32 6.707 ;
     RECT  95.568 6.707 95.592 6.709 ;
     RECT  21.12 6.469 21.288 6.755 ;
     RECT  18.6 5.845 19.608 6.805 ;
     RECT  21.12 6.755 21.144 6.805 ;
     RECT  3.936 6.661 3.96 6.851 ;
     RECT  18.6 6.805 21.144 6.851 ;
     RECT  90.816 6.611 90.936 6.851 ;
     RECT  97.296 6.707 97.32 6.851 ;
     RECT  85.104 6.133 86.04 6.853 ;
     RECT  87.648 5.509 87.672 6.853 ;
     RECT  85.104 6.853 87.672 6.899 ;
     RECT  72.288 6.469 73.032 6.949 ;
     RECT  85.104 6.899 85.224 6.995 ;
     RECT  66.48 6.179 68.088 6.997 ;
     RECT  69.408 6.323 70.392 6.997 ;
     RECT  82.704 6.661 83.832 6.997 ;
     RECT  85.104 6.995 85.176 6.997 ;
     RECT  59.04 6.323 59.064 7.043 ;
     RECT  86.928 6.899 87.672 7.043 ;
     RECT  15.36 6.805 15.384 7.093 ;
     RECT  92.544 5.411 94.512 7.093 ;
     RECT  80.688 6.517 81.48 7.139 ;
     RECT  90.816 6.851 90.84 7.139 ;
     RECT  54.768 7.045 54.792 7.189 ;
     RECT  66.48 6.997 70.392 7.235 ;
     RECT  23.616 5.987 25.128 7.237 ;
     RECT  26.16 5.605 30.984 7.237 ;
     RECT  69.408 7.235 70.392 7.285 ;
     RECT  72.096 6.949 73.032 7.285 ;
     RECT  78 5.747 78.312 7.285 ;
     RECT  69.408 7.285 73.032 7.331 ;
     RECT  11.376 6.565 11.736 7.379 ;
     RECT  15.36 7.093 15.48 7.379 ;
     RECT  23.472 7.237 30.984 7.381 ;
     RECT  32.16 6.563 53.784 7.381 ;
     RECT  66.48 7.235 68.088 7.381 ;
     RECT  87.648 7.043 87.672 7.429 ;
     RECT  88.704 6.611 89.4 7.429 ;
     RECT  105 4.643 105.312 7.429 ;
     RECT  82.704 6.997 85.176 7.475 ;
     RECT  99.6 2.151 99.912 7.477 ;
     RECT  69.408 7.331 71.208 7.523 ;
     RECT  75.36 6.517 76.968 7.571 ;
     RECT  92.448 7.093 94.512 7.571 ;
     RECT  11.472 7.379 11.736 7.619 ;
     RECT  75.36 7.571 76.776 7.619 ;
     RECT  80.688 7.139 80.952 7.621 ;
     RECT  15.36 7.379 15.384 7.667 ;
     RECT  16.608 7.237 16.632 7.667 ;
     RECT  66.288 7.381 68.088 7.667 ;
     RECT  82.704 7.475 85.08 7.667 ;
     RECT  99.504 7.477 99.912 7.667 ;
     RECT  78 7.285 78.408 7.717 ;
     RECT  23.472 7.381 53.784 7.765 ;
     RECT  54.768 7.189 54.936 7.765 ;
     RECT  63.936 6.517 64.968 7.765 ;
     RECT  60.96 6.613 62.76 7.811 ;
     RECT  56.016 6.275 58.056 7.813 ;
     RECT  18.6 6.851 20.52 7.859 ;
     RECT  80.304 7.621 80.952 7.907 ;
     RECT  101.328 6.661 102.216 7.907 ;
     RECT  18.6 7.859 19.608 7.909 ;
     RECT  23.472 7.765 55.032 7.909 ;
     RECT  78 7.717 79.32 7.955 ;
     RECT  6.096 3.589 6.168 7.957 ;
     RECT  7.2 6.517 9 7.957 ;
     RECT  23.04 7.909 55.032 7.957 ;
     RECT  60.96 7.811 62.112 8.005 ;
     RECT  87.648 7.429 89.4 8.051 ;
     RECT  91.728 7.957 91.752 8.099 ;
     RECT  63.936 7.765 65.16 8.101 ;
     RECT  87.648 8.051 89.304 8.149 ;
     RECT  93.408 7.571 94.512 8.195 ;
     RECT  66.672 7.667 68.088 8.245 ;
     RECT  72.288 7.331 73.032 8.293 ;
     RECT  63.936 8.101 65.256 8.341 ;
     RECT  75.792 7.619 76.776 8.387 ;
     RECT  80.688 7.907 80.952 8.387 ;
     RECT  70.32 7.523 71.208 8.435 ;
     RECT  74.544 8.245 74.568 8.435 ;
     RECT  87.36 8.149 89.304 8.483 ;
     RECT  63.936 8.341 65.592 8.579 ;
     RECT  13.104 6.515 13.512 8.627 ;
     RECT  82.704 7.667 84.312 8.627 ;
     RECT  66.672 8.245 68.712 8.675 ;
     RECT  87.456 8.483 89.304 8.675 ;
     RECT  22.944 7.957 55.032 8.677 ;
     RECT  56.016 7.813 58.152 8.677 ;
     RECT  21.12 8.677 21.144 8.725 ;
     RECT  76.752 8.387 76.776 8.771 ;
     RECT  109.344 8.149 109.368 8.821 ;
     RECT  18.432 7.909 19.608 8.869 ;
     RECT  21.12 8.725 21.24 8.869 ;
     RECT  63.936 8.579 65.448 8.869 ;
     RECT  103.728 7.141 103.752 8.869 ;
     RECT  105 7.429 105.864 8.869 ;
     RECT  82.704 8.627 84.264 8.915 ;
     RECT  99.6 7.667 99.912 8.965 ;
     RECT  18.432 8.869 21.24 9.011 ;
     RECT  21.12 9.011 21.24 9.013 ;
     RECT  92.88 8.869 92.904 9.059 ;
     RECT  6.096 7.957 9 9.061 ;
     RECT  72.288 8.293 73.176 9.107 ;
     RECT  97.728 8.965 97.752 9.107 ;
     RECT  103.728 8.869 105.864 9.155 ;
     RECT  99.6 8.965 100.008 9.205 ;
     RECT  22.944 8.677 58.152 9.251 ;
     RECT  95.52 6.709 95.592 9.253 ;
     RECT  99.6 9.205 100.632 9.253 ;
     RECT  80.688 8.387 80.808 9.347 ;
     RECT  72.384 9.107 73.176 9.349 ;
     RECT  78 7.955 78.648 9.349 ;
     RECT  70.32 8.435 70.968 9.395 ;
     RECT  72.384 9.349 73.992 9.395 ;
     RECT  91.2 9.253 91.224 9.395 ;
     RECT  63.216 8.869 65.448 9.491 ;
     RECT  99.6 9.253 100.824 9.491 ;
     RECT  80.784 9.347 80.808 9.539 ;
     RECT  95.52 9.253 95.688 9.539 ;
     RECT  108.864 8.821 109.368 9.589 ;
     RECT  110.4 2.151 110.712 9.589 ;
     RECT  87.648 8.675 89.304 9.635 ;
     RECT  104.208 9.155 105.816 9.635 ;
     RECT  108.864 9.589 110.712 9.733 ;
     RECT  21.12 9.013 21.912 9.875 ;
     RECT  63.216 9.491 65.256 9.875 ;
     RECT  108.816 9.733 110.712 9.875 ;
     RECT  80.928 9.781 80.952 9.923 ;
     RECT  105 9.635 105.816 9.923 ;
     RECT  76.944 8.917 76.968 9.971 ;
     RECT  72.48 9.395 73.992 10.021 ;
     RECT  102.192 7.907 102.216 10.067 ;
     RECT  83.184 8.915 84.264 10.213 ;
     RECT  6.096 9.061 9.672 10.307 ;
     RECT  66.672 8.675 68.424 10.309 ;
     RECT  78 9.349 79.128 10.309 ;
     RECT  59.328 9.925 59.352 10.405 ;
     RECT  66.672 10.309 68.52 10.451 ;
     RECT  78 10.309 79.368 10.597 ;
     RECT  97.104 9.397 97.128 10.597 ;
     RECT  59.328 10.405 59.88 10.645 ;
     RECT  18.432 9.011 19.608 10.789 ;
     RECT  59.328 10.645 59.928 10.837 ;
     RECT  7.2 10.307 9.672 10.883 ;
     RECT  63.216 9.875 64.968 10.883 ;
     RECT  66.672 10.451 68.424 10.933 ;
     RECT  105 9.923 105.312 10.933 ;
     RECT  70.368 9.395 70.968 10.981 ;
     RECT  95.52 9.539 95.592 10.981 ;
     RECT  96.96 10.597 97.128 10.981 ;
     RECT  6.096 10.307 6.12 11.123 ;
     RECT  77.712 10.597 80.136 11.123 ;
     RECT  77.712 11.123 79.848 11.125 ;
     RECT  83.184 10.213 84.36 11.125 ;
     RECT  108.864 9.875 110.712 11.125 ;
     RECT  7.344 10.883 9.672 11.171 ;
     RECT  83.184 11.125 84.648 11.173 ;
     RECT  72.48 10.021 74.616 11.219 ;
     RECT  76.896 11.125 79.848 11.219 ;
     RECT  95.52 10.981 97.128 11.315 ;
     RECT  108.72 11.125 110.712 11.363 ;
     RECT  105 10.933 105.432 11.365 ;
     RECT  83.136 11.173 84.648 11.413 ;
     RECT  7.344 11.171 8.112 11.459 ;
     RECT  72.48 11.219 73.848 11.459 ;
     RECT  80.928 11.413 80.952 11.461 ;
     RECT  94.2 8.195 94.512 11.461 ;
     RECT  95.52 11.315 95.592 11.461 ;
     RECT  76.896 11.219 79.128 11.509 ;
     RECT  99.6 9.491 100.632 11.509 ;
     RECT  80.928 11.461 81.144 11.603 ;
     RECT  66.288 10.933 68.424 11.605 ;
     RECT  69.504 10.981 70.968 11.605 ;
     RECT  87.648 9.635 87.72 11.605 ;
     RECT  104.88 11.365 105.432 11.605 ;
     RECT  76.512 11.509 79.128 11.651 ;
     RECT  66.288 11.605 70.968 11.747 ;
     RECT  108.864 11.363 110.712 11.747 ;
     RECT  104.64 11.605 105.432 11.795 ;
     RECT  16.032 11.413 16.056 11.797 ;
     RECT  17.376 11.221 17.4 11.797 ;
     RECT  63.84 10.883 64.968 11.797 ;
     RECT  66.288 11.747 69.096 11.797 ;
     RECT  18.432 10.789 19.656 11.843 ;
     RECT  63.84 11.797 69.096 11.843 ;
     RECT  80.976 11.603 81.144 11.843 ;
     RECT  94.2 11.461 95.592 11.843 ;
     RECT  99.216 11.509 100.632 11.843 ;
     RECT  104.64 11.795 105.312 11.843 ;
     RECT  90.288 9.445 90.312 11.845 ;
     RECT  97.104 11.315 97.128 11.845 ;
     RECT  72.48 11.459 73.08 11.891 ;
     RECT  75.264 11.509 75.288 11.891 ;
     RECT  76.656 11.651 79.128 11.891 ;
     RECT  21.888 9.875 21.912 11.893 ;
     RECT  87.36 11.605 87.72 11.893 ;
     RECT  80.976 11.843 81 11.939 ;
     RECT  16.032 11.797 17.4 11.941 ;
     RECT  99.456 11.843 100.632 11.987 ;
     RECT  109.344 11.747 110.712 11.987 ;
     RECT  59.28 10.837 59.928 11.989 ;
     RECT  60.912 8.005 62.112 11.989 ;
     RECT  76.896 11.891 79.128 12.083 ;
     RECT  90.288 11.845 91.08 12.083 ;
     RECT  86.496 11.893 87.72 12.227 ;
     RECT  6.432 12.037 6.456 12.229 ;
     RECT  63.84 11.843 68.76 12.275 ;
     RECT  63.84 12.275 68.088 12.277 ;
     RECT  22.944 9.251 58.056 12.421 ;
     RECT  103.104 11.413 103.128 12.421 ;
     RECT  76.944 12.083 79.128 12.515 ;
     RECT  87.312 12.227 87.72 12.515 ;
     RECT  16.032 11.941 17.496 12.517 ;
     RECT  59.28 11.989 62.112 12.517 ;
     RECT  63.312 12.277 68.088 12.517 ;
     RECT  97.104 11.845 97.56 12.517 ;
     RECT  99.6 11.987 100.632 12.565 ;
     RECT  9.216 11.171 9.672 12.755 ;
     RECT  96.672 12.517 97.56 12.755 ;
     RECT  109.488 11.987 110.712 12.947 ;
     RECT  21.216 11.893 21.912 12.949 ;
     RECT  103.008 12.421 103.128 12.997 ;
     RECT  6.384 12.229 6.456 13.043 ;
     RECT  22.944 12.421 58.2 13.043 ;
     RECT  96.672 12.755 96.696 13.043 ;
     RECT  112.368 6.805 112.392 13.091 ;
     RECT  83.136 11.413 85.128 13.139 ;
     RECT  103.008 12.997 103.272 13.139 ;
     RECT  72.6 11.891 73.08 13.141 ;
     RECT  77.088 12.515 79.128 13.141 ;
     RECT  92.688 12.949 92.712 13.235 ;
     RECT  75.312 13.189 75.336 13.333 ;
     RECT  83.136 13.139 84.648 13.333 ;
     RECT  90.288 12.083 90.312 13.379 ;
     RECT  20.736 12.949 21.912 13.381 ;
     RECT  22.944 13.043 58.056 13.381 ;
     RECT  75.312 13.333 75.72 13.475 ;
     RECT  77.088 13.141 79.752 13.477 ;
     RECT  95.52 11.843 95.592 13.477 ;
     RECT  103.104 13.139 103.272 13.523 ;
     RECT  87.36 12.515 87.72 13.573 ;
     RECT  99.6 12.565 100.872 13.573 ;
     RECT  18.6 11.843 19.656 13.621 ;
     RECT  77.04 13.477 79.752 13.667 ;
     RECT  81.12 13.189 81.144 13.763 ;
     RECT  70.368 11.747 70.968 13.765 ;
     RECT  77.04 13.667 79.464 13.765 ;
     RECT  87.312 13.573 87.72 13.765 ;
     RECT  88.704 9.635 89.112 13.765 ;
     RECT  72.336 13.141 73.128 13.813 ;
     RECT  99.6 13.573 101.64 13.859 ;
     RECT  13.2 8.627 13.512 13.861 ;
     RECT  7.8 11.459 8.112 13.909 ;
     RECT  15.312 12.517 17.496 13.909 ;
     RECT  18.48 13.621 19.656 13.909 ;
     RECT  94.2 11.843 94.512 13.909 ;
     RECT  95.52 13.477 96.216 13.909 ;
     RECT  99.6 13.859 101.112 13.909 ;
     RECT  11.712 7.619 11.736 13.955 ;
     RECT  69.648 13.765 70.968 13.955 ;
     RECT  59.28 12.517 68.088 13.957 ;
     RECT  91.632 13.909 91.656 13.957 ;
     RECT  20.736 13.381 58.056 14.099 ;
     RECT  59.28 13.957 69 14.147 ;
     RECT  72.336 13.813 73.512 14.147 ;
     RECT  99.312 13.909 101.112 14.147 ;
     RECT  87.312 13.765 89.112 14.149 ;
     RECT  100.896 14.147 101.112 14.195 ;
     RECT  99.312 14.147 99.912 14.243 ;
     RECT  91.632 13.957 92.568 14.291 ;
     RECT  104.88 11.843 105.312 14.293 ;
     RECT  7.536 13.909 8.112 14.339 ;
     RECT  100.896 14.195 100.92 14.339 ;
     RECT  6.432 13.043 6.456 14.387 ;
     RECT  91.632 14.291 91.656 14.435 ;
     RECT  94.2 13.909 96.216 14.435 ;
     RECT  82.56 13.333 84.648 14.437 ;
     RECT  76.944 13.765 79.464 14.483 ;
     RECT  86.88 14.149 89.112 14.485 ;
     RECT  95.52 14.435 96.216 14.485 ;
     RECT  75.312 13.475 75.336 14.533 ;
     RECT  103.248 13.523 103.272 14.533 ;
     RECT  20.736 14.099 53.064 14.627 ;
     RECT  109.536 12.947 110.712 14.627 ;
     RECT  70.368 13.955 70.968 14.677 ;
     RECT  0.144 14.437 0.168 14.723 ;
     RECT  75.312 14.533 75.768 14.869 ;
     RECT  76.944 14.483 79.128 14.869 ;
     RECT  82.032 14.437 84.648 14.915 ;
     RECT  86.64 14.485 89.112 14.917 ;
     RECT  86.016 14.917 89.112 15.061 ;
     RECT  81.024 15.061 81.048 15.109 ;
     RECT  59.28 14.147 68.088 15.157 ;
     RECT  75.312 14.869 79.128 15.203 ;
     RECT  59.184 15.157 68.088 15.205 ;
     RECT  90.576 15.109 90.6 15.205 ;
     RECT  80.928 15.109 81.048 15.251 ;
     RECT  99.6 14.243 99.912 15.253 ;
     RECT  59.184 15.205 68.808 15.299 ;
     RECT  90.576 15.205 91.56 15.347 ;
     RECT  54.144 14.099 58.056 15.395 ;
     RECT  86.016 15.061 89.544 15.395 ;
     RECT  95.52 14.485 96.696 15.397 ;
     RECT  75.312 15.203 75.72 15.443 ;
     RECT  92.88 15.349 92.904 15.445 ;
     RECT  104.88 14.293 105.432 15.491 ;
     RECT  88.608 15.395 89.544 15.541 ;
     RECT  90.576 15.347 90.6 15.541 ;
     RECT  95.52 15.397 96.792 15.587 ;
     RECT  20.736 14.627 24.312 15.637 ;
     RECT  25.392 14.627 53.064 15.637 ;
     RECT  77.184 15.203 79.128 15.637 ;
     RECT  20.736 15.637 53.064 15.683 ;
     RECT  28.944 15.683 53.064 15.685 ;
     RECT  54.144 15.395 54.6 15.685 ;
     RECT  75.696 15.443 75.72 15.731 ;
     RECT  82.032 14.915 84.36 15.731 ;
     RECT  105 15.491 105.432 15.779 ;
     RECT  88.608 15.541 90.6 15.827 ;
     RECT  20.736 15.683 27.768 15.971 ;
     RECT  95.52 15.587 96.696 16.019 ;
     RECT  15.312 13.909 19.656 16.021 ;
     RECT  94.2 14.435 94.512 16.021 ;
     RECT  95.52 16.019 96.6 16.021 ;
     RECT  14.832 16.021 19.656 16.069 ;
     RECT  20.736 15.971 26.472 16.069 ;
     RECT  99.6 15.253 100.008 16.069 ;
     RECT  59.28 15.299 68.808 16.115 ;
     RECT  12.816 13.861 13.512 16.117 ;
     RECT  12.816 16.117 13.656 16.165 ;
     RECT  14.832 16.069 26.472 16.165 ;
     RECT  88.608 15.827 89.544 16.211 ;
     RECT  59.28 16.115 65.112 16.307 ;
     RECT  110.4 14.627 110.712 16.309 ;
     RECT  28.944 15.685 54.6 16.355 ;
     RECT  86.016 15.395 87.576 16.357 ;
     RECT  88.608 16.211 89.448 16.357 ;
     RECT  98.112 13.045 98.136 16.405 ;
     RECT  110.4 16.309 110.808 16.451 ;
     RECT  72.6 14.147 73.512 16.453 ;
     RECT  115.8 2.151 116.112 16.453 ;
     RECT  55.968 15.395 58.056 16.501 ;
     RECT  92.352 15.445 92.904 16.501 ;
     RECT  27.696 15.971 27.768 16.595 ;
     RECT  68.784 16.115 68.808 16.597 ;
     RECT  90.576 15.827 90.6 16.691 ;
     RECT  108.096 16.549 108.12 16.691 ;
     RECT  82.272 15.731 83.832 16.741 ;
     RECT  91.584 16.501 92.904 16.741 ;
     RECT  101.088 16.597 101.112 16.741 ;
     RECT  86.016 16.357 89.448 16.787 ;
     RECT  27.744 16.595 27.768 16.789 ;
     RECT  28.944 16.355 48.696 16.789 ;
     RECT  91.584 16.741 92.952 16.789 ;
     RECT  196.8 6.037 197.544 16.789 ;
     RECT  82.272 16.741 84.12 16.835 ;
     RECT  115.8 16.453 117.096 16.835 ;
     RECT  80.928 16.693 80.952 16.837 ;
     RECT  80.928 16.837 81.24 16.885 ;
     RECT  86.016 16.787 87.432 16.885 ;
     RECT  91.584 16.789 93.144 16.931 ;
     RECT  97.728 16.405 98.136 16.931 ;
     RECT  83.232 16.835 84.12 16.933 ;
     RECT  85.68 16.885 87.432 16.933 ;
     RECT  91.584 16.931 92.712 16.933 ;
     RECT  77.184 15.637 79.224 16.981 ;
     RECT  76.8 16.981 79.224 17.029 ;
     RECT  27.744 16.789 48.696 17.075 ;
     RECT  90.624 16.933 92.712 17.075 ;
     RECT  80.832 16.885 81.24 17.077 ;
     RECT  94.2 16.021 96.6 17.125 ;
     RECT  99.6 16.069 100.104 17.125 ;
     RECT  101.088 16.741 101.304 17.125 ;
     RECT  90.624 17.075 92.616 17.219 ;
     RECT  98.448 16.933 98.472 17.219 ;
     RECT  68.784 16.597 69.096 17.267 ;
     RECT  80.352 17.077 81.864 17.267 ;
     RECT  74.688 16.837 74.712 17.317 ;
     RECT  74.688 17.317 74.808 17.363 ;
     RECT  70.368 14.677 71.352 17.365 ;
     RECT  72.48 16.453 73.512 17.365 ;
     RECT  106.464 17.125 106.488 17.413 ;
     RECT  80.352 17.267 81 17.459 ;
     RECT  94.2 17.125 96.984 17.459 ;
     RECT  110.4 16.451 110.712 17.461 ;
     RECT  70.368 17.365 73.512 17.507 ;
     RECT  80.688 17.459 81 17.507 ;
     RECT  6.048 15.781 6.072 17.509 ;
     RECT  9.648 12.755 9.672 17.509 ;
     RECT  28.944 17.075 48.696 17.509 ;
     RECT  49.824 16.355 54.6 17.509 ;
     RECT  66.384 16.115 67.8 17.509 ;
     RECT  68.784 17.267 69 17.509 ;
     RECT  80.784 17.507 81 17.603 ;
     RECT  83.232 16.933 87.432 17.603 ;
     RECT  106.368 17.413 106.488 17.651 ;
     RECT  110.4 17.461 111.432 17.651 ;
     RECT  60.624 16.307 65.112 17.653 ;
     RECT  66.384 17.509 69 17.653 ;
     RECT  85.344 17.603 87.432 17.699 ;
     RECT  88.512 16.787 89.448 17.699 ;
     RECT  12.816 16.165 26.472 17.701 ;
     RECT  27.744 17.075 27.768 17.701 ;
     RECT  74.784 17.363 74.808 17.843 ;
     RECT  102.432 14.533 103.416 17.843 ;
     RECT  28.944 17.509 54.6 17.891 ;
     RECT  59.28 16.307 59.64 17.941 ;
     RECT  60.624 17.653 69 17.941 ;
     RECT  28.944 17.891 54.552 18.035 ;
     RECT  86.976 17.699 87.432 18.037 ;
     RECT  88.512 17.699 89.112 18.037 ;
     RECT  70.368 17.507 71.496 18.083 ;
     RECT  55.92 16.501 58.056 18.085 ;
     RECT  59.28 17.941 69 18.085 ;
     RECT  106.896 17.749 107.208 18.131 ;
     RECT  7.8 14.339 8.112 18.181 ;
     RECT  94.2 17.459 96.888 18.181 ;
     RECT  55.92 18.085 69 18.323 ;
     RECT  75.984 17.029 79.224 18.325 ;
     RECT  99.6 17.125 101.304 18.371 ;
     RECT  91.344 17.219 92.616 18.373 ;
     RECT  83.232 17.603 83.832 18.421 ;
     RECT  9.264 17.509 9.672 18.467 ;
     RECT  72.6 17.507 73.512 18.467 ;
     RECT  75.984 18.325 79.608 18.517 ;
     RECT  94.08 18.181 96.888 18.517 ;
     RECT  55.92 18.323 59.64 18.563 ;
     RECT  80.976 17.603 81 18.613 ;
     RECT  12.816 17.701 27.768 18.659 ;
     RECT  91.344 18.373 92.664 18.659 ;
     RECT  94.032 18.517 96.888 18.659 ;
     RECT  94.2 18.659 96.888 18.661 ;
     RECT  75.744 18.517 79.608 18.707 ;
     RECT  80.976 18.613 81.768 18.709 ;
     RECT  85.344 17.699 85.896 18.709 ;
     RECT  86.976 18.037 89.112 18.709 ;
     RECT  12.816 18.659 26.472 18.755 ;
     RECT  196.8 16.789 197.592 18.757 ;
     RECT  11.232 18.181 11.256 18.803 ;
     RECT  60.624 18.323 69 18.805 ;
     RECT  7.68 18.181 8.112 18.853 ;
     RECT  29.04 18.035 54.552 18.899 ;
     RECT  80.88 18.709 81.768 18.899 ;
     RECT  55.92 18.563 59.304 18.901 ;
     RECT  75.744 18.707 79.176 18.901 ;
     RECT  75.696 18.901 79.176 18.947 ;
     RECT  101.28 18.371 101.304 18.997 ;
     RECT  102.432 17.843 102.696 18.997 ;
     RECT  98.304 18.469 98.328 19.093 ;
     RECT  91.344 18.659 91.608 19.141 ;
     RECT  29.04 18.899 54.072 19.187 ;
     RECT  55.104 18.901 59.304 19.187 ;
     RECT  92.592 18.659 92.664 19.189 ;
     RECT  12.816 18.755 24.408 19.235 ;
     RECT  75.696 18.947 79.08 19.237 ;
     RECT  105 15.779 105.312 19.237 ;
     RECT  111.984 19.189 112.008 19.237 ;
     RECT  85.344 18.709 89.112 19.285 ;
     RECT  111.792 19.237 112.008 19.331 ;
     RECT  60.624 18.805 69.096 19.333 ;
     RECT  70.368 18.083 70.392 19.333 ;
     RECT  104.88 19.237 105.312 19.333 ;
     RECT  107.184 18.131 107.208 19.333 ;
     RECT  110.4 17.651 110.712 19.333 ;
     RECT  111.792 19.331 111.912 19.333 ;
     RECT  27.744 18.659 27.768 19.429 ;
     RECT  71.52 18.757 71.544 19.477 ;
     RECT  72.6 18.467 73.272 19.477 ;
     RECT  103.968 19.333 105.312 19.523 ;
     RECT  7.536 18.853 8.112 19.525 ;
     RECT  92.592 19.189 92.904 19.525 ;
     RECT  99.6 18.371 100.248 19.525 ;
     RECT  101.28 18.997 102.696 19.525 ;
     RECT  5.712 17.509 6.072 19.573 ;
     RECT  7.056 19.525 8.112 19.573 ;
     RECT  94.2 18.661 96.936 19.573 ;
     RECT  98.064 19.093 98.328 19.573 ;
     RECT  99.36 19.525 102.696 19.667 ;
     RECT  27.744 19.429 27.912 19.715 ;
     RECT  5.712 19.573 8.112 19.763 ;
     RECT  29.04 19.187 35.736 19.811 ;
     RECT  9.648 18.467 9.672 19.813 ;
     RECT  196.8 18.757 197.928 19.813 ;
     RECT  71.52 19.477 73.272 19.861 ;
     RECT  85.344 19.285 89.544 19.861 ;
     RECT  105 19.523 105.312 19.909 ;
     RECT  106.56 19.333 107.208 19.909 ;
     RECT  108.288 19.717 108.312 19.909 ;
     RECT  12.816 19.235 24.312 19.955 ;
     RECT  85.2 19.861 89.544 19.957 ;
     RECT  91.2 19.141 91.608 19.957 ;
     RECT  60.624 19.333 70.392 20.003 ;
     RECT  85.2 19.957 91.608 20.003 ;
     RECT  85.344 20.003 91.608 20.051 ;
     RECT  74.88 19.237 79.08 20.101 ;
     RECT  90.288 20.051 91.608 20.101 ;
     RECT  92.592 19.525 93.192 20.101 ;
     RECT  94.2 19.573 98.328 20.101 ;
     RECT  99.36 19.667 100.056 20.101 ;
     RECT  71.52 19.861 73.512 20.149 ;
     RECT  74.88 20.101 79.464 20.149 ;
     RECT  81.12 18.899 81.432 20.149 ;
     RECT  36.72 19.187 54.072 20.197 ;
     RECT  80.928 20.149 81.432 20.197 ;
     RECT  31.488 19.811 35.736 20.293 ;
     RECT  36.72 20.197 54.12 20.293 ;
     RECT  80.928 20.197 81.768 20.341 ;
     RECT  196.8 19.813 198.552 20.341 ;
     RECT  94.2 20.101 100.056 20.387 ;
     RECT  31.488 20.293 54.12 20.389 ;
     RECT  12.816 19.955 14.28 20.437 ;
     RECT  82.8 18.421 83.832 20.437 ;
     RECT  105 19.909 108.312 20.485 ;
     RECT  115.8 16.835 116.112 20.485 ;
     RECT  60.912 20.003 70.392 20.533 ;
     RECT  71.52 20.149 79.464 20.533 ;
     RECT  31.488 20.389 54.792 20.579 ;
     RECT  60.912 20.533 79.464 20.581 ;
     RECT  80.64 20.341 81.768 20.581 ;
     RECT  33.888 20.579 54.792 20.627 ;
     RECT  115.8 20.485 116.616 20.629 ;
     RECT  60.912 20.581 81.768 20.677 ;
     RECT  82.8 20.437 84.312 20.677 ;
     RECT  55.92 19.187 59.304 20.725 ;
     RECT  36.768 20.627 54.792 20.771 ;
     RECT  99.6 20.387 100.056 20.773 ;
     RECT  101.04 19.667 102.696 20.773 ;
     RECT  31.488 20.579 31.512 20.867 ;
     RECT  55.92 20.725 59.544 20.869 ;
     RECT  121.2 2.151 121.512 20.917 ;
     RECT  25.392 18.755 26.472 20.963 ;
     RECT  85.344 20.051 89.112 21.013 ;
     RECT  90.288 20.101 93.192 21.013 ;
     RECT  115.8 20.629 116.664 21.061 ;
     RECT  25.392 20.963 26.376 21.107 ;
     RECT  29.04 19.811 30.36 21.107 ;
     RECT  44.688 20.771 54.792 21.155 ;
     RECT  115.2 21.061 116.664 21.157 ;
     RECT  132 2.151 132.312 21.205 ;
     RECT  11.904 20.437 14.28 21.253 ;
     RECT  15.264 19.955 24.312 21.253 ;
     RECT  126.6 2.151 126.912 21.253 ;
     RECT  33.888 20.627 35.784 21.299 ;
     RECT  126.6 21.253 127.368 21.301 ;
     RECT  9.168 19.813 9.672 21.349 ;
     RECT  132 21.205 132.504 21.349 ;
     RECT  7.68 19.763 8.112 21.395 ;
     RECT  118.224 21.013 118.248 21.397 ;
     RECT  29.4 21.107 30.36 21.493 ;
     RECT  11.904 21.253 24.312 21.541 ;
     RECT  25.392 21.107 26.232 21.541 ;
     RECT  60.912 20.677 84.312 21.541 ;
     RECT  11.904 21.541 26.232 21.587 ;
     RECT  118.224 21.397 118.584 21.587 ;
     RECT  121.2 20.917 122.568 21.587 ;
     RECT  142.8 2.151 143.112 21.637 ;
     RECT  196.656 20.341 198.552 21.637 ;
     RECT  9.168 21.349 10.248 21.683 ;
     RECT  36.768 20.771 43.608 21.683 ;
     RECT  11.904 21.587 25.416 21.731 ;
     RECT  39.936 21.683 43.608 21.731 ;
     RECT  5.712 19.763 6.072 21.733 ;
     RECT  142.704 21.637 143.112 21.779 ;
     RECT  36.768 21.683 38.952 21.827 ;
     RECT  32.688 20.579 32.712 21.875 ;
     RECT  10.224 21.683 10.248 21.923 ;
     RECT  29.4 21.493 30.936 21.923 ;
     RECT  40.032 21.731 43.608 21.925 ;
     RECT  44.688 21.155 48.216 21.925 ;
     RECT  49.248 21.155 54.792 21.925 ;
     RECT  55.92 20.869 59.64 21.925 ;
     RECT  11.904 21.731 14.136 21.973 ;
     RECT  49.248 21.925 59.64 22.021 ;
     RECT  60.672 21.541 84.312 22.021 ;
     RECT  29.4 21.923 30.888 22.165 ;
     RECT  40.032 21.925 48.216 22.259 ;
     RECT  15.312 21.731 25.416 22.355 ;
     RECT  27.744 19.715 27.768 22.451 ;
     RECT  37.008 21.827 38.952 22.451 ;
     RECT  196.32 21.637 198.552 22.453 ;
     RECT  40.08 22.259 48.216 22.499 ;
     RECT  196.272 22.453 198.552 22.501 ;
     RECT  11.568 21.973 14.136 22.741 ;
     RECT  5.472 21.733 6.072 22.837 ;
     RECT  7.8 21.395 8.112 22.837 ;
     RECT  33.888 21.299 35.688 22.883 ;
     RECT  5.472 22.837 8.112 22.979 ;
     RECT  41.664 22.499 48.216 23.125 ;
     RECT  49.248 22.021 84.312 23.125 ;
     RECT  11.568 22.741 14.28 23.267 ;
     RECT  28.8 22.165 30.888 23.267 ;
     RECT  41.664 23.125 84.312 23.315 ;
     RECT  33.888 22.883 35.544 23.411 ;
     RECT  12 23.267 14.28 23.507 ;
     RECT  15.312 22.355 25.08 23.605 ;
     RECT  46.992 23.315 84.312 23.699 ;
     RECT  5.472 22.979 6.072 24.469 ;
     RECT  12 23.507 14.136 24.517 ;
     RECT  15.12 23.605 25.08 24.517 ;
     RECT  12 24.517 25.08 24.853 ;
     RECT  11.856 24.853 25.08 25.333 ;
     RECT  11.568 25.333 25.08 25.619 ;
     RECT  11.568 25.619 14.136 25.667 ;
     RECT  5.472 24.469 6.504 25.715 ;
     RECT  11.856 25.667 14.136 25.715 ;
     RECT  4.32 15.637 4.344 26.293 ;
     RECT  4.272 26.293 4.344 26.579 ;
     RECT  5.472 25.715 6.264 26.819 ;
     RECT  0.144 25.477 0.168 27.155 ;
     RECT  5.472 26.819 5.736 27.251 ;
     RECT  12.288 25.715 14.136 27.301 ;
     RECT  15.12 25.619 25.08 27.301 ;
     RECT  12.288 27.301 25.08 28.307 ;
     RECT  7.8 22.979 8.112 28.789 ;
     RECT  7.44 28.789 8.112 29.605 ;
     RECT  9.168 21.683 9.192 29.605 ;
     RECT  10.848 28.933 10.872 29.749 ;
     RECT  12.288 28.307 14.136 29.749 ;
     RECT  15.12 28.307 25.08 29.749 ;
     RECT  0.528 30.037 0.552 30.227 ;
     RECT  10.272 29.749 10.872 30.277 ;
     RECT  12.288 29.749 25.08 30.277 ;
     RECT  10.272 30.277 25.08 30.323 ;
     RECT  7.44 29.605 9.192 30.611 ;
     RECT  10.272 30.323 10.296 31.427 ;
     RECT  0.144 31.429 0.168 31.619 ;
     RECT  2.4 2.151 2.712 31.765 ;
     RECT  2.304 31.765 2.712 31.955 ;
     RECT  5.712 27.251 5.736 32.389 ;
     RECT  196.176 22.501 198.552 32.531 ;
     RECT  196.176 32.531 197.88 32.579 ;
     RECT  10.416 32.533 10.44 32.629 ;
     RECT  11.712 30.323 25.08 32.629 ;
     RECT  196.272 32.579 197.88 32.723 ;
     RECT  0.144 32.629 0.168 32.819 ;
     RECT  4.32 26.579 4.344 32.869 ;
     RECT  7.632 30.611 9.192 32.965 ;
     RECT  10.416 32.629 25.08 32.965 ;
     RECT  7.632 32.965 25.08 33.107 ;
     RECT  4.32 32.869 4.536 33.683 ;
     RECT  196.8 32.723 197.88 33.971 ;
     RECT  7.632 33.107 14.136 34.403 ;
     RECT  7.632 34.403 9.192 34.741 ;
     RECT  0.144 35.317 0.168 35.507 ;
     RECT  10.176 34.403 14.136 35.509 ;
     RECT  15.12 33.107 25.08 35.509 ;
     RECT  7.536 34.741 9.192 35.749 ;
     RECT  10.176 35.509 25.08 35.749 ;
     RECT  5.712 32.389 6.264 35.845 ;
     RECT  7.536 35.749 25.08 35.845 ;
     RECT  2.4 31.955 2.712 36.565 ;
     RECT  2.304 36.565 2.712 36.707 ;
     RECT  4.32 33.683 4.344 36.757 ;
     RECT  5.712 35.845 25.08 36.757 ;
     RECT  4.32 36.757 25.08 39.395 ;
     RECT  5.088 39.395 25.08 39.731 ;
     RECT  5.088 39.731 14.136 39.923 ;
     RECT  196.8 33.971 197.832 39.925 ;
     RECT  196.224 39.925 197.832 40.115 ;
     RECT  0.144 40.693 0.168 40.883 ;
     RECT  5.712 39.923 14.136 40.885 ;
     RECT  15.168 39.731 25.08 41.075 ;
     RECT  5.664 40.885 14.136 41.939 ;
     RECT  5.664 41.939 14.088 42.805 ;
     RECT  5.088 42.805 14.088 43.379 ;
     RECT  5.088 43.379 5.112 43.955 ;
     RECT  2.4 36.707 2.712 45.493 ;
     RECT  0.144 44.725 0.168 46.019 ;
     RECT  5.136 46.597 5.16 46.787 ;
     RECT  196.8 40.115 197.832 47.797 ;
     RECT  4.176 47.173 4.2 47.939 ;
     RECT  2.4 45.493 2.808 47.987 ;
     RECT  6.192 43.379 13.656 48.229 ;
     RECT  196.32 47.797 197.832 48.421 ;
     RECT  15.312 41.075 25.08 49.619 ;
     RECT  15.792 49.619 25.08 49.907 ;
     RECT  196.32 48.421 198.6 50.773 ;
     RECT  196.32 50.773 198.84 50.963 ;
     RECT  6.192 48.229 14.136 52.403 ;
     RECT  5.088 54.181 5.112 55.427 ;
     RECT  0.144 58.117 0.168 58.307 ;
     RECT  0.144 60.037 0.168 60.323 ;
     RECT  6.192 52.403 13.656 64.357 ;
     RECT  0.144 64.213 0.168 64.403 ;
     RECT  5.424 64.357 13.656 65.027 ;
     RECT  110.4 19.333 111.912 65.027 ;
     RECT  85.344 21.013 93.192 65.267 ;
     RECT  40.08 22.499 40.512 65.269 ;
     RECT  41.664 23.315 46.008 65.269 ;
     RECT  46.992 23.699 84.168 65.363 ;
     RECT  115.2 21.157 116.712 65.363 ;
     RECT  196.32 50.963 198.6 65.555 ;
     RECT  198.576 65.555 198.6 65.603 ;
     RECT  85.344 65.267 92.04 65.699 ;
     RECT  52.464 65.363 84.168 65.795 ;
     RECT  27.36 64.933 27.384 65.939 ;
     RECT  33.888 23.411 35.112 65.939 ;
     RECT  52.464 65.795 79.08 65.939 ;
     RECT  34.8 65.939 35.112 65.941 ;
     RECT  52.704 65.939 79.08 66.035 ;
     RECT  52.752 66.035 79.08 66.179 ;
     RECT  85.344 65.699 87.528 66.275 ;
     RECT  88.8 65.699 92.04 66.419 ;
     RECT  110.4 65.027 111.816 66.755 ;
     RECT  94.2 20.387 98.328 66.803 ;
     RECT  28.8 23.267 30.504 66.899 ;
     RECT  40.08 65.269 46.008 66.899 ;
     RECT  53.04 66.179 79.08 66.899 ;
     RECT  126.24 21.301 127.368 66.899 ;
     RECT  196.32 65.555 197.112 67.043 ;
     RECT  46.992 65.363 51.312 67.091 ;
     RECT  28.944 66.899 30.504 67.283 ;
     RECT  40.08 66.899 41.064 67.283 ;
     RECT  42.432 66.899 46.008 67.283 ;
     RECT  103.968 19.523 103.992 67.331 ;
     RECT  118.224 21.587 118.248 67.331 ;
     RECT  53.52 66.899 79.08 67.379 ;
     RECT  80.064 65.795 84.168 67.523 ;
     RECT  49.824 67.091 51.312 67.525 ;
     RECT  6.192 65.027 13.656 67.619 ;
     RECT  28.944 67.283 30.264 67.619 ;
     RECT  113.904 21.061 113.928 67.667 ;
     RECT  58.128 67.379 79.08 67.715 ;
     RECT  93.168 65.267 93.192 67.763 ;
     RECT  37.008 22.451 38.568 67.813 ;
     RECT  136.224 19.861 136.248 67.859 ;
     RECT  105 20.485 108.84 67.907 ;
     RECT  98.016 66.803 98.328 67.955 ;
     RECT  37.008 67.813 38.712 68.051 ;
     RECT  46.992 67.091 48.84 68.051 ;
     RECT  82.56 67.523 84.168 68.051 ;
     RECT  29.04 67.619 30.216 68.099 ;
     RECT  38.16 68.051 38.712 68.099 ;
     RECT  45.264 67.283 46.008 68.101 ;
     RECT  46.992 68.051 48.504 68.101 ;
     RECT  66.096 67.715 79.08 68.243 ;
     RECT  49.824 67.525 51.432 68.245 ;
     RECT  16.512 49.907 25.08 68.291 ;
     RECT  45.264 68.101 48.504 68.291 ;
     RECT  58.128 67.715 65.016 68.339 ;
     RECT  80.064 67.523 81.432 68.387 ;
     RECT  88.8 66.419 91.224 68.435 ;
     RECT  58.128 68.339 64.92 68.579 ;
     RECT  66.096 68.243 76.008 68.627 ;
     RECT  40.08 67.283 40.728 68.675 ;
     RECT  58.128 68.579 63.816 68.675 ;
     RECT  99.6 20.773 102.696 68.771 ;
     RECT  115.2 65.363 116.664 68.819 ;
     RECT  64.896 68.579 64.92 68.915 ;
     RECT  67.2 68.627 76.008 68.915 ;
     RECT  49.824 68.245 51.864 68.917 ;
     RECT  53.52 67.379 56.712 68.917 ;
     RECT  29.4 68.099 30.216 68.965 ;
     RECT  77.088 68.243 79.08 69.011 ;
     RECT  98.016 67.955 98.04 69.059 ;
     RECT  85.344 66.275 87.48 69.251 ;
     RECT  83.4 68.051 84.168 69.299 ;
     RECT  49.824 68.917 57.048 69.347 ;
     RECT  58.464 68.675 63.816 69.443 ;
     RECT  16.512 68.291 24.792 69.491 ;
     RECT  55.536 69.347 57.048 69.491 ;
     RECT  132 21.349 132.6 69.491 ;
     RECT  6.72 67.619 13.656 69.539 ;
     RECT  16.512 69.491 24.456 69.539 ;
     RECT  26.784 68.677 26.808 69.539 ;
     RECT  49.824 69.347 54.504 69.587 ;
     RECT  61.68 69.443 63.816 69.683 ;
     RECT  88.8 68.435 90.408 69.733 ;
     RECT  58.464 69.443 60.696 69.779 ;
     RECT  85.344 69.251 85.608 69.779 ;
     RECT  40.08 68.675 40.512 69.781 ;
     RECT  42.432 67.283 44.184 69.781 ;
     RECT  58.464 69.779 59.544 69.827 ;
     RECT  53.808 69.587 54.504 69.875 ;
     RECT  88.8 69.733 90.648 69.875 ;
     RECT  105 67.907 108.072 69.875 ;
     RECT  58.56 69.827 59.544 70.019 ;
     RECT  33.552 68.245 33.576 70.021 ;
     RECT  34.8 65.941 35.592 70.021 ;
     RECT  48.336 68.291 48.456 70.067 ;
     RECT  33.552 70.021 35.592 70.163 ;
     RECT  48.432 70.067 48.456 70.211 ;
     RECT  49.824 69.587 52.488 70.307 ;
     RECT  67.2 68.915 69.816 70.307 ;
     RECT  101.136 68.771 102.696 70.307 ;
     RECT  37.008 68.051 37.032 70.309 ;
     RECT  54.48 69.875 54.504 70.309 ;
     RECT  55.536 69.491 56.712 70.309 ;
     RECT  29.4 68.965 30.888 70.403 ;
     RECT  110.4 66.755 111.672 70.403 ;
     RECT  115.8 68.819 116.664 70.403 ;
     RECT  37.008 70.309 37.08 70.451 ;
     RECT  6.72 69.539 10.68 70.499 ;
     RECT  26.736 70.357 26.76 70.547 ;
     RECT  54.48 70.309 56.712 70.549 ;
     RECT  69.792 70.307 69.816 70.549 ;
     RECT  54.48 70.549 57.384 70.595 ;
     RECT  69.792 70.549 69.912 70.595 ;
     RECT  42.144 69.781 44.184 70.597 ;
     RECT  45.264 68.291 47.208 70.597 ;
     RECT  54.72 70.595 57.384 70.643 ;
     RECT  42.144 70.597 47.208 70.691 ;
     RECT  66.096 68.627 66.12 70.691 ;
     RECT  69.888 70.595 69.912 70.691 ;
     RECT  6.72 70.499 8.664 70.739 ;
     RECT  33.648 70.163 35.592 70.739 ;
     RECT  77.088 69.011 78.936 70.739 ;
     RECT  94.2 66.803 96.6 70.739 ;
     RECT  105 69.875 108.024 70.739 ;
     RECT  29.4 70.403 30.216 70.787 ;
     RECT  38.16 68.099 38.568 70.787 ;
     RECT  42.144 70.691 45.912 70.787 ;
     RECT  16.512 69.539 24.312 70.835 ;
     RECT  101.808 70.307 102.696 70.835 ;
     RECT  71.04 68.915 76.008 70.883 ;
     RECT  88.8 69.875 89.88 70.883 ;
     RECT  71.04 70.883 75 70.931 ;
     RECT  58.704 70.019 59.544 71.123 ;
     RECT  101.808 70.835 101.832 71.123 ;
     RECT  46.992 70.691 47.208 71.125 ;
     RECT  61.8 69.683 63.816 71.219 ;
     RECT  80.64 68.387 81.432 71.267 ;
     RECT  34.176 70.739 35.592 71.315 ;
     RECT  86.976 69.251 87.48 71.315 ;
     RECT  71.04 70.931 74.376 71.363 ;
     RECT  37.008 70.451 37.032 71.411 ;
     RECT  115.8 70.403 116.568 71.411 ;
     RECT  58.944 71.123 59.544 71.459 ;
     RECT  107.424 70.739 108.024 71.459 ;
     RECT  49.824 70.307 51.672 71.507 ;
     RECT  40.08 69.781 40.632 71.555 ;
     RECT  87.456 71.315 87.48 71.603 ;
     RECT  126.24 66.899 126.912 71.651 ;
     RECT  42.432 70.787 45.912 71.653 ;
     RECT  46.992 71.125 47.304 71.653 ;
     RECT  94.2 70.739 96.024 71.795 ;
     RECT  16.512 70.835 19.08 71.797 ;
     RECT  20.064 70.835 24.312 71.797 ;
     RECT  85.584 69.779 85.608 71.939 ;
     RECT  71.04 71.363 71.544 71.987 ;
     RECT  16.512 71.797 24.312 72.035 ;
     RECT  6.912 70.739 8.664 72.179 ;
     RECT  18.096 72.035 24.312 72.227 ;
     RECT  60.672 69.779 60.696 72.275 ;
     RECT  80.64 71.267 80.664 72.323 ;
     RECT  9.648 70.499 10.68 72.419 ;
     RECT  71.04 71.987 71.064 72.419 ;
     RECT  38.544 70.787 38.568 72.467 ;
     RECT  18.096 72.227 19.032 72.515 ;
     RECT  34.8 71.315 35.592 72.515 ;
     RECT  29.4 70.787 29.832 72.517 ;
     RECT  40.08 71.555 40.512 72.517 ;
     RECT  55.536 70.643 57.384 72.517 ;
     RECT  58.944 71.459 59.256 72.563 ;
     RECT  77.184 70.739 78.936 72.563 ;
     RECT  132 69.491 132.504 72.563 ;
     RECT  49.824 71.507 51.432 72.611 ;
     RECT  54.816 72.517 57.384 72.659 ;
     RECT  54.816 72.659 57.24 72.803 ;
     RECT  61.8 71.219 62.52 72.803 ;
     RECT  49.824 72.611 49.944 72.805 ;
     RECT  29.4 72.517 30.888 72.851 ;
     RECT  40.08 72.517 40.728 72.851 ;
     RECT  99.6 68.771 100.008 72.851 ;
     RECT  49.584 72.805 49.944 72.947 ;
     RECT  42.432 71.653 47.304 72.995 ;
     RECT  108 71.459 108.024 72.995 ;
     RECT  105 70.739 105.864 73.043 ;
     RECT  40.08 72.851 40.512 73.091 ;
     RECT  87.792 72.181 87.816 73.091 ;
     RECT  121.2 21.587 122.328 73.091 ;
     RECT  67.2 70.307 68.76 73.139 ;
     RECT  44.16 72.995 47.304 73.187 ;
     RECT  14.832 72.997 14.856 73.283 ;
     RECT  45.264 73.187 47.304 73.283 ;
     RECT  94.2 71.795 95.448 73.283 ;
     RECT  51 72.611 51.432 73.285 ;
     RECT  45.264 73.283 46.008 73.331 ;
     RECT  20.064 72.227 24.312 73.379 ;
     RECT  94.2 73.283 94.92 73.379 ;
     RECT  55.536 72.803 57.24 73.427 ;
     RECT  38.784 73.237 38.808 73.475 ;
     RECT  20.064 73.379 22.2 73.571 ;
     RECT  34.8 72.515 35.352 73.571 ;
     RECT  59.232 72.563 59.256 73.571 ;
     RECT  63.792 71.219 63.816 73.571 ;
     RECT  22.176 73.571 22.2 73.619 ;
     RECT  72.6 71.363 74.376 73.619 ;
     RECT  20.064 73.571 21.096 73.811 ;
     RECT  16.512 72.035 17.064 73.859 ;
     RECT  42.432 72.995 43.032 73.859 ;
     RECT  61.8 72.803 62.328 73.859 ;
     RECT  42.432 73.859 42.456 73.907 ;
     RECT  44.16 73.187 44.184 74.051 ;
     RECT  45.264 73.331 45.912 74.099 ;
     RECT  11.712 69.539 13.656 74.147 ;
     RECT  6.912 72.179 8.424 74.195 ;
     RECT  9.648 72.419 10.392 74.387 ;
     RECT  16.512 73.859 16.536 74.387 ;
     RECT  9.648 74.387 9.672 74.435 ;
     RECT  47.28 73.283 47.304 74.435 ;
     RECT  49.584 72.947 49.608 74.483 ;
     RECT  51 73.285 51.528 74.579 ;
     RECT  20.064 73.811 21.048 74.627 ;
     RECT  56.4 73.427 57.24 74.627 ;
     RECT  18.432 72.515 19.032 74.675 ;
     RECT  61.8 73.859 62.232 74.675 ;
     RECT  6.912 74.195 8.112 74.723 ;
     RECT  74.352 73.619 74.376 74.723 ;
     RECT  88.8 70.883 89.784 74.723 ;
     RECT  23.52 73.379 24.312 74.867 ;
     RECT  20.064 74.627 20.184 74.915 ;
     RECT  77.184 72.563 78.312 74.915 ;
     RECT  67.2 73.139 68.136 74.963 ;
     RECT  11.712 74.147 13.512 75.011 ;
     RECT  56.4 74.627 57.144 75.011 ;
     RECT  20.064 74.915 20.088 75.155 ;
     RECT  83.4 69.299 84.072 75.155 ;
     RECT  18.432 74.675 18.912 75.203 ;
     RECT  75.984 70.883 76.008 75.203 ;
     RECT  12.624 75.011 13.512 75.251 ;
     RECT  51 74.579 51.432 75.251 ;
     RECT  2.4 47.987 2.712 86.409 ;
     RECT  7.8 74.723 8.112 86.409 ;
     RECT  13.2 75.251 13.512 86.409 ;
     RECT  18.6 75.203 18.912 86.409 ;
     RECT  24 74.867 24.312 86.409 ;
     RECT  29.4 72.851 29.712 86.409 ;
     RECT  34.8 73.571 35.112 86.409 ;
     RECT  40.2 73.091 40.512 86.409 ;
     RECT  45.6 74.099 45.912 86.409 ;
     RECT  51 75.251 51.312 86.409 ;
     RECT  56.4 75.011 56.712 86.409 ;
     RECT  61.8 74.675 62.112 86.409 ;
     RECT  67.2 74.963 67.512 86.409 ;
     RECT  72.6 73.619 72.912 86.409 ;
     RECT  78 74.915 78.312 86.409 ;
     RECT  83.4 75.155 83.712 86.409 ;
     RECT  88.8 74.723 89.112 86.409 ;
     RECT  94.2 73.379 94.512 86.409 ;
     RECT  99.6 72.851 99.912 86.409 ;
     RECT  105 73.043 105.312 86.409 ;
     RECT  110.4 70.403 110.712 86.409 ;
     RECT  115.8 71.411 116.112 86.409 ;
     RECT  121.2 73.091 121.512 86.409 ;
     RECT  126.6 71.651 126.912 86.409 ;
     RECT  132 72.563 132.312 86.409 ;
     RECT  137.4 2.151 137.712 86.409 ;
     RECT  142.8 21.779 143.112 86.409 ;
     RECT  148.2 2.151 148.512 86.409 ;
     RECT  153.6 2.151 153.912 86.409 ;
     RECT  159 2.151 159.312 86.409 ;
     RECT  164.4 2.151 164.712 86.409 ;
     RECT  169.8 2.151 170.112 86.409 ;
     RECT  175.2 2.151 175.512 86.409 ;
     RECT  180.6 2.151 180.912 86.409 ;
     RECT  186 2.151 186.312 86.409 ;
     RECT  191.4 2.151 191.712 86.409 ;
     RECT  196.8 67.043 197.112 86.409 ;
     RECT  202.2 2.151 202.512 86.409 ;
     RECT  207.6 2.151 207.912 86.409 ;
     RECT  213 2.151 213.312 86.409 ;
     RECT  2.4 86.409 2.52 86.423 ;
     RECT  7.8 86.409 7.92 86.423 ;
     RECT  13.2 86.409 13.32 86.423 ;
     RECT  18.6 86.409 18.72 86.423 ;
     RECT  24 86.409 24.12 86.423 ;
     RECT  29.4 86.409 29.52 86.423 ;
     RECT  34.8 86.409 34.92 86.423 ;
     RECT  40.2 86.409 40.32 86.423 ;
     RECT  45.6 86.409 45.72 86.423 ;
     RECT  51 86.409 51.12 86.423 ;
     RECT  56.4 86.409 56.52 86.423 ;
     RECT  61.8 86.409 61.92 86.423 ;
     RECT  67.2 86.409 67.32 86.423 ;
     RECT  72.6 86.409 72.72 86.423 ;
     RECT  78 86.409 78.12 86.423 ;
     RECT  83.4 86.409 83.52 86.423 ;
     RECT  88.8 86.409 88.92 86.423 ;
     RECT  94.2 86.409 94.32 86.423 ;
     RECT  99.6 86.409 99.72 86.423 ;
     RECT  105 86.409 105.12 86.423 ;
     RECT  110.4 86.409 110.52 86.423 ;
     RECT  115.8 86.409 115.92 86.423 ;
     RECT  121.2 86.409 121.32 86.423 ;
     RECT  126.6 86.409 126.72 86.423 ;
     RECT  132 86.409 132.12 86.423 ;
     RECT  137.4 86.409 137.52 86.423 ;
     RECT  142.8 86.409 142.92 86.423 ;
     RECT  148.2 86.409 148.32 86.423 ;
     RECT  153.6 86.409 153.72 86.423 ;
     RECT  159 86.409 159.12 86.423 ;
     RECT  164.4 86.409 164.52 86.423 ;
     RECT  169.8 86.409 169.92 86.423 ;
     RECT  175.2 86.409 175.32 86.423 ;
     RECT  180.6 86.409 180.72 86.423 ;
     RECT  186 86.409 186.12 86.423 ;
     RECT  191.4 86.409 191.52 86.423 ;
     RECT  196.8 86.409 196.92 86.423 ;
     RECT  202.2 86.409 202.32 86.423 ;
     RECT  207.6 86.409 207.72 86.423 ;
     RECT  213 86.409 213.12 86.423 ;
     RECT  40.488 0.517 41.856 1.909 ;
     RECT  47.784 1.573 49.008 1.859 ;
     RECT  37.032 1.669 38.4 1.909 ;
     RECT  6.168 1.717 7.2 7.957 ;
     RECT  35.4 1.717 36.384 2.003 ;
     RECT  47.784 1.859 48.648 3.205 ;
     RECT  37.176 1.909 38.4 2.389 ;
     RECT  40.776 1.909 41.856 2.101 ;
     RECT  35.256 2.003 36.384 3.491 ;
     RECT  40.824 2.101 41.856 2.485 ;
     RECT  51.12 2.137 52.368 2.151 ;
     RECT  28.056 2.149 29.4 2.869 ;
     RECT  51.312 2.151 52.368 2.629 ;
     RECT  38.664 2.197 39.984 2.387 ;
     RECT  53.16 2.245 54.336 2.437 ;
     RECT  83.712 2.245 84.72 3.973 ;
     RECT  29.712 2.293 31.008 3.205 ;
     RECT  31.032 2.293 32.4 3.829 ;
     RECT  46.2 2.293 47.712 2.437 ;
     RECT  26.184 2.341 27.264 3.349 ;
     RECT  42.504 2.341 43.872 3.059 ;
     RECT  38.424 2.387 39.984 2.629 ;
     RECT  37.416 2.389 38.4 2.629 ;
     RECT  60.504 2.389 61.8 2.579 ;
     RECT  34.704 2.435 34.8 2.869 ;
     RECT  8.112 2.437 9.12 3.011 ;
     RECT  46.2 2.437 47.616 2.677 ;
     RECT  53.256 2.437 54.336 2.485 ;
     RECT  11.928 2.533 13.104 2.723 ;
     RECT  68.76 2.533 69.792 2.917 ;
     RECT  60.12 2.579 61.8 2.677 ;
     RECT  16.968 2.581 18.48 2.723 ;
     RECT  38.424 2.629 39.648 3.253 ;
     RECT  46.584 2.677 47.616 2.723 ;
     RECT  60.12 2.677 61.68 2.965 ;
     RECT  13.008 2.723 13.104 3.397 ;
     RECT  46.584 2.723 47.664 4.069 ;
     RECT  57.096 2.723 57.528 2.965 ;
     RECT  22.296 2.773 23.376 3.731 ;
     RECT  93 2.773 94.2 3.301 ;
     RECT  28.2 2.869 29.4 3.493 ;
     RECT  33.192 2.869 34.8 3.493 ;
     RECT  64.056 2.869 65.088 2.917 ;
     RECT  62.112 2.917 63.552 3.685 ;
     RECT  57.096 2.965 58.128 3.781 ;
     RECT  58.152 2.965 59.232 3.589 ;
     RECT  60.12 2.965 61.152 4.597 ;
     RECT  8.112 3.011 8.424 3.637 ;
     RECT  42.504 3.059 44.4 3.205 ;
     RECT  29.832 3.205 31.008 3.971 ;
     RECT  43.224 3.205 44.4 3.347 ;
     RECT  38.424 3.253 39.552 3.541 ;
     RECT  87.384 3.253 88.8 3.395 ;
     RECT  65.112 3.299 65.16 4.069 ;
     RECT  93 3.301 94.08 4.453 ;
     RECT  42.504 3.347 44.4 4.021 ;
     RECT  99.912 3.349 100.896 4.403 ;
     RECT  100.92 3.349 102.192 4.403 ;
     RECT  25.128 3.397 26.16 4.117 ;
     RECT  70.68 3.397 71.808 4.019 ;
     RECT  18.48 3.443 18.6 4.933 ;
     RECT  35.256 3.491 36.432 4.261 ;
     RECT  28.248 3.493 29.4 3.637 ;
     RECT  33.192 3.493 34.224 3.685 ;
     RECT  28.344 3.637 29.4 3.685 ;
     RECT  62.112 3.685 63.456 3.733 ;
     RECT  31.368 3.829 32.4 4.885 ;
     RECT  76.776 3.925 78 4.165 ;
     RECT  29.712 3.971 31.008 4.741 ;
     RECT  62.112 4.019 63.408 5.605 ;
     RECT  70.68 4.019 72.144 4.933 ;
     RECT  42.504 4.021 43.872 4.645 ;
     RECT  69.48 4.067 70.512 4.355 ;
     RECT  65.112 4.069 66.576 4.501 ;
     RECT  25.176 4.117 26.16 5.795 ;
     RECT  76.968 4.165 78 5.507 ;
     RECT  83.712 4.259 84.72 5.363 ;
     RECT  35.4 4.261 36.432 4.549 ;
     RECT  54.552 4.261 56.016 4.453 ;
     RECT  79.032 4.261 80.4 5.125 ;
     RECT  51.312 4.307 52.368 5.461 ;
     RECT  69.096 4.355 70.512 5.029 ;
     RECT  99.912 4.403 102.192 5.077 ;
     RECT  54.888 4.453 56.016 4.837 ;
     RECT  0.144 4.499 0.168 5.989 ;
     RECT  65.112 4.501 66.24 4.595 ;
     RECT  68.088 4.547 69.072 5.555 ;
     RECT  35.4 4.549 36.384 4.739 ;
     RECT  72.912 4.549 73.968 4.981 ;
     RECT  13.008 4.595 13.2 4.741 ;
     RECT  64.584 4.595 66.24 5.221 ;
     RECT  27.192 4.643 28.176 5.605 ;
     RECT  42.648 4.645 43.872 4.789 ;
     RECT  35.4 4.739 37.104 5.221 ;
     RECT  12.216 4.741 13.2 4.883 ;
     RECT  29.712 4.741 30.96 5.077 ;
     RECT  42.792 4.789 43.872 5.653 ;
     RECT  12.192 4.883 13.2 5.653 ;
     RECT  70.728 4.933 72.144 5.459 ;
     RECT  69.096 5.029 70.32 5.365 ;
     RECT  99.912 5.077 101.424 6.661 ;
     RECT  79.032 5.125 80.304 5.411 ;
     RECT  54.888 5.171 56.016 5.987 ;
     RECT  91.368 5.173 92.544 5.315 ;
     RECT  35.736 5.221 37.104 5.989 ;
     RECT  64.584 5.221 66.144 5.845 ;
     RECT  30.984 5.363 32.16 7.381 ;
     RECT  83.712 5.363 84.96 5.747 ;
     RECT  79.032 5.411 80.4 5.747 ;
     RECT  94.512 5.411 94.632 5.797 ;
     RECT  70.728 5.459 72.48 5.701 ;
     RECT  60.648 5.507 61.68 6.323 ;
     RECT  76.776 5.507 78 6.517 ;
     RECT  87.672 5.509 88.8 6.181 ;
     RECT  68.088 5.555 69.408 5.749 ;
     RECT  62.112 5.605 63.264 5.701 ;
     RECT  11.736 5.653 13.2 5.893 ;
     RECT  17.4 5.653 18.48 5.747 ;
     RECT  71.064 5.701 72.48 6.323 ;
     RECT  17.4 5.747 18.6 6.131 ;
     RECT  83.712 5.747 85.104 6.661 ;
     RECT  15.864 5.749 17.088 5.987 ;
     RECT  68.376 5.749 69.408 5.891 ;
     RECT  25.128 5.795 26.16 7.237 ;
     RECT  94.512 5.797 95.568 6.709 ;
     RECT  64.68 5.845 66.144 6.179 ;
     RECT  68.088 5.891 69.408 6.997 ;
     RECT  15.84 5.987 17.088 6.035 ;
     RECT  23.472 5.987 23.616 7.237 ;
     RECT  53.928 5.987 56.016 6.563 ;
     RECT  35.736 5.989 36.768 6.325 ;
     RECT  15.84 6.035 17.184 6.083 ;
     RECT  11.736 6.083 13.104 8.627 ;
     RECT  15.84 6.083 17.376 6.131 ;
     RECT  15.84 6.131 16.632 6.805 ;
     RECT  62.76 6.131 63.936 7.811 ;
     RECT  80.4 6.131 80.688 7.621 ;
     RECT  64.68 6.179 66.48 6.517 ;
     RECT  87.672 6.181 88.704 7.429 ;
     RECT  58.056 6.275 59.04 7.043 ;
     RECT  73.704 6.275 74.832 6.323 ;
     RECT  60.96 6.323 61.68 6.613 ;
     RECT  70.392 6.323 72.48 6.469 ;
     RECT  19.608 6.469 21.12 6.805 ;
     RECT  70.392 6.469 72.288 6.949 ;
     RECT  64.968 6.517 66.48 7.381 ;
     RECT  76.968 6.517 78 7.571 ;
     RECT  81.48 6.517 82.704 7.139 ;
     RECT  53.784 6.563 56.016 7.045 ;
     RECT  89.4 6.611 90.816 7.139 ;
     RECT  2.712 6.661 3.936 6.851 ;
     RECT  83.832 6.661 85.104 6.997 ;
     RECT  99.912 6.661 101.328 7.907 ;
     RECT  94.512 6.709 95.52 11.461 ;
     RECT  15.384 6.805 16.632 7.093 ;
     RECT  70.392 6.949 72.096 7.285 ;
     RECT  58.056 7.043 58.152 7.813 ;
     RECT  87.36 7.043 87.648 8.149 ;
     RECT  53.784 7.045 54.768 7.765 ;
     RECT  54.792 7.045 56.016 7.189 ;
     RECT  15.48 7.093 16.632 7.237 ;
     RECT  102.216 7.141 103.728 9.155 ;
     RECT  103.752 7.141 105 8.869 ;
     RECT  54.936 7.189 56.016 7.765 ;
     RECT  68.088 7.235 69.408 7.523 ;
     RECT  15.48 7.237 16.608 7.379 ;
     RECT  71.208 7.331 72.288 8.435 ;
     RECT  15.384 7.379 16.608 7.667 ;
     RECT  64.968 7.381 66.288 7.667 ;
     RECT  68.088 7.523 68.712 8.245 ;
     RECT  76.776 7.571 78 8.771 ;
     RECT  92.448 7.571 93.408 7.957 ;
     RECT  75.36 7.619 75.792 8.245 ;
     RECT  64.968 7.667 66.672 7.765 ;
     RECT  79.32 7.717 80.304 7.907 ;
     RECT  55.032 7.765 56.016 8.677 ;
     RECT  65.16 7.765 66.672 8.101 ;
     RECT  62.112 7.811 63.936 8.869 ;
     RECT  19.608 7.859 20.52 8.677 ;
     RECT  79.32 7.907 80.688 7.955 ;
     RECT  99.912 7.907 102.192 8.965 ;
     RECT  78.648 7.955 79.128 9.349 ;
     RECT  91.752 7.957 93.408 8.099 ;
     RECT  89.304 8.051 89.4 9.445 ;
     RECT  92.88 8.099 93.408 8.195 ;
     RECT  65.256 8.101 66.672 8.341 ;
     RECT  109.368 8.149 110.4 9.589 ;
     RECT  92.88 8.195 94.2 8.869 ;
     RECT  73.032 8.245 74.544 8.293 ;
     RECT  74.568 8.245 75.792 8.387 ;
     RECT  73.176 8.293 74.544 8.435 ;
     RECT  65.592 8.341 66.672 8.579 ;
     RECT  80.808 8.387 80.952 9.539 ;
     RECT  70.968 8.435 72.288 9.107 ;
     RECT  73.176 8.435 73.992 9.349 ;
     RECT  65.448 8.579 66.672 9.491 ;
     RECT  11.736 8.627 13.2 13.861 ;
     RECT  19.608 8.677 21.12 8.869 ;
     RECT  76.944 8.771 78 8.917 ;
     RECT  62.112 8.869 63.216 10.883 ;
     RECT  92.904 8.869 94.2 9.059 ;
     RECT  76.968 8.917 78 9.971 ;
     RECT  100.008 8.965 102.192 9.205 ;
     RECT  19.608 9.011 21.12 9.875 ;
     RECT  21.912 9.013 22.944 13.381 ;
     RECT  70.968 9.107 72.384 9.395 ;
     RECT  100.632 9.205 102.192 9.253 ;
     RECT  58.056 9.251 58.152 9.925 ;
     RECT  100.824 9.253 102.192 9.491 ;
     RECT  80.688 9.347 80.784 9.539 ;
     RECT  70.968 9.395 72.48 11.891 ;
     RECT  95.688 9.397 97.104 9.539 ;
     RECT  89.304 9.445 90.288 9.635 ;
     RECT  65.256 9.491 66.672 9.875 ;
     RECT  80.688 9.539 80.952 9.781 ;
     RECT  95.592 9.539 97.104 10.597 ;
     RECT  87.72 9.635 88.704 13.765 ;
     RECT  89.112 9.635 90.288 13.379 ;
     RECT  80.688 9.781 80.928 9.923 ;
     RECT  19.608 9.875 19.656 10.789 ;
     RECT  64.968 9.875 66.672 10.933 ;
     RECT  108.816 9.875 108.864 11.125 ;
     RECT  80.688 9.923 80.952 10.309 ;
     RECT  105.312 9.923 105.432 10.933 ;
     RECT  58.056 9.925 59.328 10.837 ;
     RECT  76.944 9.971 78 10.597 ;
     RECT  6.12 10.307 7.2 10.883 ;
     RECT  79.368 10.309 80.952 10.597 ;
     RECT  59.88 10.405 60.912 10.645 ;
     RECT  68.424 10.451 68.52 10.981 ;
     RECT  76.944 10.597 77.712 11.125 ;
     RECT  80.136 10.597 80.952 11.123 ;
     RECT  95.592 10.597 96.96 10.981 ;
     RECT  59.928 10.645 60.912 11.989 ;
     RECT  58.056 10.837 59.28 12.421 ;
     RECT  6.12 10.883 7.344 11.123 ;
     RECT  62.112 10.883 63.84 12.277 ;
     RECT  64.968 10.933 66.288 11.797 ;
     RECT  68.424 10.981 69.504 11.605 ;
     RECT  6.384 11.123 7.344 11.459 ;
     RECT  79.848 11.123 80.952 11.219 ;
     RECT  8.112 11.171 9.216 12.755 ;
     RECT  80.928 11.219 80.952 11.413 ;
     RECT  17.4 11.221 18.432 11.843 ;
     RECT  95.592 11.315 97.104 12.517 ;
     RECT  16.056 11.413 17.376 11.797 ;
     RECT  6.384 11.459 7.8 12.037 ;
     RECT  75.288 11.509 76.512 11.651 ;
     RECT  103.128 11.605 104.64 11.843 ;
     RECT  75.288 11.651 76.656 11.891 ;
     RECT  69.096 11.747 70.368 11.843 ;
     RECT  17.4 11.843 18.6 11.941 ;
     RECT  81 11.843 81.144 11.939 ;
     RECT  94.512 11.843 95.52 13.909 ;
     RECT  99.216 11.843 99.456 11.987 ;
     RECT  103.128 11.843 103.272 12.997 ;
     RECT  70.968 11.891 72.6 13.141 ;
     RECT  75.312 11.891 76.896 12.083 ;
     RECT  85.128 11.893 86.496 12.227 ;
     RECT  80.976 11.939 81.144 13.141 ;
     RECT  17.496 11.941 18.6 13.621 ;
     RECT  99.216 11.987 99.6 13.045 ;
     RECT  6.384 12.037 6.432 12.229 ;
     RECT  6.456 12.037 7.8 13.909 ;
     RECT  75.312 12.083 76.944 12.515 ;
     RECT  62.112 12.277 63.312 12.517 ;
     RECT  58.2 12.421 59.28 13.043 ;
     RECT  75.312 12.515 77.088 13.189 ;
     RECT  87.312 12.515 87.36 13.573 ;
     RECT  95.592 12.517 96.672 13.043 ;
     RECT  96.696 12.755 97.56 13.043 ;
     RECT  19.656 12.949 20.736 16.069 ;
     RECT  92.712 12.949 94.2 13.235 ;
     RECT  58.056 13.043 59.28 15.157 ;
     RECT  95.592 13.043 97.56 13.045 ;
     RECT  95.592 13.045 98.112 13.477 ;
     RECT  98.136 13.045 99.6 13.909 ;
     RECT  103.008 13.139 103.104 13.523 ;
     RECT  70.968 13.141 72.336 14.147 ;
     RECT  79.752 13.141 81.144 13.189 ;
     RECT  75.336 13.189 77.088 13.333 ;
     RECT  79.752 13.189 81.12 13.667 ;
     RECT  75.72 13.333 77.088 13.475 ;
     RECT  81.144 13.333 82.56 13.763 ;
     RECT  75.336 13.475 77.088 13.477 ;
     RECT  75.336 13.477 77.04 13.765 ;
     RECT  96.216 13.477 98.112 14.485 ;
     RECT  103.008 13.523 103.248 13.573 ;
     RECT  101.64 13.573 103.248 13.859 ;
     RECT  17.496 13.621 18.48 13.909 ;
     RECT  79.464 13.667 81.12 13.763 ;
     RECT  79.464 13.763 82.56 14.437 ;
     RECT  75.336 13.765 76.944 14.533 ;
     RECT  101.112 13.859 103.248 14.195 ;
     RECT  11.736 13.861 12.816 13.955 ;
     RECT  6.456 13.909 7.536 14.339 ;
     RECT  98.136 13.909 99.312 14.243 ;
     RECT  69.648 13.955 70.368 13.957 ;
     RECT  69 13.957 70.368 14.147 ;
     RECT  53.064 14.099 54.144 15.685 ;
     RECT  68.088 14.147 68.808 15.205 ;
     RECT  70.968 14.147 72.6 14.677 ;
     RECT  99.912 14.147 100.896 14.339 ;
     RECT  100.92 14.195 103.248 14.339 ;
     RECT  98.136 14.243 99.6 16.931 ;
     RECT  91.656 14.291 92.568 14.435 ;
     RECT  6.456 14.339 7.8 14.387 ;
     RECT  99.912 14.339 100.008 15.253 ;
     RECT  102.432 14.339 103.248 14.533 ;
     RECT  91.632 14.435 92.568 15.109 ;
     RECT  94.512 14.435 95.52 16.021 ;
     RECT  79.464 14.437 82.032 14.483 ;
     RECT  79.128 14.483 79.224 15.637 ;
     RECT  80.928 14.483 82.032 15.061 ;
     RECT  96.696 14.485 98.112 15.397 ;
     RECT  75.768 14.533 76.944 14.869 ;
     RECT  103.416 14.533 104.88 15.491 ;
     RECT  24.312 14.627 25.392 15.637 ;
     RECT  71.352 14.677 72.6 16.453 ;
     RECT  80.928 15.061 81.024 15.109 ;
     RECT  81.048 15.061 82.032 15.251 ;
     RECT  89.544 15.109 90.576 15.541 ;
     RECT  90.6 15.109 92.568 15.205 ;
     RECT  58.056 15.157 59.184 15.299 ;
     RECT  75.72 15.203 77.184 15.731 ;
     RECT  91.56 15.205 92.568 15.347 ;
     RECT  80.928 15.251 82.032 15.731 ;
     RECT  58.056 15.299 59.28 18.085 ;
     RECT  90.6 15.347 92.568 15.349 ;
     RECT  90.6 15.349 92.88 15.445 ;
     RECT  92.904 15.349 94.2 16.741 ;
     RECT  54.6 15.395 55.968 16.501 ;
     RECT  87.576 15.395 88.608 16.357 ;
     RECT  96.792 15.397 98.112 15.587 ;
     RECT  75.312 15.443 75.696 15.731 ;
     RECT  90.6 15.445 92.352 16.501 ;
     RECT  96.696 15.587 98.112 16.019 ;
     RECT  27.768 15.683 28.944 16.789 ;
     RECT  75.312 15.731 77.184 16.837 ;
     RECT  80.928 15.731 82.272 16.693 ;
     RECT  83.832 15.731 84.36 16.741 ;
     RECT  105.312 15.779 105.432 17.125 ;
     RECT  89.544 15.827 90.576 16.211 ;
     RECT  26.472 15.971 27.696 16.595 ;
     RECT  96.6 16.019 98.112 16.405 ;
     RECT  13.512 16.021 14.832 16.117 ;
     RECT  65.112 16.115 66.384 17.653 ;
     RECT  67.8 16.115 68.784 17.509 ;
     RECT  13.656 16.117 14.832 16.165 ;
     RECT  89.448 16.211 90.576 16.691 ;
     RECT  59.64 16.307 60.624 17.941 ;
     RECT  48.696 16.355 49.824 17.509 ;
     RECT  96.6 16.405 97.728 16.931 ;
     RECT  110.712 16.451 110.808 17.461 ;
     RECT  71.352 16.453 72.48 17.365 ;
     RECT  54.6 16.501 55.92 17.891 ;
     RECT  90.6 16.501 91.584 16.691 ;
     RECT  26.472 16.595 27.744 17.701 ;
     RECT  69.096 16.597 70.368 17.267 ;
     RECT  100.104 16.597 101.088 17.125 ;
     RECT  101.112 16.597 102.432 16.741 ;
     RECT  89.448 16.691 91.584 16.933 ;
     RECT  80.952 16.693 82.272 16.835 ;
     RECT  84.12 16.741 84.36 16.885 ;
     RECT  92.952 16.741 94.2 16.789 ;
     RECT  101.304 16.741 102.432 18.997 ;
     RECT  87.432 16.787 88.512 18.037 ;
     RECT  93.144 16.789 94.2 16.931 ;
     RECT  80.952 16.835 83.232 16.837 ;
     RECT  73.512 16.837 74.688 17.363 ;
     RECT  74.712 16.837 77.184 16.981 ;
     RECT  81.24 16.837 83.232 17.077 ;
     RECT  84.12 16.885 85.68 16.933 ;
     RECT  92.712 16.931 94.2 17.075 ;
     RECT  96.6 16.931 99.6 16.933 ;
     RECT  89.448 16.933 90.624 17.219 ;
     RECT  96.6 16.933 98.448 17.125 ;
     RECT  98.472 16.933 99.6 17.219 ;
     RECT  74.712 16.981 76.8 17.029 ;
     RECT  74.712 17.029 75.984 17.317 ;
     RECT  27.768 17.075 28.944 18.035 ;
     RECT  92.616 17.075 94.2 18.181 ;
     RECT  79.224 17.077 80.352 17.459 ;
     RECT  81.864 17.077 83.232 17.267 ;
     RECT  96.984 17.125 98.448 17.219 ;
     RECT  105.312 17.125 106.464 17.413 ;
     RECT  96.984 17.219 99.6 17.459 ;
     RECT  69 17.267 70.368 18.805 ;
     RECT  81 17.267 83.232 18.421 ;
     RECT  74.808 17.317 75.984 17.843 ;
     RECT  73.512 17.363 74.784 17.843 ;
     RECT  105.312 17.413 106.368 17.651 ;
     RECT  79.224 17.459 80.688 17.507 ;
     RECT  96.888 17.459 99.6 18.469 ;
     RECT  71.496 17.507 72.6 18.083 ;
     RECT  79.224 17.507 80.784 17.603 ;
     RECT  4.344 17.509 5.712 21.733 ;
     RECT  8.112 17.509 9.264 18.467 ;
     RECT  79.224 17.603 80.976 18.325 ;
     RECT  83.832 17.603 85.344 19.861 ;
     RECT  85.896 17.699 86.976 18.709 ;
     RECT  73.512 17.843 75.984 18.467 ;
     RECT  102.696 17.843 103.416 19.237 ;
     RECT  54.552 17.891 55.92 18.899 ;
     RECT  27.768 18.035 29.04 19.429 ;
     RECT  70.392 18.083 72.6 18.757 ;
     RECT  106.896 18.131 107.184 19.333 ;
     RECT  92.616 18.181 94.08 18.373 ;
     RECT  59.64 18.323 60.624 18.563 ;
     RECT  79.608 18.325 80.976 18.707 ;
     RECT  100.248 18.371 101.28 19.525 ;
     RECT  92.664 18.373 94.08 18.517 ;
     RECT  81 18.421 82.8 18.613 ;
     RECT  8.112 18.467 9.648 19.813 ;
     RECT  73.272 18.467 75.984 18.517 ;
     RECT  96.888 18.469 98.304 18.661 ;
     RECT  98.328 18.469 99.6 19.525 ;
     RECT  73.272 18.517 75.744 18.901 ;
     RECT  92.664 18.517 94.032 18.659 ;
     RECT  59.304 18.563 60.624 20.003 ;
     RECT  81.768 18.613 82.8 18.899 ;
     RECT  26.472 18.659 27.744 20.963 ;
     RECT  91.608 18.659 92.592 20.101 ;
     RECT  92.664 18.659 94.2 19.189 ;
     RECT  96.936 18.661 98.304 19.093 ;
     RECT  79.176 18.707 80.976 18.709 ;
     RECT  79.176 18.709 80.88 18.899 ;
     RECT  24.408 18.755 25.392 19.235 ;
     RECT  70.392 18.757 71.52 20.533 ;
     RECT  71.544 18.757 72.6 19.477 ;
     RECT  69.096 18.805 70.368 19.333 ;
     RECT  6.072 18.853 7.536 19.525 ;
     RECT  54.072 18.899 55.92 18.901 ;
     RECT  79.176 18.899 81.12 18.947 ;
     RECT  81.432 18.899 82.8 20.197 ;
     RECT  54.072 18.901 55.104 19.187 ;
     RECT  73.272 18.901 75.696 19.237 ;
     RECT  79.08 18.947 81.12 20.101 ;
     RECT  96.936 19.093 98.064 19.573 ;
     RECT  35.736 19.187 36.72 20.293 ;
     RECT  54.072 19.187 55.92 20.197 ;
     RECT  92.904 19.189 94.2 19.525 ;
     RECT  110.712 19.189 111.984 19.237 ;
     RECT  24.312 19.235 25.392 21.541 ;
     RECT  73.272 19.237 74.88 19.861 ;
     RECT  102.696 19.237 104.88 19.333 ;
     RECT  110.712 19.237 111.792 19.333 ;
     RECT  102.696 19.333 103.968 67.331 ;
     RECT  105.312 19.333 106.56 19.909 ;
     RECT  27.912 19.429 29.04 19.715 ;
     RECT  103.992 19.523 105 67.331 ;
     RECT  6.072 19.525 7.056 19.573 ;
     RECT  93.192 19.525 94.2 67.763 ;
     RECT  98.328 19.525 99.36 20.101 ;
     RECT  100.056 19.667 101.04 20.773 ;
     RECT  27.768 19.715 29.04 21.107 ;
     RECT  107.208 19.717 108.288 19.909 ;
     RECT  30.36 19.811 31.488 20.867 ;
     RECT  8.112 19.813 9.168 29.605 ;
     RECT  73.512 19.861 74.88 20.149 ;
     RECT  83.832 19.861 85.2 20.003 ;
     RECT  136.248 19.861 137.4 67.859 ;
     RECT  14.28 19.955 15.264 21.253 ;
     RECT  59.304 20.003 60.912 20.725 ;
     RECT  83.832 20.003 85.344 20.437 ;
     RECT  89.112 20.051 90.288 21.013 ;
     RECT  79.464 20.101 81.12 20.149 ;
     RECT  79.464 20.149 80.928 20.341 ;
     RECT  54.12 20.197 55.92 20.389 ;
     RECT  81.768 20.197 82.8 20.677 ;
     RECT  79.464 20.341 80.64 20.581 ;
     RECT  98.328 20.387 99.6 67.955 ;
     RECT  54.792 20.389 55.92 21.925 ;
     RECT  84.312 20.437 85.344 23.699 ;
     RECT  31.512 20.579 32.688 20.867 ;
     RECT  32.712 20.579 33.888 21.875 ;
     RECT  35.784 20.627 36.768 21.299 ;
     RECT  59.544 20.725 60.912 20.869 ;
     RECT  43.608 20.771 44.688 21.925 ;
     RECT  30.36 20.867 30.936 21.493 ;
     RECT  59.64 20.869 60.912 21.541 ;
     RECT  26.376 20.963 27.744 21.107 ;
     RECT  113.928 21.061 115.2 67.667 ;
     RECT  26.232 21.107 27.744 21.587 ;
     RECT  27.768 21.107 29.4 22.165 ;
     RECT  48.216 21.155 49.248 23.125 ;
     RECT  116.712 21.157 118.224 65.363 ;
     RECT  35.688 21.299 36.768 21.827 ;
     RECT  7.68 21.395 7.8 22.837 ;
     RECT  59.64 21.541 60.672 22.021 ;
     RECT  9.192 21.683 10.224 21.923 ;
     RECT  38.952 21.683 39.936 21.731 ;
     RECT  14.136 21.731 15.312 22.741 ;
     RECT  38.952 21.731 40.032 22.259 ;
     RECT  4.344 21.733 5.472 27.251 ;
     RECT  35.688 21.827 37.008 22.883 ;
     RECT  27.768 22.165 28.8 22.451 ;
     RECT  38.952 22.259 40.08 22.451 ;
     RECT  38.568 22.451 40.08 67.813 ;
     RECT  40.512 22.499 41.664 65.269 ;
     RECT  14.28 22.741 15.312 23.507 ;
     RECT  35.544 22.883 37.008 23.411 ;
     RECT  6.072 22.979 7.8 24.469 ;
     RECT  46.008 23.315 46.992 68.101 ;
     RECT  14.136 23.507 15.312 23.605 ;
     RECT  14.136 23.605 15.12 24.517 ;
     RECT  84.168 23.699 85.344 69.299 ;
     RECT  6.504 24.469 7.8 25.715 ;
     RECT  14.136 25.619 15.12 27.301 ;
     RECT  4.344 27.251 5.712 32.869 ;
     RECT  14.136 28.307 15.12 29.749 ;
     RECT  10.872 28.933 12.288 30.277 ;
     RECT  9.192 29.749 10.272 31.427 ;
     RECT  10.296 30.323 11.712 31.427 ;
     RECT  9.192 31.427 11.712 32.533 ;
     RECT  0.144 31.619 0.168 32.629 ;
     RECT  6.264 32.389 7.632 34.741 ;
     RECT  9.192 32.533 10.416 32.965 ;
     RECT  10.44 32.533 11.712 32.629 ;
     RECT  4.536 32.869 5.712 33.683 ;
     RECT  14.136 33.107 15.12 35.509 ;
     RECT  4.344 33.683 5.712 36.757 ;
     RECT  9.192 34.403 10.176 35.749 ;
     RECT  6.264 34.741 7.536 35.845 ;
     RECT  14.136 39.731 15.168 41.075 ;
     RECT  5.664 39.923 5.712 40.885 ;
     RECT  14.136 41.075 15.312 41.939 ;
     RECT  14.088 41.939 15.312 43.379 ;
     RECT  5.112 43.379 6.192 43.955 ;
     RECT  5.16 46.597 6.192 46.787 ;
     RECT  2.808 47.173 4.176 47.939 ;
     RECT  14.136 48.229 15.312 49.619 ;
     RECT  5.112 54.181 6.192 55.427 ;
     RECT  27.384 64.933 28.8 65.939 ;
     RECT  92.04 65.267 93.168 66.419 ;
     RECT  51.312 65.363 52.464 65.939 ;
     RECT  197.112 65.555 198.576 65.603 ;
     RECT  87.528 65.699 88.8 66.275 ;
     RECT  79.08 65.795 80.064 68.387 ;
     RECT  51.312 65.939 52.704 66.035 ;
     RECT  35.592 65.941 37.008 71.411 ;
     RECT  51.312 66.035 52.752 66.179 ;
     RECT  51.312 66.179 51.432 67.525 ;
     RECT  87.48 66.275 88.8 71.603 ;
     RECT  96.6 66.803 98.016 69.059 ;
     RECT  41.064 66.899 42.432 67.283 ;
     RECT  48.84 67.091 49.824 68.051 ;
     RECT  44.184 67.283 45.264 70.597 ;
     RECT  56.712 67.379 58.128 68.675 ;
     RECT  81.432 67.523 82.56 68.051 ;
     RECT  30.216 67.619 30.264 68.965 ;
     RECT  65.016 67.715 66.096 68.339 ;
     RECT  38.712 67.813 40.08 68.099 ;
     RECT  37.032 68.051 38.16 70.309 ;
     RECT  48.504 68.051 49.824 68.291 ;
     RECT  38.568 68.099 40.08 72.467 ;
     RECT  76.008 68.243 77.088 70.739 ;
     RECT  33.576 68.245 34.8 70.021 ;
     RECT  47.208 68.291 48.336 70.067 ;
     RECT  48.456 68.291 49.824 70.211 ;
     RECT  64.92 68.339 66.096 68.915 ;
     RECT  90.408 68.435 90.648 69.733 ;
     RECT  63.816 68.579 64.896 68.915 ;
     RECT  66.12 68.627 67.2 70.691 ;
     RECT  40.512 68.675 40.728 69.781 ;
     RECT  56.712 68.675 58.464 68.917 ;
     RECT  100.008 68.771 101.136 70.307 ;
     RECT  69.816 68.915 71.04 70.549 ;
     RECT  57.048 68.917 58.464 69.491 ;
     RECT  85.608 69.251 86.976 71.315 ;
     RECT  84.072 69.299 85.344 69.779 ;
     RECT  54.504 69.347 55.536 70.309 ;
     RECT  60.696 69.443 61.68 69.683 ;
     RECT  56.712 69.491 58.464 69.827 ;
     RECT  10.68 69.539 11.712 72.419 ;
     RECT  52.488 69.587 53.808 69.875 ;
     RECT  60.696 69.683 61.8 72.275 ;
     RECT  59.544 69.779 60.672 71.459 ;
     RECT  84.072 69.779 85.584 71.939 ;
     RECT  40.632 69.781 42.144 70.787 ;
     RECT  56.712 69.827 58.56 70.019 ;
     RECT  56.712 70.019 58.704 70.549 ;
     RECT  47.208 70.067 48.432 70.211 ;
     RECT  47.208 70.211 47.304 71.125 ;
     RECT  68.76 70.307 69.792 70.595 ;
     RECT  37.08 70.309 38.16 70.451 ;
     RECT  37.032 70.451 38.16 70.787 ;
     RECT  8.664 70.499 9.648 72.179 ;
     RECT  57.384 70.549 58.704 71.123 ;
     RECT  69.912 70.549 71.04 70.691 ;
     RECT  68.76 70.595 69.888 70.691 ;
     RECT  45.912 70.691 46.992 71.653 ;
     RECT  76.008 70.739 77.184 74.915 ;
     RECT  37.032 70.787 38.544 71.411 ;
     RECT  19.08 70.835 20.064 71.797 ;
     RECT  75 70.883 75.984 70.931 ;
     RECT  62.52 71.219 63.792 72.803 ;
     RECT  71.544 71.363 72.6 71.987 ;
     RECT  59.256 71.459 60.672 72.275 ;
     RECT  40.512 71.555 40.632 72.517 ;
     RECT  87.792 71.603 88.8 72.181 ;
     RECT  17.064 72.035 18.096 72.515 ;
     RECT  8.424 72.179 9.648 74.195 ;
     RECT  87.816 72.181 88.8 73.091 ;
     RECT  19.032 72.227 20.064 74.675 ;
     RECT  10.392 72.419 11.712 74.387 ;
     RECT  38.784 72.467 40.08 73.091 ;
     RECT  17.064 72.515 18.432 73.859 ;
     RECT  49.944 72.611 51 72.947 ;
     RECT  62.328 72.803 63.792 73.571 ;
     RECT  49.608 72.947 51 74.483 ;
     RECT  43.032 72.995 44.16 73.859 ;
     RECT  13.656 72.997 14.832 73.283 ;
     RECT  38.784 73.091 40.2 73.237 ;
     RECT  44.184 73.187 45.264 74.051 ;
     RECT  38.808 73.237 40.2 73.475 ;
     RECT  46.008 73.283 47.28 73.331 ;
     RECT  45.912 73.331 47.28 74.435 ;
     RECT  22.2 73.379 23.52 73.619 ;
     RECT  21.096 73.571 22.176 73.619 ;
     RECT  72.912 73.619 74.352 74.723 ;
     RECT  18.912 74.675 20.064 75.155 ;
  END
END ot_hgi_b2_dma_land_dp
END LIBRARY
